VERSION 5.8 ;
BUSBITCHARS "[]" ;
DIVIDERCHAR "/" ;
UNITS
    DATABASE MICRONS 1000 ;
END UNITS

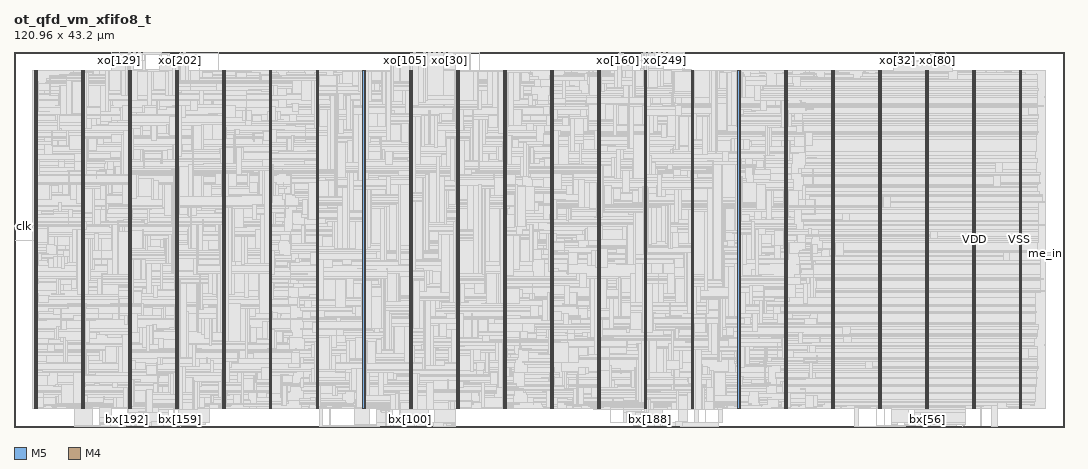
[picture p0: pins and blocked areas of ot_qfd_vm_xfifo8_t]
MACRO ot_qfd_vm_xfifo8_t
  FOREIGN ot_qfd_vm_xfifo8_t 0 0 ;
  CLASS BLOCK ;
  SIZE 120.96 BY 43.2 ;
  PIN bx[0]
    DIRECTION INPUT ;
    USE SIGNAL ;
    PORT
      LAYER M5 ;
        RECT  42.192 0 42.216 0.084 ;
    END
  END bx[0]
  PIN bx[100]
    DIRECTION INPUT ;
    USE SIGNAL ;
    PORT
      LAYER M5 ;
        RECT  45.648 0 45.672 0.084 ;
    END
  END bx[100]
  PIN bx[101]
    DIRECTION INPUT ;
    USE SIGNAL ;
    PORT
      LAYER M5 ;
        RECT  45.744 0 45.768 0.084 ;
    END
  END bx[101]
  PIN bx[102]
    DIRECTION INPUT ;
    USE SIGNAL ;
    PORT
      LAYER M5 ;
        RECT  45.84 0 45.864 0.084 ;
    END
  END bx[102]
  PIN bx[103]
    DIRECTION INPUT ;
    USE SIGNAL ;
    PORT
      LAYER M5 ;
        RECT  45.936 0 45.96 0.084 ;
    END
  END bx[103]
  PIN bx[104]
    DIRECTION INPUT ;
    USE SIGNAL ;
    PORT
      LAYER M5 ;
        RECT  46.032 0 46.056 0.084 ;
    END
  END bx[104]
  PIN bx[105]
    DIRECTION INPUT ;
    USE SIGNAL ;
    PORT
      LAYER M5 ;
        RECT  46.128 0 46.152 0.084 ;
    END
  END bx[105]
  PIN bx[106]
    DIRECTION INPUT ;
    USE SIGNAL ;
    PORT
      LAYER M5 ;
        RECT  46.224 0 46.248 0.084 ;
    END
  END bx[106]
  PIN bx[107]
    DIRECTION INPUT ;
    USE SIGNAL ;
    PORT
      LAYER M5 ;
        RECT  46.32 0 46.344 0.084 ;
    END
  END bx[107]
  PIN bx[108]
    DIRECTION INPUT ;
    USE SIGNAL ;
    PORT
      LAYER M5 ;
        RECT  46.416 0 46.44 0.084 ;
    END
  END bx[108]
  PIN bx[109]
    DIRECTION INPUT ;
    USE SIGNAL ;
    PORT
      LAYER M5 ;
        RECT  46.512 0 46.536 0.084 ;
    END
  END bx[109]
  PIN bx[10]
    DIRECTION INPUT ;
    USE SIGNAL ;
    PORT
      LAYER M5 ;
        RECT  43.152 0 43.176 0.084 ;
    END
  END bx[10]
  PIN bx[110]
    DIRECTION INPUT ;
    USE SIGNAL ;
    PORT
      LAYER M5 ;
        RECT  46.608 0 46.632 0.084 ;
    END
  END bx[110]
  PIN bx[111]
    DIRECTION INPUT ;
    USE SIGNAL ;
    PORT
      LAYER M5 ;
        RECT  46.704 0 46.728 0.084 ;
    END
  END bx[111]
  PIN bx[112]
    DIRECTION INPUT ;
    USE SIGNAL ;
    PORT
      LAYER M5 ;
        RECT  46.8 0 46.824 0.084 ;
    END
  END bx[112]
  PIN bx[113]
    DIRECTION INPUT ;
    USE SIGNAL ;
    PORT
      LAYER M5 ;
        RECT  46.896 0 46.92 0.084 ;
    END
  END bx[113]
  PIN bx[114]
    DIRECTION INPUT ;
    USE SIGNAL ;
    PORT
      LAYER M5 ;
        RECT  46.992 0 47.016 0.084 ;
    END
  END bx[114]
  PIN bx[115]
    DIRECTION INPUT ;
    USE SIGNAL ;
    PORT
      LAYER M5 ;
        RECT  47.088 0 47.112 0.084 ;
    END
  END bx[115]
  PIN bx[116]
    DIRECTION INPUT ;
    USE SIGNAL ;
    PORT
      LAYER M5 ;
        RECT  47.184 0 47.208 0.084 ;
    END
  END bx[116]
  PIN bx[117]
    DIRECTION INPUT ;
    USE SIGNAL ;
    PORT
      LAYER M5 ;
        RECT  47.28 0 47.304 0.084 ;
    END
  END bx[117]
  PIN bx[118]
    DIRECTION INPUT ;
    USE SIGNAL ;
    PORT
      LAYER M5 ;
        RECT  47.376 0 47.4 0.084 ;
    END
  END bx[118]
  PIN bx[119]
    DIRECTION INPUT ;
    USE SIGNAL ;
    PORT
      LAYER M5 ;
        RECT  47.472 0 47.496 0.084 ;
    END
  END bx[119]
  PIN bx[11]
    DIRECTION INPUT ;
    USE SIGNAL ;
    PORT
      LAYER M5 ;
        RECT  43.248 0 43.272 0.084 ;
    END
  END bx[11]
  PIN bx[120]
    DIRECTION INPUT ;
    USE SIGNAL ;
    PORT
      LAYER M5 ;
        RECT  47.568 0 47.592 0.084 ;
    END
  END bx[120]
  PIN bx[121]
    DIRECTION INPUT ;
    USE SIGNAL ;
    PORT
      LAYER M5 ;
        RECT  47.664 0 47.688 0.084 ;
    END
  END bx[121]
  PIN bx[122]
    DIRECTION INPUT ;
    USE SIGNAL ;
    PORT
      LAYER M5 ;
        RECT  47.76 0 47.784 0.084 ;
    END
  END bx[122]
  PIN bx[123]
    DIRECTION INPUT ;
    USE SIGNAL ;
    PORT
      LAYER M5 ;
        RECT  47.856 0 47.88 0.084 ;
    END
  END bx[123]
  PIN bx[124]
    DIRECTION INPUT ;
    USE SIGNAL ;
    PORT
      LAYER M5 ;
        RECT  47.952 0 47.976 0.084 ;
    END
  END bx[124]
  PIN bx[125]
    DIRECTION INPUT ;
    USE SIGNAL ;
    PORT
      LAYER M5 ;
        RECT  48.048 0 48.072 0.084 ;
    END
  END bx[125]
  PIN bx[126]
    DIRECTION INPUT ;
    USE SIGNAL ;
    PORT
      LAYER M5 ;
        RECT  48.144 0 48.168 0.084 ;
    END
  END bx[126]
  PIN bx[127]
    DIRECTION INPUT ;
    USE SIGNAL ;
    PORT
      LAYER M5 ;
        RECT  48.24 0 48.264 0.084 ;
    END
  END bx[127]
  PIN bx[128]
    DIRECTION INPUT ;
    USE SIGNAL ;
    PORT
      LAYER M5 ;
        RECT  16.08 0 16.104 0.084 ;
    END
  END bx[128]
  PIN bx[129]
    DIRECTION INPUT ;
    USE SIGNAL ;
    PORT
      LAYER M5 ;
        RECT  16.176 0 16.2 0.084 ;
    END
  END bx[129]
  PIN bx[12]
    DIRECTION INPUT ;
    USE SIGNAL ;
    PORT
      LAYER M5 ;
        RECT  43.344 0 43.368 0.084 ;
    END
  END bx[12]
  PIN bx[130]
    DIRECTION INPUT ;
    USE SIGNAL ;
    PORT
      LAYER M5 ;
        RECT  16.272 0 16.296 0.084 ;
    END
  END bx[130]
  PIN bx[131]
    DIRECTION INPUT ;
    USE SIGNAL ;
    PORT
      LAYER M5 ;
        RECT  16.368 0 16.392 0.084 ;
    END
  END bx[131]
  PIN bx[132]
    DIRECTION INPUT ;
    USE SIGNAL ;
    PORT
      LAYER M5 ;
        RECT  16.464 0 16.488 0.084 ;
    END
  END bx[132]
  PIN bx[133]
    DIRECTION INPUT ;
    USE SIGNAL ;
    PORT
      LAYER M5 ;
        RECT  16.56 0 16.584 0.084 ;
    END
  END bx[133]
  PIN bx[134]
    DIRECTION INPUT ;
    USE SIGNAL ;
    PORT
      LAYER M5 ;
        RECT  16.656 0 16.68 0.084 ;
    END
  END bx[134]
  PIN bx[135]
    DIRECTION INPUT ;
    USE SIGNAL ;
    PORT
      LAYER M5 ;
        RECT  16.752 0 16.776 0.084 ;
    END
  END bx[135]
  PIN bx[136]
    DIRECTION INPUT ;
    USE SIGNAL ;
    PORT
      LAYER M5 ;
        RECT  16.848 0 16.872 0.084 ;
    END
  END bx[136]
  PIN bx[137]
    DIRECTION INPUT ;
    USE SIGNAL ;
    PORT
      LAYER M5 ;
        RECT  16.944 0 16.968 0.084 ;
    END
  END bx[137]
  PIN bx[138]
    DIRECTION INPUT ;
    USE SIGNAL ;
    PORT
      LAYER M5 ;
        RECT  17.04 0 17.064 0.084 ;
    END
  END bx[138]
  PIN bx[139]
    DIRECTION INPUT ;
    USE SIGNAL ;
    PORT
      LAYER M5 ;
        RECT  17.136 0 17.16 0.084 ;
    END
  END bx[139]
  PIN bx[13]
    DIRECTION INPUT ;
    USE SIGNAL ;
    PORT
      LAYER M5 ;
        RECT  43.44 0 43.464 0.084 ;
    END
  END bx[13]
  PIN bx[140]
    DIRECTION INPUT ;
    USE SIGNAL ;
    PORT
      LAYER M5 ;
        RECT  17.232 0 17.256 0.084 ;
    END
  END bx[140]
  PIN bx[141]
    DIRECTION INPUT ;
    USE SIGNAL ;
    PORT
      LAYER M5 ;
        RECT  17.328 0 17.352 0.084 ;
    END
  END bx[141]
  PIN bx[142]
    DIRECTION INPUT ;
    USE SIGNAL ;
    PORT
      LAYER M5 ;
        RECT  17.424 0 17.448 0.084 ;
    END
  END bx[142]
  PIN bx[143]
    DIRECTION INPUT ;
    USE SIGNAL ;
    PORT
      LAYER M5 ;
        RECT  17.52 0 17.544 0.084 ;
    END
  END bx[143]
  PIN bx[144]
    DIRECTION INPUT ;
    USE SIGNAL ;
    PORT
      LAYER M5 ;
        RECT  17.616 0 17.64 0.084 ;
    END
  END bx[144]
  PIN bx[145]
    DIRECTION INPUT ;
    USE SIGNAL ;
    PORT
      LAYER M5 ;
        RECT  17.712 0 17.736 0.084 ;
    END
  END bx[145]
  PIN bx[146]
    DIRECTION INPUT ;
    USE SIGNAL ;
    PORT
      LAYER M5 ;
        RECT  17.808 0 17.832 0.084 ;
    END
  END bx[146]
  PIN bx[147]
    DIRECTION INPUT ;
    USE SIGNAL ;
    PORT
      LAYER M5 ;
        RECT  17.904 0 17.928 0.084 ;
    END
  END bx[147]
  PIN bx[148]
    DIRECTION INPUT ;
    USE SIGNAL ;
    PORT
      LAYER M5 ;
        RECT  18 0 18.024 0.084 ;
    END
  END bx[148]
  PIN bx[149]
    DIRECTION INPUT ;
    USE SIGNAL ;
    PORT
      LAYER M5 ;
        RECT  18.096 0 18.12 0.084 ;
    END
  END bx[149]
  PIN bx[14]
    DIRECTION INPUT ;
    USE SIGNAL ;
    PORT
      LAYER M5 ;
        RECT  43.536 0 43.56 0.084 ;
    END
  END bx[14]
  PIN bx[150]
    DIRECTION INPUT ;
    USE SIGNAL ;
    PORT
      LAYER M5 ;
        RECT  18.192 0 18.216 0.084 ;
    END
  END bx[150]
  PIN bx[151]
    DIRECTION INPUT ;
    USE SIGNAL ;
    PORT
      LAYER M5 ;
        RECT  18.288 0 18.312 0.084 ;
    END
  END bx[151]
  PIN bx[152]
    DIRECTION INPUT ;
    USE SIGNAL ;
    PORT
      LAYER M5 ;
        RECT  18.384 0 18.408 0.084 ;
    END
  END bx[152]
  PIN bx[153]
    DIRECTION INPUT ;
    USE SIGNAL ;
    PORT
      LAYER M5 ;
        RECT  18.48 0 18.504 0.084 ;
    END
  END bx[153]
  PIN bx[154]
    DIRECTION INPUT ;
    USE SIGNAL ;
    PORT
      LAYER M5 ;
        RECT  18.576 0 18.6 0.084 ;
    END
  END bx[154]
  PIN bx[155]
    DIRECTION INPUT ;
    USE SIGNAL ;
    PORT
      LAYER M5 ;
        RECT  18.672 0 18.696 0.084 ;
    END
  END bx[155]
  PIN bx[156]
    DIRECTION INPUT ;
    USE SIGNAL ;
    PORT
      LAYER M5 ;
        RECT  18.768 0 18.792 0.084 ;
    END
  END bx[156]
  PIN bx[157]
    DIRECTION INPUT ;
    USE SIGNAL ;
    PORT
      LAYER M5 ;
        RECT  18.864 0 18.888 0.084 ;
    END
  END bx[157]
  PIN bx[158]
    DIRECTION INPUT ;
    USE SIGNAL ;
    PORT
      LAYER M5 ;
        RECT  18.96 0 18.984 0.084 ;
    END
  END bx[158]
  PIN bx[159]
    DIRECTION INPUT ;
    USE SIGNAL ;
    PORT
      LAYER M5 ;
        RECT  19.056 0 19.08 0.084 ;
    END
  END bx[159]
  PIN bx[15]
    DIRECTION INPUT ;
    USE SIGNAL ;
    PORT
      LAYER M5 ;
        RECT  43.632 0 43.656 0.084 ;
    END
  END bx[15]
  PIN bx[160]
    DIRECTION INPUT ;
    USE SIGNAL ;
    PORT
      LAYER M5 ;
        RECT  70.608 0 70.632 0.084 ;
    END
  END bx[160]
  PIN bx[161]
    DIRECTION INPUT ;
    USE SIGNAL ;
    PORT
      LAYER M5 ;
        RECT  70.704 0 70.728 0.084 ;
    END
  END bx[161]
  PIN bx[162]
    DIRECTION INPUT ;
    USE SIGNAL ;
    PORT
      LAYER M5 ;
        RECT  70.8 0 70.824 0.084 ;
    END
  END bx[162]
  PIN bx[163]
    DIRECTION INPUT ;
    USE SIGNAL ;
    PORT
      LAYER M5 ;
        RECT  70.896 0 70.92 0.084 ;
    END
  END bx[163]
  PIN bx[164]
    DIRECTION INPUT ;
    USE SIGNAL ;
    PORT
      LAYER M5 ;
        RECT  70.992 0 71.016 0.084 ;
    END
  END bx[164]
  PIN bx[165]
    DIRECTION INPUT ;
    USE SIGNAL ;
    PORT
      LAYER M5 ;
        RECT  71.088 0 71.112 0.084 ;
    END
  END bx[165]
  PIN bx[166]
    DIRECTION INPUT ;
    USE SIGNAL ;
    PORT
      LAYER M5 ;
        RECT  71.184 0 71.208 0.084 ;
    END
  END bx[166]
  PIN bx[167]
    DIRECTION INPUT ;
    USE SIGNAL ;
    PORT
      LAYER M5 ;
        RECT  71.28 0 71.304 0.084 ;
    END
  END bx[167]
  PIN bx[168]
    DIRECTION INPUT ;
    USE SIGNAL ;
    PORT
      LAYER M5 ;
        RECT  71.376 0 71.4 0.084 ;
    END
  END bx[168]
  PIN bx[169]
    DIRECTION INPUT ;
    USE SIGNAL ;
    PORT
      LAYER M5 ;
        RECT  71.472 0 71.496 0.084 ;
    END
  END bx[169]
  PIN bx[16]
    DIRECTION INPUT ;
    USE SIGNAL ;
    PORT
      LAYER M5 ;
        RECT  43.728 0 43.752 0.084 ;
    END
  END bx[16]
  PIN bx[170]
    DIRECTION INPUT ;
    USE SIGNAL ;
    PORT
      LAYER M5 ;
        RECT  71.568 0 71.592 0.084 ;
    END
  END bx[170]
  PIN bx[171]
    DIRECTION INPUT ;
    USE SIGNAL ;
    PORT
      LAYER M5 ;
        RECT  71.664 0 71.688 0.084 ;
    END
  END bx[171]
  PIN bx[172]
    DIRECTION INPUT ;
    USE SIGNAL ;
    PORT
      LAYER M5 ;
        RECT  71.76 0 71.784 0.084 ;
    END
  END bx[172]
  PIN bx[173]
    DIRECTION INPUT ;
    USE SIGNAL ;
    PORT
      LAYER M5 ;
        RECT  71.856 0 71.88 0.084 ;
    END
  END bx[173]
  PIN bx[174]
    DIRECTION INPUT ;
    USE SIGNAL ;
    PORT
      LAYER M5 ;
        RECT  71.952 0 71.976 0.084 ;
    END
  END bx[174]
  PIN bx[175]
    DIRECTION INPUT ;
    USE SIGNAL ;
    PORT
      LAYER M5 ;
        RECT  72.048 0 72.072 0.084 ;
    END
  END bx[175]
  PIN bx[176]
    DIRECTION INPUT ;
    USE SIGNAL ;
    PORT
      LAYER M5 ;
        RECT  72.144 0 72.168 0.084 ;
    END
  END bx[176]
  PIN bx[177]
    DIRECTION INPUT ;
    USE SIGNAL ;
    PORT
      LAYER M5 ;
        RECT  72.24 0 72.264 0.084 ;
    END
  END bx[177]
  PIN bx[178]
    DIRECTION INPUT ;
    USE SIGNAL ;
    PORT
      LAYER M5 ;
        RECT  72.336 0 72.36 0.084 ;
    END
  END bx[178]
  PIN bx[179]
    DIRECTION INPUT ;
    USE SIGNAL ;
    PORT
      LAYER M5 ;
        RECT  72.432 0 72.456 0.084 ;
    END
  END bx[179]
  PIN bx[17]
    DIRECTION INPUT ;
    USE SIGNAL ;
    PORT
      LAYER M5 ;
        RECT  43.824 0 43.848 0.084 ;
    END
  END bx[17]
  PIN bx[180]
    DIRECTION INPUT ;
    USE SIGNAL ;
    PORT
      LAYER M5 ;
        RECT  72.528 0 72.552 0.084 ;
    END
  END bx[180]
  PIN bx[181]
    DIRECTION INPUT ;
    USE SIGNAL ;
    PORT
      LAYER M5 ;
        RECT  72.624 0 72.648 0.084 ;
    END
  END bx[181]
  PIN bx[182]
    DIRECTION INPUT ;
    USE SIGNAL ;
    PORT
      LAYER M5 ;
        RECT  72.72 0 72.744 0.084 ;
    END
  END bx[182]
  PIN bx[183]
    DIRECTION INPUT ;
    USE SIGNAL ;
    PORT
      LAYER M5 ;
        RECT  72.816 0 72.84 0.084 ;
    END
  END bx[183]
  PIN bx[184]
    DIRECTION INPUT ;
    USE SIGNAL ;
    PORT
      LAYER M5 ;
        RECT  72.912 0 72.936 0.084 ;
    END
  END bx[184]
  PIN bx[185]
    DIRECTION INPUT ;
    USE SIGNAL ;
    PORT
      LAYER M5 ;
        RECT  73.008 0 73.032 0.084 ;
    END
  END bx[185]
  PIN bx[186]
    DIRECTION INPUT ;
    USE SIGNAL ;
    PORT
      LAYER M5 ;
        RECT  73.104 0 73.128 0.084 ;
    END
  END bx[186]
  PIN bx[187]
    DIRECTION INPUT ;
    USE SIGNAL ;
    PORT
      LAYER M5 ;
        RECT  73.2 0 73.224 0.084 ;
    END
  END bx[187]
  PIN bx[188]
    DIRECTION INPUT ;
    USE SIGNAL ;
    PORT
      LAYER M5 ;
        RECT  73.296 0 73.32 0.084 ;
    END
  END bx[188]
  PIN bx[189]
    DIRECTION INPUT ;
    USE SIGNAL ;
    PORT
      LAYER M5 ;
        RECT  73.392 0 73.416 0.084 ;
    END
  END bx[189]
  PIN bx[18]
    DIRECTION INPUT ;
    USE SIGNAL ;
    PORT
      LAYER M5 ;
        RECT  43.92 0 43.944 0.084 ;
    END
  END bx[18]
  PIN bx[190]
    DIRECTION INPUT ;
    USE SIGNAL ;
    PORT
      LAYER M5 ;
        RECT  73.488 0 73.512 0.084 ;
    END
  END bx[190]
  PIN bx[191]
    DIRECTION INPUT ;
    USE SIGNAL ;
    PORT
      LAYER M5 ;
        RECT  73.584 0 73.608 0.084 ;
    END
  END bx[191]
  PIN bx[192]
    DIRECTION INPUT ;
    USE SIGNAL ;
    PORT
      LAYER M5 ;
        RECT  13.008 0 13.032 0.084 ;
    END
  END bx[192]
  PIN bx[193]
    DIRECTION INPUT ;
    USE SIGNAL ;
    PORT
      LAYER M5 ;
        RECT  13.104 0 13.128 0.084 ;
    END
  END bx[193]
  PIN bx[194]
    DIRECTION INPUT ;
    USE SIGNAL ;
    PORT
      LAYER M5 ;
        RECT  13.2 0 13.224 0.084 ;
    END
  END bx[194]
  PIN bx[195]
    DIRECTION INPUT ;
    USE SIGNAL ;
    PORT
      LAYER M5 ;
        RECT  13.296 0 13.32 0.084 ;
    END
  END bx[195]
  PIN bx[196]
    DIRECTION INPUT ;
    USE SIGNAL ;
    PORT
      LAYER M5 ;
        RECT  13.392 0 13.416 0.084 ;
    END
  END bx[196]
  PIN bx[197]
    DIRECTION INPUT ;
    USE SIGNAL ;
    PORT
      LAYER M5 ;
        RECT  13.488 0 13.512 0.084 ;
    END
  END bx[197]
  PIN bx[198]
    DIRECTION INPUT ;
    USE SIGNAL ;
    PORT
      LAYER M5 ;
        RECT  13.584 0 13.608 0.084 ;
    END
  END bx[198]
  PIN bx[199]
    DIRECTION INPUT ;
    USE SIGNAL ;
    PORT
      LAYER M5 ;
        RECT  13.68 0 13.704 0.084 ;
    END
  END bx[199]
  PIN bx[19]
    DIRECTION INPUT ;
    USE SIGNAL ;
    PORT
      LAYER M5 ;
        RECT  44.016 0 44.04 0.084 ;
    END
  END bx[19]
  PIN bx[1]
    DIRECTION INPUT ;
    USE SIGNAL ;
    PORT
      LAYER M5 ;
        RECT  42.288 0 42.312 0.084 ;
    END
  END bx[1]
  PIN bx[200]
    DIRECTION INPUT ;
    USE SIGNAL ;
    PORT
      LAYER M5 ;
        RECT  13.776 0 13.8 0.084 ;
    END
  END bx[200]
  PIN bx[201]
    DIRECTION INPUT ;
    USE SIGNAL ;
    PORT
      LAYER M5 ;
        RECT  13.872 0 13.896 0.084 ;
    END
  END bx[201]
  PIN bx[202]
    DIRECTION INPUT ;
    USE SIGNAL ;
    PORT
      LAYER M5 ;
        RECT  13.968 0 13.992 0.084 ;
    END
  END bx[202]
  PIN bx[203]
    DIRECTION INPUT ;
    USE SIGNAL ;
    PORT
      LAYER M5 ;
        RECT  14.064 0 14.088 0.084 ;
    END
  END bx[203]
  PIN bx[204]
    DIRECTION INPUT ;
    USE SIGNAL ;
    PORT
      LAYER M5 ;
        RECT  14.16 0 14.184 0.084 ;
    END
  END bx[204]
  PIN bx[205]
    DIRECTION INPUT ;
    USE SIGNAL ;
    PORT
      LAYER M5 ;
        RECT  14.256 0 14.28 0.084 ;
    END
  END bx[205]
  PIN bx[206]
    DIRECTION INPUT ;
    USE SIGNAL ;
    PORT
      LAYER M5 ;
        RECT  14.352 0 14.376 0.084 ;
    END
  END bx[206]
  PIN bx[207]
    DIRECTION INPUT ;
    USE SIGNAL ;
    PORT
      LAYER M5 ;
        RECT  14.448 0 14.472 0.084 ;
    END
  END bx[207]
  PIN bx[208]
    DIRECTION INPUT ;
    USE SIGNAL ;
    PORT
      LAYER M5 ;
        RECT  14.544 0 14.568 0.084 ;
    END
  END bx[208]
  PIN bx[209]
    DIRECTION INPUT ;
    USE SIGNAL ;
    PORT
      LAYER M5 ;
        RECT  14.64 0 14.664 0.084 ;
    END
  END bx[209]
  PIN bx[20]
    DIRECTION INPUT ;
    USE SIGNAL ;
    PORT
      LAYER M5 ;
        RECT  44.112 0 44.136 0.084 ;
    END
  END bx[20]
  PIN bx[210]
    DIRECTION INPUT ;
    USE SIGNAL ;
    PORT
      LAYER M5 ;
        RECT  14.736 0 14.76 0.084 ;
    END
  END bx[210]
  PIN bx[211]
    DIRECTION INPUT ;
    USE SIGNAL ;
    PORT
      LAYER M5 ;
        RECT  14.832 0 14.856 0.084 ;
    END
  END bx[211]
  PIN bx[212]
    DIRECTION INPUT ;
    USE SIGNAL ;
    PORT
      LAYER M5 ;
        RECT  14.928 0 14.952 0.084 ;
    END
  END bx[212]
  PIN bx[213]
    DIRECTION INPUT ;
    USE SIGNAL ;
    PORT
      LAYER M5 ;
        RECT  15.024 0 15.048 0.084 ;
    END
  END bx[213]
  PIN bx[214]
    DIRECTION INPUT ;
    USE SIGNAL ;
    PORT
      LAYER M5 ;
        RECT  15.12 0 15.144 0.084 ;
    END
  END bx[214]
  PIN bx[215]
    DIRECTION INPUT ;
    USE SIGNAL ;
    PORT
      LAYER M5 ;
        RECT  15.216 0 15.24 0.084 ;
    END
  END bx[215]
  PIN bx[216]
    DIRECTION INPUT ;
    USE SIGNAL ;
    PORT
      LAYER M5 ;
        RECT  15.312 0 15.336 0.084 ;
    END
  END bx[216]
  PIN bx[217]
    DIRECTION INPUT ;
    USE SIGNAL ;
    PORT
      LAYER M5 ;
        RECT  15.408 0 15.432 0.084 ;
    END
  END bx[217]
  PIN bx[218]
    DIRECTION INPUT ;
    USE SIGNAL ;
    PORT
      LAYER M5 ;
        RECT  15.504 0 15.528 0.084 ;
    END
  END bx[218]
  PIN bx[219]
    DIRECTION INPUT ;
    USE SIGNAL ;
    PORT
      LAYER M5 ;
        RECT  15.6 0 15.624 0.084 ;
    END
  END bx[219]
  PIN bx[21]
    DIRECTION INPUT ;
    USE SIGNAL ;
    PORT
      LAYER M5 ;
        RECT  44.208 0 44.232 0.084 ;
    END
  END bx[21]
  PIN bx[220]
    DIRECTION INPUT ;
    USE SIGNAL ;
    PORT
      LAYER M5 ;
        RECT  15.696 0 15.72 0.084 ;
    END
  END bx[220]
  PIN bx[221]
    DIRECTION INPUT ;
    USE SIGNAL ;
    PORT
      LAYER M5 ;
        RECT  15.792 0 15.816 0.084 ;
    END
  END bx[221]
  PIN bx[222]
    DIRECTION INPUT ;
    USE SIGNAL ;
    PORT
      LAYER M5 ;
        RECT  15.888 0 15.912 0.084 ;
    END
  END bx[222]
  PIN bx[223]
    DIRECTION INPUT ;
    USE SIGNAL ;
    PORT
      LAYER M5 ;
        RECT  15.984 0 16.008 0.084 ;
    END
  END bx[223]
  PIN bx[224]
    DIRECTION INPUT ;
    USE SIGNAL ;
    PORT
      LAYER M5 ;
        RECT  73.68 0 73.704 0.084 ;
    END
  END bx[224]
  PIN bx[225]
    DIRECTION INPUT ;
    USE SIGNAL ;
    PORT
      LAYER M5 ;
        RECT  73.776 0 73.8 0.084 ;
    END
  END bx[225]
  PIN bx[226]
    DIRECTION INPUT ;
    USE SIGNAL ;
    PORT
      LAYER M5 ;
        RECT  73.872 0 73.896 0.084 ;
    END
  END bx[226]
  PIN bx[227]
    DIRECTION INPUT ;
    USE SIGNAL ;
    PORT
      LAYER M5 ;
        RECT  73.968 0 73.992 0.084 ;
    END
  END bx[227]
  PIN bx[228]
    DIRECTION INPUT ;
    USE SIGNAL ;
    PORT
      LAYER M5 ;
        RECT  74.064 0 74.088 0.084 ;
    END
  END bx[228]
  PIN bx[229]
    DIRECTION INPUT ;
    USE SIGNAL ;
    PORT
      LAYER M5 ;
        RECT  74.16 0 74.184 0.084 ;
    END
  END bx[229]
  PIN bx[22]
    DIRECTION INPUT ;
    USE SIGNAL ;
    PORT
      LAYER M5 ;
        RECT  44.304 0 44.328 0.084 ;
    END
  END bx[22]
  PIN bx[230]
    DIRECTION INPUT ;
    USE SIGNAL ;
    PORT
      LAYER M5 ;
        RECT  74.256 0 74.28 0.084 ;
    END
  END bx[230]
  PIN bx[231]
    DIRECTION INPUT ;
    USE SIGNAL ;
    PORT
      LAYER M5 ;
        RECT  74.352 0 74.376 0.084 ;
    END
  END bx[231]
  PIN bx[232]
    DIRECTION INPUT ;
    USE SIGNAL ;
    PORT
      LAYER M5 ;
        RECT  74.448 0 74.472 0.084 ;
    END
  END bx[232]
  PIN bx[233]
    DIRECTION INPUT ;
    USE SIGNAL ;
    PORT
      LAYER M5 ;
        RECT  74.544 0 74.568 0.084 ;
    END
  END bx[233]
  PIN bx[234]
    DIRECTION INPUT ;
    USE SIGNAL ;
    PORT
      LAYER M5 ;
        RECT  74.64 0 74.664 0.084 ;
    END
  END bx[234]
  PIN bx[235]
    DIRECTION INPUT ;
    USE SIGNAL ;
    PORT
      LAYER M5 ;
        RECT  74.736 0 74.76 0.084 ;
    END
  END bx[235]
  PIN bx[236]
    DIRECTION INPUT ;
    USE SIGNAL ;
    PORT
      LAYER M5 ;
        RECT  74.832 0 74.856 0.084 ;
    END
  END bx[236]
  PIN bx[237]
    DIRECTION INPUT ;
    USE SIGNAL ;
    PORT
      LAYER M5 ;
        RECT  74.928 0 74.952 0.084 ;
    END
  END bx[237]
  PIN bx[238]
    DIRECTION INPUT ;
    USE SIGNAL ;
    PORT
      LAYER M5 ;
        RECT  75.024 0 75.048 0.084 ;
    END
  END bx[238]
  PIN bx[239]
    DIRECTION INPUT ;
    USE SIGNAL ;
    PORT
      LAYER M5 ;
        RECT  75.12 0 75.144 0.084 ;
    END
  END bx[239]
  PIN bx[23]
    DIRECTION INPUT ;
    USE SIGNAL ;
    PORT
      LAYER M5 ;
        RECT  44.4 0 44.424 0.084 ;
    END
  END bx[23]
  PIN bx[240]
    DIRECTION INPUT ;
    USE SIGNAL ;
    PORT
      LAYER M5 ;
        RECT  75.216 0 75.24 0.084 ;
    END
  END bx[240]
  PIN bx[241]
    DIRECTION INPUT ;
    USE SIGNAL ;
    PORT
      LAYER M5 ;
        RECT  75.312 0 75.336 0.084 ;
    END
  END bx[241]
  PIN bx[242]
    DIRECTION INPUT ;
    USE SIGNAL ;
    PORT
      LAYER M5 ;
        RECT  75.408 0 75.432 0.084 ;
    END
  END bx[242]
  PIN bx[243]
    DIRECTION INPUT ;
    USE SIGNAL ;
    PORT
      LAYER M5 ;
        RECT  75.504 0 75.528 0.084 ;
    END
  END bx[243]
  PIN bx[244]
    DIRECTION INPUT ;
    USE SIGNAL ;
    PORT
      LAYER M5 ;
        RECT  75.6 0 75.624 0.084 ;
    END
  END bx[244]
  PIN bx[245]
    DIRECTION INPUT ;
    USE SIGNAL ;
    PORT
      LAYER M5 ;
        RECT  75.696 0 75.72 0.084 ;
    END
  END bx[245]
  PIN bx[246]
    DIRECTION INPUT ;
    USE SIGNAL ;
    PORT
      LAYER M5 ;
        RECT  75.792 0 75.816 0.084 ;
    END
  END bx[246]
  PIN bx[247]
    DIRECTION INPUT ;
    USE SIGNAL ;
    PORT
      LAYER M5 ;
        RECT  75.888 0 75.912 0.084 ;
    END
  END bx[247]
  PIN bx[248]
    DIRECTION INPUT ;
    USE SIGNAL ;
    PORT
      LAYER M5 ;
        RECT  75.984 0 76.008 0.084 ;
    END
  END bx[248]
  PIN bx[249]
    DIRECTION INPUT ;
    USE SIGNAL ;
    PORT
      LAYER M5 ;
        RECT  76.08 0 76.104 0.084 ;
    END
  END bx[249]
  PIN bx[24]
    DIRECTION INPUT ;
    USE SIGNAL ;
    PORT
      LAYER M5 ;
        RECT  44.496 0 44.52 0.084 ;
    END
  END bx[24]
  PIN bx[250]
    DIRECTION INPUT ;
    USE SIGNAL ;
    PORT
      LAYER M5 ;
        RECT  76.176 0 76.2 0.084 ;
    END
  END bx[250]
  PIN bx[251]
    DIRECTION INPUT ;
    USE SIGNAL ;
    PORT
      LAYER M5 ;
        RECT  76.272 0 76.296 0.084 ;
    END
  END bx[251]
  PIN bx[252]
    DIRECTION INPUT ;
    USE SIGNAL ;
    PORT
      LAYER M5 ;
        RECT  76.368 0 76.392 0.084 ;
    END
  END bx[252]
  PIN bx[253]
    DIRECTION INPUT ;
    USE SIGNAL ;
    PORT
      LAYER M5 ;
        RECT  76.464 0 76.488 0.084 ;
    END
  END bx[253]
  PIN bx[254]
    DIRECTION INPUT ;
    USE SIGNAL ;
    PORT
      LAYER M5 ;
        RECT  76.56 0 76.584 0.084 ;
    END
  END bx[254]
  PIN bx[255]
    DIRECTION INPUT ;
    USE SIGNAL ;
    PORT
      LAYER M5 ;
        RECT  76.656 0 76.68 0.084 ;
    END
  END bx[255]
  PIN bx[25]
    DIRECTION INPUT ;
    USE SIGNAL ;
    PORT
      LAYER M5 ;
        RECT  44.592 0 44.616 0.084 ;
    END
  END bx[25]
  PIN bx[26]
    DIRECTION INPUT ;
    USE SIGNAL ;
    PORT
      LAYER M5 ;
        RECT  44.688 0 44.712 0.084 ;
    END
  END bx[26]
  PIN bx[27]
    DIRECTION INPUT ;
    USE SIGNAL ;
    PORT
      LAYER M5 ;
        RECT  44.784 0 44.808 0.084 ;
    END
  END bx[27]
  PIN bx[28]
    DIRECTION INPUT ;
    USE SIGNAL ;
    PORT
      LAYER M5 ;
        RECT  44.88 0 44.904 0.084 ;
    END
  END bx[28]
  PIN bx[29]
    DIRECTION INPUT ;
    USE SIGNAL ;
    PORT
      LAYER M5 ;
        RECT  44.976 0 45 0.084 ;
    END
  END bx[29]
  PIN bx[2]
    DIRECTION INPUT ;
    USE SIGNAL ;
    PORT
      LAYER M5 ;
        RECT  42.384 0 42.408 0.084 ;
    END
  END bx[2]
  PIN bx[30]
    DIRECTION INPUT ;
    USE SIGNAL ;
    PORT
      LAYER M5 ;
        RECT  45.072 0 45.096 0.084 ;
    END
  END bx[30]
  PIN bx[31]
    DIRECTION INPUT ;
    USE SIGNAL ;
    PORT
      LAYER M5 ;
        RECT  45.168 0 45.192 0.084 ;
    END
  END bx[31]
  PIN bx[32]
    DIRECTION INPUT ;
    USE SIGNAL ;
    PORT
      LAYER M5 ;
        RECT  102.864 0 102.888 0.084 ;
    END
  END bx[32]
  PIN bx[33]
    DIRECTION INPUT ;
    USE SIGNAL ;
    PORT
      LAYER M5 ;
        RECT  102.96 0 102.984 0.084 ;
    END
  END bx[33]
  PIN bx[34]
    DIRECTION INPUT ;
    USE SIGNAL ;
    PORT
      LAYER M5 ;
        RECT  103.056 0 103.08 0.084 ;
    END
  END bx[34]
  PIN bx[35]
    DIRECTION INPUT ;
    USE SIGNAL ;
    PORT
      LAYER M5 ;
        RECT  103.152 0 103.176 0.084 ;
    END
  END bx[35]
  PIN bx[36]
    DIRECTION INPUT ;
    USE SIGNAL ;
    PORT
      LAYER M5 ;
        RECT  103.248 0 103.272 0.084 ;
    END
  END bx[36]
  PIN bx[37]
    DIRECTION INPUT ;
    USE SIGNAL ;
    PORT
      LAYER M5 ;
        RECT  103.344 0 103.368 0.084 ;
    END
  END bx[37]
  PIN bx[38]
    DIRECTION INPUT ;
    USE SIGNAL ;
    PORT
      LAYER M5 ;
        RECT  103.44 0 103.464 0.084 ;
    END
  END bx[38]
  PIN bx[39]
    DIRECTION INPUT ;
    USE SIGNAL ;
    PORT
      LAYER M5 ;
        RECT  103.536 0 103.56 0.084 ;
    END
  END bx[39]
  PIN bx[3]
    DIRECTION INPUT ;
    USE SIGNAL ;
    PORT
      LAYER M5 ;
        RECT  42.48 0 42.504 0.084 ;
    END
  END bx[3]
  PIN bx[40]
    DIRECTION INPUT ;
    USE SIGNAL ;
    PORT
      LAYER M5 ;
        RECT  103.632 0 103.656 0.084 ;
    END
  END bx[40]
  PIN bx[41]
    DIRECTION INPUT ;
    USE SIGNAL ;
    PORT
      LAYER M5 ;
        RECT  103.728 0 103.752 0.084 ;
    END
  END bx[41]
  PIN bx[42]
    DIRECTION INPUT ;
    USE SIGNAL ;
    PORT
      LAYER M5 ;
        RECT  103.824 0 103.848 0.084 ;
    END
  END bx[42]
  PIN bx[43]
    DIRECTION INPUT ;
    USE SIGNAL ;
    PORT
      LAYER M5 ;
        RECT  103.92 0 103.944 0.084 ;
    END
  END bx[43]
  PIN bx[44]
    DIRECTION INPUT ;
    USE SIGNAL ;
    PORT
      LAYER M5 ;
        RECT  104.016 0 104.04 0.084 ;
    END
  END bx[44]
  PIN bx[45]
    DIRECTION INPUT ;
    USE SIGNAL ;
    PORT
      LAYER M5 ;
        RECT  104.112 0 104.136 0.084 ;
    END
  END bx[45]
  PIN bx[46]
    DIRECTION INPUT ;
    USE SIGNAL ;
    PORT
      LAYER M5 ;
        RECT  104.208 0 104.232 0.084 ;
    END
  END bx[46]
  PIN bx[47]
    DIRECTION INPUT ;
    USE SIGNAL ;
    PORT
      LAYER M5 ;
        RECT  104.304 0 104.328 0.084 ;
    END
  END bx[47]
  PIN bx[48]
    DIRECTION INPUT ;
    USE SIGNAL ;
    PORT
      LAYER M5 ;
        RECT  104.4 0 104.424 0.084 ;
    END
  END bx[48]
  PIN bx[49]
    DIRECTION INPUT ;
    USE SIGNAL ;
    PORT
      LAYER M5 ;
        RECT  104.496 0 104.52 0.084 ;
    END
  END bx[49]
  PIN bx[4]
    DIRECTION INPUT ;
    USE SIGNAL ;
    PORT
      LAYER M5 ;
        RECT  42.576 0 42.6 0.084 ;
    END
  END bx[4]
  PIN bx[50]
    DIRECTION INPUT ;
    USE SIGNAL ;
    PORT
      LAYER M5 ;
        RECT  104.592 0 104.616 0.084 ;
    END
  END bx[50]
  PIN bx[51]
    DIRECTION INPUT ;
    USE SIGNAL ;
    PORT
      LAYER M5 ;
        RECT  104.688 0 104.712 0.084 ;
    END
  END bx[51]
  PIN bx[52]
    DIRECTION INPUT ;
    USE SIGNAL ;
    PORT
      LAYER M5 ;
        RECT  104.784 0 104.808 0.084 ;
    END
  END bx[52]
  PIN bx[53]
    DIRECTION INPUT ;
    USE SIGNAL ;
    PORT
      LAYER M5 ;
        RECT  104.88 0 104.904 0.084 ;
    END
  END bx[53]
  PIN bx[54]
    DIRECTION INPUT ;
    USE SIGNAL ;
    PORT
      LAYER M5 ;
        RECT  104.976 0 105 0.084 ;
    END
  END bx[54]
  PIN bx[55]
    DIRECTION INPUT ;
    USE SIGNAL ;
    PORT
      LAYER M5 ;
        RECT  105.072 0 105.096 0.084 ;
    END
  END bx[55]
  PIN bx[56]
    DIRECTION INPUT ;
    USE SIGNAL ;
    PORT
      LAYER M5 ;
        RECT  105.168 0 105.192 0.084 ;
    END
  END bx[56]
  PIN bx[57]
    DIRECTION INPUT ;
    USE SIGNAL ;
    PORT
      LAYER M5 ;
        RECT  105.264 0 105.288 0.084 ;
    END
  END bx[57]
  PIN bx[58]
    DIRECTION INPUT ;
    USE SIGNAL ;
    PORT
      LAYER M5 ;
        RECT  105.36 0 105.384 0.084 ;
    END
  END bx[58]
  PIN bx[59]
    DIRECTION INPUT ;
    USE SIGNAL ;
    PORT
      LAYER M5 ;
        RECT  105.456 0 105.48 0.084 ;
    END
  END bx[59]
  PIN bx[5]
    DIRECTION INPUT ;
    USE SIGNAL ;
    PORT
      LAYER M5 ;
        RECT  42.672 0 42.696 0.084 ;
    END
  END bx[5]
  PIN bx[60]
    DIRECTION INPUT ;
    USE SIGNAL ;
    PORT
      LAYER M5 ;
        RECT  105.552 0 105.576 0.084 ;
    END
  END bx[60]
  PIN bx[61]
    DIRECTION INPUT ;
    USE SIGNAL ;
    PORT
      LAYER M5 ;
        RECT  105.648 0 105.672 0.084 ;
    END
  END bx[61]
  PIN bx[62]
    DIRECTION INPUT ;
    USE SIGNAL ;
    PORT
      LAYER M5 ;
        RECT  105.744 0 105.768 0.084 ;
    END
  END bx[62]
  PIN bx[63]
    DIRECTION INPUT ;
    USE SIGNAL ;
    PORT
      LAYER M5 ;
        RECT  105.84 0 105.864 0.084 ;
    END
  END bx[63]
  PIN bx[64]
    DIRECTION INPUT ;
    USE SIGNAL ;
    PORT
      LAYER M5 ;
        RECT  105.936 0 105.96 0.084 ;
    END
  END bx[64]
  PIN bx[65]
    DIRECTION INPUT ;
    USE SIGNAL ;
    PORT
      LAYER M5 ;
        RECT  106.032 0 106.056 0.084 ;
    END
  END bx[65]
  PIN bx[66]
    DIRECTION INPUT ;
    USE SIGNAL ;
    PORT
      LAYER M5 ;
        RECT  106.128 0 106.152 0.084 ;
    END
  END bx[66]
  PIN bx[67]
    DIRECTION INPUT ;
    USE SIGNAL ;
    PORT
      LAYER M5 ;
        RECT  106.224 0 106.248 0.084 ;
    END
  END bx[67]
  PIN bx[68]
    DIRECTION INPUT ;
    USE SIGNAL ;
    PORT
      LAYER M5 ;
        RECT  106.32 0 106.344 0.084 ;
    END
  END bx[68]
  PIN bx[69]
    DIRECTION INPUT ;
    USE SIGNAL ;
    PORT
      LAYER M5 ;
        RECT  106.416 0 106.44 0.084 ;
    END
  END bx[69]
  PIN bx[6]
    DIRECTION INPUT ;
    USE SIGNAL ;
    PORT
      LAYER M5 ;
        RECT  42.768 0 42.792 0.084 ;
    END
  END bx[6]
  PIN bx[70]
    DIRECTION INPUT ;
    USE SIGNAL ;
    PORT
      LAYER M5 ;
        RECT  106.512 0 106.536 0.084 ;
    END
  END bx[70]
  PIN bx[71]
    DIRECTION INPUT ;
    USE SIGNAL ;
    PORT
      LAYER M5 ;
        RECT  106.608 0 106.632 0.084 ;
    END
  END bx[71]
  PIN bx[72]
    DIRECTION INPUT ;
    USE SIGNAL ;
    PORT
      LAYER M5 ;
        RECT  106.704 0 106.728 0.084 ;
    END
  END bx[72]
  PIN bx[73]
    DIRECTION INPUT ;
    USE SIGNAL ;
    PORT
      LAYER M5 ;
        RECT  106.8 0 106.824 0.084 ;
    END
  END bx[73]
  PIN bx[74]
    DIRECTION INPUT ;
    USE SIGNAL ;
    PORT
      LAYER M5 ;
        RECT  106.896 0 106.92 0.084 ;
    END
  END bx[74]
  PIN bx[75]
    DIRECTION INPUT ;
    USE SIGNAL ;
    PORT
      LAYER M5 ;
        RECT  106.992 0 107.016 0.084 ;
    END
  END bx[75]
  PIN bx[76]
    DIRECTION INPUT ;
    USE SIGNAL ;
    PORT
      LAYER M5 ;
        RECT  107.088 0 107.112 0.084 ;
    END
  END bx[76]
  PIN bx[77]
    DIRECTION INPUT ;
    USE SIGNAL ;
    PORT
      LAYER M5 ;
        RECT  107.184 0 107.208 0.084 ;
    END
  END bx[77]
  PIN bx[78]
    DIRECTION INPUT ;
    USE SIGNAL ;
    PORT
      LAYER M5 ;
        RECT  107.28 0 107.304 0.084 ;
    END
  END bx[78]
  PIN bx[79]
    DIRECTION INPUT ;
    USE SIGNAL ;
    PORT
      LAYER M5 ;
        RECT  107.376 0 107.4 0.084 ;
    END
  END bx[79]
  PIN bx[7]
    DIRECTION INPUT ;
    USE SIGNAL ;
    PORT
      LAYER M5 ;
        RECT  42.864 0 42.888 0.084 ;
    END
  END bx[7]
  PIN bx[80]
    DIRECTION INPUT ;
    USE SIGNAL ;
    PORT
      LAYER M5 ;
        RECT  107.472 0 107.496 0.084 ;
    END
  END bx[80]
  PIN bx[81]
    DIRECTION INPUT ;
    USE SIGNAL ;
    PORT
      LAYER M5 ;
        RECT  107.568 0 107.592 0.084 ;
    END
  END bx[81]
  PIN bx[82]
    DIRECTION INPUT ;
    USE SIGNAL ;
    PORT
      LAYER M5 ;
        RECT  107.664 0 107.688 0.084 ;
    END
  END bx[82]
  PIN bx[83]
    DIRECTION INPUT ;
    USE SIGNAL ;
    PORT
      LAYER M5 ;
        RECT  107.76 0 107.784 0.084 ;
    END
  END bx[83]
  PIN bx[84]
    DIRECTION INPUT ;
    USE SIGNAL ;
    PORT
      LAYER M5 ;
        RECT  107.856 0 107.88 0.084 ;
    END
  END bx[84]
  PIN bx[85]
    DIRECTION INPUT ;
    USE SIGNAL ;
    PORT
      LAYER M5 ;
        RECT  107.952 0 107.976 0.084 ;
    END
  END bx[85]
  PIN bx[86]
    DIRECTION INPUT ;
    USE SIGNAL ;
    PORT
      LAYER M5 ;
        RECT  108.048 0 108.072 0.084 ;
    END
  END bx[86]
  PIN bx[87]
    DIRECTION INPUT ;
    USE SIGNAL ;
    PORT
      LAYER M5 ;
        RECT  108.144 0 108.168 0.084 ;
    END
  END bx[87]
  PIN bx[88]
    DIRECTION INPUT ;
    USE SIGNAL ;
    PORT
      LAYER M5 ;
        RECT  108.24 0 108.264 0.084 ;
    END
  END bx[88]
  PIN bx[89]
    DIRECTION INPUT ;
    USE SIGNAL ;
    PORT
      LAYER M5 ;
        RECT  108.336 0 108.36 0.084 ;
    END
  END bx[89]
  PIN bx[8]
    DIRECTION INPUT ;
    USE SIGNAL ;
    PORT
      LAYER M5 ;
        RECT  42.96 0 42.984 0.084 ;
    END
  END bx[8]
  PIN bx[90]
    DIRECTION INPUT ;
    USE SIGNAL ;
    PORT
      LAYER M5 ;
        RECT  108.432 0 108.456 0.084 ;
    END
  END bx[90]
  PIN bx[91]
    DIRECTION INPUT ;
    USE SIGNAL ;
    PORT
      LAYER M5 ;
        RECT  108.528 0 108.552 0.084 ;
    END
  END bx[91]
  PIN bx[92]
    DIRECTION INPUT ;
    USE SIGNAL ;
    PORT
      LAYER M5 ;
        RECT  108.624 0 108.648 0.084 ;
    END
  END bx[92]
  PIN bx[93]
    DIRECTION INPUT ;
    USE SIGNAL ;
    PORT
      LAYER M5 ;
        RECT  108.72 0 108.744 0.084 ;
    END
  END bx[93]
  PIN bx[94]
    DIRECTION INPUT ;
    USE SIGNAL ;
    PORT
      LAYER M5 ;
        RECT  108.816 0 108.84 0.084 ;
    END
  END bx[94]
  PIN bx[95]
    DIRECTION INPUT ;
    USE SIGNAL ;
    PORT
      LAYER M5 ;
        RECT  108.912 0 108.936 0.084 ;
    END
  END bx[95]
  PIN bx[96]
    DIRECTION INPUT ;
    USE SIGNAL ;
    PORT
      LAYER M5 ;
        RECT  45.264 0 45.288 0.084 ;
    END
  END bx[96]
  PIN bx[97]
    DIRECTION INPUT ;
    USE SIGNAL ;
    PORT
      LAYER M5 ;
        RECT  45.36 0 45.384 0.084 ;
    END
  END bx[97]
  PIN bx[98]
    DIRECTION INPUT ;
    USE SIGNAL ;
    PORT
      LAYER M5 ;
        RECT  45.456 0 45.48 0.084 ;
    END
  END bx[98]
  PIN bx[99]
    DIRECTION INPUT ;
    USE SIGNAL ;
    PORT
      LAYER M5 ;
        RECT  45.552 0 45.576 0.084 ;
    END
  END bx[99]
  PIN bx[9]
    DIRECTION INPUT ;
    USE SIGNAL ;
    PORT
      LAYER M5 ;
        RECT  43.056 0 43.08 0.084 ;
    END
  END bx[9]
  PIN clk
    DIRECTION INPUT ;
    USE SIGNAL ;
    PORT
      LAYER M4 ;
        RECT  0 23.088 0.084 23.112 ;
    END
  END clk
  PIN me_in
    DIRECTION INPUT ;
    USE SIGNAL ;
    PORT
      LAYER M4 ;
        RECT  120.876 19.92 120.96 19.944 ;
    END
  END me_in
  PIN pgw[0]
    DIRECTION INPUT ;
    USE SIGNAL ;
    PORT
      LAYER M4 ;
        RECT  120.876 20.016 120.96 20.04 ;
    END
  END pgw[0]
  PIN rtg[0]
    DIRECTION INPUT ;
    USE SIGNAL ;
    PORT
      LAYER M4 ;
        RECT  0 23.184 0.084 23.208 ;
    END
  END rtg[0]
  PIN xg[0]
    DIRECTION INPUT ;
    USE SIGNAL ;
    PORT
      LAYER M4 ;
        RECT  120.876 20.112 120.96 20.136 ;
    END
  END xg[0]
  PIN xo[0]
    DIRECTION OUTPUT ;
    USE SIGNAL ;
    PORT
      LAYER M5 ;
        RECT  47.28 43.116 47.304 43.2 ;
    END
  END xo[0]
  PIN xo[100]
    DIRECTION OUTPUT ;
    USE SIGNAL ;
    PORT
      LAYER M5 ;
        RECT  44.592 43.116 44.616 43.2 ;
    END
  END xo[100]
  PIN xo[101]
    DIRECTION OUTPUT ;
    USE SIGNAL ;
    PORT
      LAYER M5 ;
        RECT  44.688 43.116 44.712 43.2 ;
    END
  END xo[101]
  PIN xo[102]
    DIRECTION OUTPUT ;
    USE SIGNAL ;
    PORT
      LAYER M5 ;
        RECT  44.784 43.116 44.808 43.2 ;
    END
  END xo[102]
  PIN xo[103]
    DIRECTION OUTPUT ;
    USE SIGNAL ;
    PORT
      LAYER M5 ;
        RECT  44.88 43.116 44.904 43.2 ;
    END
  END xo[103]
  PIN xo[104]
    DIRECTION OUTPUT ;
    USE SIGNAL ;
    PORT
      LAYER M5 ;
        RECT  44.976 43.116 45 43.2 ;
    END
  END xo[104]
  PIN xo[105]
    DIRECTION OUTPUT ;
    USE SIGNAL ;
    PORT
      LAYER M5 ;
        RECT  45.072 43.116 45.096 43.2 ;
    END
  END xo[105]
  PIN xo[106]
    DIRECTION OUTPUT ;
    USE SIGNAL ;
    PORT
      LAYER M5 ;
        RECT  45.168 43.116 45.192 43.2 ;
    END
  END xo[106]
  PIN xo[107]
    DIRECTION OUTPUT ;
    USE SIGNAL ;
    PORT
      LAYER M5 ;
        RECT  45.264 43.116 45.288 43.2 ;
    END
  END xo[107]
  PIN xo[108]
    DIRECTION OUTPUT ;
    USE SIGNAL ;
    PORT
      LAYER M5 ;
        RECT  45.36 43.116 45.384 43.2 ;
    END
  END xo[108]
  PIN xo[109]
    DIRECTION OUTPUT ;
    USE SIGNAL ;
    PORT
      LAYER M5 ;
        RECT  45.456 43.116 45.48 43.2 ;
    END
  END xo[109]
  PIN xo[10]
    DIRECTION OUTPUT ;
    USE SIGNAL ;
    PORT
      LAYER M5 ;
        RECT  48.24 43.116 48.264 43.2 ;
    END
  END xo[10]
  PIN xo[110]
    DIRECTION OUTPUT ;
    USE SIGNAL ;
    PORT
      LAYER M5 ;
        RECT  45.552 43.116 45.576 43.2 ;
    END
  END xo[110]
  PIN xo[111]
    DIRECTION OUTPUT ;
    USE SIGNAL ;
    PORT
      LAYER M5 ;
        RECT  45.648 43.116 45.672 43.2 ;
    END
  END xo[111]
  PIN xo[112]
    DIRECTION OUTPUT ;
    USE SIGNAL ;
    PORT
      LAYER M5 ;
        RECT  45.744 43.116 45.768 43.2 ;
    END
  END xo[112]
  PIN xo[113]
    DIRECTION OUTPUT ;
    USE SIGNAL ;
    PORT
      LAYER M5 ;
        RECT  45.84 43.116 45.864 43.2 ;
    END
  END xo[113]
  PIN xo[114]
    DIRECTION OUTPUT ;
    USE SIGNAL ;
    PORT
      LAYER M5 ;
        RECT  45.936 43.116 45.96 43.2 ;
    END
  END xo[114]
  PIN xo[115]
    DIRECTION OUTPUT ;
    USE SIGNAL ;
    PORT
      LAYER M5 ;
        RECT  46.032 43.116 46.056 43.2 ;
    END
  END xo[115]
  PIN xo[116]
    DIRECTION OUTPUT ;
    USE SIGNAL ;
    PORT
      LAYER M5 ;
        RECT  46.128 43.116 46.152 43.2 ;
    END
  END xo[116]
  PIN xo[117]
    DIRECTION OUTPUT ;
    USE SIGNAL ;
    PORT
      LAYER M5 ;
        RECT  46.224 43.116 46.248 43.2 ;
    END
  END xo[117]
  PIN xo[118]
    DIRECTION OUTPUT ;
    USE SIGNAL ;
    PORT
      LAYER M5 ;
        RECT  46.32 43.116 46.344 43.2 ;
    END
  END xo[118]
  PIN xo[119]
    DIRECTION OUTPUT ;
    USE SIGNAL ;
    PORT
      LAYER M5 ;
        RECT  46.416 43.116 46.44 43.2 ;
    END
  END xo[119]
  PIN xo[11]
    DIRECTION OUTPUT ;
    USE SIGNAL ;
    PORT
      LAYER M5 ;
        RECT  48.336 43.116 48.36 43.2 ;
    END
  END xo[11]
  PIN xo[120]
    DIRECTION OUTPUT ;
    USE SIGNAL ;
    PORT
      LAYER M5 ;
        RECT  46.512 43.116 46.536 43.2 ;
    END
  END xo[120]
  PIN xo[121]
    DIRECTION OUTPUT ;
    USE SIGNAL ;
    PORT
      LAYER M5 ;
        RECT  46.608 43.116 46.632 43.2 ;
    END
  END xo[121]
  PIN xo[122]
    DIRECTION OUTPUT ;
    USE SIGNAL ;
    PORT
      LAYER M5 ;
        RECT  46.704 43.116 46.728 43.2 ;
    END
  END xo[122]
  PIN xo[123]
    DIRECTION OUTPUT ;
    USE SIGNAL ;
    PORT
      LAYER M5 ;
        RECT  46.8 43.116 46.824 43.2 ;
    END
  END xo[123]
  PIN xo[124]
    DIRECTION OUTPUT ;
    USE SIGNAL ;
    PORT
      LAYER M5 ;
        RECT  46.896 43.116 46.92 43.2 ;
    END
  END xo[124]
  PIN xo[125]
    DIRECTION OUTPUT ;
    USE SIGNAL ;
    PORT
      LAYER M5 ;
        RECT  46.992 43.116 47.016 43.2 ;
    END
  END xo[125]
  PIN xo[126]
    DIRECTION OUTPUT ;
    USE SIGNAL ;
    PORT
      LAYER M5 ;
        RECT  47.088 43.116 47.112 43.2 ;
    END
  END xo[126]
  PIN xo[127]
    DIRECTION OUTPUT ;
    USE SIGNAL ;
    PORT
      LAYER M5 ;
        RECT  47.184 43.116 47.208 43.2 ;
    END
  END xo[127]
  PIN xo[128]
    DIRECTION OUTPUT ;
    USE SIGNAL ;
    PORT
      LAYER M5 ;
        RECT  11.952 43.116 11.976 43.2 ;
    END
  END xo[128]
  PIN xo[129]
    DIRECTION OUTPUT ;
    USE SIGNAL ;
    PORT
      LAYER M5 ;
        RECT  12.048 43.116 12.072 43.2 ;
    END
  END xo[129]
  PIN xo[12]
    DIRECTION OUTPUT ;
    USE SIGNAL ;
    PORT
      LAYER M5 ;
        RECT  48.432 43.116 48.456 43.2 ;
    END
  END xo[12]
  PIN xo[130]
    DIRECTION OUTPUT ;
    USE SIGNAL ;
    PORT
      LAYER M5 ;
        RECT  12.144 43.116 12.168 43.2 ;
    END
  END xo[130]
  PIN xo[131]
    DIRECTION OUTPUT ;
    USE SIGNAL ;
    PORT
      LAYER M5 ;
        RECT  12.24 43.116 12.264 43.2 ;
    END
  END xo[131]
  PIN xo[132]
    DIRECTION OUTPUT ;
    USE SIGNAL ;
    PORT
      LAYER M5 ;
        RECT  12.336 43.116 12.36 43.2 ;
    END
  END xo[132]
  PIN xo[133]
    DIRECTION OUTPUT ;
    USE SIGNAL ;
    PORT
      LAYER M5 ;
        RECT  12.432 43.116 12.456 43.2 ;
    END
  END xo[133]
  PIN xo[134]
    DIRECTION OUTPUT ;
    USE SIGNAL ;
    PORT
      LAYER M5 ;
        RECT  12.528 43.116 12.552 43.2 ;
    END
  END xo[134]
  PIN xo[135]
    DIRECTION OUTPUT ;
    USE SIGNAL ;
    PORT
      LAYER M5 ;
        RECT  12.624 43.116 12.648 43.2 ;
    END
  END xo[135]
  PIN xo[136]
    DIRECTION OUTPUT ;
    USE SIGNAL ;
    PORT
      LAYER M5 ;
        RECT  12.72 43.116 12.744 43.2 ;
    END
  END xo[136]
  PIN xo[137]
    DIRECTION OUTPUT ;
    USE SIGNAL ;
    PORT
      LAYER M5 ;
        RECT  12.816 43.116 12.84 43.2 ;
    END
  END xo[137]
  PIN xo[138]
    DIRECTION OUTPUT ;
    USE SIGNAL ;
    PORT
      LAYER M5 ;
        RECT  12.912 43.116 12.936 43.2 ;
    END
  END xo[138]
  PIN xo[139]
    DIRECTION OUTPUT ;
    USE SIGNAL ;
    PORT
      LAYER M5 ;
        RECT  13.008 43.116 13.032 43.2 ;
    END
  END xo[139]
  PIN xo[13]
    DIRECTION OUTPUT ;
    USE SIGNAL ;
    PORT
      LAYER M5 ;
        RECT  48.528 43.116 48.552 43.2 ;
    END
  END xo[13]
  PIN xo[140]
    DIRECTION OUTPUT ;
    USE SIGNAL ;
    PORT
      LAYER M5 ;
        RECT  13.104 43.116 13.128 43.2 ;
    END
  END xo[140]
  PIN xo[141]
    DIRECTION OUTPUT ;
    USE SIGNAL ;
    PORT
      LAYER M5 ;
        RECT  13.2 43.116 13.224 43.2 ;
    END
  END xo[141]
  PIN xo[142]
    DIRECTION OUTPUT ;
    USE SIGNAL ;
    PORT
      LAYER M5 ;
        RECT  13.296 43.116 13.32 43.2 ;
    END
  END xo[142]
  PIN xo[143]
    DIRECTION OUTPUT ;
    USE SIGNAL ;
    PORT
      LAYER M5 ;
        RECT  13.392 43.116 13.416 43.2 ;
    END
  END xo[143]
  PIN xo[144]
    DIRECTION OUTPUT ;
    USE SIGNAL ;
    PORT
      LAYER M5 ;
        RECT  13.488 43.116 13.512 43.2 ;
    END
  END xo[144]
  PIN xo[145]
    DIRECTION OUTPUT ;
    USE SIGNAL ;
    PORT
      LAYER M5 ;
        RECT  13.584 43.116 13.608 43.2 ;
    END
  END xo[145]
  PIN xo[146]
    DIRECTION OUTPUT ;
    USE SIGNAL ;
    PORT
      LAYER M5 ;
        RECT  13.68 43.116 13.704 43.2 ;
    END
  END xo[146]
  PIN xo[147]
    DIRECTION OUTPUT ;
    USE SIGNAL ;
    PORT
      LAYER M5 ;
        RECT  13.776 43.116 13.8 43.2 ;
    END
  END xo[147]
  PIN xo[148]
    DIRECTION OUTPUT ;
    USE SIGNAL ;
    PORT
      LAYER M5 ;
        RECT  13.872 43.116 13.896 43.2 ;
    END
  END xo[148]
  PIN xo[149]
    DIRECTION OUTPUT ;
    USE SIGNAL ;
    PORT
      LAYER M5 ;
        RECT  13.968 43.116 13.992 43.2 ;
    END
  END xo[149]
  PIN xo[14]
    DIRECTION OUTPUT ;
    USE SIGNAL ;
    PORT
      LAYER M5 ;
        RECT  48.624 43.116 48.648 43.2 ;
    END
  END xo[14]
  PIN xo[150]
    DIRECTION OUTPUT ;
    USE SIGNAL ;
    PORT
      LAYER M5 ;
        RECT  14.064 43.116 14.088 43.2 ;
    END
  END xo[150]
  PIN xo[151]
    DIRECTION OUTPUT ;
    USE SIGNAL ;
    PORT
      LAYER M5 ;
        RECT  14.16 43.116 14.184 43.2 ;
    END
  END xo[151]
  PIN xo[152]
    DIRECTION OUTPUT ;
    USE SIGNAL ;
    PORT
      LAYER M5 ;
        RECT  14.256 43.116 14.28 43.2 ;
    END
  END xo[152]
  PIN xo[153]
    DIRECTION OUTPUT ;
    USE SIGNAL ;
    PORT
      LAYER M5 ;
        RECT  14.352 43.116 14.376 43.2 ;
    END
  END xo[153]
  PIN xo[154]
    DIRECTION OUTPUT ;
    USE SIGNAL ;
    PORT
      LAYER M5 ;
        RECT  14.448 43.116 14.472 43.2 ;
    END
  END xo[154]
  PIN xo[155]
    DIRECTION OUTPUT ;
    USE SIGNAL ;
    PORT
      LAYER M5 ;
        RECT  14.544 43.116 14.568 43.2 ;
    END
  END xo[155]
  PIN xo[156]
    DIRECTION OUTPUT ;
    USE SIGNAL ;
    PORT
      LAYER M5 ;
        RECT  14.64 43.116 14.664 43.2 ;
    END
  END xo[156]
  PIN xo[157]
    DIRECTION OUTPUT ;
    USE SIGNAL ;
    PORT
      LAYER M5 ;
        RECT  14.736 43.116 14.76 43.2 ;
    END
  END xo[157]
  PIN xo[158]
    DIRECTION OUTPUT ;
    USE SIGNAL ;
    PORT
      LAYER M5 ;
        RECT  14.832 43.116 14.856 43.2 ;
    END
  END xo[158]
  PIN xo[159]
    DIRECTION OUTPUT ;
    USE SIGNAL ;
    PORT
      LAYER M5 ;
        RECT  14.928 43.116 14.952 43.2 ;
    END
  END xo[159]
  PIN xo[15]
    DIRECTION OUTPUT ;
    USE SIGNAL ;
    PORT
      LAYER M5 ;
        RECT  48.72 43.116 48.744 43.2 ;
    END
  END xo[15]
  PIN xo[160]
    DIRECTION OUTPUT ;
    USE SIGNAL ;
    PORT
      LAYER M5 ;
        RECT  69.552 43.116 69.576 43.2 ;
    END
  END xo[160]
  PIN xo[161]
    DIRECTION OUTPUT ;
    USE SIGNAL ;
    PORT
      LAYER M5 ;
        RECT  69.648 43.116 69.672 43.2 ;
    END
  END xo[161]
  PIN xo[162]
    DIRECTION OUTPUT ;
    USE SIGNAL ;
    PORT
      LAYER M5 ;
        RECT  69.744 43.116 69.768 43.2 ;
    END
  END xo[162]
  PIN xo[163]
    DIRECTION OUTPUT ;
    USE SIGNAL ;
    PORT
      LAYER M5 ;
        RECT  69.84 43.116 69.864 43.2 ;
    END
  END xo[163]
  PIN xo[164]
    DIRECTION OUTPUT ;
    USE SIGNAL ;
    PORT
      LAYER M5 ;
        RECT  69.936 43.116 69.96 43.2 ;
    END
  END xo[164]
  PIN xo[165]
    DIRECTION OUTPUT ;
    USE SIGNAL ;
    PORT
      LAYER M5 ;
        RECT  70.032 43.116 70.056 43.2 ;
    END
  END xo[165]
  PIN xo[166]
    DIRECTION OUTPUT ;
    USE SIGNAL ;
    PORT
      LAYER M5 ;
        RECT  70.128 43.116 70.152 43.2 ;
    END
  END xo[166]
  PIN xo[167]
    DIRECTION OUTPUT ;
    USE SIGNAL ;
    PORT
      LAYER M5 ;
        RECT  70.224 43.116 70.248 43.2 ;
    END
  END xo[167]
  PIN xo[168]
    DIRECTION OUTPUT ;
    USE SIGNAL ;
    PORT
      LAYER M5 ;
        RECT  70.32 43.116 70.344 43.2 ;
    END
  END xo[168]
  PIN xo[169]
    DIRECTION OUTPUT ;
    USE SIGNAL ;
    PORT
      LAYER M5 ;
        RECT  70.416 43.116 70.44 43.2 ;
    END
  END xo[169]
  PIN xo[16]
    DIRECTION OUTPUT ;
    USE SIGNAL ;
    PORT
      LAYER M5 ;
        RECT  48.816 43.116 48.84 43.2 ;
    END
  END xo[16]
  PIN xo[170]
    DIRECTION OUTPUT ;
    USE SIGNAL ;
    PORT
      LAYER M5 ;
        RECT  70.512 43.116 70.536 43.2 ;
    END
  END xo[170]
  PIN xo[171]
    DIRECTION OUTPUT ;
    USE SIGNAL ;
    PORT
      LAYER M5 ;
        RECT  70.608 43.116 70.632 43.2 ;
    END
  END xo[171]
  PIN xo[172]
    DIRECTION OUTPUT ;
    USE SIGNAL ;
    PORT
      LAYER M5 ;
        RECT  70.704 43.116 70.728 43.2 ;
    END
  END xo[172]
  PIN xo[173]
    DIRECTION OUTPUT ;
    USE SIGNAL ;
    PORT
      LAYER M5 ;
        RECT  70.8 43.116 70.824 43.2 ;
    END
  END xo[173]
  PIN xo[174]
    DIRECTION OUTPUT ;
    USE SIGNAL ;
    PORT
      LAYER M5 ;
        RECT  70.896 43.116 70.92 43.2 ;
    END
  END xo[174]
  PIN xo[175]
    DIRECTION OUTPUT ;
    USE SIGNAL ;
    PORT
      LAYER M5 ;
        RECT  70.992 43.116 71.016 43.2 ;
    END
  END xo[175]
  PIN xo[176]
    DIRECTION OUTPUT ;
    USE SIGNAL ;
    PORT
      LAYER M5 ;
        RECT  71.088 43.116 71.112 43.2 ;
    END
  END xo[176]
  PIN xo[177]
    DIRECTION OUTPUT ;
    USE SIGNAL ;
    PORT
      LAYER M5 ;
        RECT  71.184 43.116 71.208 43.2 ;
    END
  END xo[177]
  PIN xo[178]
    DIRECTION OUTPUT ;
    USE SIGNAL ;
    PORT
      LAYER M5 ;
        RECT  71.28 43.116 71.304 43.2 ;
    END
  END xo[178]
  PIN xo[179]
    DIRECTION OUTPUT ;
    USE SIGNAL ;
    PORT
      LAYER M5 ;
        RECT  71.376 43.116 71.4 43.2 ;
    END
  END xo[179]
  PIN xo[17]
    DIRECTION OUTPUT ;
    USE SIGNAL ;
    PORT
      LAYER M5 ;
        RECT  48.912 43.116 48.936 43.2 ;
    END
  END xo[17]
  PIN xo[180]
    DIRECTION OUTPUT ;
    USE SIGNAL ;
    PORT
      LAYER M5 ;
        RECT  71.472 43.116 71.496 43.2 ;
    END
  END xo[180]
  PIN xo[181]
    DIRECTION OUTPUT ;
    USE SIGNAL ;
    PORT
      LAYER M5 ;
        RECT  71.568 43.116 71.592 43.2 ;
    END
  END xo[181]
  PIN xo[182]
    DIRECTION OUTPUT ;
    USE SIGNAL ;
    PORT
      LAYER M5 ;
        RECT  71.664 43.116 71.688 43.2 ;
    END
  END xo[182]
  PIN xo[183]
    DIRECTION OUTPUT ;
    USE SIGNAL ;
    PORT
      LAYER M5 ;
        RECT  71.76 43.116 71.784 43.2 ;
    END
  END xo[183]
  PIN xo[184]
    DIRECTION OUTPUT ;
    USE SIGNAL ;
    PORT
      LAYER M5 ;
        RECT  71.856 43.116 71.88 43.2 ;
    END
  END xo[184]
  PIN xo[185]
    DIRECTION OUTPUT ;
    USE SIGNAL ;
    PORT
      LAYER M5 ;
        RECT  71.952 43.116 71.976 43.2 ;
    END
  END xo[185]
  PIN xo[186]
    DIRECTION OUTPUT ;
    USE SIGNAL ;
    PORT
      LAYER M5 ;
        RECT  72.048 43.116 72.072 43.2 ;
    END
  END xo[186]
  PIN xo[187]
    DIRECTION OUTPUT ;
    USE SIGNAL ;
    PORT
      LAYER M5 ;
        RECT  72.144 43.116 72.168 43.2 ;
    END
  END xo[187]
  PIN xo[188]
    DIRECTION OUTPUT ;
    USE SIGNAL ;
    PORT
      LAYER M5 ;
        RECT  72.24 43.116 72.264 43.2 ;
    END
  END xo[188]
  PIN xo[189]
    DIRECTION OUTPUT ;
    USE SIGNAL ;
    PORT
      LAYER M5 ;
        RECT  72.336 43.116 72.36 43.2 ;
    END
  END xo[189]
  PIN xo[18]
    DIRECTION OUTPUT ;
    USE SIGNAL ;
    PORT
      LAYER M5 ;
        RECT  49.008 43.116 49.032 43.2 ;
    END
  END xo[18]
  PIN xo[190]
    DIRECTION OUTPUT ;
    USE SIGNAL ;
    PORT
      LAYER M5 ;
        RECT  72.432 43.116 72.456 43.2 ;
    END
  END xo[190]
  PIN xo[191]
    DIRECTION OUTPUT ;
    USE SIGNAL ;
    PORT
      LAYER M5 ;
        RECT  72.528 43.116 72.552 43.2 ;
    END
  END xo[191]
  PIN xo[192]
    DIRECTION OUTPUT ;
    USE SIGNAL ;
    PORT
      LAYER M5 ;
        RECT  18.096 43.116 18.12 43.2 ;
    END
  END xo[192]
  PIN xo[193]
    DIRECTION OUTPUT ;
    USE SIGNAL ;
    PORT
      LAYER M5 ;
        RECT  18.192 43.116 18.216 43.2 ;
    END
  END xo[193]
  PIN xo[194]
    DIRECTION OUTPUT ;
    USE SIGNAL ;
    PORT
      LAYER M5 ;
        RECT  18.288 43.116 18.312 43.2 ;
    END
  END xo[194]
  PIN xo[195]
    DIRECTION OUTPUT ;
    USE SIGNAL ;
    PORT
      LAYER M5 ;
        RECT  18.384 43.116 18.408 43.2 ;
    END
  END xo[195]
  PIN xo[196]
    DIRECTION OUTPUT ;
    USE SIGNAL ;
    PORT
      LAYER M5 ;
        RECT  18.48 43.116 18.504 43.2 ;
    END
  END xo[196]
  PIN xo[197]
    DIRECTION OUTPUT ;
    USE SIGNAL ;
    PORT
      LAYER M5 ;
        RECT  18.576 43.116 18.6 43.2 ;
    END
  END xo[197]
  PIN xo[198]
    DIRECTION OUTPUT ;
    USE SIGNAL ;
    PORT
      LAYER M5 ;
        RECT  18.672 43.116 18.696 43.2 ;
    END
  END xo[198]
  PIN xo[199]
    DIRECTION OUTPUT ;
    USE SIGNAL ;
    PORT
      LAYER M5 ;
        RECT  18.768 43.116 18.792 43.2 ;
    END
  END xo[199]
  PIN xo[19]
    DIRECTION OUTPUT ;
    USE SIGNAL ;
    PORT
      LAYER M5 ;
        RECT  49.104 43.116 49.128 43.2 ;
    END
  END xo[19]
  PIN xo[1]
    DIRECTION OUTPUT ;
    USE SIGNAL ;
    PORT
      LAYER M5 ;
        RECT  47.376 43.116 47.4 43.2 ;
    END
  END xo[1]
  PIN xo[200]
    DIRECTION OUTPUT ;
    USE SIGNAL ;
    PORT
      LAYER M5 ;
        RECT  18.864 43.116 18.888 43.2 ;
    END
  END xo[200]
  PIN xo[201]
    DIRECTION OUTPUT ;
    USE SIGNAL ;
    PORT
      LAYER M5 ;
        RECT  18.96 43.116 18.984 43.2 ;
    END
  END xo[201]
  PIN xo[202]
    DIRECTION OUTPUT ;
    USE SIGNAL ;
    PORT
      LAYER M5 ;
        RECT  19.056 43.116 19.08 43.2 ;
    END
  END xo[202]
  PIN xo[203]
    DIRECTION OUTPUT ;
    USE SIGNAL ;
    PORT
      LAYER M5 ;
        RECT  19.152 43.116 19.176 43.2 ;
    END
  END xo[203]
  PIN xo[204]
    DIRECTION OUTPUT ;
    USE SIGNAL ;
    PORT
      LAYER M5 ;
        RECT  19.248 43.116 19.272 43.2 ;
    END
  END xo[204]
  PIN xo[205]
    DIRECTION OUTPUT ;
    USE SIGNAL ;
    PORT
      LAYER M5 ;
        RECT  19.344 43.116 19.368 43.2 ;
    END
  END xo[205]
  PIN xo[206]
    DIRECTION OUTPUT ;
    USE SIGNAL ;
    PORT
      LAYER M5 ;
        RECT  19.44 43.116 19.464 43.2 ;
    END
  END xo[206]
  PIN xo[207]
    DIRECTION OUTPUT ;
    USE SIGNAL ;
    PORT
      LAYER M5 ;
        RECT  19.536 43.116 19.56 43.2 ;
    END
  END xo[207]
  PIN xo[208]
    DIRECTION OUTPUT ;
    USE SIGNAL ;
    PORT
      LAYER M5 ;
        RECT  19.632 43.116 19.656 43.2 ;
    END
  END xo[208]
  PIN xo[209]
    DIRECTION OUTPUT ;
    USE SIGNAL ;
    PORT
      LAYER M5 ;
        RECT  19.728 43.116 19.752 43.2 ;
    END
  END xo[209]
  PIN xo[20]
    DIRECTION OUTPUT ;
    USE SIGNAL ;
    PORT
      LAYER M5 ;
        RECT  49.2 43.116 49.224 43.2 ;
    END
  END xo[20]
  PIN xo[210]
    DIRECTION OUTPUT ;
    USE SIGNAL ;
    PORT
      LAYER M5 ;
        RECT  19.824 43.116 19.848 43.2 ;
    END
  END xo[210]
  PIN xo[211]
    DIRECTION OUTPUT ;
    USE SIGNAL ;
    PORT
      LAYER M5 ;
        RECT  19.92 43.116 19.944 43.2 ;
    END
  END xo[211]
  PIN xo[212]
    DIRECTION OUTPUT ;
    USE SIGNAL ;
    PORT
      LAYER M5 ;
        RECT  20.016 43.116 20.04 43.2 ;
    END
  END xo[212]
  PIN xo[213]
    DIRECTION OUTPUT ;
    USE SIGNAL ;
    PORT
      LAYER M5 ;
        RECT  20.112 43.116 20.136 43.2 ;
    END
  END xo[213]
  PIN xo[214]
    DIRECTION OUTPUT ;
    USE SIGNAL ;
    PORT
      LAYER M5 ;
        RECT  20.208 43.116 20.232 43.2 ;
    END
  END xo[214]
  PIN xo[215]
    DIRECTION OUTPUT ;
    USE SIGNAL ;
    PORT
      LAYER M5 ;
        RECT  20.304 43.116 20.328 43.2 ;
    END
  END xo[215]
  PIN xo[216]
    DIRECTION OUTPUT ;
    USE SIGNAL ;
    PORT
      LAYER M5 ;
        RECT  20.4 43.116 20.424 43.2 ;
    END
  END xo[216]
  PIN xo[217]
    DIRECTION OUTPUT ;
    USE SIGNAL ;
    PORT
      LAYER M5 ;
        RECT  20.496 43.116 20.52 43.2 ;
    END
  END xo[217]
  PIN xo[218]
    DIRECTION OUTPUT ;
    USE SIGNAL ;
    PORT
      LAYER M5 ;
        RECT  20.592 43.116 20.616 43.2 ;
    END
  END xo[218]
  PIN xo[219]
    DIRECTION OUTPUT ;
    USE SIGNAL ;
    PORT
      LAYER M5 ;
        RECT  20.688 43.116 20.712 43.2 ;
    END
  END xo[219]
  PIN xo[21]
    DIRECTION OUTPUT ;
    USE SIGNAL ;
    PORT
      LAYER M5 ;
        RECT  49.296 43.116 49.32 43.2 ;
    END
  END xo[21]
  PIN xo[220]
    DIRECTION OUTPUT ;
    USE SIGNAL ;
    PORT
      LAYER M5 ;
        RECT  20.784 43.116 20.808 43.2 ;
    END
  END xo[220]
  PIN xo[221]
    DIRECTION OUTPUT ;
    USE SIGNAL ;
    PORT
      LAYER M5 ;
        RECT  20.88 43.116 20.904 43.2 ;
    END
  END xo[221]
  PIN xo[222]
    DIRECTION OUTPUT ;
    USE SIGNAL ;
    PORT
      LAYER M5 ;
        RECT  20.976 43.116 21 43.2 ;
    END
  END xo[222]
  PIN xo[223]
    DIRECTION OUTPUT ;
    USE SIGNAL ;
    PORT
      LAYER M5 ;
        RECT  21.072 43.116 21.096 43.2 ;
    END
  END xo[223]
  PIN xo[224]
    DIRECTION OUTPUT ;
    USE SIGNAL ;
    PORT
      LAYER M5 ;
        RECT  72.624 43.116 72.648 43.2 ;
    END
  END xo[224]
  PIN xo[225]
    DIRECTION OUTPUT ;
    USE SIGNAL ;
    PORT
      LAYER M5 ;
        RECT  72.72 43.116 72.744 43.2 ;
    END
  END xo[225]
  PIN xo[226]
    DIRECTION OUTPUT ;
    USE SIGNAL ;
    PORT
      LAYER M5 ;
        RECT  72.816 43.116 72.84 43.2 ;
    END
  END xo[226]
  PIN xo[227]
    DIRECTION OUTPUT ;
    USE SIGNAL ;
    PORT
      LAYER M5 ;
        RECT  72.912 43.116 72.936 43.2 ;
    END
  END xo[227]
  PIN xo[228]
    DIRECTION OUTPUT ;
    USE SIGNAL ;
    PORT
      LAYER M5 ;
        RECT  73.008 43.116 73.032 43.2 ;
    END
  END xo[228]
  PIN xo[229]
    DIRECTION OUTPUT ;
    USE SIGNAL ;
    PORT
      LAYER M5 ;
        RECT  73.104 43.116 73.128 43.2 ;
    END
  END xo[229]
  PIN xo[22]
    DIRECTION OUTPUT ;
    USE SIGNAL ;
    PORT
      LAYER M5 ;
        RECT  49.392 43.116 49.416 43.2 ;
    END
  END xo[22]
  PIN xo[230]
    DIRECTION OUTPUT ;
    USE SIGNAL ;
    PORT
      LAYER M5 ;
        RECT  73.2 43.116 73.224 43.2 ;
    END
  END xo[230]
  PIN xo[231]
    DIRECTION OUTPUT ;
    USE SIGNAL ;
    PORT
      LAYER M5 ;
        RECT  73.296 43.116 73.32 43.2 ;
    END
  END xo[231]
  PIN xo[232]
    DIRECTION OUTPUT ;
    USE SIGNAL ;
    PORT
      LAYER M5 ;
        RECT  73.392 43.116 73.416 43.2 ;
    END
  END xo[232]
  PIN xo[233]
    DIRECTION OUTPUT ;
    USE SIGNAL ;
    PORT
      LAYER M5 ;
        RECT  73.488 43.116 73.512 43.2 ;
    END
  END xo[233]
  PIN xo[234]
    DIRECTION OUTPUT ;
    USE SIGNAL ;
    PORT
      LAYER M5 ;
        RECT  73.584 43.116 73.608 43.2 ;
    END
  END xo[234]
  PIN xo[235]
    DIRECTION OUTPUT ;
    USE SIGNAL ;
    PORT
      LAYER M5 ;
        RECT  73.68 43.116 73.704 43.2 ;
    END
  END xo[235]
  PIN xo[236]
    DIRECTION OUTPUT ;
    USE SIGNAL ;
    PORT
      LAYER M5 ;
        RECT  73.776 43.116 73.8 43.2 ;
    END
  END xo[236]
  PIN xo[237]
    DIRECTION OUTPUT ;
    USE SIGNAL ;
    PORT
      LAYER M5 ;
        RECT  73.872 43.116 73.896 43.2 ;
    END
  END xo[237]
  PIN xo[238]
    DIRECTION OUTPUT ;
    USE SIGNAL ;
    PORT
      LAYER M5 ;
        RECT  73.968 43.116 73.992 43.2 ;
    END
  END xo[238]
  PIN xo[239]
    DIRECTION OUTPUT ;
    USE SIGNAL ;
    PORT
      LAYER M5 ;
        RECT  74.064 43.116 74.088 43.2 ;
    END
  END xo[239]
  PIN xo[23]
    DIRECTION OUTPUT ;
    USE SIGNAL ;
    PORT
      LAYER M5 ;
        RECT  49.488 43.116 49.512 43.2 ;
    END
  END xo[23]
  PIN xo[240]
    DIRECTION OUTPUT ;
    USE SIGNAL ;
    PORT
      LAYER M5 ;
        RECT  74.16 43.116 74.184 43.2 ;
    END
  END xo[240]
  PIN xo[241]
    DIRECTION OUTPUT ;
    USE SIGNAL ;
    PORT
      LAYER M5 ;
        RECT  74.256 43.116 74.28 43.2 ;
    END
  END xo[241]
  PIN xo[242]
    DIRECTION OUTPUT ;
    USE SIGNAL ;
    PORT
      LAYER M5 ;
        RECT  74.352 43.116 74.376 43.2 ;
    END
  END xo[242]
  PIN xo[243]
    DIRECTION OUTPUT ;
    USE SIGNAL ;
    PORT
      LAYER M5 ;
        RECT  74.448 43.116 74.472 43.2 ;
    END
  END xo[243]
  PIN xo[244]
    DIRECTION OUTPUT ;
    USE SIGNAL ;
    PORT
      LAYER M5 ;
        RECT  74.544 43.116 74.568 43.2 ;
    END
  END xo[244]
  PIN xo[245]
    DIRECTION OUTPUT ;
    USE SIGNAL ;
    PORT
      LAYER M5 ;
        RECT  74.64 43.116 74.664 43.2 ;
    END
  END xo[245]
  PIN xo[246]
    DIRECTION OUTPUT ;
    USE SIGNAL ;
    PORT
      LAYER M5 ;
        RECT  74.736 43.116 74.76 43.2 ;
    END
  END xo[246]
  PIN xo[247]
    DIRECTION OUTPUT ;
    USE SIGNAL ;
    PORT
      LAYER M5 ;
        RECT  74.832 43.116 74.856 43.2 ;
    END
  END xo[247]
  PIN xo[248]
    DIRECTION OUTPUT ;
    USE SIGNAL ;
    PORT
      LAYER M5 ;
        RECT  74.928 43.116 74.952 43.2 ;
    END
  END xo[248]
  PIN xo[249]
    DIRECTION OUTPUT ;
    USE SIGNAL ;
    PORT
      LAYER M5 ;
        RECT  75.024 43.116 75.048 43.2 ;
    END
  END xo[249]
  PIN xo[24]
    DIRECTION OUTPUT ;
    USE SIGNAL ;
    PORT
      LAYER M5 ;
        RECT  49.584 43.116 49.608 43.2 ;
    END
  END xo[24]
  PIN xo[250]
    DIRECTION OUTPUT ;
    USE SIGNAL ;
    PORT
      LAYER M5 ;
        RECT  75.12 43.116 75.144 43.2 ;
    END
  END xo[250]
  PIN xo[251]
    DIRECTION OUTPUT ;
    USE SIGNAL ;
    PORT
      LAYER M5 ;
        RECT  75.216 43.116 75.24 43.2 ;
    END
  END xo[251]
  PIN xo[252]
    DIRECTION OUTPUT ;
    USE SIGNAL ;
    PORT
      LAYER M5 ;
        RECT  75.312 43.116 75.336 43.2 ;
    END
  END xo[252]
  PIN xo[253]
    DIRECTION OUTPUT ;
    USE SIGNAL ;
    PORT
      LAYER M5 ;
        RECT  75.408 43.116 75.432 43.2 ;
    END
  END xo[253]
  PIN xo[254]
    DIRECTION OUTPUT ;
    USE SIGNAL ;
    PORT
      LAYER M5 ;
        RECT  75.504 43.116 75.528 43.2 ;
    END
  END xo[254]
  PIN xo[255]
    DIRECTION OUTPUT ;
    USE SIGNAL ;
    PORT
      LAYER M5 ;
        RECT  75.6 43.116 75.624 43.2 ;
    END
  END xo[255]
  PIN xo[25]
    DIRECTION OUTPUT ;
    USE SIGNAL ;
    PORT
      LAYER M5 ;
        RECT  49.68 43.116 49.704 43.2 ;
    END
  END xo[25]
  PIN xo[26]
    DIRECTION OUTPUT ;
    USE SIGNAL ;
    PORT
      LAYER M5 ;
        RECT  49.776 43.116 49.8 43.2 ;
    END
  END xo[26]
  PIN xo[27]
    DIRECTION OUTPUT ;
    USE SIGNAL ;
    PORT
      LAYER M5 ;
        RECT  49.872 43.116 49.896 43.2 ;
    END
  END xo[27]
  PIN xo[28]
    DIRECTION OUTPUT ;
    USE SIGNAL ;
    PORT
      LAYER M5 ;
        RECT  49.968 43.116 49.992 43.2 ;
    END
  END xo[28]
  PIN xo[29]
    DIRECTION OUTPUT ;
    USE SIGNAL ;
    PORT
      LAYER M5 ;
        RECT  50.064 43.116 50.088 43.2 ;
    END
  END xo[29]
  PIN xo[2]
    DIRECTION OUTPUT ;
    USE SIGNAL ;
    PORT
      LAYER M5 ;
        RECT  47.472 43.116 47.496 43.2 ;
    END
  END xo[2]
  PIN xo[30]
    DIRECTION OUTPUT ;
    USE SIGNAL ;
    PORT
      LAYER M5 ;
        RECT  50.16 43.116 50.184 43.2 ;
    END
  END xo[30]
  PIN xo[31]
    DIRECTION OUTPUT ;
    USE SIGNAL ;
    PORT
      LAYER M5 ;
        RECT  50.256 43.116 50.28 43.2 ;
    END
  END xo[31]
  PIN xo[32]
    DIRECTION OUTPUT ;
    USE SIGNAL ;
    PORT
      LAYER M5 ;
        RECT  101.808 43.116 101.832 43.2 ;
    END
  END xo[32]
  PIN xo[33]
    DIRECTION OUTPUT ;
    USE SIGNAL ;
    PORT
      LAYER M5 ;
        RECT  101.904 43.116 101.928 43.2 ;
    END
  END xo[33]
  PIN xo[34]
    DIRECTION OUTPUT ;
    USE SIGNAL ;
    PORT
      LAYER M5 ;
        RECT  102 43.116 102.024 43.2 ;
    END
  END xo[34]
  PIN xo[35]
    DIRECTION OUTPUT ;
    USE SIGNAL ;
    PORT
      LAYER M5 ;
        RECT  102.096 43.116 102.12 43.2 ;
    END
  END xo[35]
  PIN xo[36]
    DIRECTION OUTPUT ;
    USE SIGNAL ;
    PORT
      LAYER M5 ;
        RECT  102.192 43.116 102.216 43.2 ;
    END
  END xo[36]
  PIN xo[37]
    DIRECTION OUTPUT ;
    USE SIGNAL ;
    PORT
      LAYER M5 ;
        RECT  102.288 43.116 102.312 43.2 ;
    END
  END xo[37]
  PIN xo[38]
    DIRECTION OUTPUT ;
    USE SIGNAL ;
    PORT
      LAYER M5 ;
        RECT  102.384 43.116 102.408 43.2 ;
    END
  END xo[38]
  PIN xo[39]
    DIRECTION OUTPUT ;
    USE SIGNAL ;
    PORT
      LAYER M5 ;
        RECT  102.48 43.116 102.504 43.2 ;
    END
  END xo[39]
  PIN xo[3]
    DIRECTION OUTPUT ;
    USE SIGNAL ;
    PORT
      LAYER M5 ;
        RECT  47.568 43.116 47.592 43.2 ;
    END
  END xo[3]
  PIN xo[40]
    DIRECTION OUTPUT ;
    USE SIGNAL ;
    PORT
      LAYER M5 ;
        RECT  102.576 43.116 102.6 43.2 ;
    END
  END xo[40]
  PIN xo[41]
    DIRECTION OUTPUT ;
    USE SIGNAL ;
    PORT
      LAYER M5 ;
        RECT  102.672 43.116 102.696 43.2 ;
    END
  END xo[41]
  PIN xo[42]
    DIRECTION OUTPUT ;
    USE SIGNAL ;
    PORT
      LAYER M5 ;
        RECT  102.768 43.116 102.792 43.2 ;
    END
  END xo[42]
  PIN xo[43]
    DIRECTION OUTPUT ;
    USE SIGNAL ;
    PORT
      LAYER M5 ;
        RECT  102.864 43.116 102.888 43.2 ;
    END
  END xo[43]
  PIN xo[44]
    DIRECTION OUTPUT ;
    USE SIGNAL ;
    PORT
      LAYER M5 ;
        RECT  102.96 43.116 102.984 43.2 ;
    END
  END xo[44]
  PIN xo[45]
    DIRECTION OUTPUT ;
    USE SIGNAL ;
    PORT
      LAYER M5 ;
        RECT  103.056 43.116 103.08 43.2 ;
    END
  END xo[45]
  PIN xo[46]
    DIRECTION OUTPUT ;
    USE SIGNAL ;
    PORT
      LAYER M5 ;
        RECT  103.152 43.116 103.176 43.2 ;
    END
  END xo[46]
  PIN xo[47]
    DIRECTION OUTPUT ;
    USE SIGNAL ;
    PORT
      LAYER M5 ;
        RECT  103.248 43.116 103.272 43.2 ;
    END
  END xo[47]
  PIN xo[48]
    DIRECTION OUTPUT ;
    USE SIGNAL ;
    PORT
      LAYER M5 ;
        RECT  103.344 43.116 103.368 43.2 ;
    END
  END xo[48]
  PIN xo[49]
    DIRECTION OUTPUT ;
    USE SIGNAL ;
    PORT
      LAYER M5 ;
        RECT  103.44 43.116 103.464 43.2 ;
    END
  END xo[49]
  PIN xo[4]
    DIRECTION OUTPUT ;
    USE SIGNAL ;
    PORT
      LAYER M5 ;
        RECT  47.664 43.116 47.688 43.2 ;
    END
  END xo[4]
  PIN xo[50]
    DIRECTION OUTPUT ;
    USE SIGNAL ;
    PORT
      LAYER M5 ;
        RECT  103.536 43.116 103.56 43.2 ;
    END
  END xo[50]
  PIN xo[51]
    DIRECTION OUTPUT ;
    USE SIGNAL ;
    PORT
      LAYER M5 ;
        RECT  103.632 43.116 103.656 43.2 ;
    END
  END xo[51]
  PIN xo[52]
    DIRECTION OUTPUT ;
    USE SIGNAL ;
    PORT
      LAYER M5 ;
        RECT  103.728 43.116 103.752 43.2 ;
    END
  END xo[52]
  PIN xo[53]
    DIRECTION OUTPUT ;
    USE SIGNAL ;
    PORT
      LAYER M5 ;
        RECT  103.824 43.116 103.848 43.2 ;
    END
  END xo[53]
  PIN xo[54]
    DIRECTION OUTPUT ;
    USE SIGNAL ;
    PORT
      LAYER M5 ;
        RECT  103.92 43.116 103.944 43.2 ;
    END
  END xo[54]
  PIN xo[55]
    DIRECTION OUTPUT ;
    USE SIGNAL ;
    PORT
      LAYER M5 ;
        RECT  104.016 43.116 104.04 43.2 ;
    END
  END xo[55]
  PIN xo[56]
    DIRECTION OUTPUT ;
    USE SIGNAL ;
    PORT
      LAYER M5 ;
        RECT  104.112 43.116 104.136 43.2 ;
    END
  END xo[56]
  PIN xo[57]
    DIRECTION OUTPUT ;
    USE SIGNAL ;
    PORT
      LAYER M5 ;
        RECT  104.208 43.116 104.232 43.2 ;
    END
  END xo[57]
  PIN xo[58]
    DIRECTION OUTPUT ;
    USE SIGNAL ;
    PORT
      LAYER M5 ;
        RECT  104.304 43.116 104.328 43.2 ;
    END
  END xo[58]
  PIN xo[59]
    DIRECTION OUTPUT ;
    USE SIGNAL ;
    PORT
      LAYER M5 ;
        RECT  104.4 43.116 104.424 43.2 ;
    END
  END xo[59]
  PIN xo[5]
    DIRECTION OUTPUT ;
    USE SIGNAL ;
    PORT
      LAYER M5 ;
        RECT  47.76 43.116 47.784 43.2 ;
    END
  END xo[5]
  PIN xo[60]
    DIRECTION OUTPUT ;
    USE SIGNAL ;
    PORT
      LAYER M5 ;
        RECT  104.496 43.116 104.52 43.2 ;
    END
  END xo[60]
  PIN xo[61]
    DIRECTION OUTPUT ;
    USE SIGNAL ;
    PORT
      LAYER M5 ;
        RECT  104.592 43.116 104.616 43.2 ;
    END
  END xo[61]
  PIN xo[62]
    DIRECTION OUTPUT ;
    USE SIGNAL ;
    PORT
      LAYER M5 ;
        RECT  104.688 43.116 104.712 43.2 ;
    END
  END xo[62]
  PIN xo[63]
    DIRECTION OUTPUT ;
    USE SIGNAL ;
    PORT
      LAYER M5 ;
        RECT  104.784 43.116 104.808 43.2 ;
    END
  END xo[63]
  PIN xo[64]
    DIRECTION OUTPUT ;
    USE SIGNAL ;
    PORT
      LAYER M5 ;
        RECT  104.88 43.116 104.904 43.2 ;
    END
  END xo[64]
  PIN xo[65]
    DIRECTION OUTPUT ;
    USE SIGNAL ;
    PORT
      LAYER M5 ;
        RECT  104.976 43.116 105 43.2 ;
    END
  END xo[65]
  PIN xo[66]
    DIRECTION OUTPUT ;
    USE SIGNAL ;
    PORT
      LAYER M5 ;
        RECT  105.072 43.116 105.096 43.2 ;
    END
  END xo[66]
  PIN xo[67]
    DIRECTION OUTPUT ;
    USE SIGNAL ;
    PORT
      LAYER M5 ;
        RECT  105.168 43.116 105.192 43.2 ;
    END
  END xo[67]
  PIN xo[68]
    DIRECTION OUTPUT ;
    USE SIGNAL ;
    PORT
      LAYER M5 ;
        RECT  105.264 43.116 105.288 43.2 ;
    END
  END xo[68]
  PIN xo[69]
    DIRECTION OUTPUT ;
    USE SIGNAL ;
    PORT
      LAYER M5 ;
        RECT  105.36 43.116 105.384 43.2 ;
    END
  END xo[69]
  PIN xo[6]
    DIRECTION OUTPUT ;
    USE SIGNAL ;
    PORT
      LAYER M5 ;
        RECT  47.856 43.116 47.88 43.2 ;
    END
  END xo[6]
  PIN xo[70]
    DIRECTION OUTPUT ;
    USE SIGNAL ;
    PORT
      LAYER M5 ;
        RECT  105.456 43.116 105.48 43.2 ;
    END
  END xo[70]
  PIN xo[71]
    DIRECTION OUTPUT ;
    USE SIGNAL ;
    PORT
      LAYER M5 ;
        RECT  105.552 43.116 105.576 43.2 ;
    END
  END xo[71]
  PIN xo[72]
    DIRECTION OUTPUT ;
    USE SIGNAL ;
    PORT
      LAYER M5 ;
        RECT  105.648 43.116 105.672 43.2 ;
    END
  END xo[72]
  PIN xo[73]
    DIRECTION OUTPUT ;
    USE SIGNAL ;
    PORT
      LAYER M5 ;
        RECT  105.744 43.116 105.768 43.2 ;
    END
  END xo[73]
  PIN xo[74]
    DIRECTION OUTPUT ;
    USE SIGNAL ;
    PORT
      LAYER M5 ;
        RECT  105.84 43.116 105.864 43.2 ;
    END
  END xo[74]
  PIN xo[75]
    DIRECTION OUTPUT ;
    USE SIGNAL ;
    PORT
      LAYER M5 ;
        RECT  105.936 43.116 105.96 43.2 ;
    END
  END xo[75]
  PIN xo[76]
    DIRECTION OUTPUT ;
    USE SIGNAL ;
    PORT
      LAYER M5 ;
        RECT  106.032 43.116 106.056 43.2 ;
    END
  END xo[76]
  PIN xo[77]
    DIRECTION OUTPUT ;
    USE SIGNAL ;
    PORT
      LAYER M5 ;
        RECT  106.128 43.116 106.152 43.2 ;
    END
  END xo[77]
  PIN xo[78]
    DIRECTION OUTPUT ;
    USE SIGNAL ;
    PORT
      LAYER M5 ;
        RECT  106.224 43.116 106.248 43.2 ;
    END
  END xo[78]
  PIN xo[79]
    DIRECTION OUTPUT ;
    USE SIGNAL ;
    PORT
      LAYER M5 ;
        RECT  106.32 43.116 106.344 43.2 ;
    END
  END xo[79]
  PIN xo[7]
    DIRECTION OUTPUT ;
    USE SIGNAL ;
    PORT
      LAYER M5 ;
        RECT  47.952 43.116 47.976 43.2 ;
    END
  END xo[7]
  PIN xo[80]
    DIRECTION OUTPUT ;
    USE SIGNAL ;
    PORT
      LAYER M5 ;
        RECT  106.416 43.116 106.44 43.2 ;
    END
  END xo[80]
  PIN xo[81]
    DIRECTION OUTPUT ;
    USE SIGNAL ;
    PORT
      LAYER M5 ;
        RECT  106.512 43.116 106.536 43.2 ;
    END
  END xo[81]
  PIN xo[82]
    DIRECTION OUTPUT ;
    USE SIGNAL ;
    PORT
      LAYER M5 ;
        RECT  106.608 43.116 106.632 43.2 ;
    END
  END xo[82]
  PIN xo[83]
    DIRECTION OUTPUT ;
    USE SIGNAL ;
    PORT
      LAYER M5 ;
        RECT  106.704 43.116 106.728 43.2 ;
    END
  END xo[83]
  PIN xo[84]
    DIRECTION OUTPUT ;
    USE SIGNAL ;
    PORT
      LAYER M5 ;
        RECT  106.8 43.116 106.824 43.2 ;
    END
  END xo[84]
  PIN xo[85]
    DIRECTION OUTPUT ;
    USE SIGNAL ;
    PORT
      LAYER M5 ;
        RECT  106.896 43.116 106.92 43.2 ;
    END
  END xo[85]
  PIN xo[86]
    DIRECTION OUTPUT ;
    USE SIGNAL ;
    PORT
      LAYER M5 ;
        RECT  106.992 43.116 107.016 43.2 ;
    END
  END xo[86]
  PIN xo[87]
    DIRECTION OUTPUT ;
    USE SIGNAL ;
    PORT
      LAYER M5 ;
        RECT  107.088 43.116 107.112 43.2 ;
    END
  END xo[87]
  PIN xo[88]
    DIRECTION OUTPUT ;
    USE SIGNAL ;
    PORT
      LAYER M5 ;
        RECT  107.184 43.116 107.208 43.2 ;
    END
  END xo[88]
  PIN xo[89]
    DIRECTION OUTPUT ;
    USE SIGNAL ;
    PORT
      LAYER M5 ;
        RECT  107.28 43.116 107.304 43.2 ;
    END
  END xo[89]
  PIN xo[8]
    DIRECTION OUTPUT ;
    USE SIGNAL ;
    PORT
      LAYER M5 ;
        RECT  48.048 43.116 48.072 43.2 ;
    END
  END xo[8]
  PIN xo[90]
    DIRECTION OUTPUT ;
    USE SIGNAL ;
    PORT
      LAYER M5 ;
        RECT  107.376 43.116 107.4 43.2 ;
    END
  END xo[90]
  PIN xo[91]
    DIRECTION OUTPUT ;
    USE SIGNAL ;
    PORT
      LAYER M5 ;
        RECT  107.472 43.116 107.496 43.2 ;
    END
  END xo[91]
  PIN xo[92]
    DIRECTION OUTPUT ;
    USE SIGNAL ;
    PORT
      LAYER M5 ;
        RECT  107.568 43.116 107.592 43.2 ;
    END
  END xo[92]
  PIN xo[93]
    DIRECTION OUTPUT ;
    USE SIGNAL ;
    PORT
      LAYER M5 ;
        RECT  107.664 43.116 107.688 43.2 ;
    END
  END xo[93]
  PIN xo[94]
    DIRECTION OUTPUT ;
    USE SIGNAL ;
    PORT
      LAYER M5 ;
        RECT  107.76 43.116 107.784 43.2 ;
    END
  END xo[94]
  PIN xo[95]
    DIRECTION OUTPUT ;
    USE SIGNAL ;
    PORT
      LAYER M5 ;
        RECT  107.856 43.116 107.88 43.2 ;
    END
  END xo[95]
  PIN xo[96]
    DIRECTION OUTPUT ;
    USE SIGNAL ;
    PORT
      LAYER M5 ;
        RECT  44.208 43.116 44.232 43.2 ;
    END
  END xo[96]
  PIN xo[97]
    DIRECTION OUTPUT ;
    USE SIGNAL ;
    PORT
      LAYER M5 ;
        RECT  44.304 43.116 44.328 43.2 ;
    END
  END xo[97]
  PIN xo[98]
    DIRECTION OUTPUT ;
    USE SIGNAL ;
    PORT
      LAYER M5 ;
        RECT  44.4 43.116 44.424 43.2 ;
    END
  END xo[98]
  PIN xo[99]
    DIRECTION OUTPUT ;
    USE SIGNAL ;
    PORT
      LAYER M5 ;
        RECT  44.496 43.116 44.52 43.2 ;
    END
  END xo[99]
  PIN xo[9]
    DIRECTION OUTPUT ;
    USE SIGNAL ;
    PORT
      LAYER M5 ;
        RECT  48.144 43.116 48.168 43.2 ;
    END
  END xo[9]
  PIN VDD
    DIRECTION INOUT ;
    USE POWER ;
    PORT
      LAYER M5 ;
        RECT  115.992 2.151 116.112 41.049 ;
        RECT  110.592 2.151 110.712 41.049 ;
        RECT  105.192 2.151 105.312 41.049 ;
        RECT  99.792 2.151 99.912 41.049 ;
        RECT  94.392 2.151 94.512 41.049 ;
        RECT  88.992 2.151 89.112 41.049 ;
        RECT  83.592 2.151 83.712 41.049 ;
        RECT  78.192 2.151 78.312 41.049 ;
        RECT  72.792 2.151 72.912 41.049 ;
        RECT  67.392 2.151 67.512 41.049 ;
        RECT  61.992 2.151 62.112 41.049 ;
        RECT  56.592 2.151 56.712 41.049 ;
        RECT  51.192 2.151 51.312 41.049 ;
        RECT  45.792 2.151 45.912 41.049 ;
        RECT  40.392 2.151 40.512 41.049 ;
        RECT  34.992 2.151 35.112 41.049 ;
        RECT  29.592 2.151 29.712 41.049 ;
        RECT  24.192 2.151 24.312 41.049 ;
        RECT  18.792 2.151 18.912 41.049 ;
        RECT  13.392 2.151 13.512 41.049 ;
        RECT  7.992 2.151 8.112 41.049 ;
        RECT  2.592 2.151 2.712 41.049 ;
    END
  END VDD
  PIN VSS
    DIRECTION INOUT ;
    USE GROUND ;
    PORT
      LAYER M5 ;
        RECT  115.8 2.137 115.92 41.063 ;
        RECT  110.4 2.137 110.52 41.063 ;
        RECT  105 2.137 105.12 41.063 ;
        RECT  99.6 2.137 99.72 41.063 ;
        RECT  94.2 2.137 94.32 41.063 ;
        RECT  88.8 2.137 88.92 41.063 ;
        RECT  83.4 2.137 83.52 41.063 ;
        RECT  78 2.137 78.12 41.063 ;
        RECT  72.6 2.137 72.72 41.063 ;
        RECT  67.2 2.137 67.32 41.063 ;
        RECT  61.8 2.137 61.92 41.063 ;
        RECT  56.4 2.137 56.52 41.063 ;
        RECT  51 2.137 51.12 41.063 ;
        RECT  45.6 2.137 45.72 41.063 ;
        RECT  40.2 2.137 40.32 41.063 ;
        RECT  34.8 2.137 34.92 41.063 ;
        RECT  29.4 2.137 29.52 41.063 ;
        RECT  24 2.137 24.12 41.063 ;
        RECT  18.6 2.137 18.72 41.063 ;
        RECT  13.2 2.137 13.32 41.063 ;
        RECT  7.8 2.137 7.92 41.063 ;
        RECT  2.4 2.137 2.52 41.063 ;
    END
  END VSS
  OBS
    LAYER RVTN ;
     RECT  2.16 2.16 118.8 2.295 ;
     RECT  2.16 2.565 118.8 2.835 ;
     RECT  2.16 3.105 118.8 3.375 ;
     RECT  2.16 3.645 118.8 3.915 ;
     RECT  2.16 4.185 118.8 4.455 ;
     RECT  2.16 4.725 118.8 4.995 ;
     RECT  2.16 5.265 118.8 5.535 ;
     RECT  2.16 5.805 118.8 6.075 ;
     RECT  2.16 6.345 118.8 6.615 ;
     RECT  2.16 6.885 118.8 7.155 ;
     RECT  2.16 7.425 118.8 7.695 ;
     RECT  2.16 7.965 118.8 8.235 ;
     RECT  2.16 8.505 118.8 8.775 ;
     RECT  2.16 9.045 118.8 9.315 ;
     RECT  2.16 9.585 118.8 9.855 ;
     RECT  2.16 10.125 118.8 10.395 ;
     RECT  2.16 10.665 118.8 10.935 ;
     RECT  2.16 11.205 118.8 11.475 ;
     RECT  2.16 11.745 118.8 12.015 ;
     RECT  2.16 12.285 118.8 12.555 ;
     RECT  2.16 12.825 118.8 13.095 ;
     RECT  2.16 13.365 118.8 13.635 ;
     RECT  2.16 13.905 118.8 14.175 ;
     RECT  2.16 14.445 118.8 14.715 ;
     RECT  2.16 14.985 118.8 15.255 ;
     RECT  2.16 15.525 118.8 15.795 ;
     RECT  2.16 16.065 118.8 16.335 ;
     RECT  2.16 16.605 118.8 16.875 ;
     RECT  2.16 17.145 118.8 17.415 ;
     RECT  2.16 17.685 118.8 17.955 ;
     RECT  2.16 18.225 118.8 18.495 ;
     RECT  2.16 18.765 118.8 19.035 ;
     RECT  2.16 19.305 118.8 19.575 ;
     RECT  2.16 19.845 118.8 20.115 ;
     RECT  2.16 20.385 118.8 20.655 ;
     RECT  2.16 20.925 118.8 21.195 ;
     RECT  2.16 21.465 118.8 21.735 ;
     RECT  2.16 22.005 118.8 22.275 ;
     RECT  2.16 22.545 118.8 22.815 ;
     RECT  2.16 23.085 118.8 23.355 ;
     RECT  2.16 23.625 118.8 23.895 ;
     RECT  2.16 24.165 118.8 24.435 ;
     RECT  2.16 24.705 118.8 24.975 ;
     RECT  2.16 25.245 118.8 25.515 ;
     RECT  2.16 25.785 118.8 26.055 ;
     RECT  2.16 26.325 118.8 26.595 ;
     RECT  2.16 26.865 118.8 27.135 ;
     RECT  2.16 27.405 118.8 27.675 ;
     RECT  2.16 27.945 118.8 28.215 ;
     RECT  2.16 28.485 118.8 28.755 ;
     RECT  2.16 29.025 118.8 29.295 ;
     RECT  2.16 29.565 118.8 29.835 ;
     RECT  2.16 30.105 118.8 30.375 ;
     RECT  2.16 30.645 118.8 30.915 ;
     RECT  2.16 31.185 118.8 31.455 ;
     RECT  2.16 31.725 118.8 31.995 ;
     RECT  2.16 32.265 118.8 32.535 ;
     RECT  2.16 32.805 118.8 33.075 ;
     RECT  2.16 33.345 118.8 33.615 ;
     RECT  2.16 33.885 118.8 34.155 ;
     RECT  2.16 34.425 118.8 34.695 ;
     RECT  2.16 34.965 118.8 35.235 ;
     RECT  2.16 35.505 118.8 35.775 ;
     RECT  2.16 36.045 118.8 36.315 ;
     RECT  2.16 36.585 118.8 36.855 ;
     RECT  2.16 37.125 118.8 37.395 ;
     RECT  2.16 37.665 118.8 37.935 ;
     RECT  2.16 38.205 118.8 38.475 ;
     RECT  2.16 38.745 118.8 39.015 ;
     RECT  2.16 39.285 118.8 39.555 ;
     RECT  2.16 39.825 118.8 40.095 ;
     RECT  2.16 40.365 118.8 40.635 ;
     RECT  2.16 40.905 118.8 41.04 ;
    LAYER RVTP ;
     RECT  2.16 2.295 118.8 2.565 ;
     RECT  2.16 2.835 118.8 3.105 ;
     RECT  2.16 3.375 118.8 3.645 ;
     RECT  2.16 3.915 118.8 4.185 ;
     RECT  2.16 4.455 118.8 4.725 ;
     RECT  2.16 4.995 118.8 5.265 ;
     RECT  2.16 5.535 118.8 5.805 ;
     RECT  2.16 6.075 118.8 6.345 ;
     RECT  2.16 6.615 118.8 6.885 ;
     RECT  2.16 7.155 118.8 7.425 ;
     RECT  2.16 7.695 118.8 7.965 ;
     RECT  2.16 8.235 118.8 8.505 ;
     RECT  2.16 8.775 118.8 9.045 ;
     RECT  2.16 9.315 118.8 9.585 ;
     RECT  2.16 9.855 118.8 10.125 ;
     RECT  2.16 10.395 118.8 10.665 ;
     RECT  2.16 10.935 118.8 11.205 ;
     RECT  2.16 11.475 118.8 11.745 ;
     RECT  2.16 12.015 118.8 12.285 ;
     RECT  2.16 12.555 118.8 12.825 ;
     RECT  2.16 13.095 118.8 13.365 ;
     RECT  2.16 13.635 118.8 13.905 ;
     RECT  2.16 14.175 118.8 14.445 ;
     RECT  2.16 14.715 118.8 14.985 ;
     RECT  2.16 15.255 118.8 15.525 ;
     RECT  2.16 15.795 118.8 16.065 ;
     RECT  2.16 16.335 118.8 16.605 ;
     RECT  2.16 16.875 118.8 17.145 ;
     RECT  2.16 17.415 118.8 17.685 ;
     RECT  2.16 17.955 118.8 18.225 ;
     RECT  2.16 18.495 118.8 18.765 ;
     RECT  2.16 19.035 118.8 19.305 ;
     RECT  2.16 19.575 118.8 19.845 ;
     RECT  2.16 20.115 118.8 20.385 ;
     RECT  2.16 20.655 118.8 20.925 ;
     RECT  2.16 21.195 118.8 21.465 ;
     RECT  2.16 21.735 118.8 22.005 ;
     RECT  2.16 22.275 118.8 22.545 ;
     RECT  2.16 22.815 118.8 23.085 ;
     RECT  2.16 23.355 118.8 23.625 ;
     RECT  2.16 23.895 118.8 24.165 ;
     RECT  2.16 24.435 118.8 24.705 ;
     RECT  2.16 24.975 118.8 25.245 ;
     RECT  2.16 25.515 118.8 25.785 ;
     RECT  2.16 26.055 118.8 26.325 ;
     RECT  2.16 26.595 118.8 26.865 ;
     RECT  2.16 27.135 118.8 27.405 ;
     RECT  2.16 27.675 118.8 27.945 ;
     RECT  2.16 28.215 118.8 28.485 ;
     RECT  2.16 28.755 118.8 29.025 ;
     RECT  2.16 29.295 118.8 29.565 ;
     RECT  2.16 29.835 118.8 30.105 ;
     RECT  2.16 30.375 118.8 30.645 ;
     RECT  2.16 30.915 118.8 31.185 ;
     RECT  2.16 31.455 118.8 31.725 ;
     RECT  2.16 31.995 118.8 32.265 ;
     RECT  2.16 32.535 118.8 32.805 ;
     RECT  2.16 33.075 118.8 33.345 ;
     RECT  2.16 33.615 118.8 33.885 ;
     RECT  2.16 34.155 118.8 34.425 ;
     RECT  2.16 34.695 118.8 34.965 ;
     RECT  2.16 35.235 118.8 35.505 ;
     RECT  2.16 35.775 118.8 36.045 ;
     RECT  2.16 36.315 118.8 36.585 ;
     RECT  2.16 36.855 118.8 37.125 ;
     RECT  2.16 37.395 118.8 37.665 ;
     RECT  2.16 37.935 118.8 38.205 ;
     RECT  2.16 38.475 118.8 38.745 ;
     RECT  2.16 39.015 118.8 39.285 ;
     RECT  2.16 39.555 118.8 39.825 ;
     RECT  2.16 40.095 118.8 40.365 ;
     RECT  2.16 40.635 118.8 40.905 ;
    LAYER M1 ;
     RECT  2.16 2.151 118.8 41.049 ;
    LAYER M2 ;
     RECT  2.16 2.151 6.835 41.049 ;
     RECT  6.943 0.036 7.375 0.054 ;
     RECT  6.835 2.106 8.051 41.049 ;
     RECT  7.375 0.036 8.995 0.09 ;
     RECT  8.995 0.036 9.859 0.126 ;
     RECT  9.859 0.036 10.615 0.162 ;
     RECT  8.051 2.151 10.795 41.049 ;
     RECT  11.083 1.152 11.183 1.17 ;
     RECT  10.795 2.151 12.155 41.094 ;
     RECT  12.155 2.151 12.487 41.049 ;
     RECT  12.991 1.152 13.091 1.17 ;
     RECT  12.487 2.106 13.487 41.049 ;
     RECT  10.615 0.036 13.567 0.198 ;
     RECT  13.487 2.151 13.603 41.049 ;
     RECT  13.567 0.036 13.963 0.234 ;
     RECT  13.603 2.151 14.791 41.166 ;
     RECT  13.963 0.036 14.863 0.279 ;
     RECT  14.863 0.036 14.899 0.504 ;
     RECT  14.791 2.106 15.223 41.166 ;
     RECT  14.899 0.036 16.295 0.549 ;
     RECT  16.295 0.108 16.375 0.549 ;
     RECT  15.223 2.034 16.843 41.166 ;
     RECT  16.375 0.108 17.087 0.594 ;
     RECT  17.087 0.108 17.159 0.432 ;
     RECT  17.159 0.414 17.699 0.432 ;
     RECT  16.843 1.962 18.851 41.166 ;
     RECT  19.039 1.152 19.751 1.17 ;
     RECT  18.851 1.962 19.823 41.049 ;
     RECT  19.823 2.07 20.543 41.049 ;
     RECT  35.203 0.108 35.527 0.126 ;
     RECT  35.527 0.072 36.391 0.126 ;
     RECT  36.391 0.036 39.451 0.126 ;
     RECT  39.451 0.036 39.559 0.162 ;
     RECT  39.559 0.036 40.675 0.198 ;
     RECT  40.675 0.036 40.963 0.234 ;
     RECT  20.543 2.151 41.575 41.049 ;
     RECT  41.575 2.106 42.359 41.049 ;
     RECT  42.359 2.151 43.843 41.049 ;
     RECT  43.843 2.034 44.347 41.049 ;
     RECT  40.963 0.036 44.419 0.279 ;
     RECT  44.419 0.036 44.455 0.504 ;
     RECT  44.347 2.034 44.627 41.13 ;
     RECT  44.455 0.036 44.987 1.17 ;
     RECT  44.987 0.036 45.311 0.594 ;
     RECT  44.627 2.034 45.427 41.049 ;
     RECT  45.427 2.034 46.111 41.094 ;
     RECT  45.311 0.036 46.931 0.549 ;
     RECT  46.931 0.036 47.111 0.279 ;
     RECT  46.111 1.998 47.327 41.094 ;
     RECT  47.111 0.108 48.271 0.279 ;
     RECT  48.271 0.108 50.567 0.549 ;
     RECT  47.327 1.998 50.639 41.049 ;
     RECT  50.567 0.108 50.819 0.126 ;
     RECT  50.639 2.151 66.595 41.049 ;
     RECT  66.595 2.106 66.703 41.049 ;
     RECT  66.703 1.998 71.023 41.049 ;
     RECT  71.023 1.998 71.231 41.094 ;
     RECT  71.311 0.108 71.383 0.126 ;
     RECT  71.231 2.106 71.591 41.094 ;
     RECT  71.383 0.072 71.959 0.126 ;
     RECT  71.959 0.072 72.031 0.432 ;
     RECT  71.591 2.151 72.211 41.094 ;
     RECT  72.211 2.151 72.751 41.274 ;
     RECT  72.031 0.072 73.039 0.504 ;
     RECT  73.039 0.072 73.327 0.549 ;
     RECT  72.751 2.151 73.571 41.319 ;
     RECT  73.327 0.036 74.147 0.549 ;
     RECT  74.147 0.036 74.255 0.432 ;
     RECT  74.255 0.036 74.543 0.36 ;
     RECT  74.543 0.036 74.759 0.279 ;
     RECT  74.759 0.036 75.083 0.234 ;
     RECT  75.083 0.036 75.991 0.09 ;
     RECT  75.991 0.036 76.207 0.504 ;
     RECT  73.571 2.151 77.999 41.166 ;
     RECT  76.207 0.036 78.863 0.549 ;
     RECT  78.863 0.036 79.655 0.054 ;
     RECT  77.999 2.151 91.615 41.049 ;
     RECT  96.871 0.036 97.267 0.054 ;
     RECT  97.267 0.036 99.391 0.09 ;
     RECT  91.615 2.106 100.111 41.049 ;
     RECT  99.391 0.036 101.767 0.126 ;
     RECT  100.111 2.106 103.495 41.094 ;
     RECT  101.767 0.036 103.855 0.162 ;
     RECT  103.855 0.036 104.431 0.504 ;
     RECT  103.495 1.998 105.503 41.094 ;
     RECT  105.503 1.998 105.611 41.049 ;
     RECT  104.431 0.036 106.511 0.549 ;
     RECT  106.511 0.072 106.799 0.549 ;
     RECT  106.799 0.486 106.907 0.549 ;
     RECT  106.907 0.486 107.303 0.504 ;
     RECT  105.611 2.106 108.635 41.049 ;
     RECT  108.635 2.151 118.8 41.049 ;
     RECT  118.8 19.746 119.687 20.142 ;
     RECT  119.687 19.746 120.299 19.764 ;
    LAYER M3 ;
     RECT  106.488 0.031 106.506 0.043 ;
     RECT  6.948 0.031 6.966 0.067 ;
     RECT  7.74 0.043 7.758 0.067 ;
     RECT  16.272 0.031 16.29 0.067 ;
     RECT  96.876 0.031 96.894 0.067 ;
     RECT  106.128 0.043 106.506 0.067 ;
     RECT  13.968 0.043 13.986 0.091 ;
     RECT  15.336 0.043 15.354 0.091 ;
     RECT  16.2 0.067 16.29 0.091 ;
     RECT  17.208 0.043 17.226 0.091 ;
     RECT  44.82 0.043 44.838 0.091 ;
     RECT  46.188 0.067 46.206 0.091 ;
     RECT  47.088 0.031 47.106 0.091 ;
     RECT  73.332 0.031 73.35 0.091 ;
     RECT  106.128 0.067 106.794 0.091 ;
     RECT  108.54 0.043 108.558 0.091 ;
     RECT  113.292 0.043 113.31 0.091 ;
     RECT  8.532 0.091 8.55 0.103 ;
     RECT  35.532 0.067 35.55 0.103 ;
     RECT  71.388 0.067 71.406 0.103 ;
     RECT  75.492 0.067 75.51 0.103 ;
     RECT  19.188 0.091 19.206 0.139 ;
     RECT  39.24 0.043 39.258 0.139 ;
     RECT  40.176 0.091 40.194 0.139 ;
     RECT  44.568 0.091 47.106 0.139 ;
     RECT  48.492 0.091 48.51 0.139 ;
     RECT  79.632 0.031 79.65 0.139 ;
     RECT  103.536 0.091 103.554 0.139 ;
     RECT  6.948 0.067 7.758 0.187 ;
     RECT  8.532 0.103 9.018 0.187 ;
     RECT  18.936 0.139 19.206 0.187 ;
     RECT  49.788 0.043 49.806 0.187 ;
     RECT  50.796 0.103 50.814 0.187 ;
     RECT  103.356 0.139 103.554 0.187 ;
     RECT  109.296 0.091 109.314 0.187 ;
     RECT  39.24 0.139 40.194 0.211 ;
     RECT  15.336 0.091 17.874 0.221 ;
     RECT  9.864 0.139 9.882 0.235 ;
     RECT  10.62 0.175 10.638 0.235 ;
     RECT  12.996 0.091 13.986 0.235 ;
     RECT  102.636 0.187 103.554 0.235 ;
     RECT  105.624 0.091 108.558 0.235 ;
     RECT  39.24 0.211 40.698 0.256 ;
     RECT  44.568 0.139 47.358 0.256 ;
     RECT  48.492 0.139 48.87 0.256 ;
     RECT  74.916 0.103 75.51 0.256 ;
     RECT  18.936 0.187 19.674 0.283 ;
     RECT  49.788 0.187 50.814 0.283 ;
     RECT  73.332 0.091 73.818 0.283 ;
     RECT  78.876 0.187 78.894 0.283 ;
     RECT  101.304 0.139 101.79 0.283 ;
     RECT  109.296 0.187 109.458 0.283 ;
     RECT  21.348 0.139 21.366 0.331 ;
     RECT  77.58 0.235 77.598 0.331 ;
     RECT  105.516 0.235 108.558 0.331 ;
     RECT  109.296 0.283 109.638 0.331 ;
     RECT  73.332 0.283 73.962 0.337 ;
     RECT  74.736 0.256 75.51 0.337 ;
     RECT  12.888 0.235 13.986 0.365 ;
     RECT  9.864 0.235 10.638 0.379 ;
     RECT  18.936 0.283 20.394 0.379 ;
     RECT  71.316 0.103 71.406 0.409 ;
     RECT  72.144 0.337 72.162 0.409 ;
     RECT  76.536 0.331 77.598 0.409 ;
     RECT  71.316 0.409 72.162 0.427 ;
     RECT  73.332 0.337 75.51 0.461 ;
     RECT  76.284 0.409 77.598 0.472 ;
     RECT  9.864 0.379 11.106 0.475 ;
     RECT  21.348 0.331 22.05 0.475 ;
     RECT  42.516 0.139 42.534 0.475 ;
     RECT  44.568 0.256 48.87 0.475 ;
     RECT  49.608 0.283 50.814 0.475 ;
     RECT  70.704 0.427 72.162 0.475 ;
     RECT  101.088 0.283 101.79 0.475 ;
     RECT  102.636 0.235 104.346 0.475 ;
     RECT  105.516 0.331 109.638 0.475 ;
     RECT  15.336 0.221 17.838 0.481 ;
     RECT  44.568 0.475 50.814 0.481 ;
     RECT  75.996 0.472 77.598 0.509 ;
     RECT  18.828 0.379 20.394 0.523 ;
     RECT  21.348 0.475 22.554 0.523 ;
     RECT  42.12 0.475 42.534 0.523 ;
     RECT  43.344 0.043 43.362 0.523 ;
     RECT  81.108 0.091 81.126 0.523 ;
     RECT  101.088 0.475 104.346 0.523 ;
     RECT  73.332 0.461 74.682 0.526 ;
     RECT  101.088 0.523 104.382 0.526 ;
     RECT  76.212 0.509 77.598 0.554 ;
     RECT  18.828 0.523 22.554 0.557 ;
     RECT  44.424 0.481 50.814 0.557 ;
     RECT  101.088 0.526 104.454 0.557 ;
     RECT  76.284 0.554 77.598 0.605 ;
     RECT  9.864 0.475 11.142 1.147 ;
     RECT  12.996 0.365 13.986 1.175 ;
     RECT  13.068 1.175 13.986 1.723 ;
     RECT  14.868 0.481 17.838 1.723 ;
     RECT  70.236 0.475 72.162 1.723 ;
     RECT  103.752 0.557 104.454 1.723 ;
     RECT  105.444 0.475 109.638 1.723 ;
     RECT  101.088 0.557 103.014 1.993 ;
     RECT  103.752 1.723 109.638 1.993 ;
     RECT  70.236 1.723 72.306 2.011 ;
     RECT  73.044 0.526 74.682 2.011 ;
     RECT  41.796 0.523 43.578 2.029 ;
     RECT  44.424 0.557 47.718 2.029 ;
     RECT  81.108 0.523 81.594 2.059 ;
     RECT  6.948 0.187 9.018 2.101 ;
     RECT  13.068 1.723 17.838 2.101 ;
     RECT  39.24 0.256 40.986 2.101 ;
     RECT  41.796 2.029 47.718 2.101 ;
     RECT  66.708 1.993 66.726 2.101 ;
     RECT  18.936 0.557 22.554 2.143 ;
     RECT  35.208 0.103 35.55 2.143 ;
     RECT  48.492 0.557 50.814 2.143 ;
     RECT  66.6 2.101 66.726 2.143 ;
     RECT  76.5 0.605 77.598 2.143 ;
     RECT  78.336 0.283 78.894 2.143 ;
     RECT  99.396 0.103 99.414 2.143 ;
     RECT  100.26 0.043 100.278 2.143 ;
     RECT  6.84 2.101 9.018 2.191 ;
     RECT  48.492 2.143 51.105 2.191 ;
     RECT  56.415 2.143 56.505 2.191 ;
     RECT  66.6 2.143 67.305 2.191 ;
     RECT  70.236 2.011 74.682 2.191 ;
     RECT  76.5 2.143 78.894 2.191 ;
     RECT  79.632 0.139 79.686 2.191 ;
     RECT  81.036 2.059 81.594 2.191 ;
     RECT  88.815 2.143 88.905 2.191 ;
     RECT  9.864 1.147 11.178 2.203 ;
     RECT  96.876 0.067 97.29 2.203 ;
     RECT  34.815 2.143 35.55 2.227 ;
     RECT  36.396 0.031 36.414 2.227 ;
     RECT  55.836 2.191 56.97 2.227 ;
     RECT  61.815 2.143 61.905 2.227 ;
     RECT  88.308 2.191 88.905 2.227 ;
     RECT  110.415 2.143 110.505 2.227 ;
     RECT  34.815 2.227 36.414 2.251 ;
     RECT  88.164 2.227 88.905 2.251 ;
     RECT  91.62 2.101 91.638 2.251 ;
     RECT  92.376 2.191 92.394 2.251 ;
     RECT  6.228 2.191 9.018 2.263 ;
     RECT  24.015 2.143 24.105 2.263 ;
     RECT  33.912 2.227 33.93 2.263 ;
     RECT  39.24 2.101 47.718 2.263 ;
     RECT  48.492 2.191 51.354 2.263 ;
     RECT  53.928 2.191 54.162 2.263 ;
     RECT  75.492 2.191 78.894 2.263 ;
     RECT  79.632 2.191 82.206 2.263 ;
     RECT  96.876 2.203 98.478 2.263 ;
     RECT  3.384 2.227 3.402 2.285 ;
     RECT  87.3 2.227 87.318 2.285 ;
     RECT  4.788 2.191 4.806 2.299 ;
     RECT  6.156 2.263 9.018 2.299 ;
     RECT  9.864 2.203 11.466 2.299 ;
     RECT  23.58 2.263 24.105 2.299 ;
     RECT  37.728 2.227 37.746 2.299 ;
     RECT  53.856 2.263 54.162 2.299 ;
     RECT  68.724 0.523 68.742 2.299 ;
     RECT  69.984 2.191 74.682 2.299 ;
     RECT  99.396 2.143 100.278 2.299 ;
     RECT  101.088 1.993 109.638 2.299 ;
     RECT  115.815 2.143 115.905 2.299 ;
     RECT  53.856 2.299 54.378 2.333 ;
     RECT  6.012 2.299 9.018 2.335 ;
     RECT  9.864 2.299 11.502 2.335 ;
     RECT  23.58 2.299 24.39 2.335 ;
     RECT  27.108 2.299 27.126 2.335 ;
     RECT  27.972 2.263 27.99 2.335 ;
     RECT  60.984 2.227 61.905 2.335 ;
     RECT  66.384 2.191 67.914 2.335 ;
     RECT  68.724 2.299 74.682 2.335 ;
     RECT  75.492 2.263 82.206 2.335 ;
     RECT  94.215 2.143 94.305 2.335 ;
     RECT  95.256 2.191 95.274 2.335 ;
     RECT  4.464 2.299 4.806 2.371 ;
     RECT  5.544 2.335 11.502 2.371 ;
     RECT  12.492 2.101 17.838 2.371 ;
     RECT  18.615 2.143 22.554 2.371 ;
     RECT  27.108 2.335 27.99 2.371 ;
     RECT  29.415 2.143 29.505 2.371 ;
     RECT  33.12 2.263 33.138 2.371 ;
     RECT  33.912 2.263 34.038 2.371 ;
     RECT  34.815 2.251 36.774 2.371 ;
     RECT  37.584 2.299 37.746 2.371 ;
     RECT  39.24 2.263 51.354 2.371 ;
     RECT  52.632 2.227 52.65 2.371 ;
     RECT  53.928 2.333 54.378 2.371 ;
     RECT  55.116 2.227 57.546 2.371 ;
     RECT  60.84 2.335 61.905 2.371 ;
     RECT  62.64 2.299 62.658 2.371 ;
     RECT  64.404 2.227 64.422 2.371 ;
     RECT  65.34 2.191 65.358 2.371 ;
     RECT  66.384 2.335 82.206 2.371 ;
     RECT  83.415 2.143 83.505 2.371 ;
     RECT  88.164 2.251 89.406 2.371 ;
     RECT  91.62 2.251 92.394 2.371 ;
     RECT  94.215 2.335 95.274 2.371 ;
     RECT  96.876 2.263 98.622 2.371 ;
     RECT  99.396 2.299 109.638 2.371 ;
     RECT  110.415 2.227 110.574 2.371 ;
     RECT  111.384 0.139 111.402 2.371 ;
     RECT  114.588 2.299 115.905 2.371 ;
     RECT  2.415 2.143 2.505 2.413 ;
     RECT  26.46 2.371 29.574 2.413 ;
     RECT  82.944 2.371 83.505 2.413 ;
     RECT  114.336 2.371 115.974 2.413 ;
     RECT  94.215 2.371 95.886 2.461 ;
     RECT  96.876 2.371 109.638 2.461 ;
     RECT  30.78 2.461 30.798 2.491 ;
     RECT  34.815 2.371 52.65 2.491 ;
     RECT  86.148 2.371 86.166 2.491 ;
     RECT  3.456 2.371 3.582 2.497 ;
     RECT  4.32 2.371 22.554 2.497 ;
     RECT  23.58 2.335 24.93 2.497 ;
     RECT  64.404 2.371 65.358 2.497 ;
     RECT  66.204 2.371 82.206 2.497 ;
     RECT  82.944 2.413 83.697 2.497 ;
     RECT  84.492 2.491 84.618 2.497 ;
     RECT  85.896 2.491 86.166 2.497 ;
     RECT  90.324 2.371 90.45 2.497 ;
     RECT  91.62 2.371 93.15 2.497 ;
     RECT  94.215 2.461 109.638 2.497 ;
     RECT  110.376 2.371 111.654 2.497 ;
     RECT  112.608 0.091 113.31 2.497 ;
     RECT  117.54 2.461 117.558 2.497 ;
     RECT  63.648 2.299 63.666 2.533 ;
     RECT  64.404 2.497 84.618 2.533 ;
     RECT  88.092 2.371 89.586 2.533 ;
     RECT  90.324 2.497 90.666 2.533 ;
     RECT  3.456 2.497 22.554 2.569 ;
     RECT  23.58 2.497 25.002 2.569 ;
     RECT  30.78 2.491 31.338 2.569 ;
     RECT  53.928 2.371 57.546 2.569 ;
     RECT  63.648 2.533 84.618 2.569 ;
     RECT  91.404 2.497 93.15 2.569 ;
     RECT  3.456 2.569 22.842 2.605 ;
     RECT  23.58 2.569 25.398 2.605 ;
     RECT  26.46 2.413 29.697 2.605 ;
     RECT  30.636 2.569 31.338 2.605 ;
     RECT  34.776 2.491 52.65 2.605 ;
     RECT  85.896 2.497 86.238 2.605 ;
     RECT  88.092 2.533 90.666 2.605 ;
     RECT  91.404 2.569 93.294 2.605 ;
     RECT  3.456 2.605 29.697 2.641 ;
     RECT  30.6 2.605 31.338 2.641 ;
     RECT  33.12 2.371 34.038 2.641 ;
     RECT  34.776 2.605 52.902 2.641 ;
     RECT  60.84 2.371 62.658 2.641 ;
     RECT  63.648 2.569 84.978 2.641 ;
     RECT  85.896 2.605 86.31 2.641 ;
     RECT  114.336 2.413 116.097 2.641 ;
     RECT  117.072 2.497 117.558 2.641 ;
     RECT  3.456 2.641 31.338 2.669 ;
     RECT  53.928 2.569 58.194 2.669 ;
     RECT  26.064 2.669 31.338 2.731 ;
     RECT  26.064 2.731 31.59 2.759 ;
     RECT  32.832 2.641 52.902 2.759 ;
     RECT  63.468 2.641 84.978 2.759 ;
     RECT  60.804 2.641 62.658 2.767 ;
     RECT  63.468 2.759 84.654 2.767 ;
     RECT  94.215 2.497 113.31 2.767 ;
     RECT  114.336 2.641 117.558 2.767 ;
     RECT  88.092 2.605 93.366 2.779 ;
     RECT  94.212 2.767 113.31 2.779 ;
     RECT  32.832 2.759 38.322 2.795 ;
     RECT  56.196 2.669 58.194 2.795 ;
     RECT  85.896 2.641 86.85 2.803 ;
     RECT  88.092 2.779 113.31 2.827 ;
     RECT  114.3 2.767 117.558 2.827 ;
     RECT  39.06 2.759 52.902 2.831 ;
     RECT  56.304 2.795 58.194 2.861 ;
     RECT  59.868 2.605 59.886 2.875 ;
     RECT  60.804 2.767 84.654 2.875 ;
     RECT  88.092 2.827 117.558 2.911 ;
     RECT  27.972 2.759 31.59 2.939 ;
     RECT  59.868 2.875 84.654 2.939 ;
     RECT  32.832 2.795 38.214 3.029 ;
     RECT  39.24 2.831 52.866 3.029 ;
     RECT  85.752 2.803 86.85 3.029 ;
     RECT  26.064 2.759 27.234 3.065 ;
     RECT  32.832 3.029 38.142 3.065 ;
     RECT  39.24 3.029 52.686 3.065 ;
     RECT  26.064 3.065 27.126 3.137 ;
     RECT  88.092 2.911 117.666 3.145 ;
     RECT  3.456 2.669 25.254 3.181 ;
     RECT  53.928 2.669 55.314 3.181 ;
     RECT  85.788 3.029 86.85 3.181 ;
     RECT  87.84 3.145 117.666 3.181 ;
     RECT  53.82 3.181 55.314 3.259 ;
     RECT  32.832 3.065 37.89 3.299 ;
     RECT  2.415 2.413 2.697 3.307 ;
     RECT  56.304 2.861 57.582 3.335 ;
     RECT  59.868 2.939 79.794 3.335 ;
     RECT  2.412 3.307 2.697 3.344 ;
     RECT  59.112 2.827 59.13 3.415 ;
     RECT  59.868 3.335 79.722 3.415 ;
     RECT  53.64 3.259 55.314 3.613 ;
     RECT  56.412 3.335 57.582 3.685 ;
     RECT  80.532 2.939 84.654 3.685 ;
     RECT  3.42 3.181 25.254 3.721 ;
     RECT  26.064 3.137 26.982 3.721 ;
     RECT  59.112 3.415 79.722 3.721 ;
     RECT  56.412 3.685 57.618 3.725 ;
     RECT  33.336 3.299 37.89 3.811 ;
     RECT  53.46 3.613 55.314 3.847 ;
     RECT  85.788 3.181 117.666 3.875 ;
     RECT  3.42 3.721 26.982 3.919 ;
     RECT  27.972 2.939 31.518 3.919 ;
     RECT  59.04 3.721 79.722 3.931 ;
     RECT  3.42 3.919 31.518 3.955 ;
     RECT  39.24 3.065 52.65 3.955 ;
     RECT  53.46 3.847 55.638 3.955 ;
     RECT  87.804 3.875 117.666 3.983 ;
     RECT  2.415 3.344 2.697 3.991 ;
     RECT  3.42 3.955 31.698 3.991 ;
     RECT  2.415 3.991 31.698 4.075 ;
     RECT  33.336 3.811 38.178 4.081 ;
     RECT  39.24 3.955 55.638 4.081 ;
     RECT  80.532 3.685 84.726 4.117 ;
     RECT  85.788 3.875 86.706 4.117 ;
     RECT  33.336 4.081 55.638 4.225 ;
     RECT  2.415 4.075 31.77 4.253 ;
     RECT  56.415 3.725 57.618 4.261 ;
     RECT  58.896 3.931 79.722 4.261 ;
     RECT  56.415 4.261 79.722 4.351 ;
     RECT  80.532 4.117 86.706 4.379 ;
     RECT  56.415 4.351 79.794 4.649 ;
     RECT  27.9 4.253 31.77 4.657 ;
     RECT  33.084 4.225 55.638 4.657 ;
     RECT  87.876 3.983 117.666 4.657 ;
     RECT  80.568 4.379 86.706 4.693 ;
     RECT  2.415 4.253 27.018 4.733 ;
     RECT  58.86 4.649 79.794 4.801 ;
     RECT  80.568 4.693 86.958 4.801 ;
     RECT  87.876 4.657 117.81 4.801 ;
     RECT  58.86 4.801 79.83 4.877 ;
     RECT  80.568 4.801 117.846 4.877 ;
     RECT  4.788 4.733 27.018 4.919 ;
     RECT  58.86 4.877 63.162 4.919 ;
     RECT  27.9 4.657 55.638 4.927 ;
     RECT  56.415 4.649 57.942 4.927 ;
     RECT  27.9 4.927 57.942 4.955 ;
     RECT  32.904 4.955 57.942 4.991 ;
     RECT  32.904 4.991 57.546 5.027 ;
     RECT  5.04 4.919 27.018 5.071 ;
     RECT  27.9 4.955 32.094 5.071 ;
     RECT  32.904 5.027 57.51 5.099 ;
     RECT  80.568 4.877 87.138 5.165 ;
     RECT  58.86 4.919 63.09 5.189 ;
     RECT  33.12 5.099 57.51 5.357 ;
     RECT  63.9 4.877 79.83 5.503 ;
     RECT  80.568 5.165 86.958 5.503 ;
     RECT  58.86 5.189 62.838 5.575 ;
     RECT  87.876 4.877 117.846 5.611 ;
     RECT  33.12 5.357 38.214 5.645 ;
     RECT  63.9 5.503 86.958 5.707 ;
     RECT  87.768 5.611 117.882 5.729 ;
     RECT  39.096 5.357 57.51 5.809 ;
     RECT  2.415 4.733 3.906 5.881 ;
     RECT  5.04 5.071 32.094 5.881 ;
     RECT  39.096 5.809 57.546 5.881 ;
     RECT  58.752 5.575 62.838 5.998 ;
     RECT  39.096 5.881 57.582 5.999 ;
     RECT  5.04 5.881 32.238 6.241 ;
     RECT  58.752 5.998 62.874 6.269 ;
     RECT  63.612 5.707 86.958 6.269 ;
     RECT  58.752 6.269 62.262 6.275 ;
     RECT  87.768 5.729 117.846 6.305 ;
     RECT  63.612 6.269 82.278 6.379 ;
     RECT  5.04 6.241 32.49 6.385 ;
     RECT  33.336 5.645 38.214 6.385 ;
     RECT  54.072 5.999 57.582 6.385 ;
     RECT  2.415 5.881 4.122 6.421 ;
     RECT  5.04 6.385 38.214 6.421 ;
     RECT  88.272 6.305 117.846 6.511 ;
     RECT  39.096 5.999 53.334 6.547 ;
     RECT  54.072 6.385 57.618 6.575 ;
     RECT  2.415 6.421 38.214 6.583 ;
     RECT  38.988 6.547 53.334 6.583 ;
     RECT  88.272 6.511 117.882 6.691 ;
     RECT  88.272 6.691 117.99 6.701 ;
     RECT  59.148 6.275 62.262 6.809 ;
     RECT  98.856 6.701 117.99 6.817 ;
     RECT  54.144 6.575 57.618 6.889 ;
     RECT  83.088 6.269 86.958 6.925 ;
     RECT  98.856 6.817 118.062 6.953 ;
     RECT  83.088 6.925 87.246 7.087 ;
     RECT  88.272 6.701 98.118 7.087 ;
     RECT  59.148 6.809 62.19 7.151 ;
     RECT  59.148 7.151 62.097 7.231 ;
     RECT  2.415 6.583 53.334 7.349 ;
     RECT  83.088 7.087 98.118 7.357 ;
     RECT  58.788 7.231 62.097 7.387 ;
     RECT  32.868 7.349 53.334 7.465 ;
     RECT  54.144 6.889 57.69 7.465 ;
     RECT  58.608 7.387 62.097 7.493 ;
     RECT  83.052 7.357 98.118 7.501 ;
     RECT  98.856 6.953 117.954 7.501 ;
     RECT  32.868 7.465 57.726 7.699 ;
     RECT  63.036 6.379 82.278 7.735 ;
     RECT  83.052 7.501 117.954 7.735 ;
     RECT  32.868 7.699 57.762 7.771 ;
     RECT  2.415 7.349 31.914 7.861 ;
     RECT  63.036 7.735 117.954 7.889 ;
     RECT  59.22 7.493 62.097 7.925 ;
     RECT  116.82 7.889 117.954 7.925 ;
     RECT  59.292 7.925 62.097 7.933 ;
     RECT  65.16 7.889 116.097 7.949 ;
     RECT  65.16 7.949 89.097 7.997 ;
     RECT  32.868 7.771 58.014 8.033 ;
     RECT  116.856 7.925 117.954 8.069 ;
     RECT  63.036 7.889 64.386 8.155 ;
     RECT  116.856 8.069 117.918 8.159 ;
     RECT  65.16 7.997 87.966 8.333 ;
     RECT  32.868 8.033 57.762 8.465 ;
     RECT  89.856 7.949 116.097 8.537 ;
     RECT  2.376 7.861 31.914 8.545 ;
     RECT  63 8.155 64.386 8.573 ;
     RECT  59.292 7.933 62.154 8.581 ;
     RECT  2.376 8.545 32.058 8.699 ;
     RECT  63.432 8.573 64.386 8.779 ;
     RECT  65.16 8.333 83.79 8.779 ;
     RECT  4.716 8.699 32.058 8.815 ;
     RECT  32.868 8.465 57.654 8.815 ;
     RECT  84.564 8.333 87.966 8.815 ;
     RECT  88.815 7.997 89.097 8.815 ;
     RECT  59.292 8.581 62.586 8.851 ;
     RECT  84.564 8.815 89.097 8.851 ;
     RECT  89.856 8.537 91.458 8.851 ;
     RECT  2.376 8.699 3.834 8.969 ;
     RECT  4.716 8.815 57.654 8.969 ;
     RECT  84.564 8.851 91.458 8.969 ;
     RECT  58.608 8.851 62.586 8.971 ;
     RECT  32.472 8.969 32.49 9.005 ;
     RECT  92.34 8.537 116.097 9.049 ;
     RECT  116.892 8.159 117.918 9.049 ;
     RECT  63.432 8.779 83.79 9.113 ;
     RECT  63.72 9.113 83.79 9.121 ;
     RECT  84.564 8.969 87.966 9.121 ;
     RECT  63.72 9.121 87.966 9.311 ;
     RECT  92.34 9.049 117.918 9.311 ;
     RECT  33.408 8.969 57.654 9.349 ;
     RECT  58.464 8.971 62.586 9.349 ;
     RECT  88.815 8.969 91.458 9.391 ;
     RECT  92.34 9.311 117.594 9.391 ;
     RECT  118.656 9.355 118.674 9.509 ;
     RECT  2.412 8.969 3.834 9.517 ;
     RECT  4.716 8.969 31.734 9.517 ;
     RECT  2.412 9.517 31.734 9.653 ;
     RECT  88.815 9.391 117.594 9.689 ;
     RECT  33.408 9.349 62.586 9.691 ;
     RECT  83.34 9.311 87.966 9.691 ;
     RECT  88.815 9.689 95.598 9.691 ;
     RECT  33.408 9.691 62.91 9.815 ;
     RECT  54.756 9.815 62.91 9.931 ;
     RECT  63.72 9.311 82.278 9.931 ;
     RECT  27.9 9.653 31.734 10.049 ;
     RECT  54.756 9.931 82.278 10.049 ;
     RECT  33.408 9.815 54.018 10.165 ;
     RECT  83.34 9.691 95.598 10.165 ;
     RECT  96.444 9.689 117.594 10.165 ;
     RECT  64.548 10.049 82.278 10.201 ;
     RECT  83.232 10.165 95.598 10.201 ;
     RECT  96.444 10.165 117.774 10.201 ;
     RECT  64.548 10.201 95.598 10.459 ;
     RECT  64.548 10.459 95.706 10.471 ;
     RECT  96.444 10.201 117.846 10.471 ;
     RECT  33.228 10.165 54.018 10.493 ;
     RECT  27.972 10.049 31.734 10.561 ;
     RECT  64.548 10.471 117.882 10.589 ;
     RECT  37.944 10.493 54.018 10.597 ;
     RECT  54.756 10.049 63.774 10.597 ;
     RECT  82.908 10.589 117.882 10.625 ;
     RECT  96.264 10.625 117.882 10.781 ;
     RECT  37.944 10.597 63.774 10.859 ;
     RECT  27.972 10.561 32.094 10.895 ;
     RECT  37.944 10.859 59.13 10.895 ;
     RECT  27.972 10.895 31.986 10.967 ;
     RECT  27.972 10.967 31.95 10.975 ;
     RECT  2.415 9.653 27.018 11.011 ;
     RECT  42.156 10.895 59.13 11.021 ;
     RECT  27.9 10.975 31.95 11.129 ;
     RECT  37.944 10.895 41.382 11.165 ;
     RECT  59.976 10.859 63.774 11.209 ;
     RECT  64.548 10.589 82.062 11.209 ;
     RECT  33.228 10.493 37.206 11.245 ;
     RECT  37.944 11.165 41.31 11.245 ;
     RECT  33.228 11.245 41.31 11.275 ;
     RECT  96.372 10.781 117.882 11.281 ;
     RECT  2.415 11.011 27.09 11.371 ;
     RECT  27.9 11.129 31.842 11.371 ;
     RECT  33.048 11.275 41.31 11.399 ;
     RECT  59.976 11.209 82.062 11.407 ;
     RECT  82.908 10.625 95.49 11.407 ;
     RECT  59.976 11.407 95.49 11.551 ;
     RECT  96.372 11.281 117.99 11.551 ;
     RECT  59.976 11.551 117.99 11.813 ;
     RECT  84.888 11.813 117.99 11.849 ;
     RECT  42.156 11.021 58.59 11.938 ;
     RECT  84.888 11.849 117.702 11.939 ;
     RECT  42.12 11.938 58.59 11.947 ;
     RECT  59.976 11.813 84.15 11.947 ;
     RECT  84.888 11.939 117.666 11.981 ;
     RECT  33.336 11.399 41.31 12.181 ;
     RECT  2.415 11.371 31.842 12.361 ;
     RECT  33.192 12.181 41.31 12.361 ;
     RECT  84.888 11.981 91.602 12.413 ;
     RECT  2.415 12.361 41.31 12.479 ;
     RECT  42.12 11.947 84.15 12.479 ;
     RECT  66.024 12.479 84.15 12.551 ;
     RECT  32.652 12.479 33.21 12.557 ;
     RECT  34.164 12.479 41.31 12.559 ;
     RECT  42.12 12.479 65.286 12.559 ;
     RECT  66.096 12.551 84.15 12.631 ;
     RECT  84.888 12.413 87.462 12.631 ;
     RECT  34.164 12.559 65.286 12.785 ;
     RECT  60.444 12.785 65.286 12.857 ;
     RECT  88.272 12.413 91.602 12.901 ;
     RECT  2.415 12.479 31.842 13.019 ;
     RECT  88.272 12.901 91.782 13.099 ;
     RECT  92.52 11.981 117.666 13.099 ;
     RECT  88.272 13.099 117.666 13.135 ;
     RECT  88.272 13.135 117.81 13.171 ;
     RECT  88.272 13.171 117.846 13.289 ;
     RECT  33.192 12.557 33.21 13.297 ;
     RECT  34.164 12.785 59.49 13.297 ;
     RECT  88.272 13.289 117.81 13.361 ;
     RECT  66.096 12.631 87.462 13.405 ;
     RECT  33.192 13.297 59.49 13.441 ;
     RECT  32.976 13.441 59.49 13.711 ;
     RECT  32.832 13.711 59.49 13.757 ;
     RECT  66.024 13.405 87.462 13.829 ;
     RECT  2.415 13.019 28.674 13.837 ;
     RECT  29.415 13.019 31.842 13.837 ;
     RECT  83.232 13.829 87.462 13.837 ;
     RECT  88.272 13.361 117.702 13.837 ;
     RECT  60.444 12.857 65.07 13.909 ;
     RECT  66.024 13.829 82.314 13.909 ;
     RECT  34.272 13.757 59.49 13.945 ;
     RECT  60.444 13.909 82.314 13.945 ;
     RECT  2.415 13.837 31.842 13.981 ;
     RECT  32.832 13.757 33.498 13.981 ;
     RECT  83.232 13.837 117.702 14.009 ;
     RECT  2.415 13.981 33.498 14.099 ;
     RECT  83.304 14.009 117.702 14.099 ;
     RECT  83.304 14.099 117.666 14.135 ;
     RECT  32.832 14.099 33.498 14.521 ;
     RECT  34.272 13.945 82.314 14.521 ;
     RECT  2.415 14.099 31.842 14.675 ;
     RECT  32.832 14.521 82.314 14.779 ;
     RECT  83.415 14.135 117.666 14.909 ;
     RECT  32.832 14.779 82.386 14.917 ;
     RECT  83.415 14.909 91.278 14.917 ;
     RECT  32.832 14.917 91.278 14.957 ;
     RECT  92.088 14.909 117.666 14.957 ;
     RECT  32.832 14.957 89.097 15.025 ;
     RECT  2.415 14.675 31.806 15.089 ;
     RECT  90.072 14.957 91.278 15.521 ;
     RECT  92.34 14.957 117.666 15.529 ;
     RECT  92.34 15.529 118.242 15.601 ;
     RECT  92.34 15.601 118.674 15.719 ;
     RECT  2.415 15.089 31.626 15.755 ;
     RECT  90.072 15.521 91.206 15.961 ;
     RECT  92.34 15.719 118.242 15.989 ;
     RECT  6.624 15.755 31.626 16.123 ;
     RECT  32.796 15.025 89.097 16.123 ;
     RECT  6.624 16.123 89.097 16.169 ;
     RECT  90 15.961 91.206 16.363 ;
     RECT  90 16.363 91.566 16.403 ;
     RECT  32.796 16.169 89.097 16.501 ;
     RECT  90 16.403 91.242 16.501 ;
     RECT  6.624 16.169 31.626 16.645 ;
     RECT  2.415 15.755 5.706 16.651 ;
     RECT  6.516 16.645 31.626 16.651 ;
     RECT  92.448 15.989 118.242 16.879 ;
     RECT  32.796 16.501 91.242 16.915 ;
     RECT  2.415 16.651 31.626 16.951 ;
     RECT  32.58 16.915 91.242 16.951 ;
     RECT  92.376 16.879 118.242 16.951 ;
     RECT  2.415 16.951 91.242 17.069 ;
     RECT  92.376 16.951 118.602 17.069 ;
     RECT  89.964 17.069 91.242 17.179 ;
     RECT  92.376 17.069 118.242 17.179 ;
     RECT  2.415 17.069 89.097 17.339 ;
     RECT  89.964 17.179 118.242 17.609 ;
     RECT  2.415 17.339 59.886 17.879 ;
     RECT  2.415 17.879 59.778 18.563 ;
     RECT  90.432 17.609 118.242 18.667 ;
     RECT  90.108 18.667 118.242 18.725 ;
     RECT  90.432 18.725 118.242 18.797 ;
     RECT  61.128 17.339 89.097 18.811 ;
     RECT  26.244 18.563 59.778 19.103 ;
     RECT  42.552 19.103 59.778 19.111 ;
     RECT  2.415 18.563 25.506 19.229 ;
     RECT  26.244 19.103 41.742 19.229 ;
     RECT  42.552 19.111 59.85 19.229 ;
     RECT  90.54 18.797 118.242 19.229 ;
     RECT  61.092 18.811 89.097 19.309 ;
     RECT  2.415 19.229 12.294 19.339 ;
     RECT  2.376 19.339 12.294 19.373 ;
     RECT  60.768 19.309 89.097 19.373 ;
     RECT  2.376 19.373 11.898 19.409 ;
     RECT  13.14 19.229 25.506 19.435 ;
     RECT  26.244 19.229 32.022 19.435 ;
     RECT  2.376 19.409 5.706 19.499 ;
     RECT  90.54 19.229 113.994 19.607 ;
     RECT  90.54 19.607 93.042 19.615 ;
     RECT  13.14 19.435 32.022 19.769 ;
     RECT  93.996 19.607 113.994 19.769 ;
     RECT  13.14 19.769 31.086 19.877 ;
     RECT  2.415 19.499 5.706 19.913 ;
     RECT  60.768 19.373 87.57 19.913 ;
     RECT  120.276 19.741 120.294 19.949 ;
     RECT  31.824 19.769 32.022 19.963 ;
     RECT  32.796 19.229 41.742 19.963 ;
     RECT  42.552 19.229 59.67 20.011 ;
     RECT  2.415 19.913 4.014 20.039 ;
     RECT  61.776 19.913 87.57 20.039 ;
     RECT  90.324 19.615 93.042 20.045 ;
     RECT  42.552 20.011 59.778 20.047 ;
     RECT  2.415 20.039 3.798 20.075 ;
     RECT  13.14 19.877 30.618 20.111 ;
     RECT  61.815 20.039 87.57 20.111 ;
     RECT  88.344 19.373 89.097 20.119 ;
     RECT  95.508 19.769 113.994 20.119 ;
     RECT  114.732 19.229 118.242 20.119 ;
     RECT  63.396 20.111 87.57 20.147 ;
     RECT  119.664 20.011 119.682 20.147 ;
     RECT  13.14 20.111 30.582 20.155 ;
     RECT  31.824 19.963 41.742 20.191 ;
     RECT  42.552 20.047 59.886 20.191 ;
     RECT  95.508 20.119 118.242 20.191 ;
     RECT  61.815 20.111 62.622 20.219 ;
     RECT  88.308 20.119 89.097 20.219 ;
     RECT  2.415 20.075 3.762 20.309 ;
     RECT  12.924 20.155 30.582 20.309 ;
     RECT  61.815 20.219 62.586 20.309 ;
     RECT  4.896 19.913 5.706 20.317 ;
     RECT  6.66 19.409 11.898 20.317 ;
     RECT  90.54 20.045 93.042 20.345 ;
     RECT  95.508 20.191 118.602 20.345 ;
     RECT  90.792 20.345 93.042 20.389 ;
     RECT  4.896 20.317 11.898 20.429 ;
     RECT  90.792 20.389 93.186 20.461 ;
     RECT  93.996 19.769 94.626 20.461 ;
     RECT  6.912 20.429 11.898 20.489 ;
     RECT  90.792 20.461 94.626 20.489 ;
     RECT  31.824 20.191 59.886 20.491 ;
     RECT  60.768 19.913 61.002 20.491 ;
     RECT  88.344 20.219 89.097 20.539 ;
     RECT  6.948 20.489 11.898 20.551 ;
     RECT  91.188 20.489 94.626 20.579 ;
     RECT  63.468 20.147 87.57 20.651 ;
     RECT  2.415 20.309 3.69 20.731 ;
     RECT  65.952 20.651 87.57 20.849 ;
     RECT  91.188 20.579 92.214 20.849 ;
     RECT  6.948 20.551 12.15 20.857 ;
     RECT  31.824 20.491 61.002 20.857 ;
     RECT  61.815 20.309 62.097 20.857 ;
     RECT  4.896 20.429 5.886 20.875 ;
     RECT  65.952 20.849 82.206 20.921 ;
     RECT  66.24 20.921 82.206 20.957 ;
     RECT  63.468 20.651 65.07 20.965 ;
     RECT  12.924 20.309 30.438 20.993 ;
     RECT  6.948 20.857 12.186 21.001 ;
     RECT  12.924 20.993 25.938 21.001 ;
     RECT  2.376 20.731 3.69 21.067 ;
     RECT  31.824 20.857 62.097 21.115 ;
     RECT  83.016 20.849 87.57 21.127 ;
     RECT  88.344 20.539 89.298 21.127 ;
     RECT  31.716 21.115 62.097 21.199 ;
     RECT  63.396 20.965 65.07 21.199 ;
     RECT  83.016 21.127 89.298 21.199 ;
     RECT  93.168 20.579 94.626 21.199 ;
     RECT  95.508 20.345 117.954 21.199 ;
     RECT  6.948 21.001 25.938 21.227 ;
     RECT  26.892 20.993 30.438 21.235 ;
     RECT  91.188 20.849 91.854 21.235 ;
     RECT  83.016 21.199 89.442 21.259 ;
     RECT  93.168 21.199 117.954 21.271 ;
     RECT  83.016 21.259 89.91 21.293 ;
     RECT  90.792 21.235 91.854 21.293 ;
     RECT  31.716 21.199 65.07 21.361 ;
     RECT  6.948 21.227 11.754 21.389 ;
     RECT  76.356 20.957 82.206 21.389 ;
     RECT  2.376 21.067 3.906 21.425 ;
     RECT  6.948 21.389 11.718 21.433 ;
     RECT  93.168 21.271 118.062 21.433 ;
     RECT  83.016 21.293 85.626 21.461 ;
     RECT  4.68 20.875 5.886 21.505 ;
     RECT  6.624 21.433 11.718 21.505 ;
     RECT  2.415 21.425 3.906 21.541 ;
     RECT  4.68 21.505 11.718 21.541 ;
     RECT  31.608 21.361 65.07 21.541 ;
     RECT  86.688 21.293 89.91 21.541 ;
     RECT  76.356 21.389 81.99 21.659 ;
     RECT  92.736 21.433 118.062 21.677 ;
     RECT  90.828 21.293 91.854 21.703 ;
     RECT  31.608 21.541 65.394 21.739 ;
     RECT  26.892 21.235 30.546 21.775 ;
     RECT  31.608 21.739 65.466 21.775 ;
     RECT  90.828 21.703 91.962 21.901 ;
     RECT  92.736 21.677 105.606 21.901 ;
     RECT  76.356 21.659 80.37 21.929 ;
     RECT  106.416 21.677 118.062 21.929 ;
     RECT  66.24 20.957 75.582 21.979 ;
     RECT  76.356 21.929 80.298 21.979 ;
     RECT  12.672 21.227 25.938 22.045 ;
     RECT  12.672 22.045 26.046 22.081 ;
     RECT  26.892 21.775 65.466 22.081 ;
     RECT  86.688 21.541 90.09 22.081 ;
     RECT  90.828 21.901 105.606 22.081 ;
     RECT  2.415 21.541 11.718 22.171 ;
     RECT  86.688 22.081 105.606 22.171 ;
     RECT  12.672 22.081 65.466 22.199 ;
     RECT  83.016 21.461 85.554 22.243 ;
     RECT  66.24 21.979 80.298 22.307 ;
     RECT  2.415 22.171 11.898 22.351 ;
     RECT  81.18 21.659 81.99 22.351 ;
     RECT  82.8 22.243 85.554 22.351 ;
     RECT  86.544 22.171 105.606 22.477 ;
     RECT  106.416 21.929 118.026 22.477 ;
     RECT  12.672 22.199 57.834 22.505 ;
     RECT  58.608 22.199 65.466 22.585 ;
     RECT  66.24 22.307 75.582 22.585 ;
     RECT  32.004 22.505 57.834 22.613 ;
     RECT  58.608 22.585 75.582 22.649 ;
     RECT  76.392 22.307 80.298 22.711 ;
     RECT  81.18 22.351 85.59 22.711 ;
     RECT  32.004 22.613 37.566 22.739 ;
     RECT  58.608 22.649 61.002 22.739 ;
     RECT  86.544 22.477 118.026 22.739 ;
     RECT  76.392 22.711 85.59 22.855 ;
     RECT  86.544 22.739 90.126 22.855 ;
     RECT  2.415 22.351 11.934 23.053 ;
     RECT  12.672 22.505 31.158 23.053 ;
     RECT  61.815 22.649 75.582 23.089 ;
     RECT  76.392 22.855 90.126 23.089 ;
     RECT  2.415 23.053 31.158 23.125 ;
     RECT  38.556 22.613 57.834 23.131 ;
     RECT  90.936 22.739 118.026 23.161 ;
     RECT  2.376 23.125 31.158 23.179 ;
     RECT  32.076 22.739 37.566 23.279 ;
     RECT  90.936 23.161 118.674 23.279 ;
     RECT  2.304 23.179 31.158 23.315 ;
     RECT  33.408 23.279 37.566 23.315 ;
     RECT  61.815 23.089 90.126 23.315 ;
     RECT  32.076 23.279 32.526 23.351 ;
     RECT  35.856 23.315 37.566 23.371 ;
     RECT  38.556 23.131 58.266 23.371 ;
     RECT  61.815 23.315 89.946 23.395 ;
     RECT  61.776 23.395 89.946 23.423 ;
     RECT  61.776 23.423 75.582 23.431 ;
     RECT  32.076 23.351 32.202 23.459 ;
     RECT  35.856 23.371 58.266 23.557 ;
     RECT  59.04 22.739 60.462 23.557 ;
     RECT  2.376 23.315 31.158 23.585 ;
     RECT  35.856 23.557 60.462 23.593 ;
     RECT  61.452 23.431 75.582 23.593 ;
     RECT  90.936 23.279 118.026 23.629 ;
     RECT  2.415 23.585 31.158 23.701 ;
     RECT  90.864 23.629 118.026 23.701 ;
     RECT  90.684 23.701 118.026 23.819 ;
     RECT  76.356 23.423 89.946 23.855 ;
     RECT  90.684 23.819 95.454 23.855 ;
     RECT  35.856 23.593 75.582 23.885 ;
     RECT  76.356 23.855 85.374 23.891 ;
     RECT  35.856 23.885 61.038 23.927 ;
     RECT  33.408 23.315 35.097 24.061 ;
     RECT  35.856 23.927 54.738 24.061 ;
     RECT  2.415 23.701 31.194 24.097 ;
     RECT  33.408 24.061 54.738 24.097 ;
     RECT  86.112 23.855 89.946 24.125 ;
     RECT  2.415 24.097 31.266 24.173 ;
     RECT  55.908 23.927 61.038 24.197 ;
     RECT  61.776 23.885 75.582 24.205 ;
     RECT  76.356 23.891 85.338 24.205 ;
     RECT  57.816 24.197 61.038 24.539 ;
     RECT  2.415 24.173 31.158 24.557 ;
     RECT  90.756 23.855 95.454 24.637 ;
     RECT  96.228 23.819 118.026 24.637 ;
     RECT  32.076 23.459 32.094 24.745 ;
     RECT  33.12 24.097 54.738 24.745 ;
     RECT  32.076 24.745 54.81 24.781 ;
     RECT  55.908 24.197 56.862 24.781 ;
     RECT  2.415 24.557 10.026 24.871 ;
     RECT  61.776 24.205 85.338 24.871 ;
     RECT  86.148 24.125 89.946 24.871 ;
     RECT  32.076 24.781 56.862 24.935 ;
     RECT  2.376 24.871 10.026 24.941 ;
     RECT  61.776 24.871 89.946 25.051 ;
     RECT  90.756 24.637 118.026 25.051 ;
     RECT  10.8 24.557 31.158 25.177 ;
     RECT  32.508 24.935 56.862 25.177 ;
     RECT  61.776 25.051 118.026 25.313 ;
     RECT  57.816 24.539 58.914 25.321 ;
     RECT  32.508 25.177 57.042 25.387 ;
     RECT  57.816 25.321 58.95 25.387 ;
     RECT  32.508 25.387 58.95 25.439 ;
     RECT  61.776 25.313 100.17 25.439 ;
     RECT  2.415 24.941 10.026 25.447 ;
     RECT  10.8 25.177 31.59 25.447 ;
     RECT  2.415 25.447 31.59 25.475 ;
     RECT  61.776 25.439 100.098 25.475 ;
     RECT  59.976 24.539 61.038 25.531 ;
     RECT  61.776 25.475 90.378 25.531 ;
     RECT  59.976 25.531 90.378 25.555 ;
     RECT  59.796 25.555 90.378 25.583 ;
     RECT  32.76 25.439 58.95 25.675 ;
     RECT  59.796 25.583 89.946 25.709 ;
     RECT  32.76 25.675 59.022 25.717 ;
     RECT  59.796 25.709 61.038 25.717 ;
     RECT  100.944 25.313 118.026 25.861 ;
     RECT  32.76 25.717 61.038 25.901 ;
     RECT  59.616 25.901 61.038 25.979 ;
     RECT  100.944 25.861 118.674 25.979 ;
     RECT  61.776 25.709 89.946 26.015 ;
     RECT  32.76 25.901 58.77 26.051 ;
     RECT  61.776 26.015 84.546 26.123 ;
     RECT  32.76 26.051 58.698 26.401 ;
     RECT  91.152 25.475 100.098 26.563 ;
     RECT  100.944 25.979 118.494 26.563 ;
     RECT  85.32 26.015 89.946 26.627 ;
     RECT  2.415 25.475 31.158 26.635 ;
     RECT  32.436 26.401 58.698 26.635 ;
     RECT  91.152 26.563 118.494 26.635 ;
     RECT  2.376 26.635 31.194 26.789 ;
     RECT  85.32 26.627 89.838 26.789 ;
     RECT  90.612 26.635 118.494 26.789 ;
     RECT  32.112 26.635 58.698 26.905 ;
     RECT  59.94 25.979 61.038 26.905 ;
     RECT  61.815 26.123 84.546 26.905 ;
     RECT  32.112 26.905 59.058 27.019 ;
     RECT  59.94 26.905 84.546 27.019 ;
     RECT  91.008 26.789 118.098 27.131 ;
     RECT  32.112 27.019 84.546 27.163 ;
     RECT  85.32 26.789 89.802 27.163 ;
     RECT  32.112 27.163 89.802 27.365 ;
     RECT  2.415 26.789 31.194 27.481 ;
     RECT  91.008 27.131 117.954 27.571 ;
     RECT  59.688 27.365 89.802 27.635 ;
     RECT  2.415 27.481 31.338 27.715 ;
     RECT  32.112 27.365 58.95 27.715 ;
     RECT  90.9 27.571 117.954 27.739 ;
     RECT  2.415 27.715 58.95 27.743 ;
     RECT  90.828 27.739 117.954 27.743 ;
     RECT  31.86 27.743 58.95 27.869 ;
     RECT  90.828 27.743 112.878 27.869 ;
     RECT  2.415 27.743 31.014 27.905 ;
     RECT  113.652 27.743 117.954 27.913 ;
     RECT  90.9 27.869 112.878 27.941 ;
     RECT  113.652 27.913 117.99 28.021 ;
     RECT  2.415 27.905 30.258 28.022 ;
     RECT  2.415 28.022 30.222 28.139 ;
     RECT  30.996 27.905 31.014 28.139 ;
     RECT  31.86 27.869 35.118 28.139 ;
     RECT  61.815 27.635 89.802 28.139 ;
     RECT  2.415 28.139 30.078 28.175 ;
     RECT  113.652 28.021 118.242 28.175 ;
     RECT  61.815 28.139 84.366 28.445 ;
     RECT  35.928 27.869 58.626 28.481 ;
     RECT  85.14 28.139 89.802 28.553 ;
     RECT  59.688 27.635 61.038 28.561 ;
     RECT  31.896 28.139 35.118 28.651 ;
     RECT  82.332 28.445 84.366 28.679 ;
     RECT  31.896 28.651 35.19 28.723 ;
     RECT  35.928 28.481 58.59 28.723 ;
     RECT  59.652 28.561 61.038 28.723 ;
     RECT  59.616 28.723 61.038 28.759 ;
     RECT  61.815 28.445 81.522 28.759 ;
     RECT  59.616 28.759 81.522 28.789 ;
     RECT  90.9 27.941 112.842 28.831 ;
     RECT  2.415 28.175 29.79 28.957 ;
     RECT  31.896 28.723 58.59 28.957 ;
     RECT  90.756 28.831 112.842 28.957 ;
     RECT  113.652 28.175 118.17 28.957 ;
     RECT  2.415 28.957 29.862 29.029 ;
     RECT  85.14 28.553 89.622 29.065 ;
     RECT  2.415 29.029 30.258 29.069 ;
     RECT  11.304 29.069 30.258 29.101 ;
     RECT  90.756 28.957 118.17 29.101 ;
     RECT  11.304 29.101 30.438 29.191 ;
     RECT  59.472 28.789 81.522 29.191 ;
     RECT  31.356 28.957 58.59 29.221 ;
     RECT  59.472 29.191 81.594 29.221 ;
     RECT  11.304 29.191 30.51 29.227 ;
     RECT  31.356 29.221 81.594 29.227 ;
     RECT  11.304 29.227 81.594 29.263 ;
     RECT  82.332 28.679 84.258 29.263 ;
     RECT  90.684 29.101 118.242 29.363 ;
     RECT  2.415 29.069 10.53 29.489 ;
     RECT  11.304 29.263 84.258 29.489 ;
     RECT  11.412 29.489 84.258 29.533 ;
     RECT  113.868 29.363 117.738 29.669 ;
     RECT  90.684 29.363 113.058 29.731 ;
     RECT  90.432 29.731 113.058 29.789 ;
     RECT  11.412 29.533 84.294 29.795 ;
     RECT  2.415 29.489 10.422 29.867 ;
     RECT  2.415 29.867 5.094 29.875 ;
     RECT  59.328 29.795 84.294 29.911 ;
     RECT  85.104 29.065 89.622 29.911 ;
     RECT  59.328 29.911 89.622 29.939 ;
     RECT  59.328 29.939 85.554 30.029 ;
     RECT  11.412 29.795 58.59 30.065 ;
     RECT  2.412 29.875 5.094 30.077 ;
     RECT  91.008 29.789 113.058 30.173 ;
     RECT  61.815 30.029 85.554 30.209 ;
     RECT  91.188 30.173 113.058 30.335 ;
     RECT  5.832 29.867 10.422 30.343 ;
     RECT  86.292 29.939 89.622 30.379 ;
     RECT  91.224 30.335 113.058 30.415 ;
     RECT  113.904 29.669 117.738 30.415 ;
     RECT  91.224 30.415 117.738 30.451 ;
     RECT  5.832 30.343 10.53 30.541 ;
     RECT  11.412 30.065 28.638 30.541 ;
     RECT  61.815 30.209 84.294 30.569 ;
     RECT  29.376 30.065 58.59 30.571 ;
     RECT  59.328 30.029 61.074 30.571 ;
     RECT  5.832 30.541 28.638 30.605 ;
     RECT  85.068 30.209 85.554 30.685 ;
     RECT  86.292 30.379 89.658 30.685 ;
     RECT  2.415 30.077 5.094 30.811 ;
     RECT  5.832 30.605 6.93 30.811 ;
     RECT  7.776 30.605 28.638 30.811 ;
     RECT  29.376 30.571 61.074 30.811 ;
     RECT  7.776 30.811 61.074 30.955 ;
     RECT  61.815 30.569 81.63 30.955 ;
     RECT  82.368 30.569 84.294 30.955 ;
     RECT  85.068 30.685 89.658 30.955 ;
     RECT  91.224 30.451 117.954 30.983 ;
     RECT  91.224 30.983 117.666 31.261 ;
     RECT  2.415 30.811 6.93 31.415 ;
     RECT  4.428 31.415 6.93 31.531 ;
     RECT  7.776 30.955 81.63 31.531 ;
     RECT  82.368 30.955 89.658 31.531 ;
     RECT  82.368 31.531 90.378 31.649 ;
     RECT  4.428 31.531 81.63 31.723 ;
     RECT  82.368 31.649 89.874 31.723 ;
     RECT  91.152 31.261 117.666 31.765 ;
     RECT  2.415 31.415 3.546 31.991 ;
     RECT  4.428 31.723 89.874 32.305 ;
     RECT  4.392 32.305 89.874 32.495 ;
     RECT  2.415 31.991 3.51 32.701 ;
     RECT  29.412 32.495 61.002 32.873 ;
     RECT  61.776 32.495 89.874 33.007 ;
     RECT  91.152 31.765 117.81 33.067 ;
     RECT  2.376 32.701 3.51 33.151 ;
     RECT  4.392 32.495 28.638 33.241 ;
     RECT  29.412 32.873 60.246 33.241 ;
     RECT  4.392 33.241 60.246 33.259 ;
     RECT  4.356 33.259 60.246 33.305 ;
     RECT  2.376 33.151 3.546 33.313 ;
     RECT  4.356 33.305 60.174 33.313 ;
     RECT  2.376 33.313 60.174 33.413 ;
     RECT  61.776 33.007 89.91 33.421 ;
     RECT  91.116 33.067 117.81 33.421 ;
     RECT  60.984 32.873 61.002 33.643 ;
     RECT  61.776 33.421 117.81 33.643 ;
     RECT  60.984 33.643 117.81 33.691 ;
     RECT  60.984 33.691 117.918 33.845 ;
     RECT  61.092 33.845 117.918 33.889 ;
     RECT  2.415 33.413 60.174 33.953 ;
     RECT  61.092 33.889 117.99 34.079 ;
     RECT  2.415 33.953 60.138 34.205 ;
     RECT  59.796 34.205 60.138 34.699 ;
     RECT  61.092 34.079 117.918 34.699 ;
     RECT  2.415 34.205 59.058 34.727 ;
     RECT  27.36 34.727 59.058 34.933 ;
     RECT  59.796 34.699 117.918 34.933 ;
     RECT  2.415 34.727 26.622 35.041 ;
     RECT  27.36 34.933 117.918 35.195 ;
     RECT  32.508 35.195 117.918 35.303 ;
     RECT  90.864 35.303 117.918 35.581 ;
     RECT  32.508 35.303 89.91 35.771 ;
     RECT  2.376 35.041 26.622 35.851 ;
     RECT  27.36 35.195 31.734 35.851 ;
     RECT  65.952 35.771 89.91 35.885 ;
     RECT  90.864 35.581 118.026 35.933 ;
     RECT  32.508 35.771 65.214 35.969 ;
     RECT  116.82 35.933 118.026 35.969 ;
     RECT  2.376 35.851 31.734 35.977 ;
     RECT  32.508 35.969 60.966 35.977 ;
     RECT  2.376 35.977 60.966 36.005 ;
     RECT  76.932 35.885 89.91 36.085 ;
     RECT  76.932 36.085 89.946 36.091 ;
     RECT  90.864 35.933 116.097 36.091 ;
     RECT  61.74 35.969 65.214 36.589 ;
     RECT  65.952 35.885 76.158 36.589 ;
     RECT  76.932 36.091 116.097 36.751 ;
     RECT  116.82 35.969 117.918 36.751 ;
     RECT  2.415 36.005 60.966 36.779 ;
     RECT  31.356 36.779 60.966 36.931 ;
     RECT  61.74 36.589 76.158 36.931 ;
     RECT  76.932 36.751 117.918 36.931 ;
     RECT  76.932 36.931 118.566 37.049 ;
     RECT  31.356 36.931 76.158 37.121 ;
     RECT  61.56 37.121 76.158 37.129 ;
     RECT  76.932 37.049 117.918 37.129 ;
     RECT  61.56 37.129 117.918 37.229 ;
     RECT  2.415 36.779 30.51 37.579 ;
     RECT  2.412 37.579 30.51 37.625 ;
     RECT  2.415 37.625 30.51 37.741 ;
     RECT  31.356 37.121 60.318 37.741 ;
     RECT  76.932 37.229 117.918 37.967 ;
     RECT  61.56 37.229 76.194 37.975 ;
     RECT  76.932 37.967 117.882 37.975 ;
     RECT  118.656 37.975 118.674 38.129 ;
     RECT  61.56 37.975 117.882 38.189 ;
     RECT  2.415 37.741 60.318 38.309 ;
     RECT  2.415 38.309 59.634 38.399 ;
     RECT  61.704 38.189 117.882 38.399 ;
     RECT  3.492 38.399 59.634 38.717 ;
     RECT  61.704 38.399 65.322 38.813 ;
     RECT  66.168 38.399 117.882 38.821 ;
     RECT  66.168 38.821 117.99 38.939 ;
     RECT  42.048 38.717 59.634 39.181 ;
     RECT  60.768 39.091 60.786 39.209 ;
     RECT  66.168 38.939 117.954 39.209 ;
     RECT  61.704 38.813 65.106 39.211 ;
     RECT  3.492 38.717 41.238 39.245 ;
     RECT  60.984 39.211 65.106 39.251 ;
     RECT  87.624 39.209 89.802 39.353 ;
     RECT  42.048 39.181 59.85 39.361 ;
     RECT  66.168 39.209 86.706 39.361 ;
     RECT  87.804 39.353 89.802 39.587 ;
     RECT  3.636 39.245 41.238 39.595 ;
     RECT  42.048 39.361 59.994 39.595 ;
     RECT  2.415 38.399 2.697 39.631 ;
     RECT  3.636 39.595 59.994 39.659 ;
     RECT  2.415 39.631 2.79 39.749 ;
     RECT  3.708 39.659 59.994 39.749 ;
     RECT  90.576 39.209 117.954 39.749 ;
     RECT  3.708 39.749 58.518 39.857 ;
     RECT  61.632 39.251 65.106 39.883 ;
     RECT  66.132 39.361 86.706 39.883 ;
     RECT  3.708 39.857 58.41 39.893 ;
     RECT  59.328 39.749 59.994 39.979 ;
     RECT  59.328 39.979 60.714 40.019 ;
     RECT  90.576 39.749 117.882 40.019 ;
     RECT  90.576 40.019 107.946 40.055 ;
     RECT  3.708 39.893 36.054 40.163 ;
     RECT  90.576 40.055 107.694 40.199 ;
     RECT  4.14 40.163 36.054 40.289 ;
     RECT  90.576 40.199 96.714 40.289 ;
     RECT  59.328 40.019 60.462 40.325 ;
     RECT  97.524 40.199 107.694 40.325 ;
     RECT  61.632 39.883 86.706 40.397 ;
     RECT  90.576 40.289 92.538 40.397 ;
     RECT  87.804 39.587 89.73 40.405 ;
     RECT  90.576 40.397 92.502 40.405 ;
     RECT  4.14 40.289 4.302 40.433 ;
     RECT  59.328 40.325 60.39 40.433 ;
     RECT  4.14 40.433 4.158 40.445 ;
     RECT  5.184 40.289 36.054 40.469 ;
     RECT  36.792 39.893 58.41 40.469 ;
     RECT  61.632 40.397 84.114 40.469 ;
     RECT  5.184 40.469 30.546 40.559 ;
     RECT  36.792 40.469 57.618 40.559 ;
     RECT  87.804 40.405 92.502 40.559 ;
     RECT  93.348 40.289 96.714 40.559 ;
     RECT  108.72 40.019 117.882 40.559 ;
     RECT  29.415 40.559 30.546 40.595 ;
     RECT  31.356 40.469 36.054 40.595 ;
     RECT  59.328 40.433 59.778 40.595 ;
     RECT  63.288 40.469 84.114 40.595 ;
     RECT  93.348 40.559 96.57 40.595 ;
     RECT  108.72 40.559 116.982 40.595 ;
     RECT  117.792 40.559 117.882 40.595 ;
     RECT  34.416 40.595 36.054 40.631 ;
     RECT  36.792 40.559 57.474 40.631 ;
     RECT  63.36 40.595 84.078 40.667 ;
     RECT  84.852 40.397 86.706 40.667 ;
     RECT  90.576 40.559 92.502 40.667 ;
     RECT  93.348 40.595 96.246 40.667 ;
     RECT  117.792 40.595 117.81 40.667 ;
     RECT  87.804 40.559 89.73 40.699 ;
     RECT  40.032 40.631 57.474 40.703 ;
     RECT  84.852 40.667 86.598 40.703 ;
     RECT  87.588 40.699 89.73 40.703 ;
     RECT  59.328 40.595 59.742 40.711 ;
     RECT  6.372 40.559 28.35 40.739 ;
     RECT  40.032 40.703 54.414 40.739 ;
     RECT  63.36 40.667 65.214 40.739 ;
     RECT  65.952 40.667 84.078 40.739 ;
     RECT  87.588 40.703 87.606 40.739 ;
     RECT  90.9 40.667 92.502 40.739 ;
     RECT  97.704 40.325 107.694 40.739 ;
     RECT  2.415 39.749 2.697 40.787 ;
     RECT  40.032 40.739 53.946 40.787 ;
     RECT  61.815 40.469 62.097 40.787 ;
     RECT  29.415 40.595 30.474 40.829 ;
     RECT  31.356 40.595 33.606 40.829 ;
     RECT  34.668 40.631 36.054 40.829 ;
     RECT  36.792 40.631 39.258 40.829 ;
     RECT  40.032 40.787 40.305 40.829 ;
     RECT  41.04 40.787 53.946 40.829 ;
     RECT  55.44 40.703 57.474 40.829 ;
     RECT  59.292 40.711 59.742 40.829 ;
     RECT  63.36 40.739 64.926 40.829 ;
     RECT  65.952 40.739 81.774 40.829 ;
     RECT  82.656 40.739 84.078 40.829 ;
     RECT  84.852 40.703 84.87 40.829 ;
     RECT  85.896 40.703 86.598 40.829 ;
     RECT  88.524 40.703 89.73 40.829 ;
     RECT  90.9 40.739 92.25 40.829 ;
     RECT  93.348 40.667 93.366 40.829 ;
     RECT  94.14 40.667 96.246 40.829 ;
     RECT  108.72 40.595 116.55 40.829 ;
     RECT  58.392 40.469 58.41 40.835 ;
     RECT  6.552 40.739 28.35 40.865 ;
     RECT  29.415 40.829 30.294 40.865 ;
     RECT  31.356 40.829 31.626 40.865 ;
     RECT  32.868 40.829 33.498 40.865 ;
     RECT  34.815 40.829 35.442 40.865 ;
     RECT  36.792 40.829 38.754 40.865 ;
     RECT  40.104 40.829 40.305 40.865 ;
     RECT  42.372 40.829 42.498 40.865 ;
     RECT  43.272 40.829 53.874 40.865 ;
     RECT  55.44 40.829 56.79 40.865 ;
     RECT  59.472 40.829 59.742 40.865 ;
     RECT  66.024 40.829 66.258 40.865 ;
     RECT  67.176 40.829 81.774 40.865 ;
     RECT  90.972 40.829 91.746 40.865 ;
     RECT  94.215 40.829 95.274 40.865 ;
     RECT  96.228 40.829 96.246 40.865 ;
     RECT  97.704 40.739 98.478 40.865 ;
     RECT  99.252 40.739 107.694 40.865 ;
     RECT  111.888 40.829 115.905 40.865 ;
     RECT  28.332 40.865 28.35 40.877 ;
     RECT  111.888 40.865 113.166 40.877 ;
     RECT  7.815 40.865 9.666 40.901 ;
     RECT  10.764 40.865 27.414 40.901 ;
     RECT  36.792 40.865 37.134 40.901 ;
     RECT  43.272 40.865 53.622 40.901 ;
     RECT  55.548 40.865 56.79 40.901 ;
     RECT  69.516 40.865 81.774 40.901 ;
     RECT  91.188 40.865 91.206 40.901 ;
     RECT  114.084 40.865 114.858 40.901 ;
     RECT  69.516 40.901 75.834 40.925 ;
     RECT  10.764 40.901 26.082 40.937 ;
     RECT  36.792 40.901 36.81 40.937 ;
     RECT  37.908 40.865 38.754 40.937 ;
     RECT  40.14 40.865 40.305 40.937 ;
     RECT  43.272 40.901 51.105 40.937 ;
     RECT  76.968 40.901 81.774 40.937 ;
     RECT  111.888 40.877 112.086 40.937 ;
     RECT  114.084 40.901 114.75 40.937 ;
     RECT  7.815 40.901 7.974 40.973 ;
     RECT  8.748 40.901 9.666 40.973 ;
     RECT  10.764 40.937 15.426 40.973 ;
     RECT  16.596 40.937 24.105 40.973 ;
     RECT  25.164 40.937 25.65 40.973 ;
     RECT  27.396 40.901 27.414 40.973 ;
     RECT  30.276 40.865 30.294 40.973 ;
     RECT  31.608 40.865 31.626 40.973 ;
     RECT  37.908 40.937 37.926 40.973 ;
     RECT  41.04 40.829 41.058 40.973 ;
     RECT  51.984 40.901 53.622 40.973 ;
     RECT  59.472 40.865 59.49 40.973 ;
     RECT  63.36 40.829 63.378 40.973 ;
     RECT  64.188 40.829 64.206 40.973 ;
     RECT  66.24 40.865 66.258 40.973 ;
     RECT  67.215 40.865 68.778 40.973 ;
     RECT  69.552 40.925 75.834 40.973 ;
     RECT  79.524 40.937 81.774 40.973 ;
     RECT  82.656 40.829 83.826 40.973 ;
     RECT  85.896 40.829 85.914 40.973 ;
     RECT  89.712 40.829 89.73 40.973 ;
     RECT  97.848 40.865 98.046 40.973 ;
     RECT  108.72 40.829 110.505 40.973 ;
     RECT  111.888 40.937 111.906 40.973 ;
     RECT  99.615 40.865 107.694 40.981 ;
     RECT  8.748 40.973 9.27 41.009 ;
     RECT  16.596 40.973 20.43 41.009 ;
     RECT  21.348 40.973 22.23 41.009 ;
     RECT  25.632 40.973 25.65 41.009 ;
     RECT  33.48 40.865 33.498 41.009 ;
     RECT  38.736 40.937 38.754 41.009 ;
     RECT  42.48 40.865 42.498 41.009 ;
     RECT  52.524 40.973 53.622 41.009 ;
     RECT  55.548 40.901 55.566 41.009 ;
     RECT  76.968 40.937 78.75 41.009 ;
     RECT  80.28 40.973 81.234 41.009 ;
     RECT  82.656 40.973 83.505 41.009 ;
     RECT  94.215 40.865 95.022 41.009 ;
     RECT  99.615 40.981 108.162 41.009 ;
     RECT  113.148 40.877 113.166 41.009 ;
     RECT  114.084 40.937 114.498 41.009 ;
     RECT  9.144 41.009 9.162 41.021 ;
     RECT  10.8 40.973 15.426 41.021 ;
     RECT  16.74 41.009 20.43 41.021 ;
     RECT  21.348 41.009 21.726 41.021 ;
     RECT  69.552 40.973 75.69 41.021 ;
     RECT  76.968 41.009 78.678 41.021 ;
     RECT  81.216 41.009 81.234 41.021 ;
     RECT  110.088 40.973 110.505 41.021 ;
     RECT  2.415 40.787 2.505 41.057 ;
     RECT  7.815 40.973 7.905 41.057 ;
     RECT  23.58 40.973 24.105 41.057 ;
     RECT  29.415 40.865 29.505 41.057 ;
     RECT  34.815 40.865 34.905 41.057 ;
     RECT  40.215 40.937 40.305 41.057 ;
     RECT  44.352 40.937 51.105 41.057 ;
     RECT  56.415 40.901 56.505 41.057 ;
     RECT  61.815 40.787 61.905 41.057 ;
     RECT  67.215 40.973 67.305 41.057 ;
     RECT  76.968 41.021 78.105 41.057 ;
     RECT  83.415 41.009 83.505 41.057 ;
     RECT  88.815 40.829 88.905 41.057 ;
     RECT  94.215 41.009 94.305 41.057 ;
     RECT  99.615 41.009 100.134 41.057 ;
     RECT  110.415 41.021 110.505 41.057 ;
     RECT  115.815 40.865 115.905 41.057 ;
     RECT  68.76 40.973 68.778 41.069 ;
     RECT  10.8 41.021 13.806 41.099 ;
     RECT  14.796 41.021 15.426 41.099 ;
     RECT  72.216 41.021 75.222 41.099 ;
     RECT  100.116 41.057 100.134 41.099 ;
     RECT  44.352 41.057 50.814 41.135 ;
     RECT  76.968 41.057 77.994 41.171 ;
     RECT  72.216 41.099 74.826 41.279 ;
     RECT  43.38 40.937 43.398 41.597 ;
     RECT  69.552 41.021 71.226 41.597 ;
     RECT  101.304 41.009 108.162 41.597 ;
     RECT  16.74 41.021 20.106 41.645 ;
     RECT  44.46 41.135 50.814 41.645 ;
     RECT  103.104 41.597 106.326 41.645 ;
     RECT  107.064 41.597 108.162 41.885 ;
     RECT  103.428 41.645 106.326 42.125 ;
     RECT  11.196 41.099 13.806 42.173 ;
     RECT  49.968 41.645 50.814 42.173 ;
     RECT  69.66 41.597 71.226 42.173 ;
     RECT  72.288 41.279 74.826 42.173 ;
     RECT  103.608 42.125 106.326 42.173 ;
     RECT  107.064 41.885 107.91 42.173 ;
     RECT  11.196 42.173 13.554 42.221 ;
     RECT  14.796 41.099 15.102 42.221 ;
     RECT  16.74 41.645 19.89 42.221 ;
     RECT  44.46 41.645 49.05 42.221 ;
     RECT  72.288 42.173 74.358 42.221 ;
     RECT  101.304 41.597 102.114 42.221 ;
     RECT  107.352 42.173 107.478 42.221 ;
     RECT  11.196 42.221 13.086 42.269 ;
     RECT  44.496 42.221 44.694 42.269 ;
     RECT  45.756 42.221 47.646 42.269 ;
     RECT  48.708 42.221 49.05 42.269 ;
     RECT  69.66 42.173 70.326 42.269 ;
     RECT  72.288 42.221 73.602 42.269 ;
     RECT  101.484 42.221 102.114 42.269 ;
     RECT  104.76 42.173 106.002 42.269 ;
     RECT  12.024 42.269 13.086 42.317 ;
     RECT  17.928 42.221 18.27 42.317 ;
     RECT  44.496 42.269 44.622 42.317 ;
     RECT  69.66 42.269 70.182 42.317 ;
     RECT  105.372 42.269 106.002 42.317 ;
     RECT  44.496 42.317 44.586 42.365 ;
     RECT  101.52 42.269 102.114 42.365 ;
     RECT  105.48 42.317 106.002 42.365 ;
     RECT  44.568 42.365 44.586 42.413 ;
     RECT  101.916 42.365 102.114 42.413 ;
     RECT  47.304 42.269 47.646 42.797 ;
     RECT  48.96 42.269 49.05 42.797 ;
     RECT  12.096 42.317 13.086 42.845 ;
     RECT  13.068 42.845 13.086 42.989 ;
     RECT  16.74 42.221 17.01 42.989 ;
     RECT  12.096 42.845 12.294 43.037 ;
     RECT  17.928 42.317 17.946 43.037 ;
     RECT  19.08 42.221 19.89 43.037 ;
     RECT  21.348 41.021 21.366 43.037 ;
     RECT  69.66 42.317 70.074 43.037 ;
     RECT  105.624 42.365 106.002 43.037 ;
     RECT  49.032 42.797 49.05 43.051 ;
     RECT  72.324 42.269 73.602 43.051 ;
     RECT  74.34 42.221 74.358 43.051 ;
     RECT  11.196 42.269 11.214 43.085 ;
     RECT  12.096 43.037 12.114 43.085 ;
     RECT  15.084 42.221 15.102 43.085 ;
     RECT  19.188 43.037 19.818 43.085 ;
     RECT  23.58 41.057 23.598 43.085 ;
     RECT  45.756 42.269 46.206 43.085 ;
     RECT  49.032 43.051 49.626 43.085 ;
     RECT  52.524 41.009 52.542 43.085 ;
     RECT  69.732 43.037 70.074 43.085 ;
     RECT  72.324 43.051 74.358 43.085 ;
     RECT  76.968 41.171 77.274 43.085 ;
     RECT  101.916 42.413 101.934 43.085 ;
     RECT  103.716 42.173 103.734 43.085 ;
     RECT  107.352 42.221 107.37 43.085 ;
     RECT  47.196 43.003 47.214 43.133 ;
     RECT  50.796 42.173 50.814 43.133 ;
     RECT  13.14 43.051 13.158 43.181 ;
     RECT  16.992 42.989 17.01 43.181 ;
     RECT  49.608 43.085 49.626 43.181 ;
     RECT  53.604 41.009 53.622 43.181 ;
     RECT  73.8 43.085 73.818 43.181 ;
     RECT  77.256 43.085 77.274 43.181 ;
    LAYER M4 ;
     RECT  0.06 23.088 0.179 23.208 ;
     RECT  0.133 21.456 2.365 21.48 ;
     RECT  2.401 3.312 2.408 3.336 ;
     RECT  2.365 7.92 2.408 7.944 ;
     RECT  2.401 9.6 2.408 9.624 ;
     RECT  2.365 19.344 2.408 19.368 ;
     RECT  2.365 21.216 2.408 21.48 ;
     RECT  0.179 23.184 2.408 23.208 ;
     RECT  2.365 24.912 2.408 24.936 ;
     RECT  2.365 26.64 2.408 26.664 ;
     RECT  2.401 30.048 2.408 30.072 ;
     RECT  2.365 32.736 2.408 32.76 ;
     RECT  2.365 35.28 2.408 35.304 ;
     RECT  2.401 37.584 2.408 37.608 ;
     RECT  2.408 2.148 2.512 41.052 ;
     RECT  2.512 2.256 2.704 40.782 ;
     RECT  2.704 12.288 2.765 13.32 ;
     RECT  2.704 14.4 2.819 15.336 ;
     RECT  2.704 16.56 2.819 17.112 ;
     RECT  2.704 18.72 2.819 19.992 ;
     RECT  2.704 36.336 2.819 39.624 ;
     RECT  2.704 28.944 2.915 30.792 ;
     RECT  2.915 28.944 2.917 30.6 ;
     RECT  2.819 19.2 3.125 19.992 ;
     RECT  2.704 4.8 3.203 4.824 ;
     RECT  2.704 24.528 3.203 24.936 ;
     RECT  2.704 6.24 3.251 6.504 ;
     RECT  2.704 2.256 3.436 3.432 ;
     RECT  2.704 7.584 3.697 8.28 ;
     RECT  2.765 12.288 3.724 12.312 ;
     RECT  2.704 21.216 3.805 22.824 ;
     RECT  3.125 19.2 3.841 19.368 ;
     RECT  3.805 21.216 3.877 23.304 ;
     RECT  3.251 6.24 3.917 6.408 ;
     RECT  2.819 14.4 3.917 15.192 ;
     RECT  3.841 18.912 3.925 19.368 ;
     RECT  2.704 9.6 3.989 10.152 ;
     RECT  2.765 13.296 4.021 13.32 ;
     RECT  3.877 21.072 4.025 23.304 ;
     RECT  2.819 36.336 4.061 36.36 ;
     RECT  2.819 38.784 4.124 39.624 ;
     RECT  4.124 38.16 4.129 39.624 ;
     RECT  3.917 15.168 4.133 15.192 ;
     RECT  2.704 26.208 4.133 27.912 ;
     RECT  4.129 38.16 4.169 40.44 ;
     RECT  4.169 38.16 4.211 38.808 ;
     RECT  2.704 32.496 4.316 32.856 ;
     RECT  4.273 34.176 4.316 34.2 ;
     RECT  4.133 26.208 4.349 27.816 ;
     RECT  4.316 32.496 4.357 34.2 ;
     RECT  4.357 32.448 4.403 34.2 ;
     RECT  3.925 18.432 4.525 19.368 ;
     RECT  3.203 24.528 4.561 24.552 ;
     RECT  4.021 13.296 4.597 13.704 ;
     RECT  4.561 24.528 4.601 25.08 ;
     RECT  3.989 10.128 4.669 10.152 ;
     RECT  2.704 11.232 4.669 11.304 ;
     RECT  4.025 21.072 4.669 21.96 ;
     RECT  4.525 4.704 4.748 4.728 ;
     RECT  3.436 2.64 4.777 3.432 ;
     RECT  2.704 35.28 4.777 35.304 ;
     RECT  4.025 23.28 4.813 23.304 ;
     RECT  4.777 2.256 4.861 3.48 ;
     RECT  4.309 15.312 4.885 15.336 ;
     RECT  2.819 16.8 4.885 17.112 ;
     RECT  4.669 10.128 4.933 11.304 ;
     RECT  4.525 18.432 4.957 19.608 ;
     RECT  4.669 20.88 4.957 21.96 ;
     RECT  4.403 32.448 5.029 32.952 ;
     RECT  4.403 34.176 5.029 34.2 ;
     RECT  4.777 35.28 5.029 35.976 ;
     RECT  4.957 18.432 5.041 21.96 ;
     RECT  2.917 28.944 5.069 28.968 ;
     RECT  4.861 2.736 5.101 3.48 ;
     RECT  4.748 4.704 5.101 4.872 ;
     RECT  4.349 27.024 5.101 27.816 ;
     RECT  5.029 32.4 5.113 32.952 ;
     RECT  4.601 24.864 5.125 25.08 ;
     RECT  4.777 37.008 5.137 37.032 ;
     RECT  4.211 38.16 5.137 38.472 ;
     RECT  4.813 23.28 5.141 23.352 ;
     RECT  4.933 10.128 5.171 11.544 ;
     RECT  4.885 15.312 5.171 17.112 ;
     RECT  5.137 37.008 5.245 38.472 ;
     RECT  5.125 29.088 5.249 29.112 ;
     RECT  5.029 34.176 5.285 35.976 ;
     RECT  5.171 10.128 5.353 10.296 ;
     RECT  5.171 11.28 5.353 11.544 ;
     RECT  4.597 12.912 5.353 13.704 ;
     RECT  5.171 15.312 5.357 17.016 ;
     RECT  5.285 35.952 5.389 35.976 ;
     RECT  5.245 37.008 5.389 39.288 ;
     RECT  5.353 11.28 5.429 13.704 ;
     RECT  5.285 34.176 5.459 34.344 ;
     RECT  5.125 24.864 5.465 25.896 ;
     RECT  5.101 2.736 5.497 3.72 ;
     RECT  5.101 4.704 5.497 4.92 ;
     RECT  5.041 18.432 5.497 19.608 ;
     RECT  5.101 27.024 5.533 27.96 ;
     RECT  3.697 7.392 5.653 8.28 ;
     RECT  5.353 9.888 5.653 10.296 ;
     RECT  5.357 15.312 5.789 15.336 ;
     RECT  5.497 18.288 5.789 19.608 ;
     RECT  5.653 7.392 5.987 10.296 ;
     RECT  5.113 32.448 6.001 32.952 ;
     RECT  5.389 35.952 6.001 39.288 ;
     RECT  4.169 40.416 6.001 40.44 ;
     RECT  6.001 32.448 6.037 33.144 ;
     RECT  5.459 34.176 6.037 34.2 ;
     RECT  5.429 11.28 6.041 12.312 ;
     RECT  6.001 35.952 6.041 40.44 ;
     RECT  5.987 7.392 6.113 10.008 ;
     RECT  5.789 18.864 6.113 19.608 ;
     RECT  5.429 13.68 6.181 13.704 ;
     RECT  5.141 23.328 6.188 23.352 ;
     RECT  6.181 13.68 6.221 14.232 ;
     RECT  6.188 23.184 6.229 23.352 ;
     RECT  5.465 24.864 6.229 25.08 ;
     RECT  6.037 32.448 6.253 34.2 ;
     RECT  6.229 23.184 6.275 25.08 ;
     RECT  6.253 32.4 6.293 34.2 ;
     RECT  5.533 26.784 6.332 27.96 ;
     RECT  6.109 29.52 6.332 29.544 ;
     RECT  6.113 18.912 6.361 19.608 ;
     RECT  5.041 20.88 6.361 21.96 ;
     RECT  6.293 32.4 6.361 33.576 ;
     RECT  6.332 26.784 6.419 29.544 ;
     RECT  6.419 26.784 6.469 27.96 ;
     RECT  5.357 16.416 6.613 17.016 ;
     RECT  6.041 35.952 6.653 39.912 ;
     RECT  6.653 36.096 6.725 39.912 ;
     RECT  6.275 24.144 6.748 25.08 ;
     RECT  6.361 18.912 6.793 21.96 ;
     RECT  5.497 2.736 6.829 4.92 ;
     RECT  6.041 12.288 6.829 12.312 ;
     RECT  6.829 2.736 6.901 5.16 ;
     RECT  3.917 6.24 6.901 6.264 ;
     RECT  6.419 29.52 7.009 29.544 ;
     RECT  2.917 30.576 7.009 30.6 ;
     RECT  6.469 26.256 7.153 27.96 ;
     RECT  6.613 15.984 7.189 17.016 ;
     RECT  6.793 18.912 7.189 22.776 ;
     RECT  7.189 15.984 7.333 22.776 ;
     RECT  7.621 0.144 7.729 0.168 ;
     RECT  7.153 34.752 7.729 34.776 ;
     RECT  6.725 36.096 7.729 39.816 ;
     RECT  6.113 9.792 7.765 10.008 ;
     RECT  6.685 10.992 7.765 11.016 ;
     RECT  6.901 2.736 7.808 6.264 ;
     RECT  6.113 7.392 7.808 8.28 ;
     RECT  7.765 9.792 7.808 11.016 ;
     RECT  6.829 12.288 7.808 12.792 ;
     RECT  6.221 14.16 7.808 14.232 ;
     RECT  7.333 15.264 7.808 22.776 ;
     RECT  6.748 24.144 7.808 24.168 ;
     RECT  7.153 25.728 7.808 27.96 ;
     RECT  7.009 29.52 7.808 30.6 ;
     RECT  6.361 31.92 7.808 33.576 ;
     RECT  7.729 34.752 7.808 39.816 ;
     RECT  7.808 2.148 7.912 41.052 ;
     RECT  7.729 0.048 7.945 0.168 ;
     RECT  7.912 2.418 8.104 40.782 ;
     RECT  8.104 15.264 8.165 21.72 ;
     RECT  8.104 4.656 8.201 5.016 ;
     RECT  8.201 4.8 8.243 5.016 ;
     RECT  8.104 6 8.243 14.232 ;
     RECT  8.243 6 8.273 12.312 ;
     RECT  8.104 34.416 8.345 40.782 ;
     RECT  8.273 6 8.381 8.52 ;
     RECT  8.243 13.632 8.381 14.232 ;
     RECT  8.104 22.752 8.387 23.688 ;
     RECT  8.104 29.088 8.387 33.288 ;
     RECT  8.104 2.832 8.417 3.624 ;
     RECT  8.387 30.672 8.453 33.288 ;
     RECT  8.381 6 8.561 8.28 ;
     RECT  8.165 15.264 8.561 21.672 ;
     RECT  8.561 6 8.579 6.312 ;
     RECT  8.345 36.912 8.627 40.782 ;
     RECT  8.453 30.672 8.633 33.192 ;
     RECT  8.273 9.792 8.668 12.312 ;
     RECT  8.668 9.792 8.705 10.92 ;
     RECT  8.633 30.672 8.705 30.792 ;
     RECT  8.561 16.896 8.819 21.672 ;
     RECT  8.345 34.416 8.885 35.592 ;
     RECT  8.819 18.144 8.993 21.672 ;
     RECT  8.627 40.608 9.061 40.782 ;
     RECT  8.387 23.376 9.097 23.688 ;
     RECT  8.104 24.672 9.097 27.432 ;
     RECT  9.061 40.608 9.131 40.968 ;
     RECT  8.243 4.8 9.241 4.824 ;
     RECT  8.993 20.304 9.241 21.672 ;
     RECT  9.097 23.376 9.281 27.432 ;
     RECT  8.993 18.144 9.317 19.32 ;
     RECT  8.579 6.048 9.389 6.312 ;
     RECT  8.668 12.288 9.389 12.312 ;
     RECT  8.387 29.088 9.452 29.592 ;
     RECT  8.705 10.176 9.461 10.92 ;
     RECT  8.633 31.824 9.5 33.192 ;
     RECT  9.5 31.824 9.533 33.288 ;
     RECT  8.885 34.752 9.533 35.592 ;
     RECT  9.452 28.608 9.539 29.592 ;
     RECT  9.533 32.592 9.587 33.288 ;
     RECT  8.561 15.264 9.673 15.288 ;
     RECT  8.819 16.896 9.673 17.112 ;
     RECT  9.493 12.48 9.745 12.504 ;
     RECT  8.381 13.632 9.745 13.656 ;
     RECT  9.745 12.48 9.785 13.656 ;
     RECT  9.241 20.304 9.785 22.344 ;
     RECT  8.561 7.632 9.817 8.28 ;
     RECT  9.539 29.568 9.817 29.592 ;
     RECT  9.131 40.608 9.817 41.016 ;
     RECT  9.241 4.8 9.821 5.064 ;
     RECT  9.461 10.608 9.893 10.92 ;
     RECT  9.281 26.208 9.925 27.432 ;
     RECT  9.533 34.848 9.961 35.592 ;
     RECT  8.627 36.912 9.961 39.384 ;
     RECT  9.281 23.376 9.965 25.08 ;
     RECT  7.945 0.048 9.997 0.216 ;
     RECT  9.961 34.848 10.001 39.384 ;
     RECT  9.317 18.72 10.028 19.32 ;
     RECT  9.785 20.304 10.028 21.672 ;
     RECT  10.028 18.72 10.115 21.672 ;
     RECT  9.673 15.264 10.117 17.112 ;
     RECT  9.817 7.632 10.141 8.856 ;
     RECT  10.117 15.264 10.163 17.64 ;
     RECT  8.417 2.832 10.309 3.384 ;
     RECT  9.587 32.592 10.325 33.192 ;
     RECT  10.309 2.832 10.355 3.528 ;
     RECT  10.355 3.168 10.397 3.528 ;
     RECT  8.705 30.672 10.469 30.696 ;
     RECT  9.817 29.568 10.501 29.688 ;
     RECT  9.893 10.608 10.508 10.632 ;
     RECT  10.141 7.392 10.549 8.856 ;
     RECT  10.001 36.384 10.573 39.384 ;
     RECT  9.817 40.56 10.573 41.016 ;
     RECT  9.965 23.664 10.597 25.08 ;
     RECT  9.925 26.208 10.597 27.768 ;
     RECT  10.501 29.232 10.609 29.688 ;
     RECT  10.597 23.664 10.643 27.768 ;
     RECT  10.643 25.056 10.645 27.768 ;
     RECT  10.645 25.056 10.649 27.912 ;
     RECT  10.508 10.56 10.753 10.632 ;
     RECT  10.163 17.616 10.753 17.64 ;
     RECT  10.115 18.72 10.753 19.32 ;
     RECT  10.001 34.848 10.829 35.16 ;
     RECT  10.573 36.384 10.835 41.016 ;
     RECT  10.643 23.664 10.901 23.736 ;
     RECT  10.649 25.056 10.937 25.704 ;
     RECT  10.649 26.784 10.937 27.912 ;
     RECT  10.835 38.736 10.969 41.016 ;
     RECT  9.997 0.048 11.077 0.264 ;
     RECT  10.835 36.384 11.081 37.656 ;
     RECT  11.077 0.048 11.113 0.408 ;
     RECT  10.501 31.728 11.149 31.752 ;
     RECT  10.829 35.136 11.18 35.16 ;
     RECT  10.115 20.304 11.185 21.672 ;
     RECT  10.969 22.992 11.185 23.304 ;
     RECT  10.937 26.88 11.189 27.912 ;
     RECT  10.325 32.784 11.221 33.192 ;
     RECT  11.221 32.784 11.257 33.576 ;
     RECT  11.18 35.136 11.267 35.64 ;
     RECT  11.189 26.928 11.297 27.912 ;
     RECT  11.081 37.056 11.297 37.656 ;
     RECT  9.821 4.8 11.365 4.824 ;
     RECT  9.785 12.48 11.365 13.128 ;
     RECT  10.753 17.616 11.365 19.32 ;
     RECT  11.185 20.304 11.365 23.304 ;
     RECT  11.297 37.056 11.405 37.08 ;
     RECT  10.397 3.168 11.437 3.384 ;
     RECT  10.609 29.04 11.437 29.688 ;
     RECT  11.437 29.04 11.605 30.024 ;
     RECT  11.605 28.944 11.692 30.024 ;
     RECT  10.549 7.392 11.761 9.24 ;
     RECT  11.437 2.208 11.833 3.384 ;
     RECT  11.185 43.056 11.869 43.08 ;
     RECT  11.365 4.512 11.873 5.16 ;
     RECT  11.365 17.616 11.905 23.304 ;
     RECT  11.267 35.136 11.909 35.352 ;
     RECT  11.869 42.24 11.977 43.08 ;
     RECT  9.389 6.24 11.989 6.312 ;
     RECT  11.761 7.344 11.989 9.24 ;
     RECT  11.149 14.208 11.989 14.232 ;
     RECT  10.163 15.264 11.989 16.392 ;
     RECT  11.989 6.24 12.035 9.24 ;
     RECT  11.989 14.208 12.035 16.392 ;
     RECT  11.365 12.336 12.037 13.128 ;
     RECT  12.035 14.208 12.037 14.856 ;
     RECT  12.035 15.936 12.053 16.392 ;
     RECT  11.905 17.616 12.089 23.736 ;
     RECT  12.037 12.336 12.133 14.856 ;
     RECT  11.977 42.192 12.229 43.08 ;
     RECT  11.692 29.04 12.265 30.024 ;
     RECT  11.149 31.104 12.265 31.752 ;
     RECT  10.937 25.68 12.301 25.704 ;
     RECT  11.909 35.28 12.301 35.352 ;
     RECT  12.193 36.48 12.301 36.84 ;
     RECT  10.969 38.736 12.301 41.064 ;
     RECT  10.753 10.368 12.337 10.632 ;
     RECT  12.265 29.04 12.373 31.752 ;
     RECT  11.257 32.784 12.373 33.672 ;
     RECT  12.301 38.496 12.409 41.064 ;
     RECT  12.301 25.632 12.445 25.704 ;
     RECT  11.297 27.072 12.445 27.912 ;
     RECT  12.301 35.28 12.445 36.84 ;
     RECT  12.035 6.288 12.517 9.24 ;
     RECT  12.337 10.272 12.517 10.632 ;
     RECT  11.833 2.208 12.661 3.432 ;
     RECT  11.873 4.512 12.661 4.536 ;
     RECT  12.089 23.712 12.661 23.736 ;
     RECT  12.373 29.04 12.661 33.672 ;
     RECT  12.133 12.336 12.733 12.84 ;
     RECT  12.409 38.16 12.901 41.064 ;
     RECT  12.229 42.144 12.901 43.08 ;
     RECT  11.113 0.048 12.985 0.504 ;
     RECT  12.661 2.208 13.093 4.536 ;
     RECT  12.733 11.856 13.093 12.84 ;
     RECT  12.901 38.16 13.129 43.08 ;
     RECT  12.089 17.616 13.165 22.488 ;
     RECT  12.661 23.712 13.165 23.88 ;
     RECT  13.093 1.728 13.18 4.536 ;
     RECT  13.18 2.148 13.208 4.536 ;
     RECT  12.517 6.288 13.208 10.632 ;
     RECT  13.093 11.76 13.208 12.84 ;
     RECT  12.133 14.208 13.208 14.856 ;
     RECT  12.053 16.272 13.208 16.392 ;
     RECT  13.165 17.616 13.208 22.584 ;
     RECT  13.165 23.712 13.208 24.408 ;
     RECT  12.445 25.632 13.208 27.912 ;
     RECT  12.661 29.04 13.208 34.2 ;
     RECT  12.445 35.28 13.208 36.984 ;
     RECT  13.129 38.16 13.208 43.176 ;
     RECT  13.208 2.148 13.312 43.176 ;
     RECT  13.312 2.418 13.385 43.176 ;
     RECT  12.985 0.048 13.453 0.552 ;
     RECT  13.385 2.418 13.465 41.16 ;
     RECT  13.465 2.418 13.504 41.016 ;
     RECT  13.504 36 13.529 36.264 ;
     RECT  13.453 0.048 13.537 0.6 ;
     RECT  13.504 23.856 13.637 25.128 ;
     RECT  13.504 14.208 13.709 19.272 ;
     RECT  13.504 2.418 13.745 5.496 ;
     RECT  13.504 30.816 13.817 34.392 ;
     RECT  13.745 2.88 13.889 5.496 ;
     RECT  13.537 0.048 13.907 0.504 ;
     RECT  13.504 6.624 13.955 7.656 ;
     RECT  13.907 0.048 13.997 0.408 ;
     RECT  13.997 0.144 14.041 0.408 ;
     RECT  14.041 0.192 14.099 0.408 ;
     RECT  13.385 42.144 14.099 43.176 ;
     RECT  13.504 26.304 14.105 29.064 ;
     RECT  13.529 36.048 14.141 36.264 ;
     RECT  14.099 0.288 14.195 0.408 ;
     RECT  13.504 10.848 14.213 13.08 ;
     RECT  13.504 37.584 14.213 41.016 ;
     RECT  14.213 37.584 14.243 40.968 ;
     RECT  14.105 26.544 14.387 29.064 ;
     RECT  13.504 9.648 14.492 9.72 ;
     RECT  14.213 10.848 14.492 11.448 ;
     RECT  13.889 5.28 14.537 5.496 ;
     RECT  13.709 17.04 14.597 19.272 ;
     RECT  13.817 30.816 14.605 31.944 ;
     RECT  13.817 33.552 14.605 34.392 ;
     RECT  13.709 14.208 14.653 15.624 ;
     RECT  13.637 23.856 14.677 23.928 ;
     RECT  14.597 17.04 14.681 19.416 ;
     RECT  14.213 12.816 14.713 13.08 ;
     RECT  14.653 14.208 14.713 14.28 ;
     RECT  14.653 15.408 14.749 15.624 ;
     RECT  14.605 33.552 14.753 34.632 ;
     RECT  14.141 36.24 14.785 36.264 ;
     RECT  14.492 9.648 14.821 11.448 ;
     RECT  14.099 42.192 14.825 43.176 ;
     RECT  13.504 20.544 14.828 22.584 ;
     RECT  14.605 30.624 14.857 31.944 ;
     RECT  14.713 12.816 14.897 14.28 ;
     RECT  14.828 20.544 14.915 22.776 ;
     RECT  14.857 30.576 14.929 31.944 ;
     RECT  14.929 29.808 14.969 31.944 ;
     RECT  14.677 23.808 15.001 23.928 ;
     RECT  14.785 36.24 15.005 37.032 ;
     RECT  14.969 29.808 15.041 31.896 ;
     RECT  15.041 30.624 15.077 31.896 ;
     RECT  14.195 0.288 15.109 0.36 ;
     RECT  14.681 17.04 15.113 19.272 ;
     RECT  14.915 20.544 15.181 22.056 ;
     RECT  13.955 6.624 15.185 7.416 ;
     RECT  14.317 1.728 15.205 1.752 ;
     RECT  13.889 2.88 15.205 4.2 ;
     RECT  15.205 1.728 15.253 4.2 ;
     RECT  15.185 6.624 15.253 7.08 ;
     RECT  14.749 15.408 15.253 15.912 ;
     RECT  15.113 17.04 15.253 18.888 ;
     RECT  15.109 0.24 15.281 0.36 ;
     RECT  14.821 9.12 15.289 11.448 ;
     RECT  15.289 8.688 15.301 11.448 ;
     RECT  15.281 0.144 15.325 0.36 ;
     RECT  15.001 23.472 15.325 23.928 ;
     RECT  13.637 25.104 15.325 25.128 ;
     RECT  15.005 37.008 15.361 37.032 ;
     RECT  14.243 38.16 15.361 40.968 ;
     RECT  15.181 20.304 15.365 22.056 ;
     RECT  15.325 23.472 15.401 25.128 ;
     RECT  15.325 0.048 15.589 0.36 ;
     RECT  15.301 8.688 15.617 11.64 ;
     RECT  15.401 23.52 15.653 25.128 ;
     RECT  14.753 33.552 15.721 34.2 ;
     RECT  15.365 20.832 15.725 22.056 ;
     RECT  14.387 26.544 15.793 28.68 ;
     RECT  15.361 37.008 15.797 40.968 ;
     RECT  15.253 15.408 15.827 18.888 ;
     RECT  15.721 33.552 15.829 34.728 ;
     RECT  15.827 15.408 15.833 16.44 ;
     RECT  15.653 25.104 15.833 25.128 ;
     RECT  15.589 0.048 15.877 0.504 ;
     RECT  15.253 1.728 15.905 4.296 ;
     RECT  14.897 12.816 15.905 13.8 ;
     RECT  15.617 9.504 16.009 11.64 ;
     RECT  16.009 9.504 16.085 11.784 ;
     RECT  15.793 26.208 16.115 28.68 ;
     RECT  15.905 3.984 16.117 4.296 ;
     RECT  15.833 15.408 16.117 16.296 ;
     RECT  15.797 38.784 16.121 40.968 ;
     RECT  15.253 6.096 16.369 7.08 ;
     RECT  16.085 11.136 16.409 11.784 ;
     RECT  16.405 35.904 16.441 35.928 ;
     RECT  15.797 37.008 16.441 37.656 ;
     RECT  15.829 33.024 16.445 34.728 ;
     RECT  16.369 6.096 16.477 7.416 ;
     RECT  16.477 6.096 16.481 7.992 ;
     RECT  16.445 33.6 16.489 34.728 ;
     RECT  16.117 14.976 16.517 16.296 ;
     RECT  16.441 35.904 16.517 37.656 ;
     RECT  16.117 3.984 16.549 5.064 ;
     RECT  16.481 6.096 16.549 6.12 ;
     RECT  16.115 26.208 16.589 28.44 ;
     RECT  16.549 3.984 16.595 6.12 ;
     RECT  15.653 23.52 16.625 23.544 ;
     RECT  16.085 9.504 16.693 10.152 ;
     RECT  15.905 1.728 16.697 2.28 ;
     RECT  16.595 5.712 16.733 6.12 ;
     RECT  16.517 36.624 16.733 37.656 ;
     RECT  16.517 15.792 16.837 16.296 ;
     RECT  16.481 7.2 16.873 7.992 ;
     RECT  16.837 15.792 16.873 16.632 ;
     RECT  15.827 18 16.873 18.888 ;
     RECT  15.725 20.832 16.909 21.576 ;
     RECT  15.077 30.624 16.933 30.84 ;
     RECT  15.905 12.816 16.981 13.704 ;
     RECT  16.933 30.384 16.981 30.84 ;
     RECT  15.077 31.872 16.981 31.896 ;
     RECT  14.825 42.96 17.021 43.176 ;
     RECT  16.589 26.208 17.053 27.912 ;
     RECT  16.981 30.384 17.057 31.896 ;
     RECT  16.873 7.2 17.093 8.04 ;
     RECT  16.873 15.792 17.129 18.888 ;
     RECT  16.595 3.984 17.161 4.68 ;
     RECT  16.693 9.072 17.165 10.152 ;
     RECT  16.409 11.136 17.165 11.256 ;
     RECT  15.877 0.048 17.237 0.6 ;
     RECT  16.981 12.528 17.269 13.704 ;
     RECT  16.909 20.688 17.269 21.576 ;
     RECT  17.189 29.088 17.273 29.112 ;
     RECT  17.269 20.688 17.305 21.672 ;
     RECT  17.053 25.296 17.377 27.912 ;
     RECT  17.269 12.528 17.411 13.848 ;
     RECT  16.121 38.88 17.449 40.968 ;
     RECT  17.129 18.864 17.485 18.888 ;
     RECT  17.305 19.968 17.485 21.672 ;
     RECT  17.485 18.864 17.521 21.672 ;
     RECT  16.733 36.624 17.525 36.936 ;
     RECT  16.489 33.792 17.557 34.728 ;
     RECT  17.525 36.768 17.633 36.936 ;
     RECT  17.021 42.96 17.665 43.032 ;
     RECT  17.057 30.864 17.701 31.896 ;
     RECT  17.449 38.16 17.809 40.968 ;
     RECT  17.161 3.936 17.845 4.68 ;
     RECT  16.733 6.096 17.845 6.12 ;
     RECT  17.521 18.864 17.845 21.72 ;
     RECT  17.557 33.792 17.845 34.872 ;
     RECT  17.665 42.192 17.881 43.032 ;
     RECT  17.165 11.232 17.953 11.256 ;
     RECT  17.845 33.648 17.953 34.872 ;
     RECT  17.881 42.144 17.957 43.032 ;
     RECT  17.845 3.936 18.025 6.12 ;
     RECT  17.129 17.664 18.133 17.688 ;
     RECT  17.845 18.864 18.133 22.2 ;
     RECT  17.377 24.336 18.133 27.912 ;
     RECT  17.845 29.232 18.169 29.256 ;
     RECT  17.809 38.16 18.205 41.016 ;
     RECT  18.133 17.664 18.241 22.2 ;
     RECT  18.133 23.376 18.241 27.912 ;
     RECT  17.701 30.864 18.241 31.944 ;
     RECT  18.169 29.232 18.277 29.832 ;
     RECT  17.633 36.912 18.277 36.936 ;
     RECT  18.205 38.16 18.313 41.16 ;
     RECT  17.957 42.144 18.313 42.312 ;
     RECT  18.025 3.696 18.341 6.12 ;
     RECT  18.241 30.864 18.349 32.52 ;
     RECT  17.237 0.096 18.373 0.6 ;
     RECT  16.697 2.064 18.373 2.28 ;
     RECT  18.241 17.664 18.421 27.912 ;
     RECT  18.277 28.944 18.421 29.832 ;
     RECT  17.953 11.232 18.457 11.448 ;
     RECT  17.411 12.816 18.457 13.848 ;
     RECT  17.129 15.792 18.457 16.632 ;
     RECT  18.421 17.664 18.457 29.832 ;
     RECT  18.457 11.232 18.493 13.848 ;
     RECT  18.373 0.096 18.515 2.28 ;
     RECT  18.515 2.064 18.608 2.28 ;
     RECT  18.341 3.696 18.608 6.312 ;
     RECT  17.093 7.968 18.608 8.04 ;
     RECT  17.165 9.072 18.608 10.104 ;
     RECT  18.493 11.232 18.608 14.136 ;
     RECT  18.457 15.792 18.608 29.832 ;
     RECT  18.349 30.864 18.608 32.568 ;
     RECT  17.953 33.552 18.608 35.784 ;
     RECT  18.277 36.912 18.608 37.08 ;
     RECT  18.313 38.16 18.608 42.312 ;
     RECT  18.608 2.064 18.904 42.312 ;
     RECT  18.904 39.888 19.069 42.312 ;
     RECT  18.904 2.064 19.073 16.92 ;
     RECT  18.904 24.48 19.091 30.024 ;
     RECT  19.069 39.888 19.133 43.032 ;
     RECT  19.073 7.968 19.181 16.92 ;
     RECT  18.515 0.096 19.217 0.552 ;
     RECT  18.904 38.544 19.253 38.76 ;
     RECT  18.904 31.2 19.289 37.08 ;
     RECT  19.289 31.824 19.331 37.08 ;
     RECT  19.073 2.064 19.379 6.984 ;
     RECT  19.331 31.824 19.397 32.52 ;
     RECT  19.379 3.936 19.793 6.984 ;
     RECT  19.133 39.888 19.801 43.08 ;
     RECT  19.331 35.616 19.811 37.032 ;
     RECT  19.181 7.968 19.907 16.536 ;
     RECT  18.904 21.456 19.933 22.2 ;
     RECT  19.933 21.456 19.969 22.776 ;
     RECT  19.091 24.48 20.005 25.272 ;
     RECT  19.969 21.12 20.041 22.776 ;
     RECT  19.907 7.968 20.051 13.32 ;
     RECT  20.041 21.072 20.113 22.776 ;
     RECT  19.091 26.544 20.113 30.024 ;
     RECT  20.051 7.968 20.147 13.128 ;
     RECT  19.801 39.888 20.147 41.64 ;
     RECT  20.113 21.072 20.149 23.064 ;
     RECT  20.005 24.336 20.149 25.272 ;
     RECT  20.147 39.888 20.293 41.016 ;
     RECT  20.293 39.264 20.329 41.016 ;
     RECT  19.811 36.432 20.365 37.032 ;
     RECT  20.329 38.736 20.38 41.016 ;
     RECT  20.149 20.592 20.389 23.064 ;
     RECT  20.149 24.288 20.389 25.272 ;
     RECT  19.397 31.872 20.401 32.52 ;
     RECT  19.331 33.552 20.401 34.248 ;
     RECT  20.389 20.592 20.476 25.272 ;
     RECT  19.379 2.064 20.533 2.856 ;
     RECT  19.793 3.936 20.533 5.688 ;
     RECT  19.793 6.96 20.533 6.984 ;
     RECT  20.147 7.968 20.533 9.528 ;
     RECT  20.113 26.544 20.545 30.216 ;
     RECT  20.401 31.872 20.545 34.776 ;
     RECT  18.904 18 20.653 19.368 ;
     RECT  20.533 2.064 20.693 5.688 ;
     RECT  20.545 26.544 20.693 34.776 ;
     RECT  19.217 0.144 20.729 0.552 ;
     RECT  20.693 30.192 20.729 34.776 ;
     RECT  20.693 2.064 20.765 5.352 ;
     RECT  19.801 43.008 20.821 43.08 ;
     RECT  20.533 6.96 20.945 9.528 ;
     RECT  20.821 42.912 20.965 43.08 ;
     RECT  20.945 8.976 21.017 9.528 ;
     RECT  20.147 10.992 21.049 13.128 ;
     RECT  19.907 14.304 21.049 16.536 ;
     RECT  20.653 17.616 21.049 19.368 ;
     RECT  20.476 20.592 21.049 23.352 ;
     RECT  20.476 24.336 21.053 25.272 ;
     RECT  21.049 17.616 21.089 23.352 ;
     RECT  20.365 36.432 21.089 37.656 ;
     RECT  20.965 42.816 21.107 43.08 ;
     RECT  20.765 2.064 21.125 5.208 ;
     RECT  21.049 10.992 21.157 16.536 ;
     RECT  21.157 10.944 21.197 16.536 ;
     RECT  21.089 18.768 21.233 23.352 ;
     RECT  20.38 39.888 21.341 41.016 ;
     RECT  21.125 2.256 21.347 5.208 ;
     RECT  21.197 13.584 21.373 16.536 ;
     RECT  21.089 17.616 21.373 17.64 ;
     RECT  21.089 37.152 21.373 37.656 ;
     RECT  20.38 38.736 21.373 38.808 ;
     RECT  20.729 0.144 21.377 0.504 ;
     RECT  21.107 43.008 21.377 43.08 ;
     RECT  20.945 6.96 21.413 7.896 ;
     RECT  21.373 13.584 21.485 17.64 ;
     RECT  21.017 8.976 21.557 9 ;
     RECT  20.693 26.544 21.557 28.92 ;
     RECT  20.729 31.92 21.589 34.776 ;
     RECT  21.347 4.656 21.593 5.208 ;
     RECT  21.053 24.912 21.635 25.272 ;
     RECT  21.197 10.944 21.637 12.552 ;
     RECT  21.485 13.584 21.731 16.536 ;
     RECT  21.233 20.304 21.733 23.352 ;
     RECT  21.731 15.168 21.737 16.536 ;
     RECT  21.733 20.304 21.737 23.928 ;
     RECT  21.341 40.32 21.737 41.016 ;
     RECT  21.731 13.584 21.773 14.136 ;
     RECT  21.557 26.592 21.773 28.92 ;
     RECT  21.373 37.152 21.773 38.808 ;
     RECT  20.729 30.192 21.841 30.216 ;
     RECT  21.737 22.512 21.845 23.928 ;
     RECT  21.589 31.92 21.845 34.824 ;
     RECT  21.845 23.904 21.881 23.928 ;
     RECT  21.841 30.192 21.881 30.36 ;
     RECT  21.637 10.608 21.985 12.552 ;
     RECT  21.347 2.256 21.989 3.432 ;
     RECT  21.377 0.336 22.061 0.504 ;
     RECT  21.413 7.344 22.213 7.896 ;
     RECT  22.213 7.344 22.3 8.04 ;
     RECT  21.773 13.728 22.421 14.136 ;
     RECT  21.737 15.408 22.453 16.536 ;
     RECT  21.485 17.616 22.453 17.64 ;
     RECT  21.737 20.304 22.457 21.48 ;
     RECT  21.985 10.224 22.508 12.552 ;
     RECT  22.508 9.648 22.525 12.552 ;
     RECT  22.061 0.48 22.565 0.504 ;
     RECT  22.3 7.344 22.595 7.896 ;
     RECT  21.989 2.736 22.597 3.432 ;
     RECT  22.597 6.288 22.669 6.312 ;
     RECT  22.595 7.344 22.669 7.656 ;
     RECT  21.773 37.152 22.741 37.656 ;
     RECT  22.597 2.736 22.745 3.576 ;
     RECT  21.773 26.592 22.781 27.912 ;
     RECT  22.525 9.36 22.787 12.552 ;
     RECT  21.737 40.32 22.813 40.872 ;
     RECT  21.845 33.072 22.853 34.824 ;
     RECT  22.813 40.32 22.853 40.968 ;
     RECT  22.453 15.408 22.885 17.64 ;
     RECT  22.787 9.888 22.889 12.552 ;
     RECT  22.741 37.152 22.889 37.704 ;
     RECT  22.745 2.784 22.925 3.576 ;
     RECT  22.669 6.288 22.961 7.656 ;
     RECT  22.889 37.152 22.961 37.656 ;
     RECT  22.961 7.632 22.997 7.656 ;
     RECT  21.635 24.912 23.065 24.936 ;
     RECT  23.065 24.72 23.173 24.936 ;
     RECT  22.781 27.888 23.209 27.912 ;
     RECT  21.773 28.896 23.209 28.92 ;
     RECT  21.845 22.512 23.245 22.536 ;
     RECT  22.889 10.944 23.317 12.552 ;
     RECT  22.421 13.728 23.317 13.752 ;
     RECT  22.885 15.312 23.317 17.64 ;
     RECT  21.773 38.736 23.317 38.808 ;
     RECT  23.317 10.944 23.461 13.752 ;
     RECT  23.317 14.976 23.461 17.64 ;
     RECT  22.453 36.048 23.461 36.072 ;
     RECT  22.457 20.496 23.533 21.48 ;
     RECT  23.245 22.512 23.533 23.304 ;
     RECT  21.377 43.056 23.609 43.08 ;
     RECT  22.925 3.408 23.612 3.576 ;
     RECT  21.593 5.088 23.612 5.208 ;
     RECT  21.233 18.768 23.653 19.272 ;
     RECT  23.533 20.496 23.653 23.304 ;
     RECT  21.845 31.92 23.677 31.944 ;
     RECT  23.677 31.92 23.708 32.04 ;
     RECT  23.461 10.944 23.749 17.64 ;
     RECT  23.653 18.768 23.749 23.304 ;
     RECT  21.881 30.336 23.749 30.36 ;
     RECT  23.708 31.536 23.749 32.04 ;
     RECT  23.612 3.408 23.857 5.208 ;
     RECT  22.961 6.288 23.857 6.6 ;
     RECT  22.781 26.592 23.893 26.76 ;
     RECT  23.209 27.888 23.893 29.256 ;
     RECT  23.857 3.408 23.929 6.6 ;
     RECT  22.961 37.152 23.965 37.176 ;
     RECT  23.929 2.832 24.008 6.6 ;
     RECT  22.889 9.888 24.008 9.912 ;
     RECT  23.749 10.944 24.008 23.304 ;
     RECT  23.173 24.72 24.008 25.032 ;
     RECT  23.893 26.592 24.008 29.256 ;
     RECT  23.749 30.336 24.008 32.04 ;
     RECT  22.853 33.168 24.008 34.824 ;
     RECT  23.461 35.904 24.008 36.072 ;
     RECT  23.965 37.056 24.008 37.176 ;
     RECT  23.317 38.736 24.008 39.576 ;
     RECT  22.853 40.56 24.008 40.968 ;
     RECT  24.008 2.148 24.112 41.052 ;
     RECT  24.112 2.418 24.304 40.968 ;
     RECT  24.304 33.264 24.437 34.536 ;
     RECT  24.304 2.64 24.473 3.912 ;
     RECT  24.473 3.648 24.617 3.912 ;
     RECT  24.304 9.888 24.725 25.32 ;
     RECT  24.304 26.592 24.725 29.256 ;
     RECT  24.304 5.088 24.797 7.512 ;
     RECT  24.797 5.088 24.803 5.736 ;
     RECT  24.617 3.648 24.833 3.672 ;
     RECT  24.725 26.592 24.905 26.664 ;
     RECT  24.725 15.312 25.013 25.32 ;
     RECT  24.797 6.816 25.049 7.512 ;
     RECT  25.013 19.056 25.121 25.32 ;
     RECT  24.304 30.336 25.297 32.232 ;
     RECT  24.437 33.264 25.297 33.672 ;
     RECT  25.013 15.312 25.373 17.64 ;
     RECT  25.121 19.056 25.373 25.128 ;
     RECT  25.297 30.336 25.441 33.672 ;
     RECT  25.441 30.336 25.481 34.296 ;
     RECT  24.304 40.512 25.513 40.968 ;
     RECT  24.304 35.616 25.553 37.08 ;
     RECT  24.725 27.696 25.589 29.256 ;
     RECT  25.589 29.088 25.657 29.256 ;
     RECT  25.481 30.336 25.657 32.232 ;
     RECT  25.513 40.272 25.661 40.968 ;
     RECT  24.803 5.088 25.801 5.496 ;
     RECT  25.049 7.44 25.801 7.512 ;
     RECT  25.477 8.544 25.801 8.568 ;
     RECT  25.801 7.44 25.841 8.568 ;
     RECT  25.841 7.92 25.945 8.568 ;
     RECT  24.473 2.64 26.021 2.664 ;
     RECT  25.481 33.648 26.021 34.296 ;
     RECT  24.725 9.888 26.129 14.232 ;
     RECT  24.905 26.592 26.165 26.616 ;
     RECT  25.657 29.088 26.165 32.232 ;
     RECT  25.373 19.056 26.197 21.96 ;
     RECT  26.089 2.736 26.245 3.432 ;
     RECT  25.801 5.088 26.245 6.312 ;
     RECT  25.553 35.616 26.269 36.408 ;
     RECT  26.245 2.736 26.381 6.312 ;
     RECT  25.373 22.992 26.381 25.128 ;
     RECT  26.165 30.816 26.453 32.232 ;
     RECT  25.373 15.504 26.521 17.64 ;
     RECT  26.381 2.736 26.525 2.76 ;
     RECT  26.197 18.768 26.525 21.96 ;
     RECT  26.269 35.328 26.629 36.408 ;
     RECT  25.945 7.92 26.665 8.808 ;
     RECT  26.129 9.888 26.665 13.656 ;
     RECT  26.381 22.992 26.741 23.016 ;
     RECT  26.629 35.328 26.773 36.648 ;
     RECT  24.304 38.208 26.773 38.76 ;
     RECT  25.661 40.272 26.813 40.872 ;
     RECT  26.773 35.328 26.819 38.76 ;
     RECT  26.525 18.864 26.849 21.96 ;
     RECT  25.589 27.696 26.881 27.912 ;
     RECT  26.165 29.088 26.881 29.352 ;
     RECT  26.665 7.92 26.921 13.656 ;
     RECT  26.521 14.88 26.993 17.64 ;
     RECT  26.881 27.696 27.097 29.352 ;
     RECT  27.097 27.072 27.137 29.352 ;
     RECT  26.921 9.696 27.173 13.656 ;
     RECT  27.173 9.696 27.245 11.688 ;
     RECT  26.819 35.328 27.353 36.456 ;
     RECT  27.353 35.328 27.425 35.976 ;
     RECT  26.381 24.096 27.457 25.128 ;
     RECT  27.457 23.856 27.529 25.128 ;
     RECT  26.021 33.648 27.529 33.672 ;
     RECT  26.381 4.224 27.541 5.544 ;
     RECT  27.541 4.224 27.548 5.736 ;
     RECT  27.548 4.224 27.565 5.976 ;
     RECT  27.529 33.168 27.589 33.864 ;
     RECT  26.921 7.92 27.635 8.52 ;
     RECT  27.137 29.328 27.637 29.352 ;
     RECT  27.589 32.88 27.676 33.864 ;
     RECT  27.565 3.936 27.677 5.976 ;
     RECT  27.676 33.168 27.677 33.864 ;
     RECT  27.173 12.768 27.821 13.656 ;
     RECT  26.849 20.592 27.845 21.96 ;
     RECT  27.677 5.088 27.853 5.976 ;
     RECT  27.529 23.856 27.923 25.656 ;
     RECT  27.853 5.088 27.929 6.264 ;
     RECT  27.245 9.696 27.929 11.496 ;
     RECT  27.025 38.832 27.953 38.856 ;
     RECT  27.677 3.936 27.961 4.008 ;
     RECT  27.961 3.408 28.067 4.008 ;
     RECT  27.137 27.072 28.069 28.2 ;
     RECT  27.929 5.424 28.108 6.264 ;
     RECT  26.993 15.696 28.172 17.64 ;
     RECT  28.069 26.88 28.177 28.2 ;
     RECT  27.637 29.328 28.177 29.592 ;
     RECT  28.172 15.648 28.213 17.64 ;
     RECT  28.177 26.88 28.249 29.592 ;
     RECT  27.821 13.104 28.309 13.656 ;
     RECT  28.213 14.736 28.309 17.64 ;
     RECT  26.813 40.512 28.321 40.872 ;
     RECT  26.849 18.864 28.357 19.464 ;
     RECT  27.845 20.592 28.357 22.776 ;
     RECT  27.923 23.856 28.357 24.504 ;
     RECT  28.321 39.936 28.361 40.872 ;
     RECT  28.108 5.472 28.501 6.264 ;
     RECT  27.953 38.736 28.508 38.856 ;
     RECT  27.425 35.952 28.537 35.976 ;
     RECT  28.361 39.936 28.549 40.44 ;
     RECT  27.929 10.224 28.573 11.496 ;
     RECT  27.923 25.632 28.597 25.656 ;
     RECT  28.249 26.784 28.597 29.592 ;
     RECT  27.677 33.84 28.652 33.864 ;
     RECT  28.652 33.84 28.693 34.056 ;
     RECT  28.357 18.864 28.897 24.504 ;
     RECT  28.597 25.632 28.897 29.592 ;
     RECT  28.067 3.408 29.041 3.432 ;
     RECT  28.573 10.224 29.149 12.12 ;
     RECT  28.537 35.328 29.149 35.976 ;
     RECT  29.041 3.408 29.408 3.912 ;
     RECT  28.501 5.472 29.408 6.84 ;
     RECT  27.635 7.92 29.408 7.944 ;
     RECT  29.185 9.072 29.408 9.096 ;
     RECT  29.149 10.128 29.408 12.12 ;
     RECT  28.309 13.104 29.408 17.64 ;
     RECT  28.897 18.864 29.408 29.592 ;
     RECT  26.453 30.816 29.408 31.656 ;
     RECT  28.693 33.024 29.408 34.056 ;
     RECT  29.149 35.328 29.408 36.36 ;
     RECT  26.819 37.584 29.408 37.608 ;
     RECT  28.508 38.64 29.408 38.856 ;
     RECT  28.549 39.888 29.408 40.44 ;
     RECT  29.408 2.148 29.512 41.052 ;
     RECT  29.512 2.418 29.704 40.782 ;
     RECT  29.704 12.48 29.765 13.32 ;
     RECT  29.704 25.824 29.765 30.264 ;
     RECT  29.765 26.64 29.891 30.264 ;
     RECT  29.704 23.328 29.909 24.744 ;
     RECT  29.704 38.16 29.939 39.384 ;
     RECT  29.704 14.736 29.945 16.632 ;
     RECT  29.704 17.616 29.981 20.328 ;
     RECT  29.704 7.92 29.987 7.944 ;
     RECT  29.945 15.984 30.017 16.632 ;
     RECT  29.704 9.072 30.053 11.256 ;
     RECT  29.981 18.432 30.053 20.328 ;
     RECT  30.053 18.432 30.097 19.416 ;
     RECT  29.909 23.376 30.125 24.744 ;
     RECT  29.891 26.64 30.131 28.152 ;
     RECT  29.704 35.28 30.161 36.888 ;
     RECT  30.053 9.072 30.233 11.016 ;
     RECT  29.704 32.784 30.269 34.248 ;
     RECT  29.765 12.48 30.305 13.176 ;
     RECT  29.939 38.16 30.364 39.336 ;
     RECT  30.017 16.512 30.377 16.632 ;
     RECT  30.161 35.28 30.377 36.36 ;
     RECT  30.131 26.64 30.413 27.912 ;
     RECT  29.704 31.68 30.413 31.8 ;
     RECT  30.377 35.424 30.665 36.36 ;
     RECT  29.704 21.456 30.697 22.056 ;
     RECT  29.704 3.888 30.733 5.928 ;
     RECT  30.305 12.48 30.737 13.128 ;
     RECT  30.733 3.408 30.769 6.024 ;
     RECT  30.737 12.816 30.773 13.128 ;
     RECT  30.773 13.104 30.809 13.128 ;
     RECT  29.704 40.416 30.809 40.44 ;
     RECT  30.233 9.744 30.881 11.016 ;
     RECT  30.769 2.496 30.899 6.024 ;
     RECT  30.125 23.376 30.917 23.688 ;
     RECT  30.899 2.496 30.953 4.872 ;
     RECT  29.891 29.568 30.953 29.784 ;
     RECT  30.413 26.64 30.985 26.856 ;
     RECT  30.881 9.744 30.989 10.92 ;
     RECT  30.665 35.424 31.061 35.448 ;
     RECT  30.269 34.224 31.169 34.248 ;
     RECT  30.125 24.72 31.196 24.744 ;
     RECT  31.196 24.144 31.237 24.744 ;
     RECT  30.985 26.208 31.237 26.856 ;
     RECT  31.237 24.144 31.283 26.856 ;
     RECT  30.953 2.496 31.349 4.776 ;
     RECT  30.364 38.16 31.385 38.952 ;
     RECT  30.413 31.776 31.417 31.8 ;
     RECT  30.269 32.784 31.417 33.192 ;
     RECT  29.945 14.736 31.453 14.76 ;
     RECT  30.989 9.744 31.457 10.296 ;
     RECT  31.417 31.776 31.457 33.192 ;
     RECT  30.097 18.432 31.525 18.456 ;
     RECT  31.349 3.072 31.529 4.776 ;
     RECT  30.899 6 31.565 6.024 ;
     RECT  31.457 10.128 31.565 10.296 ;
     RECT  31.453 14.736 31.597 14.952 ;
     RECT  31.633 7.344 31.669 7.368 ;
     RECT  30.697 21.456 31.705 22.2 ;
     RECT  31.525 18.432 31.777 18.984 ;
     RECT  31.529 4.08 31.804 4.776 ;
     RECT  30.377 16.512 31.82 16.584 ;
     RECT  31.705 21.12 31.82 22.2 ;
     RECT  30.413 27.888 31.849 27.912 ;
     RECT  31.345 29.04 31.849 29.064 ;
     RECT  31.82 16.512 31.861 17.016 ;
     RECT  31.777 18.192 31.861 18.984 ;
     RECT  31.82 21.12 31.861 22.488 ;
     RECT  31.861 16.512 31.907 18.984 ;
     RECT  31.861 20.448 31.907 22.488 ;
     RECT  31.283 26.832 31.909 26.856 ;
     RECT  31.849 27.888 31.909 29.064 ;
     RECT  31.907 20.448 31.948 22.2 ;
     RECT  31.457 31.872 31.957 33.192 ;
     RECT  31.385 38.4 31.993 38.952 ;
     RECT  31.909 26.832 31.997 29.064 ;
     RECT  31.993 38.4 32.029 39 ;
     RECT  31.993 37.296 32.065 37.32 ;
     RECT  31.957 31.872 32.141 33.576 ;
     RECT  31.907 16.512 32.173 16.536 ;
     RECT  32.137 19.968 32.221 19.992 ;
     RECT  32.141 32.784 32.321 33.576 ;
     RECT  31.997 26.832 32.357 28.104 ;
     RECT  31.907 18.96 32.425 18.984 ;
     RECT  31.381 34.896 32.437 34.92 ;
     RECT  32.437 34.608 32.483 34.92 ;
     RECT  31.597 14.112 32.677 14.952 ;
     RECT  32.065 36.384 32.717 37.32 ;
     RECT  32.636 12.528 32.723 12.552 ;
     RECT  32.717 36.384 32.749 36.552 ;
     RECT  31.669 6.816 32.857 7.368 ;
     RECT  30.841 8.544 32.857 8.568 ;
     RECT  32.677 13.728 32.861 14.952 ;
     RECT  32.857 6.816 32.897 8.568 ;
     RECT  32.425 18.96 32.897 19.416 ;
     RECT  31.804 4.752 33.013 4.776 ;
     RECT  32.897 6.816 33.059 7.992 ;
     RECT  31.948 21.12 33.073 22.2 ;
     RECT  32.029 38.4 33.073 39.864 ;
     RECT  32.897 19.056 33.113 19.416 ;
     RECT  31.283 25.44 33.181 25.464 ;
     RECT  33.181 25.44 33.217 26.232 ;
     RECT  31.565 10.272 33.257 10.296 ;
     RECT  32.173 16.128 33.293 16.536 ;
     RECT  33.013 4.512 33.329 5.64 ;
     RECT  33.059 7.344 33.329 7.992 ;
     RECT  33.073 21.12 33.437 23.16 ;
     RECT  31.201 30.192 33.505 30.216 ;
     RECT  32.321 32.784 33.541 33.048 ;
     RECT  32.483 34.608 33.541 34.824 ;
     RECT  33.437 21.216 33.545 23.16 ;
     RECT  33.545 23.136 33.587 23.16 ;
     RECT  33.541 32.784 33.625 34.824 ;
     RECT  31.907 17.616 33.761 17.64 ;
     RECT  33.037 11.28 33.793 11.304 ;
     RECT  33.217 24.48 33.865 26.232 ;
     RECT  32.357 27.36 33.937 28.104 ;
     RECT  33.865 23.952 33.973 26.232 ;
     RECT  33.937 27.36 33.973 28.152 ;
     RECT  33.329 5.184 34.045 5.64 ;
     RECT  32.861 14.928 34.081 14.952 ;
     RECT  33.113 19.296 34.124 19.416 ;
     RECT  34.124 18.672 34.165 19.416 ;
     RECT  31.529 3.072 34.213 3.096 ;
     RECT  33.329 7.968 34.22 7.992 ;
     RECT  33.901 9.024 34.22 9.048 ;
     RECT  34.22 7.968 34.225 9.048 ;
     RECT  34.045 5.184 34.261 6.072 ;
     RECT  32.749 35.952 34.261 36.552 ;
     RECT  33.073 37.584 34.261 39.864 ;
     RECT  33.793 11.232 34.369 11.304 ;
     RECT  34.369 10.848 34.441 11.304 ;
     RECT  34.261 5.184 34.585 6.696 ;
     RECT  34.225 7.968 34.585 9.528 ;
     RECT  33.625 34.368 34.621 34.824 ;
     RECT  34.261 35.952 34.621 39.864 ;
     RECT  34.213 3.072 34.765 3.432 ;
     RECT  34.765 2.496 34.808 3.432 ;
     RECT  34.585 5.184 34.808 9.864 ;
     RECT  34.441 10.848 34.808 12.072 ;
     RECT  32.861 13.728 34.808 13.752 ;
     RECT  34.081 14.928 34.808 15.288 ;
     RECT  33.293 16.512 34.808 16.536 ;
     RECT  34.165 18.672 34.808 20.088 ;
     RECT  33.545 21.216 34.808 22.056 ;
     RECT  33.973 23.952 34.808 28.152 ;
     RECT  33.505 30.192 34.808 30.648 ;
     RECT  33.793 31.776 34.808 31.8 ;
     RECT  33.625 32.784 34.808 33.144 ;
     RECT  34.621 34.368 34.808 39.864 ;
     RECT  34.808 2.148 34.912 41.052 ;
     RECT  34.912 2.418 35.104 40.782 ;
     RECT  35.104 34.608 35.201 37.08 ;
     RECT  35.104 39.216 35.219 40.44 ;
     RECT  35.104 2.418 35.345 4.824 ;
     RECT  35.104 20.832 35.561 22.056 ;
     RECT  35.104 11.376 35.597 11.4 ;
     RECT  35.104 14.64 35.633 19.32 ;
     RECT  35.633 14.688 35.705 19.32 ;
     RECT  35.104 12.624 35.741 13.368 ;
     RECT  35.345 2.418 35.989 2.52 ;
     RECT  35.104 23.136 36.085 23.4 ;
     RECT  35.104 25.152 36.137 25.56 ;
     RECT  35.104 29.664 36.169 33.576 ;
     RECT  35.201 34.608 36.169 36.552 ;
     RECT  35.104 26.544 36.281 28.44 ;
     RECT  35.104 6.576 36.313 10.344 ;
     RECT  35.104 38.208 36.349 38.232 ;
     RECT  36.169 29.664 36.421 36.552 ;
     RECT  36.349 37.632 36.421 38.232 ;
     RECT  35.741 12.624 36.565 12.648 ;
     RECT  36.313 6.576 36.611 10.488 ;
     RECT  35.345 3.888 36.637 4.824 ;
     RECT  35.705 18.432 36.677 19.32 ;
     RECT  35.989 2.304 36.745 2.52 ;
     RECT  35.561 20.832 36.745 21.912 ;
     RECT  36.085 23.136 36.745 23.64 ;
     RECT  36.745 2.256 36.785 2.52 ;
     RECT  36.281 26.592 36.889 28.44 ;
     RECT  36.421 29.664 36.889 38.232 ;
     RECT  36.745 20.832 36.961 23.64 ;
     RECT  36.637 3.6 37.001 4.824 ;
     RECT  36.611 6.576 37.045 8.184 ;
     RECT  35.705 14.688 37.045 17.016 ;
     RECT  36.889 26.592 37.069 38.232 ;
     RECT  37.045 6.288 37.091 8.184 ;
     RECT  36.565 12.528 37.105 12.648 ;
     RECT  36.611 9.216 37.109 10.488 ;
     RECT  37.069 26.592 37.189 38.376 ;
     RECT  35.219 39.36 37.189 40.44 ;
     RECT  36.961 20.544 37.213 23.64 ;
     RECT  37.001 3.6 37.217 4.536 ;
     RECT  37.189 26.592 37.217 40.44 ;
     RECT  37.217 28.704 37.253 40.44 ;
     RECT  37.253 33.792 37.276 40.44 ;
     RECT  37.213 20.544 37.285 23.688 ;
     RECT  36.137 25.296 37.285 25.56 ;
     RECT  37.276 33.792 37.331 38.376 ;
     RECT  37.276 39.6 37.465 40.44 ;
     RECT  37.091 7.392 37.609 8.184 ;
     RECT  37.105 12.144 37.613 12.648 ;
     RECT  36.785 2.256 37.757 2.28 ;
     RECT  36.677 19.296 37.789 19.32 ;
     RECT  37.285 20.544 37.825 25.56 ;
     RECT  37.217 26.592 37.825 27.624 ;
     RECT  37.465 39.6 37.897 40.632 ;
     RECT  37.331 36.528 37.937 38.376 ;
     RECT  37.331 33.792 37.973 35.448 ;
     RECT  37.109 9.792 38.189 10.488 ;
     RECT  37.613 12.144 38.225 12.168 ;
     RECT  37.045 13.824 38.225 17.016 ;
     RECT  37.253 28.704 38.225 32.808 ;
     RECT  37.937 36.528 38.225 38.184 ;
     RECT  37.609 7.392 38.257 8.52 ;
     RECT  38.189 9.792 38.257 9.912 ;
     RECT  37.973 34.224 38.293 35.448 ;
     RECT  38.225 36.528 38.293 38.136 ;
     RECT  38.225 14.928 38.329 17.016 ;
     RECT  37.825 20.544 38.365 27.624 ;
     RECT  38.225 28.704 38.365 29.352 ;
     RECT  38.225 30.48 38.396 32.808 ;
     RECT  37.217 4.176 38.653 4.536 ;
     RECT  37.091 6.288 38.653 6.312 ;
     RECT  38.365 20.544 38.665 29.352 ;
     RECT  38.257 7.392 38.693 9.912 ;
     RECT  38.293 34.224 38.801 38.136 ;
     RECT  38.653 4.176 38.833 6.312 ;
     RECT  37.789 18.672 38.873 19.32 ;
     RECT  37.897 39.6 38.941 40.968 ;
     RECT  38.396 30.48 38.977 33.048 ;
     RECT  38.801 34.224 38.977 37.608 ;
     RECT  38.225 13.824 39.049 13.848 ;
     RECT  38.329 14.928 39.053 17.064 ;
     RECT  38.665 24.912 39.053 29.352 ;
     RECT  38.041 2.496 39.085 2.52 ;
     RECT  38.977 30.48 39.125 37.608 ;
     RECT  39.061 17.664 39.161 17.688 ;
     RECT  38.693 7.872 39.301 9.912 ;
     RECT  39.049 13.056 39.301 13.848 ;
     RECT  38.665 20.544 39.301 23.688 ;
     RECT  39.085 2.496 39.373 2.664 ;
     RECT  39.373 2.496 39.404 3.144 ;
     RECT  38.833 4.176 39.404 6.696 ;
     RECT  39.404 2.496 39.445 6.696 ;
     RECT  39.053 28.416 39.517 29.352 ;
     RECT  39.517 28.416 39.685 29.4 ;
     RECT  39.125 30.48 39.685 36.024 ;
     RECT  38.941 39.36 39.697 40.968 ;
     RECT  39.125 37.008 39.877 37.608 ;
     RECT  39.697 38.688 39.877 40.968 ;
     RECT  39.301 12.768 39.985 13.848 ;
     RECT  39.053 14.928 39.985 16.584 ;
     RECT  39.985 12.768 40.129 16.584 ;
     RECT  39.229 0.048 40.165 0.072 ;
     RECT  39.445 2.256 40.208 6.696 ;
     RECT  39.301 7.872 40.208 10.296 ;
     RECT  40.129 12.576 40.208 16.584 ;
     RECT  39.589 18.24 40.208 18.264 ;
     RECT  38.873 19.296 40.208 19.32 ;
     RECT  39.301 20.4 40.208 23.688 ;
     RECT  39.053 24.912 40.208 27.384 ;
     RECT  39.685 28.416 40.208 36.024 ;
     RECT  39.877 37.008 40.208 40.968 ;
     RECT  40.208 2.148 40.312 41.052 ;
     RECT  40.312 2.256 40.504 40.968 ;
     RECT  40.504 20.4 40.529 27.384 ;
     RECT  40.504 3.648 40.565 9.912 ;
     RECT  40.504 2.256 40.673 2.28 ;
     RECT  40.529 20.496 40.739 27.384 ;
     RECT  40.565 7.344 40.745 9.912 ;
     RECT  40.504 28.512 40.787 29.352 ;
     RECT  40.504 30.864 40.787 40.968 ;
     RECT  40.787 30.864 40.835 33.48 ;
     RECT  40.787 34.656 40.835 40.968 ;
     RECT  40.565 3.648 40.925 6.312 ;
     RECT  40.925 3.648 40.961 4.728 ;
     RECT  40.739 20.688 41.033 27.384 ;
     RECT  40.835 32.736 41.069 33.48 ;
     RECT  41.033 20.928 41.105 27.384 ;
     RECT  40.504 11.376 41.141 16.92 ;
     RECT  40.835 37.488 41.177 40.968 ;
     RECT  41.105 21.12 41.219 27.384 ;
     RECT  40.745 7.344 41.651 9.864 ;
     RECT  40.504 18.096 41.717 18.12 ;
     RECT  40.165 0.048 41.785 0.12 ;
     RECT  41.651 8.496 41.785 9.864 ;
     RECT  41.701 29.76 41.788 29.784 ;
     RECT  40.835 34.656 41.929 36.12 ;
     RECT  40.961 3.648 42.001 4.68 ;
     RECT  40.925 5.808 42.001 6.312 ;
     RECT  40.787 28.512 42.001 28.536 ;
     RECT  41.141 16.368 42.037 16.92 ;
     RECT  41.069 33.456 42.109 33.48 ;
     RECT  42.037 16.368 42.181 17.112 ;
     RECT  40.835 30.864 42.181 31.704 ;
     RECT  42.109 32.688 42.181 33.48 ;
     RECT  40.504 19.2 42.253 19.416 ;
     RECT  41.219 21.12 42.253 25.224 ;
     RECT  42.181 30.864 42.288 33.48 ;
     RECT  41.177 38.688 42.289 38.712 ;
     RECT  41.177 39.888 42.289 40.968 ;
     RECT  41.785 8.496 42.293 10.056 ;
     RECT  41.141 11.376 42.325 15.048 ;
     RECT  42.181 16.224 42.325 17.112 ;
     RECT  42.293 8.88 42.332 10.056 ;
     RECT  42.181 1.824 42.361 1.848 ;
     RECT  41.177 37.488 42.361 37.608 ;
     RECT  42.289 38.688 42.361 40.968 ;
     RECT  42.332 8.88 42.365 10.344 ;
     RECT  42.361 37.488 42.433 40.968 ;
     RECT  42.288 30.864 42.505 31.944 ;
     RECT  42.001 3.648 42.563 6.312 ;
     RECT  42.365 8.928 42.577 10.344 ;
     RECT  42.325 11.376 42.577 17.112 ;
     RECT  42.253 19.2 42.649 25.224 ;
     RECT  42.577 8.928 42.653 17.112 ;
     RECT  41.651 7.344 42.725 7.368 ;
     RECT  42.505 30.768 42.725 31.944 ;
     RECT  41.219 26.832 42.793 27.384 ;
     RECT  42.725 30.768 42.793 31.752 ;
     RECT  41.929 34.608 42.793 36.12 ;
     RECT  42.433 37.104 42.793 40.968 ;
     RECT  42.653 8.976 42.797 17.112 ;
     RECT  41.785 0.048 42.812 0.552 ;
     RECT  42.361 1.728 42.812 1.848 ;
     RECT  42.812 0.048 42.899 1.848 ;
     RECT  42.793 26.736 42.908 27.384 ;
     RECT  42.001 28.512 42.908 28.824 ;
     RECT  42.649 19.2 42.941 25.368 ;
     RECT  42.288 33.024 42.949 33.48 ;
     RECT  42.793 34.608 42.949 40.968 ;
     RECT  42.797 14.448 42.973 17.112 ;
     RECT  42.929 18.192 42.973 18.216 ;
     RECT  42.973 14.448 43.013 18.216 ;
     RECT  42.563 4.896 43.049 6.312 ;
     RECT  42.899 1.728 43.193 1.848 ;
     RECT  42.797 8.976 43.229 13.368 ;
     RECT  42.941 20.304 43.285 25.368 ;
     RECT  43.193 1.776 43.301 1.848 ;
     RECT  42.949 33.024 43.369 40.968 ;
     RECT  42.899 0.048 43.373 0.552 ;
     RECT  42.908 26.736 43.379 28.824 ;
     RECT  43.369 33.024 43.409 41.592 ;
     RECT  42.563 3.648 43.429 3.768 ;
     RECT  43.229 8.976 43.445 13.032 ;
     RECT  43.409 36.096 43.445 41.592 ;
     RECT  42.793 30.192 43.589 31.752 ;
     RECT  43.049 5.52 43.661 6.312 ;
     RECT  43.445 37.488 43.697 41.592 ;
     RECT  43.445 8.976 43.729 11.544 ;
     RECT  43.589 30.912 43.733 31.752 ;
     RECT  43.373 0.096 43.763 0.552 ;
     RECT  43.729 8.496 43.801 11.544 ;
     RECT  43.445 36.096 43.805 36.408 ;
     RECT  43.429 2.064 43.945 3.768 ;
     RECT  43.661 5.52 44.012 6.12 ;
     RECT  42.941 19.2 44.017 19.32 ;
     RECT  43.285 20.304 44.017 25.656 ;
     RECT  44.017 19.2 44.053 25.656 ;
     RECT  43.013 14.448 44.089 17.64 ;
     RECT  44.012 5.328 44.099 6.12 ;
     RECT  44.089 14.448 44.243 17.688 ;
     RECT  44.053 19.2 44.245 25.704 ;
     RECT  44.245 18.624 44.305 25.704 ;
     RECT  43.379 26.736 44.305 27.96 ;
     RECT  44.305 18.624 44.332 27.96 ;
     RECT  43.945 2.064 44.341 3.864 ;
     RECT  43.405 28.944 44.341 28.968 ;
     RECT  44.243 14.448 44.381 17.64 ;
     RECT  44.341 2.064 44.417 4.248 ;
     RECT  44.381 14.448 44.417 17.352 ;
     RECT  43.697 39.84 44.449 41.592 ;
     RECT  44.417 2.064 44.477 2.808 ;
     RECT  44.449 39.84 44.485 42.216 ;
     RECT  44.417 14.496 44.489 17.352 ;
     RECT  44.332 18.72 44.525 27.96 ;
     RECT  43.409 33.024 44.557 34.872 ;
     RECT  44.485 39.84 44.557 42.36 ;
     RECT  44.477 1.728 44.561 2.808 ;
     RECT  44.557 33.024 44.629 34.968 ;
     RECT  43.763 0.096 44.809 0.456 ;
     RECT  43.697 37.488 44.809 38.712 ;
     RECT  44.809 0.048 44.881 0.456 ;
     RECT  43.981 7.44 44.953 7.464 ;
     RECT  43.801 8.448 44.953 11.544 ;
     RECT  43.805 36.096 45.061 36.12 ;
     RECT  44.809 37.104 45.061 38.712 ;
     RECT  45.061 36.096 45.133 38.712 ;
     RECT  43.733 30.912 45.349 31.032 ;
     RECT  44.629 32.736 45.397 34.968 ;
     RECT  43.445 13.008 45.457 13.032 ;
     RECT  45.133 36.096 45.529 38.808 ;
     RECT  44.557 39.84 45.529 42.408 ;
     RECT  44.489 15.168 45.565 17.352 ;
     RECT  44.525 18.72 45.565 19.32 ;
     RECT  44.561 2.064 45.608 2.808 ;
     RECT  44.417 3.84 45.608 4.248 ;
     RECT  44.099 6.096 45.608 6.12 ;
     RECT  44.953 7.44 45.608 11.544 ;
     RECT  45.457 12.528 45.608 13.032 ;
     RECT  45.565 15.168 45.608 19.32 ;
     RECT  44.525 20.88 45.608 27.96 ;
     RECT  44.341 28.944 45.608 29.592 ;
     RECT  45.349 30.672 45.608 31.032 ;
     RECT  45.397 32.016 45.608 34.968 ;
     RECT  45.529 36.096 45.608 42.408 ;
     RECT  45.608 2.064 45.701 42.408 ;
     RECT  45.701 2.064 45.904 43.08 ;
     RECT  45.904 11.376 46.019 16.92 ;
     RECT  45.904 7.44 46.109 9.384 ;
     RECT  44.881 0.048 46.141 0.6 ;
     RECT  45.904 18 46.217 25.992 ;
     RECT  45.904 27.072 46.253 35.736 ;
     RECT  46.141 0.048 46.355 0.648 ;
     RECT  45.904 2.064 46.469 6.12 ;
     RECT  45.904 37.008 46.613 43.08 ;
     RECT  46.469 4.896 46.757 6.12 ;
     RECT  46.019 11.376 46.757 16.824 ;
     RECT  46.253 30.288 46.865 35.736 ;
     RECT  46.865 32.304 46.933 35.736 ;
     RECT  46.109 8.976 46.969 9.384 ;
     RECT  46.109 7.44 47.005 7.992 ;
     RECT  46.217 19.296 47.041 25.992 ;
     RECT  46.253 27.072 47.041 28.728 ;
     RECT  46.217 18 47.117 18.264 ;
     RECT  47.041 19.296 47.117 28.728 ;
     RECT  46.969 8.976 47.185 9.528 ;
     RECT  46.757 11.376 47.185 14.568 ;
     RECT  46.613 37.44 47.185 43.08 ;
     RECT  46.757 15.6 47.293 16.824 ;
     RECT  47.117 18 47.293 18.024 ;
     RECT  47.005 6.672 47.329 7.992 ;
     RECT  47.185 8.976 47.329 14.568 ;
     RECT  46.933 32.304 47.333 35.928 ;
     RECT  47.117 20.352 47.365 28.728 ;
     RECT  47.329 6.672 47.369 14.568 ;
     RECT  47.185 37.44 47.369 43.128 ;
     RECT  46.355 0.048 47.461 0.552 ;
     RECT  47.293 15.6 47.477 18.024 ;
     RECT  46.469 2.064 47.509 3.672 ;
     RECT  46.757 4.896 47.509 5.112 ;
     RECT  47.117 19.296 47.581 19.368 ;
     RECT  47.461 0.048 47.605 0.6 ;
     RECT  47.369 37.584 47.621 43.128 ;
     RECT  47.605 0.048 47.693 0.696 ;
     RECT  47.333 32.496 47.725 35.928 ;
     RECT  47.693 0.048 47.737 0.6 ;
     RECT  47.365 20.352 47.801 29.064 ;
     RECT  47.801 20.352 47.837 22.536 ;
     RECT  47.477 16.464 47.843 18.024 ;
     RECT  47.725 32.496 47.873 36.504 ;
     RECT  47.801 23.616 47.905 29.064 ;
     RECT  47.873 32.496 47.945 36.408 ;
     RECT  47.369 7.056 47.981 14.568 ;
     RECT  47.843 16.512 48.161 18.024 ;
     RECT  47.737 0.048 48.305 0.552 ;
     RECT  47.509 2.064 48.337 5.112 ;
     RECT  47.981 7.056 48.349 11.688 ;
     RECT  48.337 2.064 48.377 5.352 ;
     RECT  47.945 32.496 48.481 35.928 ;
     RECT  47.981 12.768 48.557 14.568 ;
     RECT  48.349 7.056 48.593 9.144 ;
     RECT  48.557 13.536 48.593 14.568 ;
     RECT  48.593 8.976 48.611 9.144 ;
     RECT  47.905 23.616 48.697 29.304 ;
     RECT  46.865 30.288 48.697 31.176 ;
     RECT  48.481 32.256 48.737 35.928 ;
     RECT  48.611 9.072 48.845 9.144 ;
     RECT  47.837 20.352 48.877 20.472 ;
     RECT  47.837 21.456 48.877 22.536 ;
     RECT  48.877 20.352 48.899 22.536 ;
     RECT  48.349 10.416 48.949 11.688 ;
     RECT  47.581 19.248 48.949 19.368 ;
     RECT  48.899 20.352 48.949 22.2 ;
     RECT  48.737 35.136 49.021 35.928 ;
     RECT  48.697 23.616 49.025 31.176 ;
     RECT  48.949 10.416 49.052 11.784 ;
     RECT  48.593 13.632 49.061 14.568 ;
     RECT  49.093 15.456 49.141 15.48 ;
     RECT  48.161 16.512 49.141 17.928 ;
     RECT  49.141 15.456 49.205 17.928 ;
     RECT  49.021 35.136 49.205 36.072 ;
     RECT  49.205 15.552 49.237 17.928 ;
     RECT  48.949 19.248 49.237 22.2 ;
     RECT  49.061 13.632 49.241 14.424 ;
     RECT  49.025 30.048 49.301 31.176 ;
     RECT  48.305 0.048 49.421 0.504 ;
     RECT  47.621 38.16 49.427 43.128 ;
     RECT  49.025 23.616 49.561 28.872 ;
     RECT  49.477 37.056 49.564 37.08 ;
     RECT  48.593 7.056 49.565 7.656 ;
     RECT  49.427 42.144 49.597 43.128 ;
     RECT  49.561 23.328 49.601 28.872 ;
     RECT  48.737 32.352 49.673 34.152 ;
     RECT  49.052 10.416 49.781 11.976 ;
     RECT  49.781 10.416 49.813 11.256 ;
     RECT  49.597 13.056 49.813 13.08 ;
     RECT  49.301 30.048 49.813 31.368 ;
     RECT  49.673 32.352 49.813 33.288 ;
     RECT  49.421 0.048 49.817 0.456 ;
     RECT  49.601 23.328 49.853 27.192 ;
     RECT  48.377 4.32 49.916 5.352 ;
     RECT  49.916 4.32 50.003 5.448 ;
     RECT  48.377 2.064 50.029 2.856 ;
     RECT  49.853 25.2 50.044 27.192 ;
     RECT  49.565 7.44 50.101 7.656 ;
     RECT  48.845 9.12 50.101 9.144 ;
     RECT  49.241 14.4 50.209 14.424 ;
     RECT  49.237 15.552 50.209 22.2 ;
     RECT  50.029 2.064 50.281 2.904 ;
     RECT  49.601 28.416 50.281 28.872 ;
     RECT  49.813 30.048 50.281 33.288 ;
     RECT  50.101 7.44 50.353 9.144 ;
     RECT  49.813 10.272 50.353 11.256 ;
     RECT  49.817 0.192 50.429 0.456 ;
     RECT  49.205 35.28 50.497 36.072 ;
     RECT  50.429 0.24 50.609 0.456 ;
     RECT  49.597 42.144 50.609 43.176 ;
     RECT  50.209 14.4 50.629 22.2 ;
     RECT  49.853 23.328 50.629 23.688 ;
     RECT  50.497 35.28 50.641 36.6 ;
     RECT  50.281 28.416 50.713 33.288 ;
     RECT  50.609 0.432 50.717 0.456 ;
     RECT  50.281 2.064 50.753 2.952 ;
     RECT  50.641 35.28 50.785 36.84 ;
     RECT  49.427 38.16 50.785 41.016 ;
     RECT  49.813 12.528 50.821 13.08 ;
     RECT  50.629 14.4 50.821 23.688 ;
     RECT  50.821 12.528 50.869 23.688 ;
     RECT  50.785 35.28 50.869 41.016 ;
     RECT  50.044 25.584 50.893 27.192 ;
     RECT  50.713 28.272 50.893 33.288 ;
     RECT  50.353 7.44 50.965 11.256 ;
     RECT  50.753 2.148 51.008 2.952 ;
     RECT  50.003 4.32 51.008 5.352 ;
     RECT  50.965 6.816 51.008 11.256 ;
     RECT  50.869 12.528 51.008 24.168 ;
     RECT  50.893 25.584 51.008 33.288 ;
     RECT  50.869 34.368 51.008 41.016 ;
     RECT  51.008 2.148 51.112 41.052 ;
     RECT  51.112 2.256 51.304 40.968 ;
     RECT  51.304 26.208 51.329 33.048 ;
     RECT  51.304 14.112 51.473 16.488 ;
     RECT  51.304 10.368 51.761 13.08 ;
     RECT  51.304 34.176 51.827 36.6 ;
     RECT  51.304 4.512 51.833 5.208 ;
     RECT  51.827 34.176 51.841 34.728 ;
     RECT  51.329 29.04 51.875 33.048 ;
     RECT  51.304 9.312 51.941 9.336 ;
     RECT  51.473 14.4 51.941 16.488 ;
     RECT  51.304 22.752 52.297 25.224 ;
     RECT  51.329 26.208 52.297 27.864 ;
     RECT  51.941 14.4 52.337 14.424 ;
     RECT  51.875 30.72 52.477 33.048 ;
     RECT  51.833 5.184 52.517 5.208 ;
     RECT  51.304 6.528 52.549 8.184 ;
     RECT  52.477 30.72 52.549 33.096 ;
     RECT  51.841 34.176 52.549 34.536 ;
     RECT  50.609 43.056 52.553 43.176 ;
     RECT  52.549 6.384 52.585 8.184 ;
     RECT  51.304 2.256 52.661 2.904 ;
     RECT  51.875 29.04 52.697 29.64 ;
     RECT  51.761 10.368 52.729 12.36 ;
     RECT  52.729 10.368 52.813 13.128 ;
     RECT  52.549 30.72 52.837 34.536 ;
     RECT  51.827 35.904 52.837 36.6 ;
     RECT  52.585 6.384 52.877 8.952 ;
     RECT  51.304 37.584 52.949 40.968 ;
     RECT  51.304 17.664 52.981 21.48 ;
     RECT  52.297 22.752 52.981 27.864 ;
     RECT  52.877 6.528 52.985 8.952 ;
     RECT  52.837 30.72 52.985 36.6 ;
     RECT  52.988 5.376 53.075 5.4 ;
     RECT  51.941 15.984 53.089 16.488 ;
     RECT  52.697 29.328 53.129 29.64 ;
     RECT  52.985 36.576 53.377 36.6 ;
     RECT  52.949 37.584 53.377 40.92 ;
     RECT  52.813 10.368 53.441 12.36 ;
     RECT  52.981 17.664 53.521 27.864 ;
     RECT  53.441 10.224 53.525 12.36 ;
     RECT  53.377 36.576 53.525 40.92 ;
     RECT  53.129 29.616 53.557 29.64 ;
     RECT  52.985 30.72 53.557 35.448 ;
     RECT  52.661 2.88 53.629 2.904 ;
     RECT  53.161 4.032 53.629 4.056 ;
     RECT  52.553 43.152 53.633 43.176 ;
     RECT  53.557 29.616 53.669 35.448 ;
     RECT  52.985 7.632 53.777 8.952 ;
     RECT  53.629 2.88 53.809 4.056 ;
     RECT  53.809 2.88 53.845 5.112 ;
     RECT  53.521 17.664 53.849 27.96 ;
     RECT  53.525 36.576 53.849 38.712 ;
     RECT  53.669 30.576 53.993 35.448 ;
     RECT  53.849 17.664 54.025 27.48 ;
     RECT  52.985 6.528 54.133 6.552 ;
     RECT  53.089 15.408 54.241 16.488 ;
     RECT  54.025 17.616 54.241 27.48 ;
     RECT  53.845 2.304 54.245 5.112 ;
     RECT  54.241 15.408 54.281 27.48 ;
     RECT  53.809 14.256 54.313 14.28 ;
     RECT  53.993 32.544 54.317 35.448 ;
     RECT  54.133 6.24 54.349 6.552 ;
     RECT  53.777 7.632 54.349 8.568 ;
     RECT  54.317 32.544 54.353 32.856 ;
     RECT  54.313 14.256 54.457 14.376 ;
     RECT  54.281 15.408 54.457 17.64 ;
     RECT  53.849 37.152 54.493 38.712 ;
     RECT  53.525 40.08 54.493 40.92 ;
     RECT  54.317 33.84 54.533 35.448 ;
     RECT  53.525 11.04 54.565 12.36 ;
     RECT  53.993 30.576 54.605 31.56 ;
     RECT  54.349 6.24 54.673 8.568 ;
     RECT  54.533 34.512 54.709 35.448 ;
     RECT  54.565 11.04 54.713 12.552 ;
     RECT  54.281 19.056 54.749 27.48 ;
     RECT  54.605 30.768 54.785 31.56 ;
     RECT  54.673 6.192 54.821 8.568 ;
     RECT  54.245 4.944 54.853 5.112 ;
     RECT  54.821 6.192 54.853 6.264 ;
     RECT  54.749 26.496 54.857 27.48 ;
     RECT  54.493 37.152 55.177 40.92 ;
     RECT  54.709 28.704 55.213 28.728 ;
     RECT  54.353 32.544 55.283 32.568 ;
     RECT  55.213 28.704 55.285 29.208 ;
     RECT  55.285 28.464 55.331 29.208 ;
     RECT  54.713 11.952 55.361 12.552 ;
     RECT  54.857 26.64 55.393 27.48 ;
     RECT  55.331 28.464 55.393 28.728 ;
     RECT  54.821 7.632 55.501 8.568 ;
     RECT  54.853 9.696 55.501 9.72 ;
     RECT  54.457 14.256 55.537 17.64 ;
     RECT  54.785 30.864 55.609 31.56 ;
     RECT  54.709 34.512 55.645 35.832 ;
     RECT  55.177 36.864 55.645 40.92 ;
     RECT  54.853 4.944 55.669 6.264 ;
     RECT  55.645 34.512 55.765 40.92 ;
     RECT  55.537 14.208 55.789 17.64 ;
     RECT  55.609 30.864 55.825 32.328 ;
     RECT  55.669 4.512 55.861 6.264 ;
     RECT  55.501 7.632 55.861 9.72 ;
     RECT  54.749 19.056 55.957 25.224 ;
     RECT  55.789 14.208 56.005 17.736 ;
     RECT  55.957 18.768 56.005 25.224 ;
     RECT  55.825 30.72 56.257 32.328 ;
     RECT  54.245 2.304 56.293 3.432 ;
     RECT  55.861 4.512 56.293 9.72 ;
     RECT  56.293 2.304 56.408 9.72 ;
     RECT  56.149 10.992 56.408 11.016 ;
     RECT  55.361 12.336 56.408 12.552 ;
     RECT  56.005 14.208 56.408 25.224 ;
     RECT  55.393 26.64 56.408 28.728 ;
     RECT  56.257 30.72 56.408 32.856 ;
     RECT  55.765 33.84 56.408 40.92 ;
     RECT  56.408 2.148 56.512 41.052 ;
     RECT  56.512 2.418 56.704 40.824 ;
     RECT  56.704 7.968 56.819 9 ;
     RECT  56.704 30.192 56.819 40.824 ;
     RECT  56.819 34.56 56.908 40.824 ;
     RECT  56.908 34.656 56.909 40.824 ;
     RECT  56.704 5.856 57.125 6.888 ;
     RECT  57.125 5.856 57.233 6.792 ;
     RECT  56.819 7.968 57.233 8.376 ;
     RECT  57.233 6.144 57.269 6.792 ;
     RECT  56.819 30.192 57.299 33.576 ;
     RECT  56.704 2.496 57.377 2.52 ;
     RECT  57.269 6.144 57.413 6.312 ;
     RECT  57.299 32.208 57.413 33.576 ;
     RECT  57.413 6.24 57.521 6.312 ;
     RECT  56.704 17.472 57.58 22.056 ;
     RECT  56.909 34.752 57.593 40.824 ;
     RECT  56.704 23.04 57.629 24.456 ;
     RECT  57.629 23.136 57.685 24.456 ;
     RECT  56.704 25.536 57.685 26.808 ;
     RECT  56.704 27.888 57.779 29.112 ;
     RECT  57.685 23.136 57.829 26.808 ;
     RECT  57.779 27.888 57.829 27.912 ;
     RECT  57.829 23.136 58.025 27.912 ;
     RECT  56.704 4.416 58.097 4.536 ;
     RECT  57.233 8.016 58.117 8.376 ;
     RECT  58.117 8.016 58.163 9 ;
     RECT  57.413 32.208 58.169 33.096 ;
     RECT  56.704 14.208 58.205 16.008 ;
     RECT  57.58 18.192 58.241 22.056 ;
     RECT  57.593 37.584 58.241 40.824 ;
     RECT  58.163 8.976 58.261 9 ;
     RECT  56.704 10.272 58.261 11.016 ;
     RECT  56.704 12.528 58.313 12.888 ;
     RECT  58.241 19.056 58.313 22.056 ;
     RECT  58.261 8.976 58.348 11.016 ;
     RECT  58.241 37.872 58.349 40.824 ;
     RECT  57.779 28.896 58.381 29.112 ;
     RECT  57.299 30.192 58.381 31.128 ;
     RECT  57.593 34.752 58.421 36.6 ;
     RECT  58.348 8.976 58.493 9.096 ;
     RECT  58.421 35.328 58.529 36.6 ;
     RECT  58.205 14.928 58.601 15.864 ;
     RECT  58.349 37.872 58.637 39.336 ;
     RECT  58.097 4.416 58.693 4.44 ;
     RECT  58.381 28.896 58.693 31.128 ;
     RECT  58.169 32.208 58.693 32.76 ;
     RECT  58.693 3.936 58.739 4.44 ;
     RECT  57.521 6.24 58.781 6.264 ;
     RECT  58.025 23.136 58.883 27.72 ;
     RECT  58.883 23.136 59.027 23.88 ;
     RECT  59.027 23.136 59.029 23.352 ;
     RECT  58.693 28.896 59.069 32.76 ;
     RECT  59.036 34.176 59.123 34.2 ;
     RECT  58.348 10.176 59.141 11.016 ;
     RECT  59.069 28.896 59.213 32.52 ;
     RECT  59.213 28.896 59.221 32.328 ;
     RECT  58.637 37.872 59.221 38.136 ;
     RECT  59.221 28.8 59.293 32.328 ;
     RECT  58.349 40.8 59.321 40.824 ;
     RECT  58.597 7.392 59.357 7.416 ;
     RECT  59.293 30.288 59.357 32.328 ;
     RECT  58.601 14.928 59.389 15.384 ;
     RECT  58.313 19.056 59.425 21.624 ;
     RECT  59.029 22.752 59.425 23.352 ;
     RECT  58.637 39.312 59.429 39.336 ;
     RECT  59.357 30.336 59.465 32.328 ;
     RECT  58.529 35.328 59.465 35.928 ;
     RECT  59.293 28.8 59.501 28.824 ;
     RECT  58.493 9.072 59.609 9.096 ;
     RECT  59.425 19.056 59.681 23.352 ;
     RECT  59.389 14.64 59.701 15.384 ;
     RECT  59.221 37.056 59.717 38.136 ;
     RECT  59.701 14.64 59.749 16.008 ;
     RECT  59.749 14.64 59.788 16.584 ;
     RECT  59.681 19.296 59.789 23.352 ;
     RECT  58.165 2.832 59.897 2.856 ;
     RECT  59.465 30.336 59.897 32.232 ;
     RECT  59.788 14.64 59.933 15.384 ;
     RECT  58.883 24.912 59.933 27.72 ;
     RECT  59.897 30.336 59.933 31.8 ;
     RECT  58.739 3.936 60.005 3.96 ;
     RECT  59.933 24.912 60.005 27.672 ;
     RECT  59.717 37.056 60.077 37.608 ;
     RECT  59.141 10.176 60.173 10.728 ;
     RECT  60.173 10.176 60.227 11.448 ;
     RECT  60.227 11.424 60.257 11.448 ;
     RECT  59.789 20.496 60.329 22.488 ;
     RECT  60.005 24.912 60.365 25.896 ;
     RECT  60.329 21.6 60.509 22.488 ;
     RECT  59.933 30.336 60.515 30.888 ;
     RECT  59.821 39.216 60.685 39.24 ;
     RECT  58.313 12.528 60.757 12.552 ;
     RECT  60.365 25.872 60.803 25.896 ;
     RECT  60.005 27.648 60.803 27.672 ;
     RECT  60.757 12.288 60.829 12.552 ;
     RECT  60.829 12.288 60.937 13.416 ;
     RECT  59.933 14.64 60.937 14.664 ;
     RECT  59.789 19.296 61.081 19.32 ;
     RECT  61.325 2.256 61.333 2.28 ;
     RECT  60.901 4.128 61.333 4.152 ;
     RECT  61.261 10.32 61.333 10.344 ;
     RECT  60.329 20.496 61.333 20.52 ;
     RECT  60.509 21.6 61.333 22.248 ;
     RECT  59.465 35.328 61.333 35.88 ;
     RECT  60.433 8.4 61.441 8.52 ;
     RECT  60.937 12.288 61.513 14.664 ;
     RECT  61.081 18.816 61.532 19.32 ;
     RECT  61.532 18.048 61.549 19.32 ;
     RECT  60.077 37.584 61.549 37.608 ;
     RECT  60.721 5.712 61.585 5.736 ;
     RECT  61.441 8.4 61.585 8.856 ;
     RECT  61.333 10.32 61.585 11.208 ;
     RECT  61.549 17.952 61.585 19.32 ;
     RECT  61.333 20.496 61.585 22.248 ;
     RECT  60.937 32.448 61.585 32.472 ;
     RECT  60.181 23.856 61.669 23.88 ;
     RECT  61.585 5.232 61.693 5.736 ;
     RECT  61.513 12.288 61.693 15.48 ;
     RECT  61.189 33.648 61.765 33.672 ;
     RECT  61.333 34.752 61.765 35.88 ;
     RECT  61.333 2.256 61.808 4.152 ;
     RECT  61.693 5.232 61.808 6.264 ;
     RECT  60.829 7.392 61.808 7.416 ;
     RECT  61.585 8.4 61.808 11.208 ;
     RECT  61.693 12.288 61.808 15.528 ;
     RECT  59.788 16.56 61.808 16.584 ;
     RECT  61.585 17.952 61.808 22.248 ;
     RECT  61.669 23.856 61.808 24.504 ;
     RECT  61.549 25.536 61.808 25.56 ;
     RECT  61.549 27.36 61.808 27.384 ;
     RECT  61.004 29.952 61.808 29.976 ;
     RECT  60.937 31.008 61.808 31.032 ;
     RECT  61.585 32.304 61.808 32.472 ;
     RECT  61.765 33.648 61.808 35.88 ;
     RECT  61.549 37.584 61.808 38.184 ;
     RECT  60.685 39.216 61.808 40.008 ;
     RECT  61.808 2.148 61.912 41.052 ;
     RECT  61.912 2.418 62.104 40.782 ;
     RECT  62.104 12.288 62.165 13.704 ;
     RECT  62.104 30.288 62.165 36.552 ;
     RECT  62.104 4.752 62.243 5.832 ;
     RECT  62.104 23.856 62.489 26.232 ;
     RECT  62.104 21.408 62.525 22.248 ;
     RECT  62.165 35.472 62.561 36.552 ;
     RECT  62.489 23.856 62.633 25.176 ;
     RECT  62.104 2.64 62.668 3.432 ;
     RECT  62.104 17.952 62.705 18.216 ;
     RECT  62.165 30.288 62.741 34.104 ;
     RECT  62.741 33.552 62.957 34.104 ;
     RECT  62.165 12.288 63.029 13.32 ;
     RECT  62.104 27.36 63.029 29.208 ;
     RECT  62.104 11.184 63.209 11.208 ;
     RECT  62.243 4.752 63.241 5.736 ;
     RECT  62.561 35.472 63.241 35.688 ;
     RECT  62.104 37.824 63.241 38.376 ;
     RECT  62.104 39.504 63.241 39.912 ;
     RECT  63.029 12.288 63.277 13.128 ;
     RECT  63.241 14.112 63.385 14.28 ;
     RECT  62.104 15.312 63.385 16.296 ;
     RECT  63.241 4.752 63.421 6.408 ;
     RECT  62.525 21.408 63.425 21.672 ;
     RECT  63.241 37.824 63.5 39.912 ;
     RECT  62.489 26.208 63.569 26.232 ;
     RECT  63.5 37.008 63.587 39.912 ;
     RECT  62.633 24.48 63.596 25.176 ;
     RECT  62.104 19.296 63.601 19.32 ;
     RECT  62.705 17.952 63.637 18.072 ;
     RECT  63.029 27.36 63.637 27.864 ;
     RECT  63.421 4.464 63.641 6.408 ;
     RECT  63.641 6 63.713 6.408 ;
     RECT  62.668 3.408 63.74 3.432 ;
     RECT  63.637 17.664 63.74 18.072 ;
     RECT  63.74 17.616 63.753 18.072 ;
     RECT  63.601 19.248 63.753 19.32 ;
     RECT  63.641 4.464 63.827 4.872 ;
     RECT  62.104 7.392 63.827 9.72 ;
     RECT  63.753 17.616 63.827 19.32 ;
     RECT  63.596 23.808 63.836 25.176 ;
     RECT  63.827 18.672 63.853 19.32 ;
     RECT  62.104 20.352 63.853 20.376 ;
     RECT  62.741 30.288 63.853 32.328 ;
     RECT  62.957 33.552 63.853 33.576 ;
     RECT  63.241 34.752 63.884 35.688 ;
     RECT  63.277 11.808 63.893 13.128 ;
     RECT  63.853 18.672 63.893 20.376 ;
     RECT  63.853 30.288 63.893 33.576 ;
     RECT  63.836 23.328 63.923 25.176 ;
     RECT  63.385 14.112 63.965 16.296 ;
     RECT  63.884 34.752 63.971 35.928 ;
     RECT  63.587 39.216 64.001 39.912 ;
     RECT  63.893 31.776 64.105 33.576 ;
     RECT  63.971 34.752 64.105 35.496 ;
     RECT  63.923 23.904 64.141 25.176 ;
     RECT  63.425 21.504 64.213 21.672 ;
     RECT  64.141 23.904 64.217 25.32 ;
     RECT  63.893 11.808 64.253 12.36 ;
     RECT  64.213 21.504 64.285 21.768 ;
     RECT  63.637 26.784 64.367 27.864 ;
     RECT  63.029 29.088 64.367 29.112 ;
     RECT  63.74 3.12 64.393 3.432 ;
     RECT  64.367 26.784 64.451 29.112 ;
     RECT  64.393 2.256 64.465 3.432 ;
     RECT  63.827 4.464 64.465 4.488 ;
     RECT  64.465 2.256 64.477 4.488 ;
     RECT  64.105 31.776 64.541 35.496 ;
     RECT  64.001 39.216 64.541 39.336 ;
     RECT  63.893 30.288 64.681 30.312 ;
     RECT  63.827 17.664 64.789 17.688 ;
     RECT  64.477 2.592 64.825 4.488 ;
     RECT  63.713 6 64.825 6.024 ;
     RECT  64.285 21.504 64.825 21.816 ;
     RECT  63.965 14.112 64.837 15.48 ;
     RECT  63.893 18.672 64.865 20.088 ;
     RECT  64.837 13.632 64.883 15.48 ;
     RECT  64.883 14.736 64.909 15.48 ;
     RECT  63.587 37.536 64.933 37.56 ;
     RECT  64.865 18.672 64.937 19.944 ;
     RECT  64.825 2.592 64.969 6.024 ;
     RECT  63.827 7.392 64.979 9.144 ;
     RECT  64.937 19.296 65.009 19.944 ;
     RECT  64.969 2.592 65.027 6.168 ;
     RECT  65.027 6 65.041 6.168 ;
     RECT  64.217 25.296 65.041 25.32 ;
     RECT  64.451 26.784 65.041 28.536 ;
     RECT  64.681 30.192 65.113 30.312 ;
     RECT  64.541 31.776 65.113 32.616 ;
     RECT  64.789 16.896 65.149 17.688 ;
     RECT  64.253 11.904 65.225 12.36 ;
     RECT  64.217 23.904 65.225 23.928 ;
     RECT  65.113 30.192 65.405 32.616 ;
     RECT  63.565 10.8 65.509 10.824 ;
     RECT  65.509 10.8 65.545 10.92 ;
     RECT  65.027 2.592 65.549 4.584 ;
     RECT  65.405 31.92 65.557 32.616 ;
     RECT  64.541 33.696 65.557 35.496 ;
     RECT  65.557 31.92 65.644 35.496 ;
     RECT  65.405 30.192 65.657 30.312 ;
     RECT  64.825 21.504 65.689 22.2 ;
     RECT  64.177 40.704 65.689 40.728 ;
     RECT  65.549 2.592 65.693 2.856 ;
     RECT  65.041 25.296 65.729 28.536 ;
     RECT  65.689 21.504 65.797 22.776 ;
     RECT  65.041 6 65.801 6.84 ;
     RECT  64.933 37.536 65.833 37.656 ;
     RECT  65.833 37.008 65.905 37.656 ;
     RECT  65.149 16.08 65.945 17.688 ;
     RECT  65.905 37.008 65.945 38.232 ;
     RECT  65.009 19.296 66.013 19.32 ;
     RECT  65.797 21.504 66.013 22.872 ;
     RECT  65.644 34.08 66.037 35.496 ;
     RECT  65.689 39.888 66.037 40.728 ;
     RECT  64.979 8.208 66.085 9.144 ;
     RECT  65.545 10.464 66.085 10.92 ;
     RECT  66.013 18.576 66.085 19.32 ;
     RECT  66.037 39.84 66.117 40.728 ;
     RECT  66.117 39.84 66.121 40.392 ;
     RECT  66.037 34.08 66.133 35.736 ;
     RECT  65.945 37.008 66.133 37.128 ;
     RECT  66.085 8.208 66.153 9.288 ;
     RECT  65.801 6.144 66.161 6.84 ;
     RECT  66.133 34.08 66.161 37.128 ;
     RECT  64.909 14.736 66.265 14.808 ;
     RECT  65.945 16.08 66.265 17.112 ;
     RECT  65.729 25.296 66.265 28.152 ;
     RECT  64.883 13.632 66.337 13.656 ;
     RECT  66.265 14.736 66.337 17.112 ;
     RECT  65.945 38.208 66.337 38.232 ;
     RECT  66.121 39.504 66.337 40.392 ;
     RECT  66.085 10.368 66.445 10.92 ;
     RECT  65.225 11.952 66.445 12.36 ;
     RECT  66.337 13.632 66.445 17.112 ;
     RECT  66.085 18.576 66.517 19.944 ;
     RECT  65.549 3.84 66.553 4.584 ;
     RECT  65.644 31.92 66.841 33.096 ;
     RECT  66.161 34.08 66.841 34.104 ;
     RECT  66.153 8.4 66.908 9.288 ;
     RECT  66.445 10.368 66.908 17.112 ;
     RECT  66.517 18.576 66.985 20.376 ;
     RECT  66.841 24.096 67.057 24.12 ;
     RECT  67.057 24.096 67.065 24.216 ;
     RECT  66.265 25.2 67.065 28.152 ;
     RECT  66.553 3.408 67.165 4.584 ;
     RECT  67.165 2.832 67.208 4.584 ;
     RECT  66.908 8.4 67.208 17.112 ;
     RECT  66.985 18.432 67.208 20.376 ;
     RECT  66.013 21.504 67.208 23.064 ;
     RECT  67.065 24.096 67.208 28.152 ;
     RECT  65.905 29.76 67.208 29.784 ;
     RECT  66.841 31.92 67.208 34.104 ;
     RECT  66.161 35.328 67.208 37.128 ;
     RECT  66.337 38.208 67.208 40.392 ;
     RECT  67.208 2.148 67.312 41.052 ;
     RECT  67.312 2.256 67.504 40.782 ;
     RECT  67.504 3.84 67.619 6.552 ;
     RECT  67.504 35.232 67.619 37.608 ;
     RECT  67.504 2.256 67.645 2.808 ;
     RECT  67.504 33.6 67.673 33.672 ;
     RECT  67.504 38.688 67.709 40.728 ;
     RECT  67.504 24.192 67.745 30.072 ;
     RECT  67.504 21.6 67.781 23.16 ;
     RECT  67.504 10.272 67.817 12.36 ;
     RECT  67.745 24.672 67.955 30.072 ;
     RECT  67.955 24.672 67.997 27.864 ;
     RECT  67.709 38.688 68.003 39.528 ;
     RECT  67.619 35.376 68.177 37.32 ;
     RECT  67.504 13.68 68.213 17.112 ;
     RECT  68.003 38.784 68.285 39.528 ;
     RECT  67.504 31.728 68.321 32.472 ;
     RECT  67.504 18.432 68.357 20.568 ;
     RECT  68.213 15.84 68.387 17.112 ;
     RECT  68.357 18.432 68.387 19.128 ;
     RECT  67.619 4.512 68.605 6.552 ;
     RECT  67.504 7.968 68.605 9.144 ;
     RECT  67.817 11.376 68.605 12.36 ;
     RECT  68.213 13.68 68.605 14.76 ;
     RECT  68.605 4.512 68.645 9.144 ;
     RECT  67.709 40.704 68.749 40.728 ;
     RECT  67.955 28.848 68.857 30.072 ;
     RECT  68.645 4.512 68.86 7.032 ;
     RECT  68.86 4.512 68.861 6.792 ;
     RECT  67.997 25.68 68.861 27.864 ;
     RECT  67.645 2.784 68.965 2.808 ;
     RECT  68.605 11.376 69.005 14.76 ;
     RECT  68.861 25.68 69.005 27.432 ;
     RECT  68.965 2.784 69.033 3.432 ;
     RECT  67.817 10.272 69.077 10.296 ;
     RECT  69.005 11.376 69.077 11.784 ;
     RECT  67.673 33.6 69.109 33.624 ;
     RECT  68.177 35.376 69.109 37.176 ;
     RECT  68.861 4.512 69.185 5.352 ;
     RECT  68.857 28.848 69.217 31.032 ;
     RECT  68.285 39.072 69.217 39.528 ;
     RECT  68.749 40.704 69.217 41.064 ;
     RECT  68.387 19.104 69.221 19.128 ;
     RECT  68.321 32.448 69.257 32.472 ;
     RECT  68.357 20.448 69.361 20.568 ;
     RECT  69.217 28.656 69.397 31.032 ;
     RECT  69.109 33.6 69.401 37.176 ;
     RECT  68.387 15.84 69.433 15.864 ;
     RECT  68.387 16.896 69.433 17.112 ;
     RECT  69.217 39.072 69.541 41.064 ;
     RECT  69.185 4.512 69.545 4.92 ;
     RECT  69.401 34.896 69.581 37.176 ;
     RECT  69.005 12.768 69.649 14.76 ;
     RECT  69.433 15.84 69.649 17.112 ;
     RECT  69.649 43.008 69.721 43.032 ;
     RECT  69.397 28.656 69.833 31.992 ;
     RECT  69.005 26.256 69.869 27.432 ;
     RECT  68.861 6.528 69.875 6.792 ;
     RECT  69.875 6.528 69.901 6.552 ;
     RECT  69.649 12.768 69.905 17.208 ;
     RECT  69.905 12.768 69.941 17.112 ;
     RECT  69.541 39.072 69.971 41.592 ;
     RECT  69.901 6.144 70.013 6.552 ;
     RECT  69.971 39.072 70.021 41.064 ;
     RECT  69.869 27.024 70.045 27.432 ;
     RECT  69.833 28.656 70.045 29.592 ;
     RECT  70.021 40.272 70.067 41.064 ;
     RECT  69.721 43.008 70.117 43.08 ;
     RECT  67.781 21.6 70.153 22.776 ;
     RECT  70.117 42.144 70.163 43.08 ;
     RECT  68.713 0.528 70.225 0.552 ;
     RECT  69.033 3.408 70.261 3.432 ;
     RECT  70.009 38.016 70.261 38.04 ;
     RECT  70.021 39.072 70.261 39.288 ;
     RECT  69.833 30.768 70.265 31.992 ;
     RECT  69.433 18.72 70.405 18.744 ;
     RECT  69.361 19.968 70.405 20.568 ;
     RECT  70.265 31.968 70.409 31.992 ;
     RECT  70.067 40.32 70.451 41.064 ;
     RECT  70.225 0.48 70.513 0.552 ;
     RECT  69.077 11.376 70.513 11.4 ;
     RECT  70.163 42.144 70.547 42.312 ;
     RECT  68.645 8.496 70.549 9.144 ;
     RECT  70.549 8.496 70.553 9.96 ;
     RECT  70.513 0.48 70.585 1.128 ;
     RECT  70.513 11.328 70.585 11.4 ;
     RECT  70.405 18.72 70.585 20.568 ;
     RECT  70.153 21.6 70.585 23.064 ;
     RECT  69.401 33.6 70.621 33.624 ;
     RECT  70.585 18.72 70.657 23.064 ;
     RECT  70.585 0.48 70.693 1.752 ;
     RECT  70.621 33.552 70.693 33.624 ;
     RECT  69.581 34.896 70.693 37.032 ;
     RECT  70.553 9.12 70.732 9.96 ;
     RECT  70.547 42.144 70.739 42.264 ;
     RECT  67.997 24.672 70.765 24.696 ;
     RECT  70.693 32.112 70.844 37.032 ;
     RECT  70.261 38.016 70.844 39.288 ;
     RECT  70.585 10.944 70.877 11.4 ;
     RECT  70.844 32.112 70.931 39.288 ;
     RECT  70.877 11.232 70.945 11.4 ;
     RECT  70.045 27.024 70.949 29.592 ;
     RECT  69.941 12.768 70.973 14.376 ;
     RECT  69.941 15.552 70.973 17.112 ;
     RECT  69.545 4.896 70.981 4.92 ;
     RECT  70.013 6.528 70.981 6.552 ;
     RECT  70.973 12.768 70.985 17.112 ;
     RECT  70.945 11.232 71.017 11.784 ;
     RECT  70.985 12.768 71.017 13.176 ;
     RECT  70.985 14.352 71.053 17.112 ;
     RECT  70.981 4.896 71.125 6.552 ;
     RECT  70.949 28.656 71.197 29.592 ;
     RECT  70.265 30.768 71.197 30.792 ;
     RECT  70.949 27.024 71.233 27.24 ;
     RECT  70.739 42.144 71.237 42.168 ;
     RECT  71.233 26.784 71.269 27.24 ;
     RECT  70.931 38.016 71.269 39.288 ;
     RECT  70.451 40.32 71.269 41.016 ;
     RECT  70.931 32.112 71.345 36.936 ;
     RECT  70.657 18.72 71.413 23.352 ;
     RECT  70.765 24.48 71.413 24.696 ;
     RECT  71.197 28.656 71.413 30.792 ;
     RECT  71.345 32.112 71.413 33.672 ;
     RECT  71.269 38.016 71.453 41.016 ;
     RECT  71.125 4.56 71.521 6.552 ;
     RECT  71.453 38.112 71.555 41.016 ;
     RECT  70.261 3.024 71.557 3.432 ;
     RECT  71.521 4.56 71.557 6.84 ;
     RECT  71.053 14.352 71.629 17.736 ;
     RECT  71.413 18.72 71.629 24.696 ;
     RECT  71.629 14.352 71.633 24.696 ;
     RECT  70.693 0.432 71.641 1.752 ;
     RECT  71.557 3.024 71.665 6.84 ;
     RECT  71.665 3.024 71.737 7.656 ;
     RECT  70.732 9.12 71.737 9.528 ;
     RECT  71.737 9.12 71.797 9.624 ;
     RECT  71.737 3.024 71.893 7.752 ;
     RECT  71.893 2.832 71.917 7.752 ;
     RECT  71.797 8.832 71.917 9.624 ;
     RECT  71.845 42.192 71.941 42.216 ;
     RECT  71.269 25.872 71.989 27.24 ;
     RECT  71.641 0.432 72.133 0.504 ;
     RECT  71.917 2.832 72.241 9.624 ;
     RECT  71.017 11.232 72.277 13.176 ;
     RECT  71.941 42.192 72.313 42.264 ;
     RECT  72.277 10.896 72.349 13.176 ;
     RECT  71.633 14.352 72.349 18.84 ;
     RECT  71.989 25.872 72.349 27.624 ;
     RECT  72.133 0.336 72.373 0.504 ;
     RECT  71.345 34.896 72.428 36.936 ;
     RECT  71.633 19.824 72.469 24.696 ;
     RECT  72.349 25.872 72.469 27.672 ;
     RECT  71.555 39.264 72.565 41.016 ;
     RECT  72.313 42.192 72.565 43.08 ;
     RECT  72.241 2.832 72.601 9.912 ;
     RECT  71.641 1.728 72.608 1.752 ;
     RECT  72.601 2.784 72.608 9.912 ;
     RECT  72.349 10.896 72.608 18.84 ;
     RECT  72.469 19.824 72.608 27.672 ;
     RECT  71.413 28.656 72.608 33.672 ;
     RECT  72.428 34.896 72.608 37.032 ;
     RECT  71.555 38.112 72.608 38.136 ;
     RECT  72.565 39.264 72.608 43.08 ;
     RECT  72.373 0.144 72.613 0.504 ;
     RECT  72.613 0.144 72.805 0.552 ;
     RECT  72.608 1.728 72.904 43.08 ;
     RECT  72.904 20.16 72.965 27.672 ;
     RECT  72.965 20.976 73.037 27.624 ;
     RECT  72.904 39.12 73.037 43.08 ;
     RECT  72.904 5.472 73.073 9.912 ;
     RECT  72.805 0.096 73.105 0.552 ;
     RECT  72.904 1.728 73.139 3.144 ;
     RECT  72.904 29.04 73.181 35.928 ;
     RECT  73.073 5.568 73.217 9.912 ;
     RECT  73.139 2.016 73.289 3.144 ;
     RECT  72.904 36.912 73.331 37.992 ;
     RECT  73.331 37.056 73.369 37.992 ;
     RECT  72.904 17.712 73.397 18.888 ;
     RECT  73.181 29.04 73.397 31.224 ;
     RECT  73.037 20.976 73.433 25.272 ;
     RECT  72.904 10.896 73.505 16.536 ;
     RECT  73.369 37.296 73.505 37.992 ;
     RECT  73.505 10.896 73.577 13.176 ;
     RECT  73.577 11.136 73.613 13.176 ;
     RECT  73.289 2.016 73.649 2.856 ;
     RECT  73.181 33.84 73.649 35.928 ;
     RECT  73.181 32.304 73.721 32.328 ;
     RECT  73.105 0.096 73.789 0.648 ;
     RECT  73.037 42.144 73.789 43.08 ;
     RECT  73.613 11.136 73.937 11.976 ;
     RECT  73.613 13.104 73.937 13.176 ;
     RECT  73.397 29.04 73.937 30.456 ;
     RECT  73.433 21.12 73.973 25.272 ;
     RECT  73.037 26.88 74.005 27.624 ;
     RECT  73.217 6.288 74.045 9.912 ;
     RECT  74.005 26.88 74.053 27.864 ;
     RECT  74.053 26.544 74.113 27.864 ;
     RECT  73.937 29.04 74.113 29.784 ;
     RECT  74.113 26.544 74.117 29.784 ;
     RECT  73.649 34.08 74.153 35.928 ;
     RECT  73.037 39.12 74.153 41.064 ;
     RECT  73.505 14.352 74.197 16.536 ;
     RECT  73.397 17.712 74.197 17.736 ;
     RECT  74.197 14.352 74.284 17.736 ;
     RECT  72.904 4.128 74.441 4.152 ;
     RECT  73.505 37.296 74.477 37.944 ;
     RECT  73.789 0.096 74.483 0.696 ;
     RECT  74.153 39.216 74.483 41.064 ;
     RECT  73.973 21.408 74.545 25.272 ;
     RECT  74.257 10.128 74.585 10.152 ;
     RECT  73.937 11.136 74.621 11.256 ;
     RECT  74.117 26.544 74.627 29.064 ;
     RECT  74.153 34.08 74.629 34.824 ;
     RECT  73.937 13.104 74.653 13.128 ;
     RECT  74.284 17.712 74.653 17.736 ;
     RECT  73.397 18.864 74.653 18.888 ;
     RECT  74.627 28.8 74.657 29.064 ;
     RECT  74.483 0.096 74.675 0.6 ;
     RECT  74.477 37.296 74.761 37.32 ;
     RECT  74.483 39.216 74.771 41.016 ;
     RECT  74.621 11.136 74.797 11.16 ;
     RECT  74.284 14.352 74.801 16.536 ;
     RECT  74.045 6.288 74.833 9 ;
     RECT  74.653 17.712 74.837 18.888 ;
     RECT  73.789 42.144 74.837 43.176 ;
     RECT  74.837 17.712 74.873 17.976 ;
     RECT  74.153 35.904 74.909 35.928 ;
     RECT  74.545 21.408 75.013 25.464 ;
     RECT  74.627 26.544 75.017 27.384 ;
     RECT  74.653 13.056 75.085 13.128 ;
     RECT  74.833 6.24 75.161 9 ;
     RECT  74.629 33.36 75.161 34.824 ;
     RECT  75.013 21.12 75.265 25.464 ;
     RECT  75.085 29.664 75.265 29.688 ;
     RECT  75.161 33.456 75.265 34.824 ;
     RECT  74.801 15.408 75.301 16.536 ;
     RECT  74.873 17.712 75.301 17.736 ;
     RECT  73.649 2.016 75.337 2.28 ;
     RECT  75.265 20.88 75.337 25.464 ;
     RECT  75.337 20.688 75.373 25.464 ;
     RECT  75.161 7.632 75.409 9 ;
     RECT  75.373 20.688 75.452 25.608 ;
     RECT  75.085 12.768 75.548 13.128 ;
     RECT  74.801 14.352 75.548 14.376 ;
     RECT  75.452 20.544 75.629 25.608 ;
     RECT  75.548 12.768 75.635 14.376 ;
     RECT  75.157 31.536 75.661 31.56 ;
     RECT  74.833 4.8 75.697 4.92 ;
     RECT  74.761 37.056 75.697 37.32 ;
     RECT  75.481 38.496 75.697 38.52 ;
     RECT  74.771 39.552 75.701 41.016 ;
     RECT  75.337 2.016 75.733 2.376 ;
     RECT  75.161 6.24 75.733 6.648 ;
     RECT  75.409 7.632 75.769 9.672 ;
     RECT  74.797 10.704 75.769 11.16 ;
     RECT  75.629 20.544 75.827 22.44 ;
     RECT  75.265 29.664 75.845 30.216 ;
     RECT  75.661 31.536 75.877 31.944 ;
     RECT  75.697 37.056 75.877 38.52 ;
     RECT  75.701 39.552 75.877 40.968 ;
     RECT  75.877 31.536 75.949 32.04 ;
     RECT  75.877 37.056 75.971 40.968 ;
     RECT  75.049 19.296 75.98 19.368 ;
     RECT  75.949 31.536 75.989 32.424 ;
     RECT  75.925 28.656 76.012 29.64 ;
     RECT  75.769 7.632 76.019 11.16 ;
     RECT  75.697 4.176 76.021 4.92 ;
     RECT  75.733 5.904 76.021 6.648 ;
     RECT  75.301 15.408 76.057 17.736 ;
     RECT  75.98 18.912 76.057 19.368 ;
     RECT  75.629 23.52 76.057 25.608 ;
     RECT  75.017 26.784 76.057 27.384 ;
     RECT  75.635 12.768 76.061 12.84 ;
     RECT  76.057 23.52 76.061 27.384 ;
     RECT  75.971 37.056 76.061 37.416 ;
     RECT  76.021 4.176 76.097 6.648 ;
     RECT  75.971 38.496 76.097 40.968 ;
     RECT  76.019 10.128 76.133 11.16 ;
     RECT  76.057 15.408 76.133 19.368 ;
     RECT  76.133 10.176 76.165 11.16 ;
     RECT  74.675 0.096 76.229 0.552 ;
     RECT  75.635 14.352 76.237 14.376 ;
     RECT  76.133 15.408 76.237 17.16 ;
     RECT  75.989 31.92 76.237 32.424 ;
     RECT  75.265 33.456 76.237 35.88 ;
     RECT  75.733 2.016 76.309 2.856 ;
     RECT  76.097 4.176 76.309 4.2 ;
     RECT  76.061 37.056 76.385 37.224 ;
     RECT  76.309 2.016 76.493 4.2 ;
     RECT  75.827 20.688 76.493 22.44 ;
     RECT  76.061 23.52 76.529 27.336 ;
     RECT  76.165 10.176 76.565 11.4 ;
     RECT  76.237 31.92 76.565 35.88 ;
     RECT  76.565 31.92 76.601 35.736 ;
     RECT  76.097 5.712 76.637 6.648 ;
     RECT  76.601 32.016 76.637 35.736 ;
     RECT  76.019 7.632 76.669 8.808 ;
     RECT  76.565 10.896 76.709 11.4 ;
     RECT  76.012 28.992 76.781 29.64 ;
     RECT  76.061 12.768 76.853 12.792 ;
     RECT  76.529 23.856 76.853 27.336 ;
     RECT  76.669 6.768 76.961 8.808 ;
     RECT  74.837 43.056 76.997 43.176 ;
     RECT  76.229 0.096 77.033 0.6 ;
     RECT  76.133 18.432 77.173 19.368 ;
     RECT  76.237 14.352 77.269 17.16 ;
     RECT  77.173 18.432 77.269 20.088 ;
     RECT  76.997 43.152 77.285 43.176 ;
     RECT  77.269 14.352 77.461 20.088 ;
     RECT  76.493 2.016 77.605 3.576 ;
     RECT  76.637 5.712 77.605 5.736 ;
     RECT  77.137 13.056 77.605 13.128 ;
     RECT  77.461 14.112 77.605 20.088 ;
     RECT  76.781 28.992 77.605 29.592 ;
     RECT  77.605 5.28 77.677 5.736 ;
     RECT  76.493 21.168 77.749 22.44 ;
     RECT  76.853 23.856 77.749 25.08 ;
     RECT  76.637 32.4 77.749 35.736 ;
     RECT  77.605 28.704 77.893 29.592 ;
     RECT  77.605 2.016 78.008 3.96 ;
     RECT  77.677 5.04 78.008 5.736 ;
     RECT  76.961 7.392 78.008 8.808 ;
     RECT  77.389 9.792 78.008 9.816 ;
     RECT  76.709 11.376 78.008 11.4 ;
     RECT  77.605 13.056 78.008 20.088 ;
     RECT  77.749 21.168 78.008 25.08 ;
     RECT  76.853 26.064 78.008 27.336 ;
     RECT  77.893 28.512 78.008 29.592 ;
     RECT  77.749 31.776 78.008 35.736 ;
     RECT  76.385 37.056 78.008 37.08 ;
     RECT  76.097 38.64 78.008 40.968 ;
     RECT  78.008 2.016 78.112 41.052 ;
     RECT  78.112 2.016 78.304 41.016 ;
     RECT  78.304 10.176 78.419 11.976 ;
     RECT  78.304 37.056 78.419 41.016 ;
     RECT  78.419 10.416 78.437 11.976 ;
     RECT  78.304 2.016 78.473 8.904 ;
     RECT  78.304 13.008 78.653 16.152 ;
     RECT  78.304 33.072 78.653 36.072 ;
     RECT  78.304 28.656 78.689 29.256 ;
     RECT  78.653 14.352 79.049 16.152 ;
     RECT  78.473 2.064 79.235 8.904 ;
     RECT  79.235 2.064 79.265 4.92 ;
     RECT  79.235 6 79.265 7.176 ;
     RECT  78.304 31.44 79.297 32.04 ;
     RECT  78.653 33.072 79.297 35.736 ;
     RECT  79.049 15.696 79.525 16.152 ;
     RECT  78.304 17.616 79.525 24.792 ;
     RECT  79.265 2.064 79.553 4.584 ;
     RECT  78.437 10.848 79.621 11.976 ;
     RECT  78.653 13.008 79.621 13.128 ;
     RECT  79.621 10.848 79.765 13.128 ;
     RECT  79.049 14.352 79.765 14.712 ;
     RECT  79.765 10.848 79.811 14.712 ;
     RECT  79.525 15.696 79.841 24.792 ;
     RECT  79.297 31.44 79.877 35.736 ;
     RECT  79.841 17.04 79.909 24.792 ;
     RECT  78.304 26.112 79.909 27.432 ;
     RECT  79.265 6 79.913 6.984 ;
     RECT  79.811 10.848 79.945 11.976 ;
     RECT  79.235 8.688 79.957 8.904 ;
     RECT  79.945 10.56 79.957 11.976 ;
     RECT  79.811 13.104 79.985 14.712 ;
     RECT  79.841 15.696 80.021 15.72 ;
     RECT  79.877 31.728 80.125 35.736 ;
     RECT  78.419 37.968 80.125 41.016 ;
     RECT  79.913 6 80.129 6.84 ;
     RECT  80.125 31.728 80.305 36.072 ;
     RECT  80.125 37.296 80.305 41.016 ;
     RECT  79.553 4.56 80.341 4.584 ;
     RECT  80.129 6 80.341 6.552 ;
     RECT  79.957 8.688 80.341 11.976 ;
     RECT  79.909 17.04 80.444 27.432 ;
     RECT  78.689 28.656 80.444 28.68 ;
     RECT  79.801 29.664 80.444 29.688 ;
     RECT  79.909 30.72 80.444 30.744 ;
     RECT  80.444 17.04 80.485 28.68 ;
     RECT  80.444 29.664 80.485 30.744 ;
     RECT  80.485 17.04 80.531 30.744 ;
     RECT  79.553 2.064 80.593 2.904 ;
     RECT  80.341 4.56 80.593 6.552 ;
     RECT  80.593 2.064 80.633 6.552 ;
     RECT  80.633 2.064 80.741 6.264 ;
     RECT  80.305 31.728 80.869 41.016 ;
     RECT  80.869 31.536 80.956 41.016 ;
     RECT  80.956 31.728 80.993 41.016 ;
     RECT  80.341 8.4 81.025 11.976 ;
     RECT  80.993 31.728 81.059 37.32 ;
     RECT  80.741 2.064 81.065 2.28 ;
     RECT  79.985 13.488 81.133 14.712 ;
     RECT  77.033 0.096 81.137 0.552 ;
     RECT  81.133 13.44 81.169 14.712 ;
     RECT  81.169 13.152 81.197 14.712 ;
     RECT  81.025 7.584 81.205 11.976 ;
     RECT  81.197 13.104 81.205 14.712 ;
     RECT  80.993 38.976 81.245 41.016 ;
     RECT  81.205 7.584 81.281 14.712 ;
     RECT  81.281 10.272 81.421 14.712 ;
     RECT  80.531 17.04 81.493 30.264 ;
     RECT  81.281 7.584 81.539 8.712 ;
     RECT  81.137 0.528 81.605 0.552 ;
     RECT  81.421 10.272 81.605 14.808 ;
     RECT  81.493 16.752 81.605 30.264 ;
     RECT  81.605 16.752 81.637 25.32 ;
     RECT  81.637 16.032 81.677 25.32 ;
     RECT  81.677 21.504 81.821 25.32 ;
     RECT  81.065 2.256 81.853 2.28 ;
     RECT  81.677 16.032 81.857 20.328 ;
     RECT  80.741 3.6 81.923 6.264 ;
     RECT  81.605 11.424 81.929 14.808 ;
     RECT  81.923 3.6 81.965 5.88 ;
     RECT  81.929 12 81.965 14.808 ;
     RECT  81.821 21.504 81.965 25.128 ;
     RECT  81.853 2.256 82.037 2.52 ;
     RECT  81.965 3.6 82.037 4.584 ;
     RECT  81.059 34.176 82.069 37.32 ;
     RECT  81.245 38.976 82.069 40.872 ;
     RECT  82.069 34.176 82.145 40.872 ;
     RECT  81.965 12.72 82.357 14.808 ;
     RECT  81.857 16.032 82.357 18.456 ;
     RECT  81.059 31.728 82.597 33.048 ;
     RECT  82.597 31.728 82.645 33.096 ;
     RECT  82.145 34.704 82.645 40.872 ;
     RECT  81.605 10.272 82.933 10.296 ;
     RECT  82.645 31.728 82.969 33.192 ;
     RECT  82.357 12.72 83.005 18.456 ;
     RECT  81.965 22.608 83.029 25.128 ;
     RECT  81.539 8.4 83.041 8.712 ;
     RECT  83.029 22.608 83.173 25.224 ;
     RECT  81.605 26.496 83.173 30.264 ;
     RECT  83.041 7.968 83.221 8.712 ;
     RECT  82.645 34.704 83.269 40.968 ;
     RECT  83.221 7.392 83.293 8.712 ;
     RECT  83.173 22.608 83.293 30.264 ;
     RECT  82.969 31.728 83.293 33.24 ;
     RECT  81.857 20.16 83.401 20.328 ;
     RECT  81.965 21.504 83.401 21.528 ;
     RECT  82.037 2.496 83.408 2.52 ;
     RECT  82.037 3.6 83.408 3.96 ;
     RECT  81.965 5.76 83.408 5.88 ;
     RECT  83.293 7.392 83.408 8.808 ;
     RECT  82.933 10.272 83.408 11.016 ;
     RECT  83.005 12.72 83.408 18.792 ;
     RECT  83.401 20.16 83.408 21.528 ;
     RECT  83.293 22.608 83.408 33.24 ;
     RECT  83.269 34.656 83.408 40.968 ;
     RECT  83.408 2.148 83.512 41.052 ;
     RECT  83.512 2.418 83.704 40.782 ;
     RECT  83.704 30.048 83.729 30.936 ;
     RECT  83.704 23.664 83.837 28.824 ;
     RECT  83.729 30.048 83.837 30.888 ;
     RECT  83.704 37.968 83.837 40.584 ;
     RECT  83.704 4.752 83.873 5.784 ;
     RECT  83.837 37.968 83.873 40.44 ;
     RECT  83.704 17.376 83.945 22.2 ;
     RECT  83.837 25.824 83.945 28.824 ;
     RECT  83.704 36 83.981 36.552 ;
     RECT  83.704 31.92 84.014 33.144 ;
     RECT  83.873 5.472 84.053 5.784 ;
     RECT  83.704 6.912 84.197 9.288 ;
     RECT  83.873 37.968 84.233 40.392 ;
     RECT  84.197 7.008 84.269 9.288 ;
     RECT  84.233 37.968 84.269 39.528 ;
     RECT  83.704 13.056 84.305 15.48 ;
     RECT  83.945 18.72 84.413 22.2 ;
     RECT  83.704 2.496 84.629 2.808 ;
     RECT  84.014 31.968 84.701 33.144 ;
     RECT  84.269 7.2 84.707 9.288 ;
     RECT  83.945 17.376 84.737 17.496 ;
     RECT  84.701 31.968 84.737 32.904 ;
     RECT  84.305 14.16 84.769 15.48 ;
     RECT  83.837 23.664 84.773 24.456 ;
     RECT  84.053 5.472 84.913 5.496 ;
     RECT  84.737 17.472 84.913 17.496 ;
     RECT  84.737 32.304 84.917 32.904 ;
     RECT  84.305 13.056 84.949 13.128 ;
     RECT  84.413 19.344 84.949 22.2 ;
     RECT  84.773 23.664 84.949 23.736 ;
     RECT  84.949 19.344 84.953 23.736 ;
     RECT  83.981 36.336 84.989 36.552 ;
     RECT  83.704 10.992 85.021 11.448 ;
     RECT  84.949 12.72 85.021 13.128 ;
     RECT  84.769 14.16 85.025 16.248 ;
     RECT  83.837 30.048 85.196 30.072 ;
     RECT  84.707 8.928 85.205 9.288 ;
     RECT  83.704 34.704 85.237 34.728 ;
     RECT  85.196 29.184 85.283 30.072 ;
     RECT  84.953 19.344 85.313 23.688 ;
     RECT  84.269 37.968 85.345 39.288 ;
     RECT  85.025 14.16 85.349 14.568 ;
     RECT  84.913 17.472 85.381 18.168 ;
     RECT  85.313 19.344 85.381 22.776 ;
     RECT  85.283 29.616 85.385 30.072 ;
     RECT  84.989 36.336 85.385 36.504 ;
     RECT  83.945 25.824 85.493 28.152 ;
     RECT  85.493 25.824 85.525 27.912 ;
     RECT  85.021 10.992 85.637 13.128 ;
     RECT  85.381 17.472 85.763 22.776 ;
     RECT  85.763 18.672 85.781 22.2 ;
     RECT  85.781 19.68 85.811 22.2 ;
     RECT  84.629 2.496 85.885 2.52 ;
     RECT  85.637 11.952 85.885 13.128 ;
     RECT  85.349 14.16 85.885 14.52 ;
     RECT  85.82 10.272 85.907 10.296 ;
     RECT  84.707 7.2 85.921 7.224 ;
     RECT  85.885 2.496 85.925 3.432 ;
     RECT  85.385 36.48 85.957 36.504 ;
     RECT  85.345 37.584 85.957 39.288 ;
     RECT  85.957 36.48 86.003 39.288 ;
     RECT  85.763 17.472 86.105 17.544 ;
     RECT  85.811 19.776 86.105 22.2 ;
     RECT  85.885 11.952 86.177 14.52 ;
     RECT  86.177 12.96 86.213 14.52 ;
     RECT  86.003 38.88 86.249 39.288 ;
     RECT  85.921 7.2 86.317 7.464 ;
     RECT  86.249 38.928 86.321 39.288 ;
     RECT  86.213 13.056 86.341 14.52 ;
     RECT  85.025 15.648 86.341 16.248 ;
     RECT  86.341 13.056 86.387 16.248 ;
     RECT  86.387 13.056 86.428 15.912 ;
     RECT  84.913 5.04 86.453 5.496 ;
     RECT  86.317 7.2 86.453 7.944 ;
     RECT  86.453 5.04 86.461 7.944 ;
     RECT  85.205 9.12 86.461 9.288 ;
     RECT  85.385 29.616 86.492 29.64 ;
     RECT  86.317 31.296 86.492 31.32 ;
     RECT  85.885 40.416 86.501 40.44 ;
     RECT  86.245 33.552 86.525 33.576 ;
     RECT  85.237 34.704 86.525 34.776 ;
     RECT  84.917 32.304 86.533 32.328 ;
     RECT  86.461 5.04 86.537 9.288 ;
     RECT  86.533 32.304 86.569 32.376 ;
     RECT  86.525 33.552 86.569 34.776 ;
     RECT  86.105 19.776 86.573 19.992 ;
     RECT  86.537 5.04 86.579 5.736 ;
     RECT  85.525 25.104 86.579 27.912 ;
     RECT  86.492 29.616 86.579 31.32 ;
     RECT  86.579 31.296 86.605 31.32 ;
     RECT  86.569 32.304 86.605 34.776 ;
     RECT  86.579 5.04 86.645 5.496 ;
     RECT  86.537 6.864 86.645 9.288 ;
     RECT  86.003 36.48 86.675 37.656 ;
     RECT  86.428 13.056 86.681 14.52 ;
     RECT  86.605 23.952 86.713 23.976 ;
     RECT  86.579 25.104 86.713 27.192 ;
     RECT  86.629 39.312 86.717 39.432 ;
     RECT  85.925 3.216 86.789 3.432 ;
     RECT  86.645 7.536 86.789 9.288 ;
     RECT  86.605 31.296 86.825 34.776 ;
     RECT  86.573 19.776 87.005 19.8 ;
     RECT  86.825 31.296 87.005 34.488 ;
     RECT  85.781 18.672 87.041 18.696 ;
     RECT  87.073 28.416 87.109 28.44 ;
     RECT  86.579 29.616 87.109 29.64 ;
     RECT  86.645 5.04 87.145 5.16 ;
     RECT  87.145 4.848 87.149 5.16 ;
     RECT  87.109 28.416 87.149 29.64 ;
     RECT  86.105 21.168 87.217 22.2 ;
     RECT  87.005 32.352 87.221 34.488 ;
     RECT  86.789 3.408 87.257 3.432 ;
     RECT  86.789 7.536 87.257 7.992 ;
     RECT  86.713 23.952 87.257 27.192 ;
     RECT  87.257 25.44 87.443 27.192 ;
     RECT  86.681 13.056 87.473 13.416 ;
     RECT  86.105 17.52 87.473 17.544 ;
     RECT  87.257 23.952 87.473 23.976 ;
     RECT  87.217 20.928 87.577 22.2 ;
     RECT  86.681 14.448 87.649 14.52 ;
     RECT  87.005 31.296 87.653 31.32 ;
     RECT  86.675 37.056 87.689 37.656 ;
     RECT  86.717 39.312 87.788 39.336 ;
     RECT  87.577 40.704 87.788 40.728 ;
     RECT  86.177 11.952 87.98 11.976 ;
     RECT  87.473 13.056 87.98 13.08 ;
     RECT  87.149 4.848 88.261 4.872 ;
     RECT  87.221 34.464 88.297 34.488 ;
     RECT  87.689 37.056 88.309 37.608 ;
     RECT  86.789 9.216 88.369 9.288 ;
     RECT  87.289 10.32 88.369 10.344 ;
     RECT  87.221 32.352 88.369 33.048 ;
     RECT  87.289 2.256 88.405 2.28 ;
     RECT  88.297 34.464 88.441 34.728 ;
     RECT  88.309 36.096 88.441 37.608 ;
     RECT  88.261 4.848 88.477 5.208 ;
     RECT  87.257 7.92 88.501 7.992 ;
     RECT  88.369 9.216 88.501 10.344 ;
     RECT  87.577 20.928 88.645 22.584 ;
     RECT  87.443 25.44 88.693 25.464 ;
     RECT  87.443 26.496 88.693 27.192 ;
     RECT  88.405 2.256 88.808 2.904 ;
     RECT  88.477 3.936 88.808 5.208 ;
     RECT  88.261 6.672 88.808 6.696 ;
     RECT  88.501 7.92 88.808 10.344 ;
     RECT  87.98 11.952 88.808 13.08 ;
     RECT  87.649 14.448 88.808 14.856 ;
     RECT  86.428 15.888 88.808 15.912 ;
     RECT  88.801 17.088 88.808 17.112 ;
     RECT  88.645 20.688 88.808 22.584 ;
     RECT  88.693 25.44 88.808 27.192 ;
     RECT  87.149 28.416 88.808 29.256 ;
     RECT  88.369 32.304 88.808 33.048 ;
     RECT  88.441 34.464 88.808 37.608 ;
     RECT  87.788 39.312 88.808 40.728 ;
     RECT  88.808 2.148 88.912 41.052 ;
     RECT  88.912 2.256 89.104 40.782 ;
     RECT  89.104 24.144 89.201 27.192 ;
     RECT  89.104 19.248 89.219 21.288 ;
     RECT  89.104 37.584 89.219 37.608 ;
     RECT  89.104 22.752 89.237 22.776 ;
     RECT  89.104 34.608 89.245 36.456 ;
     RECT  89.104 39.312 89.309 39.336 ;
     RECT  89.104 14.448 89.315 14.952 ;
     RECT  89.104 30.72 89.345 33.048 ;
     RECT  89.219 20.016 89.353 21.288 ;
     RECT  89.201 24.144 89.366 24.216 ;
     RECT  89.104 2.256 89.411 4.008 ;
     RECT  89.411 2.256 89.452 3.336 ;
     RECT  89.366 24.192 89.452 24.216 ;
     RECT  89.345 31.632 89.489 33.048 ;
     RECT  89.245 34.608 89.525 36.12 ;
     RECT  89.104 12.528 89.705 13.08 ;
     RECT  89.525 34.608 90.133 34.776 ;
     RECT  89.353 21.264 90.241 21.288 ;
     RECT  89.201 25.536 90.389 27.192 ;
     RECT  89.525 36.096 90.389 36.12 ;
     RECT  89.104 9.648 90.421 9.912 ;
     RECT  89.104 10.896 90.421 10.92 ;
     RECT  89.104 29.232 90.421 29.256 ;
     RECT  89.104 16.368 90.565 17.208 ;
     RECT  90.097 18.672 90.565 18.696 ;
     RECT  90.565 16.368 90.611 18.696 ;
     RECT  90.529 37.584 90.637 37.608 ;
     RECT  90.611 17.856 90.677 18.216 ;
     RECT  90.637 37.344 90.677 37.608 ;
     RECT  90.421 29.232 90.713 29.784 ;
     RECT  90.421 9.648 90.785 10.92 ;
     RECT  90.389 26.208 90.817 27.192 ;
     RECT  90.133 33.936 90.853 34.776 ;
     RECT  90.785 10.896 90.893 10.92 ;
     RECT  90.853 33.936 90.893 35.352 ;
     RECT  89.104 7.632 90.925 8.04 ;
     RECT  89.315 14.928 90.925 14.952 ;
     RECT  90.925 7.392 90.929 8.04 ;
     RECT  90.925 14.208 90.997 14.952 ;
     RECT  90.611 16.368 90.997 16.536 ;
     RECT  89.705 12.528 91.033 12.552 ;
     RECT  89.489 31.632 91.105 32.328 ;
     RECT  90.893 33.936 91.105 33.96 ;
     RECT  90.929 7.392 91.109 7.704 ;
     RECT  89.452 2.832 91.141 3.336 ;
     RECT  90.637 4.368 91.141 4.392 ;
     RECT  89.104 5.472 91.141 5.496 ;
     RECT  90.241 21.264 91.177 22.2 ;
     RECT  91.141 5.472 91.181 5.64 ;
     RECT  91.105 31.632 91.181 33.96 ;
     RECT  91.141 2.256 91.187 4.392 ;
     RECT  90.677 37.344 91.189 37.368 ;
     RECT  91.177 21.072 91.217 22.2 ;
     RECT  90.817 26.208 91.217 27.768 ;
     RECT  91.189 36.432 91.235 37.368 ;
     RECT  91.235 36.432 91.289 36.648 ;
     RECT  90.493 38.784 91.321 38.808 ;
     RECT  90.997 14.208 91.433 16.536 ;
     RECT  91.181 5.616 91.501 5.64 ;
     RECT  91.217 22.176 91.537 22.2 ;
     RECT  91.501 5.616 91.609 6.312 ;
     RECT  91.109 7.392 91.609 7.416 ;
     RECT  91.217 26.208 91.613 26.76 ;
     RECT  89.353 20.016 91.717 20.04 ;
     RECT  91.217 21.072 91.717 21.096 ;
     RECT  91.433 14.928 91.753 16.536 ;
     RECT  91.717 19.344 91.763 21.096 ;
     RECT  90.785 9.648 91.829 9.672 ;
     RECT  91.537 22.176 91.829 22.824 ;
     RECT  90.677 18.192 91.897 18.216 ;
     RECT  91.763 19.344 91.897 21.048 ;
     RECT  91.321 38.784 91.901 39.048 ;
     RECT  91.897 18.192 91.937 21.048 ;
     RECT  91.181 32.448 91.973 33.96 ;
     RECT  91.217 27.744 92.005 27.768 ;
     RECT  91.609 5.616 92.009 7.416 ;
     RECT  92.005 27.744 92.041 28.44 ;
     RECT  90.713 29.76 92.041 29.784 ;
     RECT  92.041 27.744 92.051 29.784 ;
     RECT  91.753 14.928 92.077 17.208 ;
     RECT  91.937 18.192 92.077 19.032 ;
     RECT  91.289 36.624 92.081 36.648 ;
     RECT  90.961 40.8 92.108 40.824 ;
     RECT  91.187 2.256 92.117 3.576 ;
     RECT  92.077 14.928 92.117 19.032 ;
     RECT  92.108 40.128 92.195 40.824 ;
     RECT  90.745 24.528 92.197 24.552 ;
     RECT  91.613 26.208 92.197 26.232 ;
     RECT  92.197 24.528 92.284 26.232 ;
     RECT  92.009 5.616 92.297 6.312 ;
     RECT  92.117 18.72 92.369 19.032 ;
     RECT  92.284 24.528 92.369 24.552 ;
     RECT  91.033 11.76 92.437 12.552 ;
     RECT  92.009 7.392 92.473 7.416 ;
     RECT  91.465 31.008 92.473 31.032 ;
     RECT  92.473 7.392 92.513 8.232 ;
     RECT  91.937 20.016 92.549 21.048 ;
     RECT  92.117 2.4 92.617 3.576 ;
     RECT  91.901 39.024 92.621 39.048 ;
     RECT  91.829 22.176 92.653 22.776 ;
     RECT  90.893 35.328 92.761 35.352 ;
     RECT  91.861 10.464 92.797 10.488 ;
     RECT  92.797 9.888 92.869 10.488 ;
     RECT  92.284 26.208 92.905 26.232 ;
     RECT  92.473 31.008 92.905 31.512 ;
     RECT  92.905 30.432 92.909 31.512 ;
     RECT  92.761 35.328 92.921 35.88 ;
     RECT  92.051 27.744 92.963 29.256 ;
     RECT  92.909 31.488 92.965 31.512 ;
     RECT  91.973 33.072 92.965 33.96 ;
     RECT  92.617 2.4 92.977 3.96 ;
     RECT  92.965 31.488 92.981 33.96 ;
     RECT  92.905 26.208 92.989 26.76 ;
     RECT  92.977 2.4 93.017 4.536 ;
     RECT  92.981 31.488 93.017 33.672 ;
     RECT  92.921 35.28 93.049 35.88 ;
     RECT  93.017 31.488 93.052 33.432 ;
     RECT  92.297 5.952 93.121 6.312 ;
     RECT  93.017 2.4 93.161 2.856 ;
     RECT  92.963 27.888 93.161 29.256 ;
     RECT  92.869 9.744 93.193 10.488 ;
     RECT  92.437 11.76 93.193 13.416 ;
     RECT  93.049 35.28 93.233 36.504 ;
     RECT  92.549 20.112 93.265 21.048 ;
     RECT  92.653 22.032 93.265 22.776 ;
     RECT  93.265 20.112 93.301 22.776 ;
     RECT  92.117 14.928 93.409 17.496 ;
     RECT  93.193 9.744 93.481 13.416 ;
     RECT  93.409 14.784 93.481 17.496 ;
     RECT  93.409 37.968 93.493 37.992 ;
     RECT  92.369 18.72 93.625 18.792 ;
     RECT  93.481 9.744 93.733 17.496 ;
     RECT  93.301 20.112 93.805 23.4 ;
     RECT  93.625 18.72 93.985 19.032 ;
     RECT  93.805 20.112 93.985 24.168 ;
     RECT  93.052 31.488 94.049 31.512 ;
     RECT  93.052 33.072 94.049 33.432 ;
     RECT  93.161 27.888 94.069 29.064 ;
     RECT  93.733 9.36 94.165 17.496 ;
     RECT  93.985 18.72 94.201 24.168 ;
     RECT  93.161 2.592 94.208 2.856 ;
     RECT  93.017 3.936 94.208 4.536 ;
     RECT  93.121 5.952 94.208 6.696 ;
     RECT  92.513 7.872 94.208 8.232 ;
     RECT  94.165 9.36 94.208 17.64 ;
     RECT  94.201 18.72 94.208 24.936 ;
     RECT  92.989 26.208 94.208 26.232 ;
     RECT  94.069 27.216 94.208 29.064 ;
     RECT  92.909 30.432 94.208 30.456 ;
     RECT  94.049 31.488 94.208 33.432 ;
     RECT  93.233 35.328 94.208 36.504 ;
     RECT  93.493 37.968 94.208 38.232 ;
     RECT  93.637 39.792 94.208 39.816 ;
     RECT  92.195 40.8 94.208 40.824 ;
     RECT  94.208 2.148 94.312 41.052 ;
     RECT  94.312 2.208 94.349 40.824 ;
     RECT  94.349 2.208 94.504 40.782 ;
     RECT  94.504 14.928 94.565 17.688 ;
     RECT  94.504 18.768 94.637 19.368 ;
     RECT  94.504 11.232 94.643 13.848 ;
     RECT  94.565 15.312 94.691 17.688 ;
     RECT  94.637 18.768 94.709 19.32 ;
     RECT  94.504 2.208 94.781 4.968 ;
     RECT  94.691 15.312 94.781 17.64 ;
     RECT  94.504 30.048 94.925 34.104 ;
     RECT  94.781 4.944 95.069 4.968 ;
     RECT  94.504 20.592 95.171 24.936 ;
     RECT  94.504 6.384 95.213 6.696 ;
     RECT  94.925 31.536 95.213 34.104 ;
     RECT  94.504 36.432 95.285 37.608 ;
     RECT  95.213 31.872 95.357 34.104 ;
     RECT  94.709 18.768 95.429 18.84 ;
     RECT  94.504 9.36 95.537 9.384 ;
     RECT  94.504 26.208 95.645 28.536 ;
     RECT  94.643 11.376 95.677 13.848 ;
     RECT  95.171 20.592 95.701 22.776 ;
     RECT  95.285 36.432 95.753 37.128 ;
     RECT  94.504 39.312 95.756 40.392 ;
     RECT  95.677 10.464 95.789 14.184 ;
     RECT  94.781 15.312 95.789 17.448 ;
     RECT  95.756 39.312 95.797 40.536 ;
     RECT  95.701 19.92 95.825 22.776 ;
     RECT  95.797 38.688 95.843 40.536 ;
     RECT  95.429 18.816 95.853 18.84 ;
     RECT  95.789 10.464 95.857 11.832 ;
     RECT  95.843 38.688 95.897 39.912 ;
     RECT  94.781 2.208 96.113 3.624 ;
     RECT  95.825 20.112 96.149 22.776 ;
     RECT  95.357 34.08 96.181 34.104 ;
     RECT  94.504 35.424 96.181 35.448 ;
     RECT  95.645 26.208 96.185 28.488 ;
     RECT  96.149 20.352 96.253 22.776 ;
     RECT  95.171 24.144 96.253 24.936 ;
     RECT  96.253 20.352 96.293 24.936 ;
     RECT  94.925 30.048 96.325 30.168 ;
     RECT  95.357 31.872 96.325 33.096 ;
     RECT  96.181 34.08 96.325 35.448 ;
     RECT  95.213 6.672 96.361 6.696 ;
     RECT  96.325 30.048 96.433 30.84 ;
     RECT  96.325 31.872 96.433 35.448 ;
     RECT  96.113 2.208 96.437 3.432 ;
     RECT  96.433 30.048 96.437 35.448 ;
     RECT  95.897 39.312 96.509 39.912 ;
     RECT  96.437 2.208 96.515 2.904 ;
     RECT  95.789 15.552 96.577 17.448 ;
     RECT  94.504 7.872 96.617 7.896 ;
     RECT  95.789 13.296 96.689 14.184 ;
     RECT  96.293 24.912 96.709 24.936 ;
     RECT  96.185 26.208 96.709 27.336 ;
     RECT  96.361 6.672 96.725 6.888 ;
     RECT  95.753 37.008 96.793 37.128 ;
     RECT  96.689 13.824 96.797 14.184 ;
     RECT  96.185 28.416 96.829 28.488 ;
     RECT  96.437 30.048 96.829 33.144 ;
     RECT  96.829 28.416 96.833 33.144 ;
     RECT  96.725 6.864 96.941 6.888 ;
     RECT  96.577 15.552 96.947 18.408 ;
     RECT  96.437 34.128 97.004 35.448 ;
     RECT  96.793 36.624 97.004 37.128 ;
     RECT  96.833 28.416 97.013 33 ;
     RECT  96.293 20.352 97.141 23.4 ;
     RECT  97.013 28.416 97.157 30.84 ;
     RECT  96.509 39.6 97.189 39.912 ;
     RECT  97.157 28.416 97.297 30.456 ;
     RECT  96.797 13.824 97.373 13.848 ;
     RECT  96.709 24.912 97.373 27.336 ;
     RECT  96.973 8.208 97.441 8.232 ;
     RECT  95.857 9.648 97.441 11.832 ;
     RECT  97.004 34.128 97.445 37.128 ;
     RECT  97.441 3.888 97.513 3.912 ;
     RECT  96.901 4.896 97.513 4.92 ;
     RECT  97.141 19.92 97.513 23.4 ;
     RECT  97.373 26.208 97.513 27.336 ;
     RECT  97.297 28.32 97.513 30.456 ;
     RECT  97.513 26.208 97.523 30.456 ;
     RECT  97.513 3.888 97.621 4.92 ;
     RECT  97.525 38.544 97.657 38.568 ;
     RECT  97.189 39.6 97.657 40.152 ;
     RECT  96.947 15.552 97.669 17.64 ;
     RECT  97.669 15.072 97.756 17.64 ;
     RECT  97.445 34.128 97.769 36.408 ;
     RECT  97.657 38.544 97.805 40.152 ;
     RECT  97.441 8.208 97.873 11.832 ;
     RECT  97.769 34.752 97.913 36.408 ;
     RECT  97.873 8.16 98.017 11.832 ;
     RECT  97.013 32.448 98.093 33 ;
     RECT  97.523 30.432 98.125 30.456 ;
     RECT  97.513 19.248 98.165 23.4 ;
     RECT  98.017 8.16 98.233 12.6 ;
     RECT  98.093 32.784 98.237 33 ;
     RECT  97.805 38.544 98.237 39.624 ;
     RECT  97.621 3.84 98.377 4.92 ;
     RECT  97.756 15.552 98.417 17.64 ;
     RECT  98.165 19.632 98.485 23.4 ;
     RECT  97.373 24.912 98.485 25.224 ;
     RECT  96.515 2.208 98.489 2.856 ;
     RECT  98.489 2.304 98.521 2.856 ;
     RECT  98.377 3.84 98.521 4.968 ;
     RECT  98.485 19.632 98.521 25.224 ;
     RECT  97.523 26.208 98.521 29.304 ;
     RECT  98.197 6.672 98.565 6.696 ;
     RECT  98.233 8.16 98.565 12.888 ;
     RECT  98.417 15.888 98.593 17.64 ;
     RECT  98.521 19.632 98.597 29.304 ;
     RECT  98.565 6.672 98.627 12.888 ;
     RECT  97.913 34.896 98.633 36.408 ;
     RECT  98.633 36.384 98.989 36.408 ;
     RECT  98.989 36.384 99.061 37.032 ;
     RECT  98.237 38.544 99.061 38.568 ;
     RECT  98.629 33.072 99.157 33.096 ;
     RECT  99.061 36.384 99.397 38.568 ;
     RECT  98.237 39.6 99.397 39.624 ;
     RECT  99.157 33.072 99.445 33.576 ;
     RECT  98.633 34.896 99.445 35.4 ;
     RECT  99.445 33.072 99.452 35.4 ;
     RECT  98.627 9.072 99.601 12.888 ;
     RECT  99.565 14.496 99.601 14.52 ;
     RECT  98.593 15.888 99.601 18.408 ;
     RECT  98.597 19.632 99.601 29.064 ;
     RECT  98.521 2.304 99.608 4.968 ;
     RECT  98.627 7.584 99.608 7.944 ;
     RECT  99.601 9.072 99.608 14.52 ;
     RECT  99.601 15.888 99.608 29.064 ;
     RECT  98.125 30.432 99.608 31.416 ;
     RECT  99.452 32.448 99.608 35.4 ;
     RECT  99.397 36.384 99.608 39.624 ;
     RECT  99.608 2.148 99.712 41.052 ;
     RECT  99.712 2.304 99.904 40.782 ;
     RECT  99.904 25.2 100.001 36.936 ;
     RECT  99.904 2.304 100.019 5.496 ;
     RECT  99.904 6.816 100.019 12.216 ;
     RECT  100.001 25.2 100.019 36.696 ;
     RECT  100.019 8.448 100.067 12.216 ;
     RECT  100.019 28.944 100.067 36.696 ;
     RECT  100.019 2.304 100.073 2.808 ;
     RECT  97.117 0.096 100.249 0.12 ;
     RECT  99.904 37.968 100.433 40.632 ;
     RECT  99.904 15.696 100.577 21.048 ;
     RECT  100.067 29.04 100.721 36.696 ;
     RECT  100.433 37.968 100.829 39.624 ;
     RECT  100.721 29.04 100.901 34.248 ;
     RECT  99.904 13.68 100.933 14.712 ;
     RECT  100.577 15.696 100.933 17.784 ;
     RECT  99.904 22.224 100.969 24.168 ;
     RECT  100.019 25.2 100.969 27.96 ;
     RECT  100.721 35.328 100.972 36.696 ;
     RECT  100.969 22.224 100.973 27.96 ;
     RECT  100.019 4.176 101.009 5.496 ;
     RECT  100.901 29.664 101.045 34.248 ;
     RECT  100.249 0.048 101.077 0.12 ;
     RECT  101.045 30.432 101.267 34.248 ;
     RECT  101.009 4.512 101.297 5.496 ;
     RECT  100.073 2.496 101.365 2.808 ;
     RECT  101.365 2.496 101.401 3.096 ;
     RECT  100.019 6.816 101.401 7.416 ;
     RECT  100.972 36.048 101.401 36.696 ;
     RECT  100.829 37.968 101.401 39.48 ;
     RECT  101.267 31.776 101.441 34.248 ;
     RECT  101.293 42.192 101.473 42.216 ;
     RECT  101.473 42.192 101.509 42.264 ;
     RECT  100.897 40.704 101.513 40.728 ;
     RECT  101.441 31.776 101.621 32.76 ;
     RECT  100.933 13.68 101.644 17.784 ;
     RECT  100.973 22.224 101.657 25.128 ;
     RECT  100.973 26.352 101.693 27.96 ;
     RECT  101.401 36.048 101.801 39.48 ;
     RECT  101.401 6.816 101.869 7.512 ;
     RECT  100.067 8.736 101.905 12.216 ;
     RECT  101.644 13.68 101.905 16.392 ;
     RECT  101.657 22.224 101.905 23.4 ;
     RECT  101.509 42.192 101.905 42.36 ;
     RECT  101.869 6.288 102.013 7.512 ;
     RECT  101.905 8.736 102.013 16.392 ;
     RECT  101.644 17.664 102.017 17.784 ;
     RECT  101.621 31.824 102.017 32.76 ;
     RECT  101.077 0.048 102.049 0.312 ;
     RECT  102.013 6.288 102.089 16.392 ;
     RECT  101.401 2.496 102.121 3.384 ;
     RECT  101.297 4.512 102.121 4.824 ;
     RECT  102.089 6.288 102.125 11.016 ;
     RECT  101.905 22.176 102.125 23.4 ;
     RECT  101.905 42.192 102.131 43.08 ;
     RECT  102.125 22.176 102.157 22.728 ;
     RECT  101.801 36.048 102.269 37.608 ;
     RECT  102.269 36.288 102.377 37.608 ;
     RECT  102.049 0.048 102.409 0.504 ;
     RECT  102.131 42.192 102.437 42.408 ;
     RECT  102.157 22.128 102.485 22.728 ;
     RECT  102.017 32.256 102.545 32.76 ;
     RECT  101.441 33.792 102.545 34.248 ;
     RECT  102.545 32.256 102.589 34.248 ;
     RECT  101.693 26.352 102.593 27.912 ;
     RECT  102.589 32.256 102.611 34.632 ;
     RECT  102.437 41.568 102.611 42.408 ;
     RECT  102.373 28.896 102.613 28.92 ;
     RECT  101.267 30.432 102.613 30.792 ;
     RECT  102.089 12 102.629 16.392 ;
     RECT  102.593 27.792 102.629 27.912 ;
     RECT  102.613 28.896 102.659 30.792 ;
     RECT  102.373 40.464 102.661 40.488 ;
     RECT  102.611 41.568 102.661 42.168 ;
     RECT  102.485 22.128 102.665 22.632 ;
     RECT  102.125 6.288 102.697 9.048 ;
     RECT  101.801 38.592 102.697 39.48 ;
     RECT  102.661 40.464 102.697 42.168 ;
     RECT  102.665 22.128 102.701 22.488 ;
     RECT  102.629 12.912 102.877 16.392 ;
     RECT  102.659 29.088 102.917 30.792 ;
     RECT  102.017 17.664 102.949 17.688 ;
     RECT  102.697 6.24 102.953 9.048 ;
     RECT  102.949 17.568 102.989 17.688 ;
     RECT  102.701 22.128 102.989 22.2 ;
     RECT  100.577 18.768 103.021 21.048 ;
     RECT  102.989 22.128 103.021 22.152 ;
     RECT  101.657 25.104 103.021 25.128 ;
     RECT  102.917 30.336 103.025 30.792 ;
     RECT  102.377 36.576 103.043 37.608 ;
     RECT  102.877 12.912 103.057 16.536 ;
     RECT  102.989 17.568 103.057 17.592 ;
     RECT  103.021 18.768 103.061 22.152 ;
     RECT  102.593 26.352 103.133 26.808 ;
     RECT  103.043 37.056 103.133 37.608 ;
     RECT  102.917 29.088 103.169 29.112 ;
     RECT  103.025 30.336 103.169 30.504 ;
     RECT  102.697 38.592 103.187 42.168 ;
     RECT  103.021 25.056 103.189 25.128 ;
     RECT  102.611 32.976 103.201 34.632 ;
     RECT  102.125 10.224 103.205 11.016 ;
     RECT  103.057 12.912 103.205 17.592 ;
     RECT  103.133 37.104 103.205 37.608 ;
     RECT  102.953 6.24 103.235 6.888 ;
     RECT  103.189 24.288 103.235 25.656 ;
     RECT  103.205 37.44 103.273 37.608 ;
     RECT  103.187 38.592 103.273 38.712 ;
     RECT  103.187 39.744 103.283 41.064 ;
     RECT  102.953 7.92 103.309 9.048 ;
     RECT  103.205 10.224 103.309 10.824 ;
     RECT  103.205 13.008 103.321 17.592 ;
     RECT  103.321 13.008 103.349 16.536 ;
     RECT  103.061 18.768 103.417 21.672 ;
     RECT  102.121 2.496 103.456 4.824 ;
     RECT  103.273 37.44 103.457 38.712 ;
     RECT  103.456 2.496 103.561 4.872 ;
     RECT  103.235 6.24 103.561 6.84 ;
     RECT  103.133 26.736 103.561 26.808 ;
     RECT  102.629 27.792 103.561 27.816 ;
     RECT  103.561 2.496 103.667 6.84 ;
     RECT  103.309 7.92 103.673 10.824 ;
     RECT  103.349 13.008 103.673 16.392 ;
     RECT  102.409 0.048 103.697 0.552 ;
     RECT  103.187 42.048 103.705 42.168 ;
     RECT  103.667 2.496 103.745 4.104 ;
     RECT  103.673 14.064 103.745 16.392 ;
     RECT  103.697 0.048 103.781 1.176 ;
     RECT  103.201 32.976 103.781 34.824 ;
     RECT  103.745 2.496 103.813 3.912 ;
     RECT  103.673 7.92 103.889 10.68 ;
     RECT  103.169 30.48 103.889 30.504 ;
     RECT  103.889 7.92 103.907 7.992 ;
     RECT  103.813 1.728 103.961 3.912 ;
     RECT  103.321 17.568 104.137 17.592 ;
     RECT  103.417 18.576 104.137 21.672 ;
     RECT  103.235 24.288 104.209 24.456 ;
     RECT  103.561 26.736 104.209 27.816 ;
     RECT  103.283 39.744 104.209 41.016 ;
     RECT  104.065 22.8 104.281 22.824 ;
     RECT  104.209 26.736 104.293 27.96 ;
     RECT  104.273 29.088 104.293 29.112 ;
     RECT  104.293 26.736 104.317 29.112 ;
     RECT  103.235 25.632 104.341 25.656 ;
     RECT  104.317 26.688 104.341 29.112 ;
     RECT  104.209 39.504 104.425 41.016 ;
     RECT  103.705 42.048 104.425 43.08 ;
     RECT  104.137 17.568 104.461 21.672 ;
     RECT  104.281 22.8 104.461 22.872 ;
     RECT  104.209 23.904 104.461 24.456 ;
     RECT  104.137 31.776 104.605 31.8 ;
     RECT  103.781 33.264 104.78 34.824 ;
     RECT  104.677 36.048 104.78 36.072 ;
     RECT  103.457 37.44 104.78 38.184 ;
     RECT  104.461 17.568 104.821 24.456 ;
     RECT  104.78 33.264 104.831 38.184 ;
     RECT  103.745 15.696 104.857 16.392 ;
     RECT  104.821 17.568 104.857 24.504 ;
     RECT  103.745 14.064 104.869 14.376 ;
     RECT  104.831 33.264 104.869 38.28 ;
     RECT  103.889 9.024 104.893 10.68 ;
     RECT  103.907 7.92 104.929 7.944 ;
     RECT  104.893 9.024 104.929 10.92 ;
     RECT  103.961 1.728 105.008 2.904 ;
     RECT  103.961 3.888 105.008 3.912 ;
     RECT  103.667 5.184 105.008 6.84 ;
     RECT  104.929 7.92 105.008 10.92 ;
     RECT  104.869 13.824 105.008 14.376 ;
     RECT  104.857 15.696 105.008 24.648 ;
     RECT  104.341 25.632 105.008 29.112 ;
     RECT  104.137 30.432 105.008 30.456 ;
     RECT  104.605 31.776 105.008 32.136 ;
     RECT  104.869 33.264 105.008 38.52 ;
     RECT  104.425 39.504 105.008 43.08 ;
     RECT  105.008 1.728 105.304 43.08 ;
     RECT  105.304 6.24 105.443 10.92 ;
     RECT  105.304 30.336 105.473 30.552 ;
     RECT  105.304 13.632 105.509 21.672 ;
     RECT  105.304 36.528 105.545 38.424 ;
     RECT  105.304 22.848 105.653 24.648 ;
     RECT  105.509 13.632 105.683 16.392 ;
     RECT  105.653 22.848 105.725 24.504 ;
     RECT  105.545 36.528 105.725 37.416 ;
     RECT  105.304 12.528 105.779 12.552 ;
     RECT  105.304 1.728 105.833 5.208 ;
     RECT  105.443 6.24 105.869 10.68 ;
     RECT  105.833 2.304 105.877 5.208 ;
     RECT  105.869 6.288 105.941 10.68 ;
     RECT  105.545 38.4 106.013 38.424 ;
     RECT  105.941 6.528 106.121 10.68 ;
     RECT  105.725 23.136 106.121 24.504 ;
     RECT  103.781 0.048 106.157 0.552 ;
     RECT  105.725 36.624 106.229 37.416 ;
     RECT  106.121 23.568 106.373 24.504 ;
     RECT  105.304 26.352 106.441 28.968 ;
     RECT  105.304 39.456 106.597 43.08 ;
     RECT  106.229 36.624 106.625 37.08 ;
     RECT  106.693 12.384 106.765 12.408 ;
     RECT  105.473 30.528 106.789 30.552 ;
     RECT  105.877 2.352 106.909 5.208 ;
     RECT  106.441 26.352 106.909 29.064 ;
     RECT  106.157 0.096 106.933 0.552 ;
     RECT  105.304 31.776 106.949 34.776 ;
     RECT  106.765 12.096 106.981 12.408 ;
     RECT  105.509 17.568 106.981 21.672 ;
     RECT  106.933 0.096 107.021 0.648 ;
     RECT  106.909 26.352 107.053 29.112 ;
     RECT  106.789 30.192 107.053 30.552 ;
     RECT  106.597 39.312 107.053 43.08 ;
     RECT  106.909 2.352 107.084 5.496 ;
     RECT  106.121 6.528 107.084 7.128 ;
     RECT  106.121 8.448 107.089 10.68 ;
     RECT  107.053 38.688 107.093 43.08 ;
     RECT  107.021 0.096 107.116 0.6 ;
     RECT  106.981 17.568 107.129 22.488 ;
     RECT  107.053 26.352 107.129 30.696 ;
     RECT  106.981 12.096 107.161 12.552 ;
     RECT  105.683 13.968 107.161 16.392 ;
     RECT  107.084 2.352 107.171 7.128 ;
     RECT  107.161 12.096 107.173 16.392 ;
     RECT  106.949 31.776 107.201 34.248 ;
     RECT  107.173 12.096 107.267 16.44 ;
     RECT  107.009 25.104 107.353 25.128 ;
     RECT  107.129 26.352 107.356 28.632 ;
     RECT  107.093 39.792 107.381 43.08 ;
     RECT  107.116 0.096 107.411 0.552 ;
     RECT  107.267 12.096 107.417 13.32 ;
     RECT  107.417 12.096 107.525 12.552 ;
     RECT  107.129 17.568 107.557 19.368 ;
     RECT  106.625 36.624 107.557 37.032 ;
     RECT  107.171 6.72 107.593 7.128 ;
     RECT  107.089 8.448 107.593 10.824 ;
     RECT  107.267 14.784 107.701 16.44 ;
     RECT  107.557 17.472 107.701 19.368 ;
     RECT  107.129 29.616 107.737 30.696 ;
     RECT  107.171 2.352 107.747 5.736 ;
     RECT  107.381 39.792 107.795 42.216 ;
     RECT  107.129 20.544 107.797 22.488 ;
     RECT  106.373 23.568 107.797 23.976 ;
     RECT  107.797 20.544 107.885 23.976 ;
     RECT  107.201 31.968 107.917 34.248 ;
     RECT  107.017 35.28 107.917 35.304 ;
     RECT  107.356 26.352 107.921 28.296 ;
     RECT  107.795 39.792 107.921 42.168 ;
     RECT  107.093 38.688 107.953 38.712 ;
     RECT  107.747 4.56 107.957 5.736 ;
     RECT  107.921 28.272 107.993 28.296 ;
     RECT  107.593 6.72 108.035 10.824 ;
     RECT  107.885 20.928 108.101 23.976 ;
     RECT  108.035 6.72 108.173 7.944 ;
     RECT  107.701 14.784 108.173 19.368 ;
     RECT  107.921 39.792 108.173 41.88 ;
     RECT  108.236 13.584 108.277 13.608 ;
     RECT  108.173 14.784 108.277 18.264 ;
     RECT  107.953 38.16 108.313 38.712 ;
     RECT  108.173 39.792 108.313 41.016 ;
     RECT  107.917 31.968 108.389 35.304 ;
     RECT  107.525 12.096 108.421 12.408 ;
     RECT  108.389 32.304 108.421 35.304 ;
     RECT  107.557 36.48 108.421 37.032 ;
     RECT  108.421 32.304 108.425 37.032 ;
     RECT  107.737 29.616 108.457 30.792 ;
     RECT  107.957 4.56 108.497 4.968 ;
     RECT  107.411 0.096 108.529 0.456 ;
     RECT  108.035 9.024 108.529 10.824 ;
     RECT  108.421 11.808 108.529 12.408 ;
     RECT  108.457 29.088 108.709 30.792 ;
     RECT  108.425 32.304 108.713 35.928 ;
     RECT  108.529 0.048 108.716 0.456 ;
     RECT  108.529 9.024 108.745 12.552 ;
     RECT  108.277 13.584 108.745 18.264 ;
     RECT  108.497 4.56 108.755 4.68 ;
     RECT  108.101 20.928 108.785 23.688 ;
     RECT  108.716 0.048 108.803 0.504 ;
     RECT  108.803 0.048 108.851 0.408 ;
     RECT  108.785 20.928 108.893 22.824 ;
     RECT  108.745 9.024 108.965 18.264 ;
     RECT  108.173 19.344 108.965 19.368 ;
     RECT  107.921 26.352 109.001 27.096 ;
     RECT  108.425 36.96 109.069 37.032 ;
     RECT  108.313 38.16 109.069 41.016 ;
     RECT  108.893 20.928 109.141 22.2 ;
     RECT  108.965 9.024 109.145 16.824 ;
     RECT  108.709 29.088 109.145 30.888 ;
     RECT  108.173 6.72 109.177 7.128 ;
     RECT  109.145 29.088 109.177 30.84 ;
     RECT  109.145 10.32 109.181 16.824 ;
     RECT  109.181 10.32 109.217 12.888 ;
     RECT  109.141 20.688 109.289 22.2 ;
     RECT  108.713 32.304 109.393 35.112 ;
     RECT  109.177 6.72 109.465 7.992 ;
     RECT  108.457 25.296 109.465 25.32 ;
     RECT  109.069 36.96 109.465 41.016 ;
     RECT  109.465 6.288 109.645 7.992 ;
     RECT  109.145 9.024 109.645 9.048 ;
     RECT  108.851 0.048 109.649 0.312 ;
     RECT  109.393 31.968 109.861 35.112 ;
     RECT  109.001 26.736 110.005 27.096 ;
     RECT  109.861 31.92 110.005 35.112 ;
     RECT  108.965 18.144 110.077 18.264 ;
     RECT  109.645 6.288 110.113 9.048 ;
     RECT  109.289 20.688 110.365 22.056 ;
     RECT  107.747 2.352 110.401 3.336 ;
     RECT  108.755 4.56 110.401 4.584 ;
     RECT  109.181 14.112 110.401 16.824 ;
     RECT  110.077 18.144 110.401 18.36 ;
     RECT  110.005 26.64 110.401 27.096 ;
     RECT  110.401 2.352 110.408 4.584 ;
     RECT  110.113 6.288 110.408 9.096 ;
     RECT  109.217 10.32 110.408 11.448 ;
     RECT  109.217 12.864 110.408 12.888 ;
     RECT  110.401 14.112 110.408 18.36 ;
     RECT  110.365 19.776 110.408 22.056 ;
     RECT  109.465 25.104 110.408 25.32 ;
     RECT  110.401 26.64 110.408 27.912 ;
     RECT  109.177 29.04 110.408 30.84 ;
     RECT  110.005 31.92 110.408 35.544 ;
     RECT  109.465 36.624 110.408 41.016 ;
     RECT  110.408 2.148 110.512 41.052 ;
     RECT  110.512 2.352 110.704 40.968 ;
     RECT  110.704 18.24 110.837 22.776 ;
     RECT  110.704 2.352 110.873 2.904 ;
     RECT  110.704 6.288 110.873 6.84 ;
     RECT  110.704 31.92 110.963 37.032 ;
     RECT  110.963 31.92 111.089 35.352 ;
     RECT  110.704 7.968 111.125 11.448 ;
     RECT  110.704 25.2 111.148 28.44 ;
     RECT  110.837 20.016 111.161 22.776 ;
     RECT  111.089 32.016 111.197 35.352 ;
     RECT  111.125 7.968 111.377 11.304 ;
     RECT  109.649 0.048 111.413 0.168 ;
     RECT  110.704 14.64 111.449 14.76 ;
     RECT  110.704 30.816 111.685 30.888 ;
     RECT  110.704 4.224 111.697 5.112 ;
     RECT  110.873 6.768 111.733 6.84 ;
     RECT  110.704 15.984 111.733 17.208 ;
     RECT  110.837 18.24 111.733 18.936 ;
     RECT  111.148 26.928 111.733 28.44 ;
     RECT  111.148 25.2 111.773 25.752 ;
     RECT  111.377 7.968 111.779 9.672 ;
     RECT  111.733 26.928 111.845 28.536 ;
     RECT  111.733 15.984 111.877 18.936 ;
     RECT  111.733 6.768 111.953 6.984 ;
     RECT  110.704 13.104 111.953 13.656 ;
     RECT  111.953 13.104 112.021 13.128 ;
     RECT  111.779 9.312 112.022 9.672 ;
     RECT  110.873 2.352 112.057 2.856 ;
     RECT  111.697 4.224 112.057 5.304 ;
     RECT  111.197 32.016 112.061 33.96 ;
     RECT  110.704 38.448 112.129 40.968 ;
     RECT  112.057 2.352 112.165 5.304 ;
     RECT  111.953 6.768 112.165 6.792 ;
     RECT  111.377 10.752 112.165 11.304 ;
     RECT  112.021 12.768 112.165 13.128 ;
     RECT  111.845 26.928 112.169 28.44 ;
     RECT  112.165 2.352 112.205 6.792 ;
     RECT  111.877 15.408 112.237 18.936 ;
     RECT  111.161 20.016 112.237 20.568 ;
     RECT  112.205 2.352 112.249 5.832 ;
     RECT  111.779 7.968 112.313 8.232 ;
     RECT  112.022 9.36 112.313 9.672 ;
     RECT  112.313 9.36 112.349 9.528 ;
     RECT  112.165 10.752 112.349 13.128 ;
     RECT  112.061 32.016 112.385 33.912 ;
     RECT  111.685 30.192 112.421 30.888 ;
     RECT  110.963 36.48 112.453 37.032 ;
     RECT  112.237 15.408 112.525 20.568 ;
     RECT  112.453 36.48 112.537 37.176 ;
     RECT  112.525 14.736 112.633 20.568 ;
     RECT  111.413 0.048 112.637 0.12 ;
     RECT  112.633 14.592 112.669 20.568 ;
     RECT  111.161 21.936 112.669 22.776 ;
     RECT  111.197 35.328 112.705 35.352 ;
     RECT  112.537 36.48 112.705 36.552 ;
     RECT  112.669 14.592 112.745 22.776 ;
     RECT  112.349 10.752 112.781 12.024 ;
     RECT  112.745 14.592 112.889 19.272 ;
     RECT  112.705 35.328 112.961 36.552 ;
     RECT  112.249 2.352 113.075 5.784 ;
     RECT  111.773 25.728 113.132 25.752 ;
     RECT  112.889 14.592 113.141 17.208 ;
     RECT  113.132 25.056 113.219 25.752 ;
     RECT  113.219 25.392 113.267 25.752 ;
     RECT  112.169 26.928 113.267 27.96 ;
     RECT  112.637 0.048 113.321 0.072 ;
     RECT  112.889 18.432 113.357 19.272 ;
     RECT  112.349 13.104 113.393 13.128 ;
     RECT  113.075 3.936 113.429 5.784 ;
     RECT  112.385 32.016 113.461 33.432 ;
     RECT  112.313 7.968 113.497 8.184 ;
     RECT  112.349 9.36 113.497 9.432 ;
     RECT  113.141 14.592 113.497 15.288 ;
     RECT  113.267 25.728 113.497 25.752 ;
     RECT  113.429 4.656 113.501 5.784 ;
     RECT  112.745 20.544 113.545 22.776 ;
     RECT  112.129 38.208 113.612 40.968 ;
     RECT  113.497 6.816 113.677 6.84 ;
     RECT  113.497 7.968 113.677 9.432 ;
     RECT  113.612 38.112 113.699 40.968 ;
     RECT  113.267 27.744 113.713 27.96 ;
     RECT  112.961 36.432 113.753 36.552 ;
     RECT  113.677 6.816 113.893 9.432 ;
     RECT  112.781 11.136 113.893 12.024 ;
     RECT  113.461 31.872 113.929 33.432 ;
     RECT  113.357 18.432 113.933 18.792 ;
     RECT  113.753 36.432 113.933 36.504 ;
     RECT  113.497 14.352 114.001 15.288 ;
     RECT  113.075 2.352 114.005 2.952 ;
     RECT  113.545 21.072 114.005 22.776 ;
     RECT  113.699 38.448 114.005 40.968 ;
     RECT  114.005 38.64 114.113 40.968 ;
     RECT  113.141 16.944 114.14 17.208 ;
     RECT  113.929 31.872 114.145 34.056 ;
     RECT  114.001 13.632 114.181 15.288 ;
     RECT  114.14 16.464 114.181 17.208 ;
     RECT  112.421 30.864 114.181 30.888 ;
     RECT  113.713 27.744 114.185 28.728 ;
     RECT  113.893 6.816 114.217 12.024 ;
     RECT  114.181 13.632 114.227 17.208 ;
     RECT  114.217 6.816 114.257 12.504 ;
     RECT  113.501 4.896 114.437 5.784 ;
     RECT  114.181 30.048 114.476 30.888 ;
     RECT  114.145 31.872 114.476 34.152 ;
     RECT  114.113 38.64 114.509 40.92 ;
     RECT  114.476 30.048 114.563 34.152 ;
     RECT  112.669 23.952 114.577 23.976 ;
     RECT  114.437 5.088 114.617 5.784 ;
     RECT  114.257 6.816 114.617 11.304 ;
     RECT  114.577 23.952 114.617 24.12 ;
     RECT  114.227 13.68 114.761 14.376 ;
     RECT  113.933 36.48 114.805 36.504 ;
     RECT  114.005 21.936 115.009 22.776 ;
     RECT  114.227 16.944 115.045 17.208 ;
     RECT  114.005 2.352 115.141 2.856 ;
     RECT  115.093 3.936 115.141 3.96 ;
     RECT  113.497 25.728 115.141 26.712 ;
     RECT  114.185 27.744 115.141 28.2 ;
     RECT  114.563 31.872 115.189 34.152 ;
     RECT  112.961 35.328 115.189 35.352 ;
     RECT  114.761 14.208 115.333 14.376 ;
     RECT  114.227 15.408 115.333 15.816 ;
     RECT  114.805 36.48 115.34 37.464 ;
     RECT  113.933 18.72 115.441 18.792 ;
     RECT  115.052 5.952 115.657 6.12 ;
     RECT  114.617 7.632 115.657 11.304 ;
     RECT  115.045 16.944 115.693 17.736 ;
     RECT  115.693 16.848 115.729 17.736 ;
     RECT  115.441 18.72 115.729 19.56 ;
     RECT  115.141 2.352 115.808 3.96 ;
     RECT  115.657 5.952 115.808 11.304 ;
     RECT  114.257 12.48 115.808 12.504 ;
     RECT  115.333 14.208 115.808 15.816 ;
     RECT  115.729 16.848 115.808 19.56 ;
     RECT  115.009 21.168 115.808 22.776 ;
     RECT  114.617 24.096 115.808 24.12 ;
     RECT  115.141 25.728 115.808 28.2 ;
     RECT  114.563 30.048 115.808 30.84 ;
     RECT  115.189 31.872 115.808 35.352 ;
     RECT  115.34 36.48 115.808 37.608 ;
     RECT  114.509 38.64 115.808 40.824 ;
     RECT  115.808 2.148 115.912 41.052 ;
     RECT  115.912 2.418 116.104 40.782 ;
     RECT  116.104 14.736 116.165 15.768 ;
     RECT  116.104 29.52 116.243 32.328 ;
     RECT  116.104 22.752 116.273 24.12 ;
     RECT  116.104 35.904 116.273 40.584 ;
     RECT  116.104 10.272 116.281 11.448 ;
     RECT  116.104 19.344 116.309 21.72 ;
     RECT  116.104 33.6 116.309 34.728 ;
     RECT  116.104 6.096 116.381 6.168 ;
     RECT  116.309 20.4 116.381 21.72 ;
     RECT  116.309 33.6 116.381 34.488 ;
     RECT  116.273 22.752 116.417 23.688 ;
     RECT  116.273 35.904 116.489 40.488 ;
     RECT  116.381 20.4 116.561 21.192 ;
     RECT  116.243 29.52 116.597 30.792 ;
     RECT  116.104 12.48 116.627 13.608 ;
     RECT  116.281 10.272 116.633 10.824 ;
     RECT  116.309 19.344 116.633 19.368 ;
     RECT  116.104 25.68 116.669 25.8 ;
     RECT  116.104 5.088 116.675 5.112 ;
     RECT  116.489 39.216 116.705 40.488 ;
     RECT  116.597 29.52 116.777 29.64 ;
     RECT  116.633 10.752 116.813 10.824 ;
     RECT  116.104 16.848 116.813 18.024 ;
     RECT  116.597 30.672 116.849 30.792 ;
     RECT  116.417 23.28 116.921 23.688 ;
     RECT  116.165 14.832 116.957 15.768 ;
     RECT  116.104 8.976 117.029 9 ;
     RECT  116.561 21.168 117.029 21.192 ;
     RECT  116.104 27.024 117.029 27.768 ;
     RECT  116.705 39.216 117.029 39.912 ;
     RECT  116.104 7.2 117.1 7.656 ;
     RECT  116.381 33.6 117.173 33.624 ;
     RECT  116.813 16.944 117.245 18.024 ;
     RECT  116.104 2.976 117.308 3.96 ;
     RECT  116.627 12.48 117.353 12.504 ;
     RECT  116.627 13.584 117.353 13.608 ;
     RECT  116.921 23.328 117.353 23.688 ;
     RECT  116.243 32.304 117.353 32.328 ;
     RECT  117.308 2.592 117.395 3.96 ;
     RECT  117.395 3.12 117.417 3.96 ;
     RECT  116.849 30.672 117.461 30.696 ;
     RECT  117.417 3.12 117.497 3.144 ;
     RECT  117.245 16.944 117.497 17.736 ;
     RECT  117.029 27.024 117.569 27.048 ;
     RECT  116.489 35.904 117.569 37.608 ;
     RECT  116.813 10.8 117.605 10.824 ;
     RECT  117.569 37.008 117.641 37.608 ;
     RECT  117.497 16.944 117.677 16.968 ;
     RECT  116.381 6.144 117.713 6.168 ;
     RECT  117.1 7.632 117.713 7.656 ;
     RECT  116.957 15.744 117.713 15.768 ;
     RECT  116.669 25.68 117.713 25.704 ;
     RECT  117.241 29.04 117.713 29.064 ;
     RECT  117.569 35.904 117.713 35.928 ;
     RECT  117.641 37.584 117.713 37.608 ;
     RECT  117.353 23.328 117.749 23.352 ;
     RECT  119.653 20.016 120.265 20.136 ;
     RECT  120.265 19.92 120.924 20.136 ;
    LAYER M5 ;
     RECT  102.864 0.016 108.936 0.085 ;
     RECT  13.008 0.016 19.08 0.227 ;
     RECT  102.864 0.085 109.416 0.275 ;
     RECT  70.608 0.016 76.68 0.371 ;
     RECT  102.864 0.275 108.84 0.419 ;
     RECT  42.192 0.016 48.264 0.563 ;
     RECT  102.864 0.419 108.792 0.563 ;
     RECT  42.384 0.563 48.072 0.659 ;
     RECT  70.608 0.371 76.584 0.707 ;
     RECT  13.104 0.227 19.08 1.763 ;
     RECT  42.384 0.659 45.48 1.763 ;
     RECT  70.608 0.707 73.848 1.763 ;
     RECT  42.576 1.763 45.48 1.811 ;
     RECT  42.672 1.811 45.48 1.859 ;
     RECT  13.2 1.763 19.08 2.099 ;
     RECT  43.44 1.859 45.48 2.137 ;
     RECT  46.512 0.659 48.072 2.137 ;
     RECT  2.4 2.137 2.52 2.151 ;
     RECT  7.8 2.137 7.92 2.151 ;
     RECT  24 2.137 24.12 2.151 ;
     RECT  29.4 2.137 29.52 2.151 ;
     RECT  34.8 2.137 34.92 2.151 ;
     RECT  40.2 2.137 40.32 2.151 ;
     RECT  51 2.137 51.12 2.151 ;
     RECT  56.4 2.137 56.52 2.151 ;
     RECT  61.8 2.137 61.92 2.151 ;
     RECT  67.2 2.137 67.32 2.151 ;
     RECT  78 2.137 78.12 2.151 ;
     RECT  83.4 2.137 83.52 2.151 ;
     RECT  88.8 2.137 88.92 2.151 ;
     RECT  94.2 2.137 94.32 2.151 ;
     RECT  99.6 2.137 99.72 2.151 ;
     RECT  110.4 2.137 110.52 2.151 ;
     RECT  115.8 2.137 115.92 2.151 ;
     RECT  16.368 2.099 19.08 2.197 ;
     RECT  51 2.151 51.312 2.197 ;
     RECT  2.4 2.151 2.712 2.245 ;
     RECT  40.2 2.151 40.512 2.245 ;
     RECT  61.8 2.151 62.112 2.245 ;
     RECT  67.2 2.151 67.512 2.245 ;
     RECT  88.8 2.151 89.112 2.245 ;
     RECT  13.2 2.099 15.24 2.291 ;
     RECT  103.152 0.563 105.864 2.339 ;
     RECT  104.784 2.339 105.768 2.387 ;
     RECT  61.344 2.245 62.112 2.629 ;
     RECT  99.6 2.151 99.912 2.773 ;
     RECT  43.44 2.137 48.072 2.819 ;
     RECT  110.4 2.151 110.712 2.821 ;
     RECT  115.8 2.151 116.112 2.821 ;
     RECT  4.8 2.245 4.824 2.869 ;
     RECT  13.2 2.291 14.952 2.869 ;
     RECT  78 2.151 78.312 2.869 ;
     RECT  79.584 2.773 79.608 2.869 ;
     RECT  50.88 2.197 51.312 2.915 ;
     RECT  78 2.869 79.608 2.915 ;
     RECT  96.48 2.197 96.504 2.915 ;
     RECT  61.344 2.629 62.616 3.107 ;
     RECT  101.376 2.773 101.4 3.107 ;
     RECT  64.416 2.245 64.44 3.109 ;
     RECT  103.152 2.339 103.608 3.301 ;
     RECT  2.4 2.245 3.384 3.347 ;
     RECT  4.8 2.869 4.92 3.395 ;
     RECT  24 2.151 24.312 3.397 ;
     RECT  34.8 2.151 35.112 3.397 ;
     RECT  56.4 2.151 56.712 3.397 ;
     RECT  12.48 2.869 14.952 3.443 ;
     RECT  61.536 3.107 62.616 3.443 ;
     RECT  63.792 3.109 64.44 3.443 ;
     RECT  68.976 2.773 69 3.443 ;
     RECT  10.32 2.821 10.344 3.539 ;
     RECT  113.04 2.581 113.064 3.539 ;
     RECT  43.824 2.819 48.072 3.637 ;
     RECT  16.368 2.197 19.368 3.731 ;
     RECT  67.2 2.245 67.608 3.875 ;
     RECT  7.8 2.151 8.112 3.925 ;
     RECT  20.544 3.397 20.568 3.925 ;
     RECT  31.728 3.061 31.752 3.925 ;
     RECT  94.2 2.151 94.512 3.925 ;
     RECT  115.152 2.821 116.112 3.925 ;
     RECT  117.36 2.581 117.384 3.971 ;
     RECT  27.6 3.925 27.624 3.973 ;
     RECT  61.536 3.443 62.112 4.019 ;
     RECT  88.8 2.245 89.4 4.019 ;
     RECT  30.864 3.925 31.752 4.115 ;
     RECT  39.456 2.245 40.512 4.115 ;
     RECT  110.4 2.821 110.808 4.259 ;
     RECT  23.664 3.397 24.312 4.355 ;
     RECT  102.672 3.301 103.608 4.357 ;
     RECT  91.152 2.245 91.176 4.403 ;
     RECT  58.704 3.925 58.728 4.451 ;
     RECT  102.672 4.357 103.656 4.595 ;
     RECT  41.616 3.829 41.64 4.645 ;
     RECT  106.944 0.563 108.792 4.645 ;
     RECT  20.544 3.925 21.336 4.691 ;
     RECT  26.256 3.397 26.28 4.691 ;
     RECT  43.824 3.637 48.216 4.837 ;
     RECT  4.8 3.395 4.824 4.883 ;
     RECT  6.864 3.925 8.112 4.981 ;
     RECT  24 4.355 24.312 5.077 ;
     RECT  27.6 3.973 28.056 5.077 ;
     RECT  115.104 3.925 116.112 5.077 ;
     RECT  6.864 4.981 8.232 5.171 ;
     RECT  11.376 4.501 11.4 5.171 ;
     RECT  103.152 4.595 103.656 5.173 ;
     RECT  104.88 2.387 105.768 5.173 ;
     RECT  22.56 2.821 22.584 5.219 ;
     RECT  113.232 4.645 113.256 5.219 ;
     RECT  78 2.915 79.224 5.315 ;
     RECT  27.552 5.077 28.056 5.459 ;
     RECT  49.968 4.501 49.992 5.459 ;
     RECT  64.992 4.453 65.016 5.459 ;
     RECT  61.8 4.019 62.112 5.701 ;
     RECT  24 5.077 24.792 5.747 ;
     RECT  27.552 5.459 27.624 5.747 ;
     RECT  34.224 3.397 35.112 5.747 ;
     RECT  41.616 4.645 42.552 5.747 ;
     RECT  86.544 3.205 86.568 5.747 ;
     RECT  61.8 5.701 62.232 5.843 ;
     RECT  112.176 5.701 112.2 5.843 ;
     RECT  93.456 3.925 94.512 5.941 ;
     RECT  93.168 5.941 94.512 5.987 ;
     RECT  7.8 5.171 8.232 5.989 ;
     RECT  115.104 5.077 116.664 6.179 ;
     RECT  12.672 3.443 14.952 6.229 ;
     RECT  55.68 3.397 56.712 6.229 ;
     RECT  81.888 5.077 81.912 6.229 ;
     RECT  81.504 6.229 81.912 6.275 ;
     RECT  2.4 3.347 3.192 6.469 ;
     RECT  53.04 5.365 53.064 6.563 ;
     RECT  37.056 6.277 37.08 6.611 ;
     RECT  103.152 5.173 105.768 6.803 ;
     RECT  110.4 4.259 110.712 6.805 ;
     RECT  33.024 4.501 33.048 6.851 ;
     RECT  103.152 6.803 103.656 6.949 ;
     RECT  110.4 6.805 110.904 6.949 ;
     RECT  68.784 6.517 68.808 7.043 ;
     RECT  12 6.229 14.952 7.091 ;
     RECT  83.4 2.151 83.712 7.189 ;
     RECT  115.104 6.179 116.112 7.189 ;
     RECT  40.2 4.115 40.512 7.333 ;
     RECT  41.616 5.747 41.64 7.333 ;
     RECT  34.272 5.747 35.112 7.381 ;
     RECT  61.8 5.843 62.112 7.381 ;
     RECT  63.792 3.443 63.816 7.381 ;
     RECT  70.896 1.763 73.848 7.381 ;
     RECT  74.832 0.707 76.584 7.381 ;
     RECT  83.4 7.189 84.696 7.381 ;
     RECT  2.4 6.469 3.24 7.619 ;
     RECT  81.504 6.275 81.528 7.619 ;
     RECT  43.824 4.837 48.984 7.667 ;
     RECT  115.104 7.189 117.048 7.667 ;
     RECT  78 5.315 78.936 7.765 ;
     RECT  22.224 7.333 22.248 7.861 ;
     RECT  93.168 5.987 93.192 7.861 ;
     RECT  94.2 5.987 94.512 7.861 ;
     RECT  93.168 7.861 94.512 7.907 ;
     RECT  29.4 2.151 29.712 7.909 ;
     RECT  30.864 4.115 30.888 7.909 ;
     RECT  102.288 6.949 103.656 7.957 ;
     RECT  20.544 4.691 20.568 8.003 ;
     RECT  55.536 6.229 56.712 8.003 ;
     RECT  83.232 7.381 84.696 8.003 ;
     RECT  22.224 7.861 22.584 8.051 ;
     RECT  12.288 7.091 14.952 8.147 ;
     RECT  40.2 7.333 41.64 8.147 ;
     RECT  34.272 7.381 36.024 8.149 ;
     RECT  98.592 6.661 98.616 8.149 ;
     RECT  34.272 8.149 36.504 8.195 ;
     RECT  61.8 7.381 63.816 8.195 ;
     RECT  98.112 8.149 98.616 8.195 ;
     RECT  102.288 7.957 103.896 8.195 ;
     RECT  56.4 8.003 56.712 8.341 ;
     RECT  58.128 8.005 58.152 8.341 ;
     RECT  64.944 7.381 64.968 8.435 ;
     RECT  99.6 2.773 100.008 8.437 ;
     RECT  27.6 5.747 27.624 8.485 ;
     RECT  86.496 6.229 86.52 8.485 ;
     RECT  27.36 8.485 27.624 8.531 ;
     RECT  36.48 8.195 36.504 8.533 ;
     RECT  29.4 7.909 30.888 8.579 ;
     RECT  43.824 7.667 48.6 8.579 ;
     RECT  103.152 8.195 103.896 8.579 ;
     RECT  34.272 8.195 35.112 8.675 ;
     RECT  99.6 8.437 100.056 8.725 ;
     RECT  88.8 4.019 89.112 8.821 ;
     RECT  70.896 7.381 76.584 8.867 ;
     RECT  41.616 8.147 41.64 8.917 ;
     RECT  41.616 8.917 42.168 8.963 ;
     RECT  52.704 7.333 52.728 8.963 ;
     RECT  56.4 8.341 58.152 9.011 ;
     RECT  98.112 8.195 98.136 9.011 ;
     RECT  115.104 7.667 116.856 9.011 ;
     RECT  103.392 8.579 103.896 9.059 ;
     RECT  5.952 8.437 5.976 9.061 ;
     RECT  27.36 8.531 27.384 9.061 ;
     RECT  42.144 8.963 42.168 9.061 ;
     RECT  29.4 8.579 29.976 9.107 ;
     RECT  69.84 4.885 69.864 9.155 ;
     RECT  42.144 9.061 42.36 9.253 ;
     RECT  86.496 8.485 86.664 9.253 ;
     RECT  66.096 8.197 66.12 9.299 ;
     RECT  85.872 9.253 86.664 9.299 ;
     RECT  22.56 8.051 22.584 9.349 ;
     RECT  115.104 9.011 116.112 9.349 ;
     RECT  34.8 8.675 35.112 9.493 ;
     RECT  36.48 8.533 36.6 9.493 ;
     RECT  2.4 7.619 2.712 9.589 ;
     RECT  3.936 8.245 3.96 9.589 ;
     RECT  2.4 9.589 3.96 9.635 ;
     RECT  67.2 3.875 67.512 9.637 ;
     RECT  78 7.765 79.224 9.637 ;
     RECT  63.792 8.195 63.816 9.731 ;
     RECT  88.512 8.821 89.112 9.731 ;
     RECT  114.192 9.349 116.112 9.827 ;
     RECT  106.848 4.645 108.792 9.875 ;
     RECT  5.664 9.061 5.976 9.877 ;
     RECT  70.896 8.867 73.848 9.925 ;
     RECT  12.432 8.147 14.952 10.069 ;
     RECT  16.368 3.731 19.08 10.069 ;
     RECT  5.568 9.877 5.976 10.117 ;
     RECT  115.8 9.827 116.112 10.261 ;
     RECT  5.136 10.117 5.976 10.307 ;
     RECT  20.112 8.533 20.136 10.307 ;
     RECT  43.824 8.579 44.232 10.307 ;
     RECT  56.4 9.011 57.24 10.307 ;
     RECT  85.872 9.299 85.896 10.307 ;
     RECT  34.8 9.493 36.6 10.355 ;
     RECT  42.144 9.253 42.408 10.355 ;
     RECT  56.4 10.307 56.808 10.355 ;
     RECT  114.192 9.827 114.216 10.355 ;
     RECT  99.6 8.725 100.824 10.451 ;
     RECT  66.96 9.637 67.512 10.499 ;
     RECT  22.56 9.349 22.776 10.597 ;
     RECT  12.432 10.069 19.08 10.883 ;
     RECT  21.648 10.597 22.776 10.883 ;
     RECT  26.88 9.061 27.384 10.883 ;
     RECT  45.216 8.579 48.6 10.883 ;
     RECT  58.272 9.349 58.296 10.883 ;
     RECT  78 9.637 79.992 10.883 ;
     RECT  7.8 5.989 8.568 10.885 ;
     RECT  78 10.883 78.408 10.931 ;
     RECT  53.472 10.213 53.496 11.075 ;
     RECT  29.4 9.107 29.712 11.173 ;
     RECT  93.264 7.907 94.512 11.221 ;
     RECT  93.264 11.221 94.632 11.267 ;
     RECT  70.656 9.925 73.848 11.411 ;
     RECT  12.432 10.883 15.336 11.459 ;
     RECT  21.648 10.883 21.672 11.459 ;
     RECT  26.88 10.883 26.904 11.459 ;
     RECT  60.192 10.165 60.216 11.459 ;
     RECT  79.968 10.883 79.992 11.459 ;
     RECT  83.232 8.003 84.312 11.459 ;
     RECT  96.384 10.453 96.408 11.459 ;
     RECT  110.4 6.949 111.768 11.459 ;
     RECT  115.8 10.261 116.232 11.459 ;
     RECT  5.136 10.307 5.592 11.509 ;
     RECT  4.944 11.509 5.592 11.555 ;
     RECT  14.928 11.459 15.336 11.651 ;
     RECT  7.8 10.885 8.616 11.699 ;
     RECT  24 5.747 24.312 11.701 ;
     RECT  22.752 10.883 22.776 11.747 ;
     RECT  42.144 10.355 42.36 11.891 ;
     RECT  16.368 10.883 19.08 11.941 ;
     RECT  20.256 11.701 20.28 11.941 ;
     RECT  78 10.931 78.312 11.941 ;
     RECT  26.736 11.653 26.76 11.987 ;
     RECT  93.504 11.267 94.632 12.085 ;
     RECT  66.192 11.941 66.216 12.277 ;
     RECT  67.2 10.499 67.512 12.277 ;
     RECT  66.192 12.277 67.512 12.323 ;
     RECT  88.8 9.731 89.112 12.373 ;
     RECT  78 11.941 78.984 12.517 ;
     RECT  106.944 9.875 108.792 12.517 ;
     RECT  36.576 10.355 36.6 12.563 ;
     RECT  91.824 11.941 91.848 12.563 ;
     RECT  93.504 12.085 95.16 12.563 ;
     RECT  104.88 6.803 105.768 12.563 ;
     RECT  83.232 11.459 83.712 12.709 ;
     RECT  12.432 11.459 13.608 12.757 ;
     RECT  10.56 8.485 10.584 12.803 ;
     RECT  103.392 9.059 103.656 12.901 ;
     RECT  78 12.517 79.8 13.043 ;
     RECT  42.192 11.891 42.36 13.045 ;
     RECT  81.216 11.941 81.24 13.045 ;
     RECT  82.32 12.709 83.712 13.045 ;
     RECT  88.032 12.373 89.112 13.091 ;
     RECT  115.8 11.459 116.112 13.093 ;
     RECT  52.752 12.037 52.776 13.139 ;
     RECT  78 13.043 78.696 13.139 ;
     RECT  81.216 13.045 83.712 13.139 ;
     RECT  102.576 12.901 103.656 13.139 ;
     RECT  23.76 11.701 24.312 13.331 ;
     RECT  94.2 12.563 95.16 13.331 ;
     RECT  106.944 12.517 109.128 13.331 ;
     RECT  12.048 12.757 13.608 13.619 ;
     RECT  81.792 13.139 83.712 13.619 ;
     RECT  115.8 13.093 116.616 13.619 ;
     RECT  4.944 11.555 4.968 13.621 ;
     RECT  104.88 12.563 105.312 13.621 ;
     RECT  7.8 11.699 8.232 13.667 ;
     RECT  49.104 11.941 49.128 13.667 ;
     RECT  14.928 11.651 14.952 13.715 ;
     RECT  66.624 12.323 67.512 13.715 ;
     RECT  103.392 13.139 103.656 13.715 ;
     RECT  32.688 12.517 32.712 13.763 ;
     RECT  37.056 12.613 37.08 13.859 ;
     RECT  42.192 13.045 42.408 13.907 ;
     RECT  51 2.915 51.312 14.005 ;
     RECT  74.832 8.867 76.584 14.101 ;
     RECT  78 13.139 78.312 14.101 ;
     RECT  99.6 10.451 100.296 14.101 ;
     RECT  7.8 13.667 8.112 14.149 ;
     RECT  12.096 13.619 13.608 14.197 ;
     RECT  42.336 13.907 42.408 14.197 ;
     RECT  114.192 13.621 114.216 14.197 ;
     RECT  115.8 13.619 116.112 14.197 ;
     RECT  70.896 11.411 73.848 14.291 ;
     RECT  21.696 13.573 21.72 14.339 ;
     RECT  88.8 13.091 89.112 14.437 ;
     RECT  79.776 13.043 79.8 14.485 ;
     RECT  81.792 13.619 81.816 14.531 ;
     RECT  84.96 14.149 84.984 14.533 ;
     RECT  110.4 11.459 110.712 14.629 ;
     RECT  111.744 11.459 111.768 14.629 ;
     RECT  79.536 14.485 79.8 14.675 ;
     RECT  50.832 14.005 51.312 14.723 ;
     RECT  28.32 14.533 28.344 14.725 ;
     RECT  74.832 14.101 78.312 14.771 ;
     RECT  16.368 11.941 20.28 14.773 ;
     RECT  16.368 14.773 20.712 14.819 ;
     RECT  12.096 14.197 14.616 14.821 ;
     RECT  12 14.821 14.616 14.867 ;
     RECT  28.224 14.725 28.344 14.867 ;
     RECT  29.4 11.173 29.928 14.867 ;
     RECT  57.84 14.197 57.864 14.867 ;
     RECT  70.992 14.291 73.848 14.867 ;
     RECT  34.8 10.355 35.112 14.917 ;
     RECT  40.2 8.147 40.512 14.917 ;
     RECT  36.48 14.773 36.504 14.963 ;
     RECT  42.336 14.197 42.504 15.013 ;
     RECT  85.968 14.485 85.992 15.061 ;
     RECT  104.88 13.621 105.672 15.061 ;
     RECT  44.208 10.307 44.232 15.157 ;
     RECT  45.216 10.883 48.072 15.157 ;
     RECT  34.8 14.917 35.208 15.253 ;
     RECT  12 14.867 12.12 15.301 ;
     RECT  94.2 13.331 94.512 15.301 ;
     RECT  64.848 13.621 64.872 15.395 ;
     RECT  56.4 10.355 56.712 15.397 ;
     RECT  4.896 13.621 4.968 15.443 ;
     RECT  71.664 14.867 73.848 15.443 ;
     RECT  112.896 14.773 112.92 15.443 ;
     RECT  106.944 13.331 108.792 15.541 ;
     RECT  84.912 14.533 84.984 15.637 ;
     RECT  85.968 15.061 86.376 15.637 ;
     RECT  28.224 14.867 28.248 15.683 ;
     RECT  10.128 13.045 10.152 15.685 ;
     RECT  11.712 15.301 12.12 15.685 ;
     RECT  16.368 14.819 19.128 15.781 ;
     RECT  55.536 15.397 56.712 15.829 ;
     RECT  42.192 15.013 42.504 15.877 ;
     RECT  67.2 13.715 67.512 15.877 ;
     RECT  10.128 15.685 12.12 15.971 ;
     RECT  93.456 15.301 94.512 15.973 ;
     RECT  10.128 15.971 10.824 16.019 ;
     RECT  59.712 15.349 59.736 16.019 ;
     RECT  93.456 15.973 94.872 16.019 ;
     RECT  97.68 15.061 97.704 16.019 ;
     RECT  110.4 14.629 111.768 16.019 ;
     RECT  4.896 15.443 4.92 16.259 ;
     RECT  42.192 15.877 42.744 16.259 ;
     RECT  84.912 15.637 86.376 16.259 ;
     RECT  24 13.331 24.312 16.261 ;
     RECT  25.632 15.685 25.656 16.261 ;
     RECT  7.344 14.149 8.112 16.405 ;
     RECT  16.368 15.781 19.224 16.405 ;
     RECT  103.536 13.715 103.656 16.405 ;
     RECT  106.944 15.541 108.888 16.405 ;
     RECT  110.4 16.019 110.712 16.405 ;
     RECT  25.488 16.261 25.656 16.453 ;
     RECT  20.256 14.819 20.712 16.499 ;
     RECT  27.072 15.973 27.096 16.499 ;
     RECT  54.432 11.365 54.456 16.499 ;
     RECT  99.6 14.101 101.16 16.499 ;
     RECT  114.192 14.197 116.112 16.499 ;
     RECT  74.832 14.771 76.584 16.501 ;
     RECT  78 14.771 78.312 16.501 ;
     RECT  49.152 14.197 49.176 16.547 ;
     RECT  101.136 16.499 101.16 16.547 ;
     RECT  67.2 15.877 67.656 16.549 ;
     RECT  34.176 15.253 35.208 16.595 ;
     RECT  40.08 14.917 40.512 16.595 ;
     RECT  55.536 15.829 57.528 16.595 ;
     RECT  71.856 15.443 73.848 16.595 ;
     RECT  103.248 16.405 103.656 16.643 ;
     RECT  2.4 9.635 3.672 16.789 ;
     RECT  2.4 16.789 3.96 16.835 ;
     RECT  42.624 16.259 42.744 16.835 ;
     RECT  106.944 16.405 110.712 16.835 ;
     RECT  7.2 16.405 8.112 16.885 ;
     RECT  44.208 15.157 48.072 16.933 ;
     RECT  51 14.723 51.312 16.933 ;
     RECT  24 16.261 24.504 16.981 ;
     RECT  25.488 16.453 25.8 16.981 ;
     RECT  32.16 16.501 32.184 16.981 ;
     RECT  79.536 14.675 79.56 17.027 ;
     RECT  44.208 16.933 49.128 17.075 ;
     RECT  13.2 14.867 14.04 17.077 ;
     RECT  72.384 16.595 73.848 17.077 ;
     RECT  74.832 16.501 78.312 17.077 ;
     RECT  92.352 15.637 92.376 17.077 ;
     RECT  5.136 16.981 5.16 17.123 ;
     RECT  7.2 16.885 9 17.123 ;
     RECT  42.624 16.835 42.648 17.123 ;
     RECT  44.208 17.075 49.032 17.171 ;
     RECT  92.352 17.077 92.904 17.219 ;
     RECT  72.384 17.077 78.312 17.411 ;
     RECT  99.6 16.499 99.912 17.605 ;
     RECT  104.88 15.061 105.72 17.605 ;
     RECT  106.944 16.835 108.792 17.605 ;
     RECT  10.128 16.019 10.152 17.651 ;
     RECT  24 16.981 25.8 17.651 ;
     RECT  72.432 17.411 78.312 17.651 ;
     RECT  13.2 17.077 14.232 17.653 ;
     RECT  39.072 15.157 39.096 17.699 ;
     RECT  44.208 17.171 48.072 17.699 ;
     RECT  64.8 15.445 64.824 17.699 ;
     RECT  115.152 16.499 116.112 17.699 ;
     RECT  72.432 17.651 76.584 17.747 ;
     RECT  50.112 16.933 51.312 17.891 ;
     RECT  13.2 17.653 14.424 17.989 ;
     RECT  61.8 8.195 62.112 18.037 ;
     RECT  15.792 16.405 19.224 18.131 ;
     RECT  12 15.971 12.12 18.227 ;
     RECT  96.912 17.605 96.936 18.419 ;
     RECT  98.64 17.605 99.912 18.419 ;
     RECT  29.4 14.867 29.88 18.421 ;
     RECT  3.936 16.835 3.96 18.467 ;
     RECT  67.2 16.549 68.376 18.467 ;
     RECT  72.432 17.747 73.848 18.565 ;
     RECT  63.792 17.605 63.816 18.707 ;
     RECT  90.576 17.173 90.6 18.707 ;
     RECT  2.4 16.835 2.712 18.709 ;
     RECT  85.728 16.259 85.752 18.709 ;
     RECT  99.6 18.419 99.912 18.709 ;
     RECT  5.04 18.661 5.064 18.757 ;
     RECT  24 17.651 25.512 18.757 ;
     RECT  56.4 16.595 57.528 18.757 ;
     RECT  103.536 16.643 103.656 18.757 ;
     RECT  7.2 17.123 8.808 18.803 ;
     RECT  20.256 16.499 20.28 18.803 ;
     RECT  94.2 16.019 94.872 18.805 ;
     RECT  61.584 18.037 62.112 18.851 ;
     RECT  71.904 18.565 73.848 18.851 ;
     RECT  101.568 17.077 101.592 18.851 ;
     RECT  111.744 16.019 111.768 18.947 ;
     RECT  24 18.757 26.232 18.995 ;
     RECT  31.872 16.981 32.184 18.995 ;
     RECT  99.6 18.709 100.536 18.995 ;
     RECT  12 18.227 12.024 19.043 ;
     RECT  94.2 18.805 95.832 19.045 ;
     RECT  104.88 17.605 108.792 19.283 ;
     RECT  42.96 18.181 42.984 19.331 ;
     RECT  4.992 18.757 5.064 19.379 ;
     RECT  49.248 18.181 49.272 19.379 ;
     RECT  85.584 18.709 85.752 19.379 ;
     RECT  13.2 17.989 14.664 19.427 ;
     RECT  29.4 18.421 30.072 19.427 ;
     RECT  55.968 18.757 57.528 19.427 ;
     RECT  115.68 17.699 116.112 19.427 ;
     RECT  25.488 18.995 26.232 19.475 ;
     RECT  7.2 18.803 8.112 19.477 ;
     RECT  85.728 19.379 85.752 19.669 ;
     RECT  67.2 18.467 67.608 19.765 ;
     RECT  110.4 16.835 110.712 19.765 ;
     RECT  2.4 18.709 2.808 20.003 ;
     RECT  32.16 18.995 32.184 20.003 ;
     RECT  70.08 17.029 70.104 20.003 ;
     RECT  85.728 19.669 85.8 20.003 ;
     RECT  104.88 19.283 105.72 20.003 ;
     RECT  58.656 19.381 58.68 20.051 ;
     RECT  24 18.995 24.312 20.053 ;
     RECT  51 17.891 51.312 20.053 ;
     RECT  79.584 17.077 79.608 20.053 ;
     RECT  34.176 16.595 35.112 20.099 ;
     RECT  94.08 19.045 95.832 20.147 ;
     RECT  79.44 20.053 79.608 20.149 ;
     RECT  50.736 20.053 51.312 20.195 ;
     RECT  10.08 19.909 10.104 20.339 ;
     RECT  44.256 17.699 48.072 20.339 ;
     RECT  102.576 18.757 103.656 20.387 ;
     RECT  7.056 19.477 8.112 20.389 ;
     RECT  40.2 16.595 40.512 20.485 ;
     RECT  4.992 19.379 5.016 20.579 ;
     RECT  6.528 20.389 8.112 20.579 ;
     RECT  13.2 19.427 14.232 20.579 ;
     RECT  54.096 19.765 54.12 20.579 ;
     RECT  67.2 19.765 68.184 20.579 ;
     RECT  79.44 20.149 80.04 20.579 ;
     RECT  88.8 14.437 89.304 20.579 ;
     RECT  94.2 20.147 95.832 20.579 ;
     RECT  99.6 18.995 100.296 20.579 ;
     RECT  106.944 19.283 108.792 20.579 ;
     RECT  110.4 19.765 110.808 20.579 ;
     RECT  113.472 17.029 113.496 20.579 ;
     RECT  7.68 20.579 8.112 20.627 ;
     RECT  25.488 19.475 25.656 20.627 ;
     RECT  56.4 19.427 57.528 20.627 ;
     RECT  88.8 20.579 89.112 20.677 ;
     RECT  94.2 20.579 95.736 20.723 ;
     RECT  6.528 20.579 6.552 20.915 ;
     RECT  50.88 20.195 51.312 21.107 ;
     RECT  91.728 19.333 91.752 21.107 ;
     RECT  95.712 20.723 95.736 21.107 ;
     RECT  97.152 19.909 97.176 21.107 ;
     RECT  23.664 20.053 24.312 21.155 ;
     RECT  25.632 20.627 25.656 21.155 ;
     RECT  28.368 20.293 28.392 21.155 ;
     RECT  40.2 20.485 40.728 21.155 ;
     RECT  85.776 20.003 85.8 21.155 ;
     RECT  80.016 20.579 80.04 21.203 ;
     RECT  60.096 20.485 60.12 21.251 ;
     RECT  56.4 20.627 57.048 21.395 ;
     RECT  72.6 18.851 73.848 21.397 ;
     RECT  74.832 17.747 76.584 21.397 ;
     RECT  72.6 21.397 76.584 21.539 ;
     RECT  34.8 20.099 35.112 21.541 ;
     RECT  40.2 21.155 40.512 21.589 ;
     RECT  56.4 21.395 56.712 21.589 ;
     RECT  54.048 21.205 54.072 21.635 ;
     RECT  7.8 20.627 8.112 21.637 ;
     RECT  45.216 20.339 48.072 21.637 ;
     RECT  78 17.651 78.312 21.637 ;
     RECT  107.04 20.579 108.792 21.637 ;
     RECT  56.304 21.589 56.712 21.731 ;
     RECT  40.08 21.589 40.512 22.117 ;
     RECT  51 21.107 51.312 22.165 ;
     RECT  44.88 21.637 48.072 22.259 ;
     RECT  31.872 20.437 31.896 22.499 ;
     RECT  44.88 22.259 46.056 22.499 ;
     RECT  88.656 20.677 89.112 22.499 ;
     RECT  106.992 21.637 108.792 22.499 ;
     RECT  47.472 22.259 48.072 22.501 ;
     RECT  21.072 22.165 21.096 22.643 ;
     RECT  112.656 21.925 112.68 22.739 ;
     RECT  34.032 21.541 35.112 22.741 ;
     RECT  72.6 21.539 73.848 22.741 ;
     RECT  74.832 21.539 76.584 22.741 ;
     RECT  88.8 22.499 89.112 22.741 ;
     RECT  94.2 20.723 94.512 22.741 ;
     RECT  7.8 21.637 8.376 22.787 ;
     RECT  29.4 19.427 29.712 22.789 ;
     RECT  47.472 22.501 48.888 22.835 ;
     RECT  50.64 22.165 51.312 22.979 ;
     RECT  0.144 21.445 0.168 23.123 ;
     RECT  33.456 22.741 35.112 23.125 ;
     RECT  42.144 23.077 42.168 23.173 ;
     RECT  11.376 22.213 11.4 23.315 ;
     RECT  6.24 23.173 6.264 23.317 ;
     RECT  63.648 21.589 63.672 23.317 ;
     RECT  99.6 20.579 99.912 23.365 ;
     RECT  72.6 22.741 76.584 23.411 ;
     RECT  81.888 22.165 81.912 23.411 ;
     RECT  94.2 22.741 95.16 23.411 ;
     RECT  39.408 22.117 40.512 23.555 ;
     RECT  47.616 22.835 48.888 23.557 ;
     RECT  107.04 22.499 108.792 23.557 ;
     RECT  33.456 23.125 36.072 23.605 ;
     RECT  42.144 23.173 42.888 23.699 ;
     RECT  74.832 23.411 76.584 23.845 ;
     RECT  77.616 21.637 78.312 23.845 ;
     RECT  14.88 22.741 14.904 23.893 ;
     RECT  56.4 21.731 56.712 23.893 ;
     RECT  63.648 23.317 63.912 23.939 ;
     RECT  74.832 23.845 78.312 23.941 ;
     RECT  42.864 23.699 42.888 23.987 ;
     RECT  71.424 23.893 71.448 24.085 ;
     RECT  72.6 23.411 73.848 24.085 ;
     RECT  51 22.979 51.312 24.133 ;
     RECT  5.424 23.317 6.264 24.179 ;
     RECT  88.8 22.741 89.208 24.181 ;
     RECT  103.536 20.387 103.656 24.277 ;
     RECT  58.992 23.845 59.016 24.421 ;
     RECT  83.232 13.619 83.712 24.421 ;
     RECT  56.256 23.893 56.712 24.467 ;
     RECT  27.888 22.741 27.912 24.469 ;
     RECT  29.28 22.789 29.712 24.469 ;
     RECT  61.8 18.851 62.112 24.469 ;
     RECT  63.648 23.939 63.672 24.469 ;
     RECT  74.832 23.941 78.696 24.515 ;
     RECT  2.4 20.003 2.712 24.517 ;
     RECT  47.616 23.557 49.608 24.659 ;
     RECT  67.2 20.579 67.512 24.661 ;
     RECT  71.424 24.085 73.848 24.709 ;
     RECT  74.832 24.515 78.312 24.709 ;
     RECT  81.888 24.469 81.912 24.805 ;
     RECT  27.888 24.469 29.712 24.853 ;
     RECT  71.424 24.709 78.312 24.899 ;
     RECT  2.4 24.517 3.192 24.947 ;
     RECT  67.104 24.661 67.512 25.045 ;
     RECT  113.232 22.741 113.256 25.045 ;
     RECT  20.4 23.029 20.424 25.091 ;
     RECT  85.728 22.741 85.752 25.093 ;
     RECT  14.544 23.893 14.904 25.139 ;
     RECT  53.904 24.133 54.12 25.139 ;
     RECT  80.928 24.805 81.912 25.139 ;
     RECT  85.536 25.093 85.752 25.139 ;
     RECT  101.472 24.469 101.496 25.139 ;
     RECT  106.368 23.557 108.792 25.139 ;
     RECT  53.904 25.139 53.928 25.187 ;
     RECT  63.552 24.469 63.672 25.187 ;
     RECT  50.88 24.133 51.312 25.189 ;
     RECT  83.136 24.421 83.712 25.189 ;
     RECT  33.456 23.605 36.12 25.235 ;
     RECT  80.928 25.139 81.528 25.235 ;
     RECT  57.696 23.317 57.72 25.427 ;
     RECT  36.096 25.235 36.12 25.523 ;
     RECT  38.592 24.469 38.616 25.571 ;
     RECT  61.68 24.469 62.112 25.571 ;
     RECT  88.8 24.181 89.4 25.571 ;
     RECT  13.2 20.579 13.512 25.621 ;
     RECT  44.064 23.893 44.088 25.621 ;
     RECT  103.2 24.277 103.656 25.667 ;
     RECT  104.88 20.003 105.312 25.669 ;
     RECT  10.608 24.517 10.632 25.715 ;
     RECT  43.296 25.621 44.088 25.715 ;
     RECT  96.72 24.901 96.744 25.715 ;
     RECT  113.184 25.045 113.256 25.763 ;
     RECT  5.424 24.179 5.448 25.861 ;
     RECT  40.08 23.555 40.512 25.861 ;
     RECT  71.424 24.899 76.632 25.861 ;
     RECT  5.136 25.861 5.448 25.907 ;
     RECT  99.6 23.365 100.008 25.957 ;
     RECT  49.968 25.189 51.312 26.197 ;
     RECT  67.104 25.045 67.944 26.197 ;
     RECT  27.648 24.853 29.712 26.243 ;
     RECT  31.248 24.133 31.272 26.243 ;
     RECT  87.408 25.429 87.432 26.243 ;
     RECT  6.672 25.045 6.696 26.291 ;
     RECT  88.8 25.571 89.208 26.341 ;
     RECT  88.704 26.341 89.208 26.387 ;
     RECT  110.4 20.579 110.712 26.389 ;
     RECT  88.704 26.387 89.112 26.531 ;
     RECT  103.536 25.667 103.656 26.581 ;
     RECT  104.832 25.669 105.312 26.581 ;
     RECT  83.04 25.189 83.712 26.627 ;
     RECT  24 21.155 24.312 26.629 ;
     RECT  49.968 26.197 51.72 26.675 ;
     RECT  94.2 23.411 94.68 26.677 ;
     RECT  115.8 19.427 116.112 26.677 ;
     RECT  2.4 24.947 2.712 26.725 ;
     RECT  92.208 22.741 92.232 26.725 ;
     RECT  50.88 26.675 51.72 26.819 ;
     RECT  67.104 26.197 68.328 26.819 ;
     RECT  71.28 25.861 76.632 26.819 ;
     RECT  56.4 24.467 56.712 26.917 ;
     RECT  110.4 26.389 111.096 26.917 ;
     RECT  2.4 26.725 3.624 27.059 ;
     RECT  40.08 25.861 41.208 27.059 ;
     RECT  43.296 25.715 43.32 27.061 ;
     RECT  106.368 25.139 106.392 27.061 ;
     RECT  107.472 25.139 108.792 27.061 ;
     RECT  106.368 27.061 108.792 27.107 ;
     RECT  12.528 25.621 13.512 27.109 ;
     RECT  80.496 27.061 80.52 27.109 ;
     RECT  81.504 25.235 81.528 27.109 ;
     RECT  14.88 25.139 14.904 27.157 ;
     RECT  47.616 24.659 48.888 27.157 ;
     RECT  40.08 27.059 40.512 27.203 ;
     RECT  11.616 27.109 13.512 27.205 ;
     RECT  14.832 27.157 14.904 27.205 ;
     RECT  94.2 26.677 95.352 27.205 ;
     RECT  71.424 26.819 76.632 27.251 ;
     RECT  57.744 25.621 57.768 27.253 ;
     RECT  58.848 24.421 59.016 27.253 ;
     RECT  29.4 26.243 29.712 27.301 ;
     RECT  45.216 22.499 46.056 27.301 ;
     RECT  98.016 26.725 98.04 27.347 ;
     RECT  33.456 25.235 35.112 27.349 ;
     RECT  61.8 25.571 62.112 27.349 ;
     RECT  63.648 25.187 63.672 27.349 ;
     RECT  67.104 26.819 67.944 27.349 ;
     RECT  20.448 26.581 20.472 27.443 ;
     RECT  85.536 25.139 85.56 27.587 ;
     RECT  60.768 25.861 60.792 27.637 ;
     RECT  60.48 27.637 60.792 27.683 ;
     RECT  99.216 25.957 100.008 27.683 ;
     RECT  24 26.629 24.552 27.731 ;
     RECT  115.152 26.677 116.112 27.733 ;
     RECT  113.232 25.763 113.256 27.779 ;
     RECT  5.136 25.907 5.16 27.781 ;
     RECT  99.504 27.683 100.008 27.781 ;
     RECT  103.536 26.581 105.312 27.781 ;
     RECT  21.6 22.741 21.624 27.875 ;
     RECT  53.52 26.485 53.544 27.875 ;
     RECT  16.368 18.131 19.224 27.877 ;
     RECT  42.96 27.061 43.32 27.877 ;
     RECT  33.072 27.349 35.112 27.923 ;
     RECT  66.576 27.349 67.944 27.923 ;
     RECT  80.496 27.109 81.528 27.923 ;
     RECT  94.08 27.205 95.352 27.923 ;
     RECT  110.4 26.917 111.768 27.923 ;
     RECT  45.024 27.301 46.056 27.971 ;
     RECT  92.208 26.725 92.952 27.971 ;
     RECT  11.616 27.205 14.904 28.115 ;
     RECT  31.92 27.301 31.944 28.115 ;
     RECT  29.4 27.301 30.12 28.163 ;
     RECT  33.552 27.923 35.112 28.163 ;
     RECT  66.576 27.923 67.848 28.163 ;
     RECT  38.448 26.629 38.472 28.403 ;
     RECT  92.208 27.971 92.232 28.405 ;
     RECT  36.24 26.725 36.264 28.451 ;
     RECT  61.8 27.349 63.672 28.451 ;
     RECT  92.016 28.405 92.232 28.451 ;
     RECT  54.72 27.061 54.744 28.453 ;
     RECT  55.968 26.917 56.712 28.453 ;
     RECT  106.56 27.107 108.792 28.499 ;
     RECT  40.2 27.203 40.512 28.501 ;
     RECT  63.648 28.451 63.672 28.501 ;
     RECT  94.08 27.923 94.512 28.547 ;
     RECT  111.744 27.923 111.768 28.547 ;
     RECT  9.504 27.349 9.528 28.643 ;
     RECT  42.96 27.877 43.368 28.643 ;
     RECT  107.28 28.499 108.792 28.643 ;
     RECT  54.72 28.453 56.712 28.739 ;
     RECT  83.184 26.627 83.712 28.739 ;
     RECT  57.744 27.253 59.016 28.789 ;
     RECT  6.384 27.925 6.408 28.931 ;
     RECT  57.744 28.789 59.256 28.931 ;
     RECT  4.56 27.781 5.16 28.979 ;
     RECT  11.616 28.115 14.376 28.979 ;
     RECT  50.88 26.819 51.312 29.029 ;
     RECT  97.488 28.309 97.512 29.029 ;
     RECT  12.528 28.979 14.376 29.075 ;
     RECT  72 27.251 76.632 29.077 ;
     RECT  77.616 24.899 78.312 29.077 ;
     RECT  5.136 28.979 5.16 29.123 ;
     RECT  63.648 28.501 64.44 29.123 ;
     RECT  70.752 28.645 70.776 29.123 ;
     RECT  102.624 27.781 105.312 29.123 ;
     RECT  55.296 28.739 56.712 29.219 ;
     RECT  85.248 28.117 85.272 29.219 ;
     RECT  99.504 27.781 100.056 29.219 ;
     RECT  16.08 27.877 19.224 29.221 ;
     RECT  50.88 29.029 51.864 29.221 ;
     RECT  40.2 28.501 41.736 29.363 ;
     RECT  50.736 29.221 51.864 29.363 ;
     RECT  40.2 29.363 40.512 29.365 ;
     RECT  72 29.077 78.312 29.459 ;
     RECT  72 29.459 76.728 29.557 ;
     RECT  27.648 26.243 27.672 29.603 ;
     RECT  2.4 27.059 2.712 29.605 ;
     RECT  67.2 28.163 67.848 29.605 ;
     RECT  71.808 29.557 76.728 29.651 ;
     RECT  57.84 28.931 59.256 29.699 ;
     RECT  71.808 29.651 75.144 29.699 ;
     RECT  102.624 29.123 103.656 29.699 ;
     RECT  71.808 29.699 74.856 29.747 ;
     RECT  41.712 29.363 41.736 29.795 ;
     RECT  92.016 28.451 92.04 29.795 ;
     RECT  7.8 22.787 8.112 29.941 ;
     RECT  60.48 27.683 60.504 29.941 ;
     RECT  61.8 28.451 62.112 29.941 ;
     RECT  12.528 29.075 13.512 29.989 ;
     RECT  16.08 29.221 19.608 30.035 ;
     RECT  96.96 29.029 97.512 30.083 ;
     RECT  94.2 28.547 94.512 30.133 ;
     RECT  29.4 28.163 29.88 30.275 ;
     RECT  50.88 29.363 51.864 30.275 ;
     RECT  80.496 27.923 81.48 30.275 ;
     RECT  97.488 30.083 97.512 30.275 ;
     RECT  110.4 27.923 110.712 30.325 ;
     RECT  63.648 29.123 63.672 30.563 ;
     RECT  110.064 30.325 110.712 30.563 ;
     RECT  56.256 29.219 56.712 30.565 ;
     RECT  57.84 29.699 59.016 30.565 ;
     RECT  56.256 30.565 59.016 30.611 ;
     RECT  24 27.731 24.312 30.661 ;
     RECT  50.88 30.275 51.312 30.661 ;
     RECT  34.8 28.163 35.112 30.709 ;
     RECT  2.4 29.605 2.904 30.803 ;
     RECT  7.8 29.941 8.376 30.803 ;
     RECT  12.432 29.989 13.512 30.803 ;
     RECT  50.784 30.661 51.312 30.803 ;
     RECT  107.952 28.643 108.792 30.803 ;
     RECT  16.08 30.035 19.224 30.851 ;
     RECT  56.256 30.611 57.288 30.851 ;
     RECT  111.696 30.181 111.72 30.851 ;
     RECT  115.008 27.733 116.112 30.851 ;
     RECT  58.704 30.611 59.016 30.853 ;
     RECT  60.48 29.941 62.112 30.899 ;
     RECT  107.952 30.803 108.744 30.899 ;
     RECT  53.568 29.605 53.592 31.043 ;
     RECT  61.056 30.899 62.112 31.043 ;
     RECT  12.528 30.803 13.512 31.139 ;
     RECT  94.2 30.133 94.632 31.139 ;
     RECT  45.216 27.971 46.056 31.141 ;
     RECT  58.704 30.853 59.112 31.331 ;
     RECT  47.616 27.157 49.368 31.379 ;
     RECT  80.496 30.275 80.52 31.525 ;
     RECT  42.96 28.643 42.984 31.669 ;
     RECT  115.8 30.851 116.112 31.669 ;
     RECT  10.512 29.221 10.536 31.717 ;
     RECT  39.696 29.365 40.512 31.765 ;
     RECT  50.88 30.803 51.312 31.765 ;
     RECT  104.832 29.123 105.312 31.765 ;
     RECT  34.8 30.709 35.208 31.811 ;
     RECT  17.712 30.851 19.224 31.813 ;
     RECT  99.504 29.219 99.912 31.861 ;
     RECT  114.528 31.765 114.552 31.861 ;
     RECT  115.8 31.669 116.232 31.861 ;
     RECT  17.712 31.813 19.32 31.955 ;
     RECT  38.736 31.765 40.512 31.955 ;
     RECT  58.752 31.331 59.112 31.955 ;
     RECT  101.232 31.189 101.256 31.955 ;
     RECT  71.808 29.747 73.848 32.101 ;
     RECT  45.216 31.141 46.536 32.195 ;
     RECT  110.4 30.563 110.712 32.197 ;
     RECT  103.536 29.699 103.656 32.245 ;
     RECT  39.696 31.955 40.512 32.293 ;
     RECT  114.528 31.861 116.232 32.339 ;
     RECT  94.2 31.139 94.512 32.341 ;
     RECT  5.04 32.389 5.064 32.437 ;
     RECT  17.904 31.955 19.32 32.437 ;
     RECT  47.616 31.379 48.888 32.437 ;
     RECT  50.304 31.765 51.312 32.437 ;
     RECT  61.8 31.043 62.112 32.437 ;
     RECT  83.232 28.739 83.712 32.437 ;
     RECT  86.544 27.877 86.568 32.437 ;
     RECT  106.8 30.181 106.824 32.437 ;
     RECT  107.952 30.899 108.456 32.437 ;
     RECT  114.528 32.339 116.112 32.483 ;
     RECT  47.616 32.437 51.312 32.531 ;
     RECT  56.4 30.851 57.288 32.531 ;
     RECT  66.048 31.909 66.072 32.531 ;
     RECT  71.28 32.101 73.848 32.531 ;
     RECT  48.48 32.531 51.312 32.579 ;
     RECT  42.192 31.669 42.984 32.723 ;
     RECT  56.4 32.531 56.952 32.771 ;
     RECT  104.832 31.765 105.576 32.771 ;
     RECT  10.512 31.717 10.92 32.773 ;
     RECT  9.552 32.773 10.92 32.867 ;
     RECT  71.28 32.531 71.304 32.915 ;
     RECT  4.368 32.437 5.064 32.917 ;
     RECT  106.8 32.437 108.456 32.917 ;
     RECT  106.608 32.917 108.456 32.963 ;
     RECT  110.4 32.197 111.48 32.963 ;
     RECT  112.752 32.197 112.776 33.011 ;
     RECT  16.08 30.851 16.392 33.013 ;
     RECT  29.4 30.275 29.712 33.013 ;
     RECT  80.496 31.525 80.904 33.013 ;
     RECT  107.76 32.963 108.456 33.013 ;
     RECT  107.76 33.013 108.936 33.059 ;
     RECT  94.08 32.341 94.512 33.061 ;
     RECT  99.504 31.861 100.008 33.061 ;
     RECT  82.608 32.437 83.712 33.107 ;
     RECT  102.576 32.245 103.656 33.107 ;
     RECT  80.496 33.013 80.952 33.109 ;
     RECT  4.368 32.917 5.16 33.299 ;
     RECT  9.552 32.867 9.576 33.299 ;
     RECT  76.56 29.651 76.728 33.347 ;
     RECT  72.6 32.531 73.848 33.349 ;
     RECT  74.832 29.747 74.856 33.349 ;
     RECT  34.8 31.811 35.112 33.397 ;
     RECT  92.976 32.437 93 33.443 ;
     RECT  48.48 32.579 49.608 33.491 ;
     RECT  13.104 31.139 13.512 33.493 ;
     RECT  115.104 32.483 116.112 33.493 ;
     RECT  13.104 33.493 13.656 33.539 ;
     RECT  48.624 33.491 49.608 33.539 ;
     RECT  10.8 32.867 10.92 33.541 ;
     RECT  99.456 33.061 100.008 33.541 ;
     RECT  17.904 32.437 19.8 33.587 ;
     RECT  99.168 33.541 100.008 33.587 ;
     RECT  13.2 33.539 13.656 33.589 ;
     RECT  15.84 33.013 16.392 33.589 ;
     RECT  42.96 32.723 42.984 33.589 ;
     RECT  77.904 29.459 78.312 33.589 ;
     RECT  17.904 33.587 19.224 33.683 ;
     RECT  33.552 28.163 33.576 33.683 ;
     RECT  39.696 32.293 40.824 33.683 ;
     RECT  61.2 32.437 62.112 33.683 ;
     RECT  80.496 33.109 81.048 33.683 ;
     RECT  107.952 33.059 108.936 33.683 ;
     RECT  55.248 32.533 55.272 33.829 ;
     RECT  56.4 32.771 56.904 33.829 ;
     RECT  27.6 32.869 27.624 33.875 ;
     RECT  77.904 33.589 79.224 33.925 ;
     RECT  80.496 33.683 80.52 33.925 ;
     RECT  55.248 33.829 56.904 33.973 ;
     RECT  23.76 30.661 24.312 34.019 ;
     RECT  48.864 33.539 49.608 34.067 ;
     RECT  15.84 33.589 16.44 34.115 ;
     RECT  77.904 33.925 80.52 34.115 ;
     RECT  13.2 33.589 14.232 34.211 ;
     RECT  38.448 33.013 38.472 34.213 ;
     RECT  104.832 32.771 105.528 34.213 ;
     RECT  106.608 32.963 106.632 34.213 ;
     RECT  72.6 33.349 74.856 34.259 ;
     RECT  5.04 33.299 5.16 34.309 ;
     RECT  5.04 34.309 5.448 34.355 ;
     RECT  88.8 26.531 89.112 34.453 ;
     RECT  86.544 32.437 87.144 34.499 ;
     RECT  78 34.115 80.52 34.595 ;
     RECT  79.776 34.595 80.52 34.643 ;
     RECT  50.88 32.579 51.312 34.693 ;
     RECT  74.832 34.259 74.856 34.693 ;
     RECT  76.56 33.347 76.584 34.693 ;
     RECT  54.288 33.973 56.904 34.741 ;
     RECT  61.8 33.683 62.112 34.741 ;
     RECT  65.568 33.445 65.592 34.741 ;
     RECT  65.568 34.741 66.072 34.787 ;
     RECT  104.832 34.213 106.632 34.787 ;
     RECT  18.288 33.683 19.224 34.789 ;
     RECT  110.4 32.963 110.712 34.789 ;
     RECT  74.832 34.693 76.584 34.835 ;
     RECT  107.952 33.683 108.456 34.835 ;
     RECT  109.536 34.789 110.712 34.885 ;
     RECT  38.448 34.213 38.808 34.931 ;
     RECT  45.216 32.195 46.056 34.933 ;
     RECT  109.536 34.885 110.952 34.979 ;
     RECT  109.68 34.979 110.952 35.123 ;
     RECT  50.88 34.693 51.816 35.269 ;
     RECT  50.832 35.269 51.816 35.315 ;
     RECT  83.232 33.107 83.712 35.317 ;
     RECT  34.8 33.397 35.496 35.363 ;
     RECT  61.344 34.741 62.112 35.363 ;
     RECT  42.96 33.589 43.32 35.365 ;
     RECT  38.784 34.931 38.808 35.411 ;
     RECT  42.624 35.365 43.32 35.411 ;
     RECT  69.12 34.501 69.144 35.411 ;
     RECT  99.168 33.587 99.912 35.411 ;
     RECT  63.552 34.741 63.576 35.461 ;
     RECT  74.832 34.835 75.72 35.507 ;
     RECT  58.944 31.955 59.112 35.509 ;
     RECT  54.288 34.741 57.72 35.555 ;
     RECT  18.288 34.789 19.32 35.605 ;
     RECT  80.496 34.643 80.52 35.605 ;
     RECT  82.08 35.461 82.104 35.605 ;
     RECT  66.048 34.787 66.072 35.701 ;
     RECT  66.048 35.701 66.168 35.747 ;
     RECT  55.536 35.555 57.72 35.843 ;
     RECT  37.296 31.045 37.32 35.845 ;
     RECT  37.104 35.845 37.32 35.891 ;
     RECT  48.864 34.067 48.888 35.893 ;
     RECT  50.832 35.315 51.312 35.893 ;
     RECT  16.368 34.115 16.44 35.939 ;
     RECT  58.944 35.509 59.256 35.939 ;
     RECT  63.552 35.461 63.96 35.939 ;
     RECT  72.6 34.259 73.848 35.939 ;
     RECT  74.832 35.507 74.856 35.939 ;
     RECT  108.432 34.835 108.456 35.939 ;
     RECT  110.4 35.123 110.952 35.939 ;
     RECT  28.704 33.013 29.712 35.941 ;
     RECT  83.088 35.317 83.712 36.035 ;
     RECT  78 34.595 78.408 36.037 ;
     RECT  88.704 34.453 89.112 36.085 ;
     RECT  97.968 35.461 97.992 36.373 ;
     RECT  97.056 36.373 97.992 36.419 ;
     RECT  7.8 30.803 8.112 36.421 ;
     RECT  80.496 35.605 82.104 36.421 ;
     RECT  88.32 36.085 89.112 36.421 ;
     RECT  93.984 33.061 94.512 36.469 ;
     RECT  100.896 35.317 100.92 36.563 ;
     RECT  103.296 33.107 103.656 36.565 ;
     RECT  50.688 35.893 51.312 36.659 ;
     RECT  66.144 35.747 66.168 36.659 ;
     RECT  110.4 35.939 110.856 36.851 ;
     RECT  28.56 35.941 29.712 36.853 ;
     RECT  50.832 36.659 51.312 36.899 ;
     RECT  104.832 34.787 105.432 36.947 ;
     RECT  7.68 36.421 8.112 36.997 ;
     RECT  72.6 35.939 73.32 36.997 ;
     RECT  86.64 34.499 87.144 36.997 ;
     RECT  5.136 34.355 5.448 37.043 ;
     RECT  18.288 35.605 19.8 37.043 ;
     RECT  39.024 36.373 39.048 37.043 ;
     RECT  104.832 36.947 105.312 37.043 ;
     RECT  106.608 34.787 106.632 37.043 ;
     RECT  2.4 30.803 2.712 37.045 ;
     RECT  37.104 35.891 37.128 37.045 ;
     RECT  86.592 36.997 87.144 37.045 ;
     RECT  16.368 35.939 16.392 37.091 ;
     RECT  18.288 37.043 19.32 37.091 ;
     RECT  40.2 33.683 40.824 37.091 ;
     RECT  48.864 35.893 49.512 37.091 ;
     RECT  59.232 35.939 59.256 37.091 ;
     RECT  72.48 36.997 73.32 37.091 ;
     RECT  85.968 37.045 87.144 37.091 ;
     RECT  88.32 36.421 89.208 37.091 ;
     RECT  97.056 36.419 97.08 37.139 ;
     RECT  112.464 36.517 112.488 37.187 ;
     RECT  91.2 36.421 91.224 37.379 ;
     RECT  103.008 36.565 103.656 37.379 ;
     RECT  13.2 34.211 13.656 37.573 ;
     RECT  32.448 34.597 32.472 37.573 ;
     RECT  42.624 35.411 42.648 37.573 ;
     RECT  47.424 34.501 47.448 37.573 ;
     RECT  69.984 36.997 70.008 37.573 ;
     RECT  6.864 36.997 8.112 37.619 ;
     RECT  88.8 37.091 89.208 37.619 ;
     RECT  103.296 37.379 103.656 37.667 ;
     RECT  37.104 37.045 37.512 37.859 ;
     RECT  78 36.037 78.456 38.051 ;
     RECT  72.48 37.091 72.912 38.147 ;
     RECT  80.448 36.421 82.104 38.147 ;
     RECT  69.984 37.573 70.92 38.149 ;
     RECT  69.984 38.149 71.304 38.195 ;
     RECT  34.8 35.363 35.112 38.197 ;
     RECT  54.288 35.555 54.312 38.197 ;
     RECT  55.536 35.843 56.904 38.197 ;
     RECT  7.392 37.619 8.112 38.243 ;
     RECT  26.784 36.421 26.808 38.243 ;
     RECT  54.288 38.197 56.904 38.243 ;
     RECT  93.504 36.469 94.512 38.243 ;
     RECT  108.144 36.997 108.168 38.243 ;
     RECT  32.448 37.573 33.288 38.387 ;
     RECT  63.552 35.939 63.576 38.387 ;
     RECT  55.008 38.243 56.904 38.483 ;
     RECT  113.664 36.421 113.688 38.675 ;
     RECT  41.856 37.573 42.648 38.677 ;
     RECT  44.64 34.933 46.056 38.677 ;
     RECT  47.28 37.573 47.448 38.677 ;
     RECT  71.28 38.195 71.304 38.677 ;
     RECT  103.536 37.667 103.656 38.677 ;
     RECT  41.856 38.677 43.32 38.723 ;
     RECT  44.64 38.677 47.448 38.723 ;
     RECT  67.2 29.605 67.992 38.723 ;
     RECT  22.464 33.973 22.488 38.725 ;
     RECT  24 34.019 24.312 38.725 ;
     RECT  28.56 36.853 29.928 38.725 ;
     RECT  50.88 36.899 51.312 38.725 ;
     RECT  2.4 37.045 2.808 38.819 ;
     RECT  4.176 38.149 4.2 38.819 ;
     RECT  22.464 38.725 24.312 38.819 ;
     RECT  42.624 38.723 43.32 38.819 ;
     RECT  114.816 33.493 116.112 38.819 ;
     RECT  27.984 38.725 29.928 38.867 ;
     RECT  85.968 37.091 86.664 38.963 ;
     RECT  5.424 37.043 5.448 39.011 ;
     RECT  7.8 38.243 8.112 39.061 ;
     RECT  72.6 38.147 72.912 39.157 ;
     RECT  61.8 35.363 62.112 39.205 ;
     RECT  48.864 37.091 48.888 39.253 ;
     RECT  72.6 39.157 73.56 39.299 ;
     RECT  28.56 38.867 29.928 39.301 ;
     RECT  37.104 37.859 37.128 39.301 ;
     RECT  71.28 38.677 71.544 39.395 ;
     RECT  80.448 38.147 81.192 39.395 ;
     RECT  10.8 33.541 11.256 39.443 ;
     RECT  86.64 38.963 86.664 39.443 ;
     RECT  11.232 39.443 11.256 39.539 ;
     RECT  55.824 38.483 56.904 39.539 ;
     RECT  80.448 39.395 80.472 39.539 ;
     RECT  99.408 35.411 99.912 39.539 ;
     RECT  72.6 39.299 72.912 39.541 ;
     RECT  23.328 38.819 24.312 39.587 ;
     RECT  74.736 39.301 74.76 39.587 ;
     RECT  37.104 39.301 37.224 39.589 ;
     RECT  97.536 38.533 97.56 39.635 ;
     RECT  34.8 38.197 35.208 39.731 ;
     RECT  37.104 39.589 37.464 39.731 ;
     RECT  83.232 36.035 83.712 39.733 ;
     RECT  88.8 37.619 89.112 39.733 ;
     RECT  103.152 38.677 103.656 39.733 ;
     RECT  37.104 39.731 37.224 39.779 ;
     RECT  94.2 38.243 94.512 39.781 ;
     RECT  7.8 39.061 8.616 39.827 ;
     RECT  32.448 38.387 32.472 39.875 ;
     RECT  109.392 38.677 109.416 39.877 ;
     RECT  110.4 36.851 110.712 39.877 ;
     RECT  28.56 39.301 30.312 39.923 ;
     RECT  109.392 39.877 110.712 39.923 ;
     RECT  61.008 39.205 62.112 40.019 ;
     RECT  103.056 39.733 103.656 40.069 ;
     RECT  106.608 39.301 106.632 40.117 ;
     RECT  75.936 37.573 75.96 40.213 ;
     RECT  44.64 38.723 46.728 40.261 ;
     RECT  69.984 38.195 70.008 40.261 ;
     RECT  13.2 37.573 14.232 40.309 ;
     RECT  15.408 39.301 15.432 40.309 ;
     RECT  69.984 40.261 70.056 40.309 ;
     RECT  103.056 40.069 103.848 40.309 ;
     RECT  104.88 37.043 105.312 40.309 ;
     RECT  69.984 40.309 70.92 40.357 ;
     RECT  72.048 39.541 72.912 40.357 ;
     RECT  69.984 40.357 72.912 40.405 ;
     RECT  106.608 40.117 107.112 40.405 ;
     RECT  29.4 39.923 30.312 40.451 ;
     RECT  37.2 39.779 37.224 40.451 ;
     RECT  103.056 40.309 105.312 40.453 ;
     RECT  106.608 40.405 107.304 40.453 ;
     RECT  13.2 40.309 15.432 40.499 ;
     RECT  43.296 38.819 43.32 40.499 ;
     RECT  56.4 39.539 56.904 40.499 ;
     RECT  44.64 40.261 47.016 40.501 ;
     RECT  48.384 39.253 48.888 40.501 ;
     RECT  69.648 40.405 72.912 40.501 ;
     RECT  95.808 38.677 95.832 40.547 ;
     RECT  13.2 40.499 15.336 40.549 ;
     RECT  20.304 39.253 20.328 40.549 ;
     RECT  50.448 38.725 51.312 40.549 ;
     RECT  106.416 40.453 107.304 40.549 ;
     RECT  7.8 39.827 8.232 40.595 ;
     RECT  75.12 40.213 75.96 40.595 ;
     RECT  82.656 39.733 83.712 40.595 ;
     RECT  113.328 39.397 113.352 40.595 ;
     RECT  44.64 40.501 48.888 40.645 ;
     RECT  49.872 40.549 51.312 40.645 ;
     RECT  75.12 40.595 75.624 40.693 ;
     RECT  12.72 40.549 15.336 40.739 ;
     RECT  66.048 39.829 66.072 40.739 ;
     RECT  87.84 39.733 89.112 40.739 ;
     RECT  109.584 39.923 110.712 40.787 ;
     RECT  18.6 37.091 19.224 40.789 ;
     RECT  20.304 40.549 21 40.789 ;
     RECT  44.64 40.645 51.312 40.789 ;
     RECT  74.64 40.693 75.624 40.789 ;
     RECT  106.416 40.549 107.496 40.789 ;
     RECT  92.16 39.013 92.184 40.835 ;
     RECT  93.648 39.781 94.512 40.835 ;
     RECT  69.648 40.501 73.32 40.837 ;
     RECT  74.544 40.789 75.624 40.837 ;
     RECT  106.416 40.789 107.592 40.837 ;
     RECT  18.6 40.789 21 40.981 ;
     RECT  102.384 40.453 105.312 40.981 ;
     RECT  106.416 40.837 107.688 40.981 ;
     RECT  2.4 38.819 2.712 41.049 ;
     RECT  7.8 40.595 8.112 41.049 ;
     RECT  24 39.587 24.312 41.049 ;
     RECT  29.4 40.451 29.712 41.049 ;
     RECT  34.8 39.731 35.112 41.049 ;
     RECT  40.2 37.091 40.512 41.049 ;
     RECT  44.304 40.789 51.312 41.049 ;
     RECT  56.4 40.499 56.712 41.049 ;
     RECT  61.8 40.019 62.112 41.049 ;
     RECT  67.2 38.723 67.512 41.049 ;
     RECT  78 38.051 78.312 41.049 ;
     RECT  83.4 40.595 83.712 41.049 ;
     RECT  88.8 40.739 89.112 41.049 ;
     RECT  94.2 40.835 94.512 41.049 ;
     RECT  99.6 39.539 99.912 41.049 ;
     RECT  110.4 40.787 110.712 41.049 ;
     RECT  115.8 38.819 116.112 41.049 ;
     RECT  2.4 41.049 2.52 41.063 ;
     RECT  7.8 41.049 7.92 41.063 ;
     RECT  24 41.049 24.12 41.063 ;
     RECT  29.4 41.049 29.52 41.063 ;
     RECT  34.8 41.049 34.92 41.063 ;
     RECT  40.2 41.049 40.32 41.063 ;
     RECT  44.304 41.049 51.12 41.063 ;
     RECT  56.4 41.049 56.52 41.063 ;
     RECT  61.8 41.049 61.92 41.063 ;
     RECT  67.2 41.049 67.32 41.063 ;
     RECT  78 41.049 78.12 41.063 ;
     RECT  83.4 41.049 83.52 41.063 ;
     RECT  88.8 41.049 88.92 41.063 ;
     RECT  94.2 41.049 94.32 41.063 ;
     RECT  99.6 41.049 99.72 41.063 ;
     RECT  110.4 41.049 110.52 41.063 ;
     RECT  115.8 41.049 115.92 41.063 ;
     RECT  44.304 41.063 50.28 41.557 ;
     RECT  69.648 40.837 75.624 41.557 ;
     RECT  12.72 40.739 14.952 42.133 ;
     RECT  18.288 40.981 21.096 42.133 ;
     RECT  102.384 40.981 107.688 42.133 ;
     RECT  12.24 42.133 14.952 42.181 ;
     RECT  18.192 42.133 21.096 42.181 ;
     RECT  102.384 42.133 107.88 42.181 ;
     RECT  12.048 42.181 14.952 43.045 ;
     RECT  11.952 43.045 14.952 43.152 ;
     RECT  18.096 42.181 21.096 43.152 ;
     RECT  44.208 41.557 50.28 43.152 ;
     RECT  69.552 41.557 75.624 43.152 ;
     RECT  101.808 42.181 107.88 43.152 ;
  END
END ot_qfd_vm_xfifo8_t
END LIBRARY
